VERSION 5.8 ;
BUSBITCHARS "[]" ;
DIVIDERCHAR "/" ;
UNITS
    DATABASE MICRONS 1000 ;
END UNITS

VIA ino_system_via1_2_1000_440_1_2_410_410
  VIARULE via1Array ;
  CUTSIZE 0.19 0.19 ;
  LAYERS Metal1 Via1 Metal2 ;
  CUTSPACING 0.22 0.22 ;
  ENCLOSURE 0.05 0.125 0.005 0.05 ;
  ROWCOL 1 2 ;
END ino_system_via1_2_1000_440_1_2_410_410

VIA ino_system_via2_3_1000_440_1_2_410_410
  VIARULE via2Array ;
  CUTSIZE 0.19 0.19 ;
  LAYERS Metal2 Via2 Metal3 ;
  CUTSPACING 0.22 0.22 ;
  ENCLOSURE 0.005 0.05 0.05 0.005 ;
  ROWCOL 1 2 ;
END ino_system_via2_3_1000_440_1_2_410_410

VIA ino_system_via3_4_1000_440_1_2_410_410
  VIARULE via3Array ;
  CUTSIZE 0.19 0.19 ;
  LAYERS Metal3 Via3 Metal4 ;
  CUTSPACING 0.22 0.22 ;
  ENCLOSURE 0.05 0.005 0.2 0.05 ;
  ROWCOL 1 2 ;
END ino_system_via3_4_1000_440_1_2_410_410

VIA ino_system_via4_5_1000_2000_1_1_840_840
  VIARULE viaTop1Array ;
  CUTSIZE 0.42 0.42 ;
  LAYERS Metal4 TopVia1 TopMetal1 ;
  CUTSPACING 0.42 0.42 ;
  ENCLOSURE 0.29 0.1 0.42 0.79 ;
END ino_system_via4_5_1000_2000_1_1_840_840

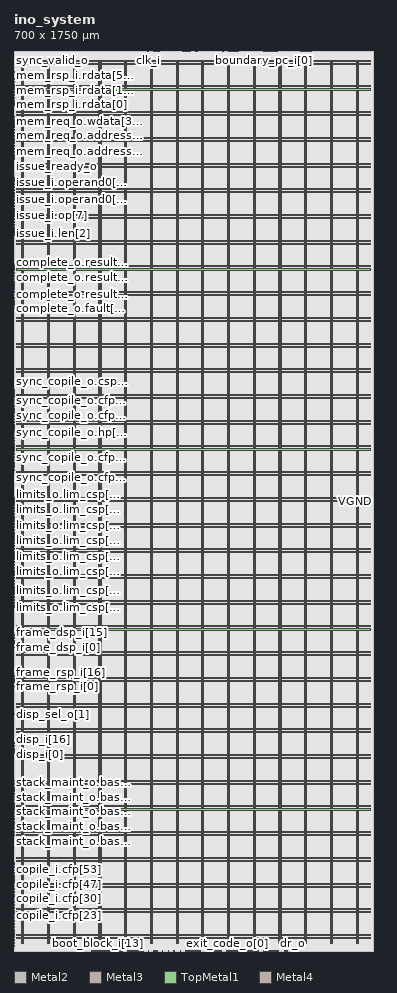
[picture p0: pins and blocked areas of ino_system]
MACRO ino_system
  FOREIGN ino_system 0 0 ;
  CLASS BLOCK ;
  SIZE 700 BY 1750 ;
  PIN boot_block_i[0]
    DIRECTION INPUT ;
    USE SIGNAL ;
    PORT
      LAYER Metal2 ;
        RECT  150.04 0 150.44 0.4 ;
    END
  END boot_block_i[0]
  PIN boot_block_i[10]
    DIRECTION INPUT ;
    USE SIGNAL ;
    PORT
      LAYER Metal2 ;
        RECT  159.64 0 160.04 0.4 ;
    END
  END boot_block_i[10]
  PIN boot_block_i[11]
    DIRECTION INPUT ;
    USE SIGNAL ;
    PORT
      LAYER Metal2 ;
        RECT  160.6 0 161 0.4 ;
    END
  END boot_block_i[11]
  PIN boot_block_i[12]
    DIRECTION INPUT ;
    USE SIGNAL ;
    PORT
      LAYER Metal2 ;
        RECT  161.56 0 161.96 0.4 ;
    END
  END boot_block_i[12]
  PIN boot_block_i[13]
    DIRECTION INPUT ;
    USE SIGNAL ;
    PORT
      LAYER Metal2 ;
        RECT  162.52 0 162.92 0.4 ;
    END
  END boot_block_i[13]
  PIN boot_block_i[14]
    DIRECTION INPUT ;
    USE SIGNAL ;
    PORT
      LAYER Metal2 ;
        RECT  163.48 0 163.88 0.4 ;
    END
  END boot_block_i[14]
  PIN boot_block_i[15]
    DIRECTION INPUT ;
    USE SIGNAL ;
    PORT
      LAYER Metal2 ;
        RECT  164.44 0 164.84 0.4 ;
    END
  END boot_block_i[15]
  PIN boot_block_i[16]
    DIRECTION INPUT ;
    USE SIGNAL ;
    PORT
      LAYER Metal2 ;
        RECT  165.4 0 165.8 0.4 ;
    END
  END boot_block_i[16]
  PIN boot_block_i[17]
    DIRECTION INPUT ;
    USE SIGNAL ;
    PORT
      LAYER Metal2 ;
        RECT  166.36 0 166.76 0.4 ;
    END
  END boot_block_i[17]
  PIN boot_block_i[18]
    DIRECTION INPUT ;
    USE SIGNAL ;
    PORT
      LAYER Metal2 ;
        RECT  167.32 0 167.72 0.4 ;
    END
  END boot_block_i[18]
  PIN boot_block_i[19]
    DIRECTION INPUT ;
    USE SIGNAL ;
    PORT
      LAYER Metal2 ;
        RECT  168.28 0 168.68 0.4 ;
    END
  END boot_block_i[19]
  PIN boot_block_i[1]
    DIRECTION INPUT ;
    USE SIGNAL ;
    PORT
      LAYER Metal2 ;
        RECT  151 0 151.4 0.4 ;
    END
  END boot_block_i[1]
  PIN boot_block_i[20]
    DIRECTION INPUT ;
    USE SIGNAL ;
    PORT
      LAYER Metal2 ;
        RECT  169.24 0 169.64 0.4 ;
    END
  END boot_block_i[20]
  PIN boot_block_i[21]
    DIRECTION INPUT ;
    USE SIGNAL ;
    PORT
      LAYER Metal2 ;
        RECT  170.2 0 170.6 0.4 ;
    END
  END boot_block_i[21]
  PIN boot_block_i[22]
    DIRECTION INPUT ;
    USE SIGNAL ;
    PORT
      LAYER Metal2 ;
        RECT  171.16 0 171.56 0.4 ;
    END
  END boot_block_i[22]
  PIN boot_block_i[23]
    DIRECTION INPUT ;
    USE SIGNAL ;
    PORT
      LAYER Metal2 ;
        RECT  172.12 0 172.52 0.4 ;
    END
  END boot_block_i[23]
  PIN boot_block_i[24]
    DIRECTION INPUT ;
    USE SIGNAL ;
    PORT
      LAYER Metal2 ;
        RECT  173.08 0 173.48 0.4 ;
    END
  END boot_block_i[24]
  PIN boot_block_i[25]
    DIRECTION INPUT ;
    USE SIGNAL ;
    PORT
      LAYER Metal2 ;
        RECT  174.04 0 174.44 0.4 ;
    END
  END boot_block_i[25]
  PIN boot_block_i[26]
    DIRECTION INPUT ;
    USE SIGNAL ;
    PORT
      LAYER Metal2 ;
        RECT  175 0 175.4 0.4 ;
    END
  END boot_block_i[26]
  PIN boot_block_i[27]
    DIRECTION INPUT ;
    USE SIGNAL ;
    PORT
      LAYER Metal2 ;
        RECT  175.96 0 176.36 0.4 ;
    END
  END boot_block_i[27]
  PIN boot_block_i[28]
    DIRECTION INPUT ;
    USE SIGNAL ;
    PORT
      LAYER Metal2 ;
        RECT  176.92 0 177.32 0.4 ;
    END
  END boot_block_i[28]
  PIN boot_block_i[29]
    DIRECTION INPUT ;
    USE SIGNAL ;
    PORT
      LAYER Metal2 ;
        RECT  177.88 0 178.28 0.4 ;
    END
  END boot_block_i[29]
  PIN boot_block_i[2]
    DIRECTION INPUT ;
    USE SIGNAL ;
    PORT
      LAYER Metal2 ;
        RECT  151.96 0 152.36 0.4 ;
    END
  END boot_block_i[2]
  PIN boot_block_i[30]
    DIRECTION INPUT ;
    USE SIGNAL ;
    PORT
      LAYER Metal2 ;
        RECT  178.84 0 179.24 0.4 ;
    END
  END boot_block_i[30]
  PIN boot_block_i[31]
    DIRECTION INPUT ;
    USE SIGNAL ;
    PORT
      LAYER Metal2 ;
        RECT  179.8 0 180.2 0.4 ;
    END
  END boot_block_i[31]
  PIN boot_block_i[32]
    DIRECTION INPUT ;
    USE SIGNAL ;
    PORT
      LAYER Metal2 ;
        RECT  180.76 0 181.16 0.4 ;
    END
  END boot_block_i[32]
  PIN boot_block_i[33]
    DIRECTION INPUT ;
    USE SIGNAL ;
    PORT
      LAYER Metal2 ;
        RECT  181.72 0 182.12 0.4 ;
    END
  END boot_block_i[33]
  PIN boot_block_i[34]
    DIRECTION INPUT ;
    USE SIGNAL ;
    PORT
      LAYER Metal2 ;
        RECT  182.68 0 183.08 0.4 ;
    END
  END boot_block_i[34]
  PIN boot_block_i[35]
    DIRECTION INPUT ;
    USE SIGNAL ;
    PORT
      LAYER Metal2 ;
        RECT  183.64 0 184.04 0.4 ;
    END
  END boot_block_i[35]
  PIN boot_block_i[36]
    DIRECTION INPUT ;
    USE SIGNAL ;
    PORT
      LAYER Metal2 ;
        RECT  184.6 0 185 0.4 ;
    END
  END boot_block_i[36]
  PIN boot_block_i[37]
    DIRECTION INPUT ;
    USE SIGNAL ;
    PORT
      LAYER Metal2 ;
        RECT  185.56 0 185.96 0.4 ;
    END
  END boot_block_i[37]
  PIN boot_block_i[38]
    DIRECTION INPUT ;
    USE SIGNAL ;
    PORT
      LAYER Metal2 ;
        RECT  186.52 0 186.92 0.4 ;
    END
  END boot_block_i[38]
  PIN boot_block_i[39]
    DIRECTION INPUT ;
    USE SIGNAL ;
    PORT
      LAYER Metal2 ;
        RECT  187.48 0 187.88 0.4 ;
    END
  END boot_block_i[39]
  PIN boot_block_i[3]
    DIRECTION INPUT ;
    USE SIGNAL ;
    PORT
      LAYER Metal2 ;
        RECT  152.92 0 153.32 0.4 ;
    END
  END boot_block_i[3]
  PIN boot_block_i[40]
    DIRECTION INPUT ;
    USE SIGNAL ;
    PORT
      LAYER Metal2 ;
        RECT  188.44 0 188.84 0.4 ;
    END
  END boot_block_i[40]
  PIN boot_block_i[41]
    DIRECTION INPUT ;
    USE SIGNAL ;
    PORT
      LAYER Metal2 ;
        RECT  189.4 0 189.8 0.4 ;
    END
  END boot_block_i[41]
  PIN boot_block_i[42]
    DIRECTION INPUT ;
    USE SIGNAL ;
    PORT
      LAYER Metal2 ;
        RECT  190.36 0 190.76 0.4 ;
    END
  END boot_block_i[42]
  PIN boot_block_i[43]
    DIRECTION INPUT ;
    USE SIGNAL ;
    PORT
      LAYER Metal2 ;
        RECT  191.32 0 191.72 0.4 ;
    END
  END boot_block_i[43]
  PIN boot_block_i[44]
    DIRECTION INPUT ;
    USE SIGNAL ;
    PORT
      LAYER Metal2 ;
        RECT  192.28 0 192.68 0.4 ;
    END
  END boot_block_i[44]
  PIN boot_block_i[45]
    DIRECTION INPUT ;
    USE SIGNAL ;
    PORT
      LAYER Metal2 ;
        RECT  193.24 0 193.64 0.4 ;
    END
  END boot_block_i[45]
  PIN boot_block_i[46]
    DIRECTION INPUT ;
    USE SIGNAL ;
    PORT
      LAYER Metal2 ;
        RECT  194.2 0 194.6 0.4 ;
    END
  END boot_block_i[46]
  PIN boot_block_i[47]
    DIRECTION INPUT ;
    USE SIGNAL ;
    PORT
      LAYER Metal2 ;
        RECT  195.16 0 195.56 0.4 ;
    END
  END boot_block_i[47]
  PIN boot_block_i[48]
    DIRECTION INPUT ;
    USE SIGNAL ;
    PORT
      LAYER Metal2 ;
        RECT  196.12 0 196.52 0.4 ;
    END
  END boot_block_i[48]
  PIN boot_block_i[49]
    DIRECTION INPUT ;
    USE SIGNAL ;
    PORT
      LAYER Metal2 ;
        RECT  197.08 0 197.48 0.4 ;
    END
  END boot_block_i[49]
  PIN boot_block_i[4]
    DIRECTION INPUT ;
    USE SIGNAL ;
    PORT
      LAYER Metal2 ;
        RECT  153.88 0 154.28 0.4 ;
    END
  END boot_block_i[4]
  PIN boot_block_i[50]
    DIRECTION INPUT ;
    USE SIGNAL ;
    PORT
      LAYER Metal2 ;
        RECT  198.04 0 198.44 0.4 ;
    END
  END boot_block_i[50]
  PIN boot_block_i[51]
    DIRECTION INPUT ;
    USE SIGNAL ;
    PORT
      LAYER Metal2 ;
        RECT  199 0 199.4 0.4 ;
    END
  END boot_block_i[51]
  PIN boot_block_i[52]
    DIRECTION INPUT ;
    USE SIGNAL ;
    PORT
      LAYER Metal2 ;
        RECT  199.96 0 200.36 0.4 ;
    END
  END boot_block_i[52]
  PIN boot_block_i[53]
    DIRECTION INPUT ;
    USE SIGNAL ;
    PORT
      LAYER Metal2 ;
        RECT  200.92 0 201.32 0.4 ;
    END
  END boot_block_i[53]
  PIN boot_block_i[54]
    DIRECTION INPUT ;
    USE SIGNAL ;
    PORT
      LAYER Metal2 ;
        RECT  201.88 0 202.28 0.4 ;
    END
  END boot_block_i[54]
  PIN boot_block_i[55]
    DIRECTION INPUT ;
    USE SIGNAL ;
    PORT
      LAYER Metal2 ;
        RECT  202.84 0 203.24 0.4 ;
    END
  END boot_block_i[55]
  PIN boot_block_i[56]
    DIRECTION INPUT ;
    USE SIGNAL ;
    PORT
      LAYER Metal2 ;
        RECT  203.8 0 204.2 0.4 ;
    END
  END boot_block_i[56]
  PIN boot_block_i[57]
    DIRECTION INPUT ;
    USE SIGNAL ;
    PORT
      LAYER Metal2 ;
        RECT  204.76 0 205.16 0.4 ;
    END
  END boot_block_i[57]
  PIN boot_block_i[58]
    DIRECTION INPUT ;
    USE SIGNAL ;
    PORT
      LAYER Metal2 ;
        RECT  205.72 0 206.12 0.4 ;
    END
  END boot_block_i[58]
  PIN boot_block_i[59]
    DIRECTION INPUT ;
    USE SIGNAL ;
    PORT
      LAYER Metal2 ;
        RECT  206.68 0 207.08 0.4 ;
    END
  END boot_block_i[59]
  PIN boot_block_i[5]
    DIRECTION INPUT ;
    USE SIGNAL ;
    PORT
      LAYER Metal2 ;
        RECT  154.84 0 155.24 0.4 ;
    END
  END boot_block_i[5]
  PIN boot_block_i[60]
    DIRECTION INPUT ;
    USE SIGNAL ;
    PORT
      LAYER Metal2 ;
        RECT  207.64 0 208.04 0.4 ;
    END
  END boot_block_i[60]
  PIN boot_block_i[61]
    DIRECTION INPUT ;
    USE SIGNAL ;
    PORT
      LAYER Metal2 ;
        RECT  208.6 0 209 0.4 ;
    END
  END boot_block_i[61]
  PIN boot_block_i[62]
    DIRECTION INPUT ;
    USE SIGNAL ;
    PORT
      LAYER Metal2 ;
        RECT  209.56 0 209.96 0.4 ;
    END
  END boot_block_i[62]
  PIN boot_block_i[63]
    DIRECTION INPUT ;
    USE SIGNAL ;
    PORT
      LAYER Metal2 ;
        RECT  210.52 0 210.92 0.4 ;
    END
  END boot_block_i[63]
  PIN boot_block_i[6]
    DIRECTION INPUT ;
    USE SIGNAL ;
    PORT
      LAYER Metal2 ;
        RECT  155.8 0 156.2 0.4 ;
    END
  END boot_block_i[6]
  PIN boot_block_i[7]
    DIRECTION INPUT ;
    USE SIGNAL ;
    PORT
      LAYER Metal2 ;
        RECT  156.76 0 157.16 0.4 ;
    END
  END boot_block_i[7]
  PIN boot_block_i[8]
    DIRECTION INPUT ;
    USE SIGNAL ;
    PORT
      LAYER Metal2 ;
        RECT  157.72 0 158.12 0.4 ;
    END
  END boot_block_i[8]
  PIN boot_block_i[9]
    DIRECTION INPUT ;
    USE SIGNAL ;
    PORT
      LAYER Metal2 ;
        RECT  158.68 0 159.08 0.4 ;
    END
  END boot_block_i[9]
  PIN boundary_pc_i[0]
    DIRECTION INPUT ;
    USE SIGNAL ;
    PORT
      LAYER Metal2 ;
        RECT  486.04 1749.6 486.44 1750 ;
    END
  END boundary_pc_i[0]
  PIN boundary_pc_i[10]
    DIRECTION INPUT ;
    USE SIGNAL ;
    PORT
      LAYER Metal2 ;
        RECT  495.64 1749.6 496.04 1750 ;
    END
  END boundary_pc_i[10]
  PIN boundary_pc_i[11]
    DIRECTION INPUT ;
    USE SIGNAL ;
    PORT
      LAYER Metal2 ;
        RECT  496.6 1749.6 497 1750 ;
    END
  END boundary_pc_i[11]
  PIN boundary_pc_i[12]
    DIRECTION INPUT ;
    USE SIGNAL ;
    PORT
      LAYER Metal2 ;
        RECT  497.56 1749.6 497.96 1750 ;
    END
  END boundary_pc_i[12]
  PIN boundary_pc_i[13]
    DIRECTION INPUT ;
    USE SIGNAL ;
    PORT
      LAYER Metal2 ;
        RECT  498.52 1749.6 498.92 1750 ;
    END
  END boundary_pc_i[13]
  PIN boundary_pc_i[14]
    DIRECTION INPUT ;
    USE SIGNAL ;
    PORT
      LAYER Metal2 ;
        RECT  499.48 1749.6 499.88 1750 ;
    END
  END boundary_pc_i[14]
  PIN boundary_pc_i[15]
    DIRECTION INPUT ;
    USE SIGNAL ;
    PORT
      LAYER Metal2 ;
        RECT  500.44 1749.6 500.84 1750 ;
    END
  END boundary_pc_i[15]
  PIN boundary_pc_i[16]
    DIRECTION INPUT ;
    USE SIGNAL ;
    PORT
      LAYER Metal2 ;
        RECT  501.4 1749.6 501.8 1750 ;
    END
  END boundary_pc_i[16]
  PIN boundary_pc_i[17]
    DIRECTION INPUT ;
    USE SIGNAL ;
    PORT
      LAYER Metal2 ;
        RECT  502.36 1749.6 502.76 1750 ;
    END
  END boundary_pc_i[17]
  PIN boundary_pc_i[18]
    DIRECTION INPUT ;
    USE SIGNAL ;
    PORT
      LAYER Metal2 ;
        RECT  503.32 1749.6 503.72 1750 ;
    END
  END boundary_pc_i[18]
  PIN boundary_pc_i[19]
    DIRECTION INPUT ;
    USE SIGNAL ;
    PORT
      LAYER Metal2 ;
        RECT  504.28 1749.6 504.68 1750 ;
    END
  END boundary_pc_i[19]
  PIN boundary_pc_i[1]
    DIRECTION INPUT ;
    USE SIGNAL ;
    PORT
      LAYER Metal2 ;
        RECT  487 1749.6 487.4 1750 ;
    END
  END boundary_pc_i[1]
  PIN boundary_pc_i[20]
    DIRECTION INPUT ;
    USE SIGNAL ;
    PORT
      LAYER Metal2 ;
        RECT  505.24 1749.6 505.64 1750 ;
    END
  END boundary_pc_i[20]
  PIN boundary_pc_i[21]
    DIRECTION INPUT ;
    USE SIGNAL ;
    PORT
      LAYER Metal2 ;
        RECT  506.2 1749.6 506.6 1750 ;
    END
  END boundary_pc_i[21]
  PIN boundary_pc_i[22]
    DIRECTION INPUT ;
    USE SIGNAL ;
    PORT
      LAYER Metal2 ;
        RECT  507.16 1749.6 507.56 1750 ;
    END
  END boundary_pc_i[22]
  PIN boundary_pc_i[23]
    DIRECTION INPUT ;
    USE SIGNAL ;
    PORT
      LAYER Metal2 ;
        RECT  508.12 1749.6 508.52 1750 ;
    END
  END boundary_pc_i[23]
  PIN boundary_pc_i[24]
    DIRECTION INPUT ;
    USE SIGNAL ;
    PORT
      LAYER Metal2 ;
        RECT  509.08 1749.6 509.48 1750 ;
    END
  END boundary_pc_i[24]
  PIN boundary_pc_i[25]
    DIRECTION INPUT ;
    USE SIGNAL ;
    PORT
      LAYER Metal2 ;
        RECT  510.04 1749.6 510.44 1750 ;
    END
  END boundary_pc_i[25]
  PIN boundary_pc_i[26]
    DIRECTION INPUT ;
    USE SIGNAL ;
    PORT
      LAYER Metal2 ;
        RECT  511 1749.6 511.4 1750 ;
    END
  END boundary_pc_i[26]
  PIN boundary_pc_i[27]
    DIRECTION INPUT ;
    USE SIGNAL ;
    PORT
      LAYER Metal2 ;
        RECT  511.96 1749.6 512.36 1750 ;
    END
  END boundary_pc_i[27]
  PIN boundary_pc_i[28]
    DIRECTION INPUT ;
    USE SIGNAL ;
    PORT
      LAYER Metal2 ;
        RECT  512.92 1749.6 513.32 1750 ;
    END
  END boundary_pc_i[28]
  PIN boundary_pc_i[29]
    DIRECTION INPUT ;
    USE SIGNAL ;
    PORT
      LAYER Metal2 ;
        RECT  513.88 1749.6 514.28 1750 ;
    END
  END boundary_pc_i[29]
  PIN boundary_pc_i[2]
    DIRECTION INPUT ;
    USE SIGNAL ;
    PORT
      LAYER Metal2 ;
        RECT  487.96 1749.6 488.36 1750 ;
    END
  END boundary_pc_i[2]
  PIN boundary_pc_i[30]
    DIRECTION INPUT ;
    USE SIGNAL ;
    PORT
      LAYER Metal2 ;
        RECT  514.84 1749.6 515.24 1750 ;
    END
  END boundary_pc_i[30]
  PIN boundary_pc_i[31]
    DIRECTION INPUT ;
    USE SIGNAL ;
    PORT
      LAYER Metal2 ;
        RECT  515.8 1749.6 516.2 1750 ;
    END
  END boundary_pc_i[31]
  PIN boundary_pc_i[3]
    DIRECTION INPUT ;
    USE SIGNAL ;
    PORT
      LAYER Metal2 ;
        RECT  488.92 1749.6 489.32 1750 ;
    END
  END boundary_pc_i[3]
  PIN boundary_pc_i[4]
    DIRECTION INPUT ;
    USE SIGNAL ;
    PORT
      LAYER Metal2 ;
        RECT  489.88 1749.6 490.28 1750 ;
    END
  END boundary_pc_i[4]
  PIN boundary_pc_i[5]
    DIRECTION INPUT ;
    USE SIGNAL ;
    PORT
      LAYER Metal2 ;
        RECT  490.84 1749.6 491.24 1750 ;
    END
  END boundary_pc_i[5]
  PIN boundary_pc_i[6]
    DIRECTION INPUT ;
    USE SIGNAL ;
    PORT
      LAYER Metal2 ;
        RECT  491.8 1749.6 492.2 1750 ;
    END
  END boundary_pc_i[6]
  PIN boundary_pc_i[7]
    DIRECTION INPUT ;
    USE SIGNAL ;
    PORT
      LAYER Metal2 ;
        RECT  492.76 1749.6 493.16 1750 ;
    END
  END boundary_pc_i[7]
  PIN boundary_pc_i[8]
    DIRECTION INPUT ;
    USE SIGNAL ;
    PORT
      LAYER Metal2 ;
        RECT  493.72 1749.6 494.12 1750 ;
    END
  END boundary_pc_i[8]
  PIN boundary_pc_i[9]
    DIRECTION INPUT ;
    USE SIGNAL ;
    PORT
      LAYER Metal2 ;
        RECT  494.68 1749.6 495.08 1750 ;
    END
  END boundary_pc_i[9]
  PIN boundary_valid_i
    DIRECTION INPUT ;
    USE SIGNAL ;
    PORT
      LAYER Metal2 ;
        RECT  475.48 1749.6 475.88 1750 ;
    END
  END boundary_valid_i
  PIN clk_i
    DIRECTION INPUT ;
    USE SIGNAL ;
    PORT
      LAYER Metal2 ;
        RECT  260.44 1749.6 260.84 1750 ;
    END
  END clk_i
  PIN complete_o.fault[0]
    DIRECTION OUTPUT ;
    USE SIGNAL ;
    PORT
      LAYER Metal3 ;
        RECT  0 1248.46 0.4 1248.86 ;
    END
  END complete_o.fault[0]
  PIN complete_o.fault[1]
    DIRECTION OUTPUT ;
    USE SIGNAL ;
    PORT
      LAYER Metal3 ;
        RECT  0 1250.98 0.4 1251.38 ;
    END
  END complete_o.fault[1]
  PIN complete_o.fault[2]
    DIRECTION OUTPUT ;
    USE SIGNAL ;
    PORT
      LAYER Metal3 ;
        RECT  0 1253.5 0.4 1253.9 ;
    END
  END complete_o.fault[2]
  PIN complete_o.fault[3]
    DIRECTION OUTPUT ;
    USE SIGNAL ;
    PORT
      LAYER Metal3 ;
        RECT  0 1256.02 0.4 1256.42 ;
    END
  END complete_o.fault[3]
  PIN complete_o.fault[4]
    DIRECTION OUTPUT ;
    USE SIGNAL ;
    PORT
      LAYER Metal3 ;
        RECT  0 1258.54 0.4 1258.94 ;
    END
  END complete_o.fault[4]
  PIN complete_o.fault[5]
    DIRECTION OUTPUT ;
    USE SIGNAL ;
    PORT
      LAYER Metal3 ;
        RECT  0 1261.06 0.4 1261.46 ;
    END
  END complete_o.fault[5]
  PIN complete_o.fault[6]
    DIRECTION OUTPUT ;
    USE SIGNAL ;
    PORT
      LAYER Metal3 ;
        RECT  0 1263.58 0.4 1263.98 ;
    END
  END complete_o.fault[6]
  PIN complete_o.fault[7]
    DIRECTION OUTPUT ;
    USE SIGNAL ;
    PORT
      LAYER Metal3 ;
        RECT  0 1266.1 0.4 1266.5 ;
    END
  END complete_o.fault[7]
  PIN complete_o.fault[8]
    DIRECTION OUTPUT ;
    USE SIGNAL ;
    PORT
      LAYER Metal3 ;
        RECT  0 1268.62 0.4 1269.02 ;
    END
  END complete_o.fault[8]
  PIN complete_o.result[0]
    DIRECTION OUTPUT ;
    USE SIGNAL ;
    PORT
      LAYER Metal3 ;
        RECT  0 1249.3 0.4 1249.7 ;
    END
  END complete_o.result[0]
  PIN complete_o.result[10]
    DIRECTION OUTPUT ;
    USE SIGNAL ;
    PORT
      LAYER Metal3 ;
        RECT  0 1272.82 0.4 1273.22 ;
    END
  END complete_o.result[10]
  PIN complete_o.result[11]
    DIRECTION OUTPUT ;
    USE SIGNAL ;
    PORT
      LAYER Metal3 ;
        RECT  0 1274.5 0.4 1274.9 ;
    END
  END complete_o.result[11]
  PIN complete_o.result[12]
    DIRECTION OUTPUT ;
    USE SIGNAL ;
    PORT
      LAYER Metal3 ;
        RECT  0 1276.18 0.4 1276.58 ;
    END
  END complete_o.result[12]
  PIN complete_o.result[13]
    DIRECTION OUTPUT ;
    USE SIGNAL ;
    PORT
      LAYER Metal3 ;
        RECT  0 1277.86 0.4 1278.26 ;
    END
  END complete_o.result[13]
  PIN complete_o.result[14]
    DIRECTION OUTPUT ;
    USE SIGNAL ;
    PORT
      LAYER Metal3 ;
        RECT  0 1279.54 0.4 1279.94 ;
    END
  END complete_o.result[14]
  PIN complete_o.result[15]
    DIRECTION OUTPUT ;
    USE SIGNAL ;
    PORT
      LAYER Metal3 ;
        RECT  0 1281.22 0.4 1281.62 ;
    END
  END complete_o.result[15]
  PIN complete_o.result[16]
    DIRECTION OUTPUT ;
    USE SIGNAL ;
    PORT
      LAYER Metal3 ;
        RECT  0 1282.9 0.4 1283.3 ;
    END
  END complete_o.result[16]
  PIN complete_o.result[17]
    DIRECTION OUTPUT ;
    USE SIGNAL ;
    PORT
      LAYER Metal3 ;
        RECT  0 1284.58 0.4 1284.98 ;
    END
  END complete_o.result[17]
  PIN complete_o.result[18]
    DIRECTION OUTPUT ;
    USE SIGNAL ;
    PORT
      LAYER Metal3 ;
        RECT  0 1286.26 0.4 1286.66 ;
    END
  END complete_o.result[18]
  PIN complete_o.result[19]
    DIRECTION OUTPUT ;
    USE SIGNAL ;
    PORT
      LAYER Metal3 ;
        RECT  0 1287.94 0.4 1288.34 ;
    END
  END complete_o.result[19]
  PIN complete_o.result[1]
    DIRECTION OUTPUT ;
    USE SIGNAL ;
    PORT
      LAYER Metal3 ;
        RECT  0 1251.82 0.4 1252.22 ;
    END
  END complete_o.result[1]
  PIN complete_o.result[20]
    DIRECTION OUTPUT ;
    USE SIGNAL ;
    PORT
      LAYER Metal3 ;
        RECT  0 1289.62 0.4 1290.02 ;
    END
  END complete_o.result[20]
  PIN complete_o.result[21]
    DIRECTION OUTPUT ;
    USE SIGNAL ;
    PORT
      LAYER Metal3 ;
        RECT  0 1291.3 0.4 1291.7 ;
    END
  END complete_o.result[21]
  PIN complete_o.result[22]
    DIRECTION OUTPUT ;
    USE SIGNAL ;
    PORT
      LAYER Metal3 ;
        RECT  0 1292.98 0.4 1293.38 ;
    END
  END complete_o.result[22]
  PIN complete_o.result[23]
    DIRECTION OUTPUT ;
    USE SIGNAL ;
    PORT
      LAYER Metal3 ;
        RECT  0 1294.66 0.4 1295.06 ;
    END
  END complete_o.result[23]
  PIN complete_o.result[24]
    DIRECTION OUTPUT ;
    USE SIGNAL ;
    PORT
      LAYER Metal3 ;
        RECT  0 1296.34 0.4 1296.74 ;
    END
  END complete_o.result[24]
  PIN complete_o.result[25]
    DIRECTION OUTPUT ;
    USE SIGNAL ;
    PORT
      LAYER Metal3 ;
        RECT  0 1298.02 0.4 1298.42 ;
    END
  END complete_o.result[25]
  PIN complete_o.result[26]
    DIRECTION OUTPUT ;
    USE SIGNAL ;
    PORT
      LAYER Metal3 ;
        RECT  0 1299.7 0.4 1300.1 ;
    END
  END complete_o.result[26]
  PIN complete_o.result[27]
    DIRECTION OUTPUT ;
    USE SIGNAL ;
    PORT
      LAYER Metal3 ;
        RECT  0 1301.38 0.4 1301.78 ;
    END
  END complete_o.result[27]
  PIN complete_o.result[28]
    DIRECTION OUTPUT ;
    USE SIGNAL ;
    PORT
      LAYER Metal3 ;
        RECT  0 1303.06 0.4 1303.46 ;
    END
  END complete_o.result[28]
  PIN complete_o.result[29]
    DIRECTION OUTPUT ;
    USE SIGNAL ;
    PORT
      LAYER Metal3 ;
        RECT  0 1304.74 0.4 1305.14 ;
    END
  END complete_o.result[29]
  PIN complete_o.result[2]
    DIRECTION OUTPUT ;
    USE SIGNAL ;
    PORT
      LAYER Metal3 ;
        RECT  0 1254.34 0.4 1254.74 ;
    END
  END complete_o.result[2]
  PIN complete_o.result[30]
    DIRECTION OUTPUT ;
    USE SIGNAL ;
    PORT
      LAYER Metal3 ;
        RECT  0 1306.42 0.4 1306.82 ;
    END
  END complete_o.result[30]
  PIN complete_o.result[31]
    DIRECTION OUTPUT ;
    USE SIGNAL ;
    PORT
      LAYER Metal3 ;
        RECT  0 1308.1 0.4 1308.5 ;
    END
  END complete_o.result[31]
  PIN complete_o.result[32]
    DIRECTION OUTPUT ;
    USE SIGNAL ;
    PORT
      LAYER Metal3 ;
        RECT  0 1309.78 0.4 1310.18 ;
    END
  END complete_o.result[32]
  PIN complete_o.result[33]
    DIRECTION OUTPUT ;
    USE SIGNAL ;
    PORT
      LAYER Metal3 ;
        RECT  0 1310.62 0.4 1311.02 ;
    END
  END complete_o.result[33]
  PIN complete_o.result[34]
    DIRECTION OUTPUT ;
    USE SIGNAL ;
    PORT
      LAYER Metal3 ;
        RECT  0 1311.46 0.4 1311.86 ;
    END
  END complete_o.result[34]
  PIN complete_o.result[35]
    DIRECTION OUTPUT ;
    USE SIGNAL ;
    PORT
      LAYER Metal3 ;
        RECT  0 1312.3 0.4 1312.7 ;
    END
  END complete_o.result[35]
  PIN complete_o.result[36]
    DIRECTION OUTPUT ;
    USE SIGNAL ;
    PORT
      LAYER Metal3 ;
        RECT  0 1313.14 0.4 1313.54 ;
    END
  END complete_o.result[36]
  PIN complete_o.result[37]
    DIRECTION OUTPUT ;
    USE SIGNAL ;
    PORT
      LAYER Metal3 ;
        RECT  0 1313.98 0.4 1314.38 ;
    END
  END complete_o.result[37]
  PIN complete_o.result[38]
    DIRECTION OUTPUT ;
    USE SIGNAL ;
    PORT
      LAYER Metal3 ;
        RECT  0 1314.82 0.4 1315.22 ;
    END
  END complete_o.result[38]
  PIN complete_o.result[39]
    DIRECTION OUTPUT ;
    USE SIGNAL ;
    PORT
      LAYER Metal3 ;
        RECT  0 1315.66 0.4 1316.06 ;
    END
  END complete_o.result[39]
  PIN complete_o.result[3]
    DIRECTION OUTPUT ;
    USE SIGNAL ;
    PORT
      LAYER Metal3 ;
        RECT  0 1256.86 0.4 1257.26 ;
    END
  END complete_o.result[3]
  PIN complete_o.result[40]
    DIRECTION OUTPUT ;
    USE SIGNAL ;
    PORT
      LAYER Metal3 ;
        RECT  0 1316.5 0.4 1316.9 ;
    END
  END complete_o.result[40]
  PIN complete_o.result[41]
    DIRECTION OUTPUT ;
    USE SIGNAL ;
    PORT
      LAYER Metal3 ;
        RECT  0 1317.34 0.4 1317.74 ;
    END
  END complete_o.result[41]
  PIN complete_o.result[42]
    DIRECTION OUTPUT ;
    USE SIGNAL ;
    PORT
      LAYER Metal3 ;
        RECT  0 1318.18 0.4 1318.58 ;
    END
  END complete_o.result[42]
  PIN complete_o.result[43]
    DIRECTION OUTPUT ;
    USE SIGNAL ;
    PORT
      LAYER Metal3 ;
        RECT  0 1319.02 0.4 1319.42 ;
    END
  END complete_o.result[43]
  PIN complete_o.result[44]
    DIRECTION OUTPUT ;
    USE SIGNAL ;
    PORT
      LAYER Metal3 ;
        RECT  0 1319.86 0.4 1320.26 ;
    END
  END complete_o.result[44]
  PIN complete_o.result[45]
    DIRECTION OUTPUT ;
    USE SIGNAL ;
    PORT
      LAYER Metal3 ;
        RECT  0 1320.7 0.4 1321.1 ;
    END
  END complete_o.result[45]
  PIN complete_o.result[46]
    DIRECTION OUTPUT ;
    USE SIGNAL ;
    PORT
      LAYER Metal3 ;
        RECT  0 1321.54 0.4 1321.94 ;
    END
  END complete_o.result[46]
  PIN complete_o.result[47]
    DIRECTION OUTPUT ;
    USE SIGNAL ;
    PORT
      LAYER Metal3 ;
        RECT  0 1322.38 0.4 1322.78 ;
    END
  END complete_o.result[47]
  PIN complete_o.result[48]
    DIRECTION OUTPUT ;
    USE SIGNAL ;
    PORT
      LAYER Metal3 ;
        RECT  0 1323.22 0.4 1323.62 ;
    END
  END complete_o.result[48]
  PIN complete_o.result[49]
    DIRECTION OUTPUT ;
    USE SIGNAL ;
    PORT
      LAYER Metal3 ;
        RECT  0 1324.06 0.4 1324.46 ;
    END
  END complete_o.result[49]
  PIN complete_o.result[4]
    DIRECTION OUTPUT ;
    USE SIGNAL ;
    PORT
      LAYER Metal3 ;
        RECT  0 1259.38 0.4 1259.78 ;
    END
  END complete_o.result[4]
  PIN complete_o.result[50]
    DIRECTION OUTPUT ;
    USE SIGNAL ;
    PORT
      LAYER Metal3 ;
        RECT  0 1324.9 0.4 1325.3 ;
    END
  END complete_o.result[50]
  PIN complete_o.result[51]
    DIRECTION OUTPUT ;
    USE SIGNAL ;
    PORT
      LAYER Metal3 ;
        RECT  0 1325.74 0.4 1326.14 ;
    END
  END complete_o.result[51]
  PIN complete_o.result[52]
    DIRECTION OUTPUT ;
    USE SIGNAL ;
    PORT
      LAYER Metal3 ;
        RECT  0 1326.58 0.4 1326.98 ;
    END
  END complete_o.result[52]
  PIN complete_o.result[53]
    DIRECTION OUTPUT ;
    USE SIGNAL ;
    PORT
      LAYER Metal3 ;
        RECT  0 1327.42 0.4 1327.82 ;
    END
  END complete_o.result[53]
  PIN complete_o.result[54]
    DIRECTION OUTPUT ;
    USE SIGNAL ;
    PORT
      LAYER Metal3 ;
        RECT  0 1328.26 0.4 1328.66 ;
    END
  END complete_o.result[54]
  PIN complete_o.result[55]
    DIRECTION OUTPUT ;
    USE SIGNAL ;
    PORT
      LAYER Metal3 ;
        RECT  0 1329.1 0.4 1329.5 ;
    END
  END complete_o.result[55]
  PIN complete_o.result[56]
    DIRECTION OUTPUT ;
    USE SIGNAL ;
    PORT
      LAYER Metal3 ;
        RECT  0 1329.94 0.4 1330.34 ;
    END
  END complete_o.result[56]
  PIN complete_o.result[57]
    DIRECTION OUTPUT ;
    USE SIGNAL ;
    PORT
      LAYER Metal3 ;
        RECT  0 1330.78 0.4 1331.18 ;
    END
  END complete_o.result[57]
  PIN complete_o.result[58]
    DIRECTION OUTPUT ;
    USE SIGNAL ;
    PORT
      LAYER Metal3 ;
        RECT  0 1331.62 0.4 1332.02 ;
    END
  END complete_o.result[58]
  PIN complete_o.result[59]
    DIRECTION OUTPUT ;
    USE SIGNAL ;
    PORT
      LAYER Metal3 ;
        RECT  0 1332.46 0.4 1332.86 ;
    END
  END complete_o.result[59]
  PIN complete_o.result[5]
    DIRECTION OUTPUT ;
    USE SIGNAL ;
    PORT
      LAYER Metal3 ;
        RECT  0 1261.9 0.4 1262.3 ;
    END
  END complete_o.result[5]
  PIN complete_o.result[60]
    DIRECTION OUTPUT ;
    USE SIGNAL ;
    PORT
      LAYER Metal3 ;
        RECT  0 1333.3 0.4 1333.7 ;
    END
  END complete_o.result[60]
  PIN complete_o.result[61]
    DIRECTION OUTPUT ;
    USE SIGNAL ;
    PORT
      LAYER Metal3 ;
        RECT  0 1334.14 0.4 1334.54 ;
    END
  END complete_o.result[61]
  PIN complete_o.result[62]
    DIRECTION OUTPUT ;
    USE SIGNAL ;
    PORT
      LAYER Metal3 ;
        RECT  0 1334.98 0.4 1335.38 ;
    END
  END complete_o.result[62]
  PIN complete_o.result[63]
    DIRECTION OUTPUT ;
    USE SIGNAL ;
    PORT
      LAYER Metal3 ;
        RECT  0 1335.82 0.4 1336.22 ;
    END
  END complete_o.result[63]
  PIN complete_o.result[6]
    DIRECTION OUTPUT ;
    USE SIGNAL ;
    PORT
      LAYER Metal3 ;
        RECT  0 1264.42 0.4 1264.82 ;
    END
  END complete_o.result[6]
  PIN complete_o.result[7]
    DIRECTION OUTPUT ;
    USE SIGNAL ;
    PORT
      LAYER Metal3 ;
        RECT  0 1266.94 0.4 1267.34 ;
    END
  END complete_o.result[7]
  PIN complete_o.result[8]
    DIRECTION OUTPUT ;
    USE SIGNAL ;
    PORT
      LAYER Metal3 ;
        RECT  0 1269.46 0.4 1269.86 ;
    END
  END complete_o.result[8]
  PIN complete_o.result[9]
    DIRECTION OUTPUT ;
    USE SIGNAL ;
    PORT
      LAYER Metal3 ;
        RECT  0 1271.14 0.4 1271.54 ;
    END
  END complete_o.result[9]
  PIN complete_o.result_valid
    DIRECTION OUTPUT ;
    USE SIGNAL ;
    PORT
      LAYER Metal3 ;
        RECT  0 1245.94 0.4 1246.34 ;
    END
  END complete_o.result_valid
  PIN complete_o.taken
    DIRECTION OUTPUT ;
    USE SIGNAL ;
    PORT
      LAYER Metal3 ;
        RECT  0 1246.78 0.4 1247.18 ;
    END
  END complete_o.taken
  PIN complete_o.target[0]
    DIRECTION OUTPUT ;
    USE SIGNAL ;
    PORT
      LAYER Metal3 ;
        RECT  0 1250.14 0.4 1250.54 ;
    END
  END complete_o.target[0]
  PIN complete_o.target[10]
    DIRECTION OUTPUT ;
    USE SIGNAL ;
    PORT
      LAYER Metal3 ;
        RECT  0 1273.66 0.4 1274.06 ;
    END
  END complete_o.target[10]
  PIN complete_o.target[11]
    DIRECTION OUTPUT ;
    USE SIGNAL ;
    PORT
      LAYER Metal3 ;
        RECT  0 1275.34 0.4 1275.74 ;
    END
  END complete_o.target[11]
  PIN complete_o.target[12]
    DIRECTION OUTPUT ;
    USE SIGNAL ;
    PORT
      LAYER Metal3 ;
        RECT  0 1277.02 0.4 1277.42 ;
    END
  END complete_o.target[12]
  PIN complete_o.target[13]
    DIRECTION OUTPUT ;
    USE SIGNAL ;
    PORT
      LAYER Metal3 ;
        RECT  0 1278.7 0.4 1279.1 ;
    END
  END complete_o.target[13]
  PIN complete_o.target[14]
    DIRECTION OUTPUT ;
    USE SIGNAL ;
    PORT
      LAYER Metal3 ;
        RECT  0 1280.38 0.4 1280.78 ;
    END
  END complete_o.target[14]
  PIN complete_o.target[15]
    DIRECTION OUTPUT ;
    USE SIGNAL ;
    PORT
      LAYER Metal3 ;
        RECT  0 1282.06 0.4 1282.46 ;
    END
  END complete_o.target[15]
  PIN complete_o.target[16]
    DIRECTION OUTPUT ;
    USE SIGNAL ;
    PORT
      LAYER Metal3 ;
        RECT  0 1283.74 0.4 1284.14 ;
    END
  END complete_o.target[16]
  PIN complete_o.target[17]
    DIRECTION OUTPUT ;
    USE SIGNAL ;
    PORT
      LAYER Metal3 ;
        RECT  0 1285.42 0.4 1285.82 ;
    END
  END complete_o.target[17]
  PIN complete_o.target[18]
    DIRECTION OUTPUT ;
    USE SIGNAL ;
    PORT
      LAYER Metal3 ;
        RECT  0 1287.1 0.4 1287.5 ;
    END
  END complete_o.target[18]
  PIN complete_o.target[19]
    DIRECTION OUTPUT ;
    USE SIGNAL ;
    PORT
      LAYER Metal3 ;
        RECT  0 1288.78 0.4 1289.18 ;
    END
  END complete_o.target[19]
  PIN complete_o.target[1]
    DIRECTION OUTPUT ;
    USE SIGNAL ;
    PORT
      LAYER Metal3 ;
        RECT  0 1252.66 0.4 1253.06 ;
    END
  END complete_o.target[1]
  PIN complete_o.target[20]
    DIRECTION OUTPUT ;
    USE SIGNAL ;
    PORT
      LAYER Metal3 ;
        RECT  0 1290.46 0.4 1290.86 ;
    END
  END complete_o.target[20]
  PIN complete_o.target[21]
    DIRECTION OUTPUT ;
    USE SIGNAL ;
    PORT
      LAYER Metal3 ;
        RECT  0 1292.14 0.4 1292.54 ;
    END
  END complete_o.target[21]
  PIN complete_o.target[22]
    DIRECTION OUTPUT ;
    USE SIGNAL ;
    PORT
      LAYER Metal3 ;
        RECT  0 1293.82 0.4 1294.22 ;
    END
  END complete_o.target[22]
  PIN complete_o.target[23]
    DIRECTION OUTPUT ;
    USE SIGNAL ;
    PORT
      LAYER Metal3 ;
        RECT  0 1295.5 0.4 1295.9 ;
    END
  END complete_o.target[23]
  PIN complete_o.target[24]
    DIRECTION OUTPUT ;
    USE SIGNAL ;
    PORT
      LAYER Metal3 ;
        RECT  0 1297.18 0.4 1297.58 ;
    END
  END complete_o.target[24]
  PIN complete_o.target[25]
    DIRECTION OUTPUT ;
    USE SIGNAL ;
    PORT
      LAYER Metal3 ;
        RECT  0 1298.86 0.4 1299.26 ;
    END
  END complete_o.target[25]
  PIN complete_o.target[26]
    DIRECTION OUTPUT ;
    USE SIGNAL ;
    PORT
      LAYER Metal3 ;
        RECT  0 1300.54 0.4 1300.94 ;
    END
  END complete_o.target[26]
  PIN complete_o.target[27]
    DIRECTION OUTPUT ;
    USE SIGNAL ;
    PORT
      LAYER Metal3 ;
        RECT  0 1302.22 0.4 1302.62 ;
    END
  END complete_o.target[27]
  PIN complete_o.target[28]
    DIRECTION OUTPUT ;
    USE SIGNAL ;
    PORT
      LAYER Metal3 ;
        RECT  0 1303.9 0.4 1304.3 ;
    END
  END complete_o.target[28]
  PIN complete_o.target[29]
    DIRECTION OUTPUT ;
    USE SIGNAL ;
    PORT
      LAYER Metal3 ;
        RECT  0 1305.58 0.4 1305.98 ;
    END
  END complete_o.target[29]
  PIN complete_o.target[2]
    DIRECTION OUTPUT ;
    USE SIGNAL ;
    PORT
      LAYER Metal3 ;
        RECT  0 1255.18 0.4 1255.58 ;
    END
  END complete_o.target[2]
  PIN complete_o.target[30]
    DIRECTION OUTPUT ;
    USE SIGNAL ;
    PORT
      LAYER Metal3 ;
        RECT  0 1307.26 0.4 1307.66 ;
    END
  END complete_o.target[30]
  PIN complete_o.target[31]
    DIRECTION OUTPUT ;
    USE SIGNAL ;
    PORT
      LAYER Metal3 ;
        RECT  0 1308.94 0.4 1309.34 ;
    END
  END complete_o.target[31]
  PIN complete_o.target[3]
    DIRECTION OUTPUT ;
    USE SIGNAL ;
    PORT
      LAYER Metal3 ;
        RECT  0 1257.7 0.4 1258.1 ;
    END
  END complete_o.target[3]
  PIN complete_o.target[4]
    DIRECTION OUTPUT ;
    USE SIGNAL ;
    PORT
      LAYER Metal3 ;
        RECT  0 1260.22 0.4 1260.62 ;
    END
  END complete_o.target[4]
  PIN complete_o.target[5]
    DIRECTION OUTPUT ;
    USE SIGNAL ;
    PORT
      LAYER Metal3 ;
        RECT  0 1262.74 0.4 1263.14 ;
    END
  END complete_o.target[5]
  PIN complete_o.target[6]
    DIRECTION OUTPUT ;
    USE SIGNAL ;
    PORT
      LAYER Metal3 ;
        RECT  0 1265.26 0.4 1265.66 ;
    END
  END complete_o.target[6]
  PIN complete_o.target[7]
    DIRECTION OUTPUT ;
    USE SIGNAL ;
    PORT
      LAYER Metal3 ;
        RECT  0 1267.78 0.4 1268.18 ;
    END
  END complete_o.target[7]
  PIN complete_o.target[8]
    DIRECTION OUTPUT ;
    USE SIGNAL ;
    PORT
      LAYER Metal3 ;
        RECT  0 1270.3 0.4 1270.7 ;
    END
  END complete_o.target[8]
  PIN complete_o.target[9]
    DIRECTION OUTPUT ;
    USE SIGNAL ;
    PORT
      LAYER Metal3 ;
        RECT  0 1271.98 0.4 1272.38 ;
    END
  END complete_o.target[9]
  PIN complete_o.valid
    DIRECTION OUTPUT ;
    USE SIGNAL ;
    PORT
      LAYER Metal3 ;
        RECT  0 1247.62 0.4 1248.02 ;
    END
  END complete_o.valid
  PIN copile_i.cfp[0]
    DIRECTION INPUT ;
    USE SIGNAL ;
    PORT
      LAYER Metal3 ;
        RECT  0 10.3 0.4 10.7 ;
    END
  END copile_i.cfp[0]
  PIN copile_i.cfp[10]
    DIRECTION INPUT ;
    USE SIGNAL ;
    PORT
      LAYER Metal3 ;
        RECT  0 35.5 0.4 35.9 ;
    END
  END copile_i.cfp[10]
  PIN copile_i.cfp[11]
    DIRECTION INPUT ;
    USE SIGNAL ;
    PORT
      LAYER Metal3 ;
        RECT  0 38.02 0.4 38.42 ;
    END
  END copile_i.cfp[11]
  PIN copile_i.cfp[12]
    DIRECTION INPUT ;
    USE SIGNAL ;
    PORT
      LAYER Metal3 ;
        RECT  0 40.54 0.4 40.94 ;
    END
  END copile_i.cfp[12]
  PIN copile_i.cfp[13]
    DIRECTION INPUT ;
    USE SIGNAL ;
    PORT
      LAYER Metal3 ;
        RECT  0 43.06 0.4 43.46 ;
    END
  END copile_i.cfp[13]
  PIN copile_i.cfp[14]
    DIRECTION INPUT ;
    USE SIGNAL ;
    PORT
      LAYER Metal3 ;
        RECT  0 45.58 0.4 45.98 ;
    END
  END copile_i.cfp[14]
  PIN copile_i.cfp[15]
    DIRECTION INPUT ;
    USE SIGNAL ;
    PORT
      LAYER Metal3 ;
        RECT  0 48.1 0.4 48.5 ;
    END
  END copile_i.cfp[15]
  PIN copile_i.cfp[16]
    DIRECTION INPUT ;
    USE SIGNAL ;
    PORT
      LAYER Metal3 ;
        RECT  0 50.62 0.4 51.02 ;
    END
  END copile_i.cfp[16]
  PIN copile_i.cfp[17]
    DIRECTION INPUT ;
    USE SIGNAL ;
    PORT
      LAYER Metal3 ;
        RECT  0 53.14 0.4 53.54 ;
    END
  END copile_i.cfp[17]
  PIN copile_i.cfp[18]
    DIRECTION INPUT ;
    USE SIGNAL ;
    PORT
      LAYER Metal3 ;
        RECT  0 55.66 0.4 56.06 ;
    END
  END copile_i.cfp[18]
  PIN copile_i.cfp[19]
    DIRECTION INPUT ;
    USE SIGNAL ;
    PORT
      LAYER Metal3 ;
        RECT  0 58.18 0.4 58.58 ;
    END
  END copile_i.cfp[19]
  PIN copile_i.cfp[1]
    DIRECTION INPUT ;
    USE SIGNAL ;
    PORT
      LAYER Metal3 ;
        RECT  0 12.82 0.4 13.22 ;
    END
  END copile_i.cfp[1]
  PIN copile_i.cfp[20]
    DIRECTION INPUT ;
    USE SIGNAL ;
    PORT
      LAYER Metal3 ;
        RECT  0 60.7 0.4 61.1 ;
    END
  END copile_i.cfp[20]
  PIN copile_i.cfp[21]
    DIRECTION INPUT ;
    USE SIGNAL ;
    PORT
      LAYER Metal3 ;
        RECT  0 63.22 0.4 63.62 ;
    END
  END copile_i.cfp[21]
  PIN copile_i.cfp[22]
    DIRECTION INPUT ;
    USE SIGNAL ;
    PORT
      LAYER Metal3 ;
        RECT  0 65.74 0.4 66.14 ;
    END
  END copile_i.cfp[22]
  PIN copile_i.cfp[23]
    DIRECTION INPUT ;
    USE SIGNAL ;
    PORT
      LAYER Metal3 ;
        RECT  0 68.26 0.4 68.66 ;
    END
  END copile_i.cfp[23]
  PIN copile_i.cfp[24]
    DIRECTION INPUT ;
    USE SIGNAL ;
    PORT
      LAYER Metal3 ;
        RECT  0 70.78 0.4 71.18 ;
    END
  END copile_i.cfp[24]
  PIN copile_i.cfp[25]
    DIRECTION INPUT ;
    USE SIGNAL ;
    PORT
      LAYER Metal3 ;
        RECT  0 73.3 0.4 73.7 ;
    END
  END copile_i.cfp[25]
  PIN copile_i.cfp[26]
    DIRECTION INPUT ;
    USE SIGNAL ;
    PORT
      LAYER Metal3 ;
        RECT  0 75.82 0.4 76.22 ;
    END
  END copile_i.cfp[26]
  PIN copile_i.cfp[27]
    DIRECTION INPUT ;
    USE SIGNAL ;
    PORT
      LAYER Metal3 ;
        RECT  0 78.34 0.4 78.74 ;
    END
  END copile_i.cfp[27]
  PIN copile_i.cfp[28]
    DIRECTION INPUT ;
    USE SIGNAL ;
    PORT
      LAYER Metal3 ;
        RECT  0 80.86 0.4 81.26 ;
    END
  END copile_i.cfp[28]
  PIN copile_i.cfp[29]
    DIRECTION INPUT ;
    USE SIGNAL ;
    PORT
      LAYER Metal3 ;
        RECT  0 83.38 0.4 83.78 ;
    END
  END copile_i.cfp[29]
  PIN copile_i.cfp[2]
    DIRECTION INPUT ;
    USE SIGNAL ;
    PORT
      LAYER Metal3 ;
        RECT  0 15.34 0.4 15.74 ;
    END
  END copile_i.cfp[2]
  PIN copile_i.cfp[30]
    DIRECTION INPUT ;
    USE SIGNAL ;
    PORT
      LAYER Metal3 ;
        RECT  0 85.9 0.4 86.3 ;
    END
  END copile_i.cfp[30]
  PIN copile_i.cfp[31]
    DIRECTION INPUT ;
    USE SIGNAL ;
    PORT
      LAYER Metal3 ;
        RECT  0 88.42 0.4 88.82 ;
    END
  END copile_i.cfp[31]
  PIN copile_i.cfp[32]
    DIRECTION INPUT ;
    USE SIGNAL ;
    PORT
      LAYER Metal3 ;
        RECT  0 90.94 0.4 91.34 ;
    END
  END copile_i.cfp[32]
  PIN copile_i.cfp[33]
    DIRECTION INPUT ;
    USE SIGNAL ;
    PORT
      LAYER Metal3 ;
        RECT  0 93.46 0.4 93.86 ;
    END
  END copile_i.cfp[33]
  PIN copile_i.cfp[34]
    DIRECTION INPUT ;
    USE SIGNAL ;
    PORT
      LAYER Metal3 ;
        RECT  0 95.98 0.4 96.38 ;
    END
  END copile_i.cfp[34]
  PIN copile_i.cfp[35]
    DIRECTION INPUT ;
    USE SIGNAL ;
    PORT
      LAYER Metal3 ;
        RECT  0 98.5 0.4 98.9 ;
    END
  END copile_i.cfp[35]
  PIN copile_i.cfp[36]
    DIRECTION INPUT ;
    USE SIGNAL ;
    PORT
      LAYER Metal3 ;
        RECT  0 101.02 0.4 101.42 ;
    END
  END copile_i.cfp[36]
  PIN copile_i.cfp[37]
    DIRECTION INPUT ;
    USE SIGNAL ;
    PORT
      LAYER Metal3 ;
        RECT  0 103.54 0.4 103.94 ;
    END
  END copile_i.cfp[37]
  PIN copile_i.cfp[38]
    DIRECTION INPUT ;
    USE SIGNAL ;
    PORT
      LAYER Metal3 ;
        RECT  0 106.06 0.4 106.46 ;
    END
  END copile_i.cfp[38]
  PIN copile_i.cfp[39]
    DIRECTION INPUT ;
    USE SIGNAL ;
    PORT
      LAYER Metal3 ;
        RECT  0 108.58 0.4 108.98 ;
    END
  END copile_i.cfp[39]
  PIN copile_i.cfp[3]
    DIRECTION INPUT ;
    USE SIGNAL ;
    PORT
      LAYER Metal3 ;
        RECT  0 17.86 0.4 18.26 ;
    END
  END copile_i.cfp[3]
  PIN copile_i.cfp[40]
    DIRECTION INPUT ;
    USE SIGNAL ;
    PORT
      LAYER Metal3 ;
        RECT  0 111.1 0.4 111.5 ;
    END
  END copile_i.cfp[40]
  PIN copile_i.cfp[41]
    DIRECTION INPUT ;
    USE SIGNAL ;
    PORT
      LAYER Metal3 ;
        RECT  0 113.62 0.4 114.02 ;
    END
  END copile_i.cfp[41]
  PIN copile_i.cfp[42]
    DIRECTION INPUT ;
    USE SIGNAL ;
    PORT
      LAYER Metal3 ;
        RECT  0 116.14 0.4 116.54 ;
    END
  END copile_i.cfp[42]
  PIN copile_i.cfp[43]
    DIRECTION INPUT ;
    USE SIGNAL ;
    PORT
      LAYER Metal3 ;
        RECT  0 118.66 0.4 119.06 ;
    END
  END copile_i.cfp[43]
  PIN copile_i.cfp[44]
    DIRECTION INPUT ;
    USE SIGNAL ;
    PORT
      LAYER Metal3 ;
        RECT  0 121.18 0.4 121.58 ;
    END
  END copile_i.cfp[44]
  PIN copile_i.cfp[45]
    DIRECTION INPUT ;
    USE SIGNAL ;
    PORT
      LAYER Metal3 ;
        RECT  0 123.7 0.4 124.1 ;
    END
  END copile_i.cfp[45]
  PIN copile_i.cfp[46]
    DIRECTION INPUT ;
    USE SIGNAL ;
    PORT
      LAYER Metal3 ;
        RECT  0 126.22 0.4 126.62 ;
    END
  END copile_i.cfp[46]
  PIN copile_i.cfp[47]
    DIRECTION INPUT ;
    USE SIGNAL ;
    PORT
      LAYER Metal3 ;
        RECT  0 128.74 0.4 129.14 ;
    END
  END copile_i.cfp[47]
  PIN copile_i.cfp[48]
    DIRECTION INPUT ;
    USE SIGNAL ;
    PORT
      LAYER Metal3 ;
        RECT  0 131.26 0.4 131.66 ;
    END
  END copile_i.cfp[48]
  PIN copile_i.cfp[49]
    DIRECTION INPUT ;
    USE SIGNAL ;
    PORT
      LAYER Metal3 ;
        RECT  0 133.78 0.4 134.18 ;
    END
  END copile_i.cfp[49]
  PIN copile_i.cfp[4]
    DIRECTION INPUT ;
    USE SIGNAL ;
    PORT
      LAYER Metal3 ;
        RECT  0 20.38 0.4 20.78 ;
    END
  END copile_i.cfp[4]
  PIN copile_i.cfp[50]
    DIRECTION INPUT ;
    USE SIGNAL ;
    PORT
      LAYER Metal3 ;
        RECT  0 136.3 0.4 136.7 ;
    END
  END copile_i.cfp[50]
  PIN copile_i.cfp[51]
    DIRECTION INPUT ;
    USE SIGNAL ;
    PORT
      LAYER Metal3 ;
        RECT  0 138.82 0.4 139.22 ;
    END
  END copile_i.cfp[51]
  PIN copile_i.cfp[52]
    DIRECTION INPUT ;
    USE SIGNAL ;
    PORT
      LAYER Metal3 ;
        RECT  0 141.34 0.4 141.74 ;
    END
  END copile_i.cfp[52]
  PIN copile_i.cfp[53]
    DIRECTION INPUT ;
    USE SIGNAL ;
    PORT
      LAYER Metal3 ;
        RECT  0 143.86 0.4 144.26 ;
    END
  END copile_i.cfp[53]
  PIN copile_i.cfp[54]
    DIRECTION INPUT ;
    USE SIGNAL ;
    PORT
      LAYER Metal3 ;
        RECT  0 146.38 0.4 146.78 ;
    END
  END copile_i.cfp[54]
  PIN copile_i.cfp[55]
    DIRECTION INPUT ;
    USE SIGNAL ;
    PORT
      LAYER Metal3 ;
        RECT  0 148.9 0.4 149.3 ;
    END
  END copile_i.cfp[55]
  PIN copile_i.cfp[56]
    DIRECTION INPUT ;
    USE SIGNAL ;
    PORT
      LAYER Metal3 ;
        RECT  0 151.42 0.4 151.82 ;
    END
  END copile_i.cfp[56]
  PIN copile_i.cfp[57]
    DIRECTION INPUT ;
    USE SIGNAL ;
    PORT
      LAYER Metal3 ;
        RECT  0 153.94 0.4 154.34 ;
    END
  END copile_i.cfp[57]
  PIN copile_i.cfp[58]
    DIRECTION INPUT ;
    USE SIGNAL ;
    PORT
      LAYER Metal3 ;
        RECT  0 156.46 0.4 156.86 ;
    END
  END copile_i.cfp[58]
  PIN copile_i.cfp[59]
    DIRECTION INPUT ;
    USE SIGNAL ;
    PORT
      LAYER Metal3 ;
        RECT  0 158.98 0.4 159.38 ;
    END
  END copile_i.cfp[59]
  PIN copile_i.cfp[5]
    DIRECTION INPUT ;
    USE SIGNAL ;
    PORT
      LAYER Metal3 ;
        RECT  0 22.9 0.4 23.3 ;
    END
  END copile_i.cfp[5]
  PIN copile_i.cfp[60]
    DIRECTION INPUT ;
    USE SIGNAL ;
    PORT
      LAYER Metal3 ;
        RECT  0 161.5 0.4 161.9 ;
    END
  END copile_i.cfp[60]
  PIN copile_i.cfp[61]
    DIRECTION INPUT ;
    USE SIGNAL ;
    PORT
      LAYER Metal3 ;
        RECT  0 164.02 0.4 164.42 ;
    END
  END copile_i.cfp[61]
  PIN copile_i.cfp[62]
    DIRECTION INPUT ;
    USE SIGNAL ;
    PORT
      LAYER Metal3 ;
        RECT  0 166.54 0.4 166.94 ;
    END
  END copile_i.cfp[62]
  PIN copile_i.cfp[63]
    DIRECTION INPUT ;
    USE SIGNAL ;
    PORT
      LAYER Metal3 ;
        RECT  0 169.06 0.4 169.46 ;
    END
  END copile_i.cfp[63]
  PIN copile_i.cfp[6]
    DIRECTION INPUT ;
    USE SIGNAL ;
    PORT
      LAYER Metal3 ;
        RECT  0 25.42 0.4 25.82 ;
    END
  END copile_i.cfp[6]
  PIN copile_i.cfp[7]
    DIRECTION INPUT ;
    USE SIGNAL ;
    PORT
      LAYER Metal3 ;
        RECT  0 27.94 0.4 28.34 ;
    END
  END copile_i.cfp[7]
  PIN copile_i.cfp[8]
    DIRECTION INPUT ;
    USE SIGNAL ;
    PORT
      LAYER Metal3 ;
        RECT  0 30.46 0.4 30.86 ;
    END
  END copile_i.cfp[8]
  PIN copile_i.cfp[9]
    DIRECTION INPUT ;
    USE SIGNAL ;
    PORT
      LAYER Metal3 ;
        RECT  0 32.98 0.4 33.38 ;
    END
  END copile_i.cfp[9]
  PIN copile_i.csp[0]
    DIRECTION INPUT ;
    USE SIGNAL ;
    PORT
      LAYER Metal3 ;
        RECT  0 11.14 0.4 11.54 ;
    END
  END copile_i.csp[0]
  PIN copile_i.csp[10]
    DIRECTION INPUT ;
    USE SIGNAL ;
    PORT
      LAYER Metal3 ;
        RECT  0 36.34 0.4 36.74 ;
    END
  END copile_i.csp[10]
  PIN copile_i.csp[11]
    DIRECTION INPUT ;
    USE SIGNAL ;
    PORT
      LAYER Metal3 ;
        RECT  0 38.86 0.4 39.26 ;
    END
  END copile_i.csp[11]
  PIN copile_i.csp[12]
    DIRECTION INPUT ;
    USE SIGNAL ;
    PORT
      LAYER Metal3 ;
        RECT  0 41.38 0.4 41.78 ;
    END
  END copile_i.csp[12]
  PIN copile_i.csp[13]
    DIRECTION INPUT ;
    USE SIGNAL ;
    PORT
      LAYER Metal3 ;
        RECT  0 43.9 0.4 44.3 ;
    END
  END copile_i.csp[13]
  PIN copile_i.csp[14]
    DIRECTION INPUT ;
    USE SIGNAL ;
    PORT
      LAYER Metal3 ;
        RECT  0 46.42 0.4 46.82 ;
    END
  END copile_i.csp[14]
  PIN copile_i.csp[15]
    DIRECTION INPUT ;
    USE SIGNAL ;
    PORT
      LAYER Metal3 ;
        RECT  0 48.94 0.4 49.34 ;
    END
  END copile_i.csp[15]
  PIN copile_i.csp[16]
    DIRECTION INPUT ;
    USE SIGNAL ;
    PORT
      LAYER Metal3 ;
        RECT  0 51.46 0.4 51.86 ;
    END
  END copile_i.csp[16]
  PIN copile_i.csp[17]
    DIRECTION INPUT ;
    USE SIGNAL ;
    PORT
      LAYER Metal3 ;
        RECT  0 53.98 0.4 54.38 ;
    END
  END copile_i.csp[17]
  PIN copile_i.csp[18]
    DIRECTION INPUT ;
    USE SIGNAL ;
    PORT
      LAYER Metal3 ;
        RECT  0 56.5 0.4 56.9 ;
    END
  END copile_i.csp[18]
  PIN copile_i.csp[19]
    DIRECTION INPUT ;
    USE SIGNAL ;
    PORT
      LAYER Metal3 ;
        RECT  0 59.02 0.4 59.42 ;
    END
  END copile_i.csp[19]
  PIN copile_i.csp[1]
    DIRECTION INPUT ;
    USE SIGNAL ;
    PORT
      LAYER Metal3 ;
        RECT  0 13.66 0.4 14.06 ;
    END
  END copile_i.csp[1]
  PIN copile_i.csp[20]
    DIRECTION INPUT ;
    USE SIGNAL ;
    PORT
      LAYER Metal3 ;
        RECT  0 61.54 0.4 61.94 ;
    END
  END copile_i.csp[20]
  PIN copile_i.csp[21]
    DIRECTION INPUT ;
    USE SIGNAL ;
    PORT
      LAYER Metal3 ;
        RECT  0 64.06 0.4 64.46 ;
    END
  END copile_i.csp[21]
  PIN copile_i.csp[22]
    DIRECTION INPUT ;
    USE SIGNAL ;
    PORT
      LAYER Metal3 ;
        RECT  0 66.58 0.4 66.98 ;
    END
  END copile_i.csp[22]
  PIN copile_i.csp[23]
    DIRECTION INPUT ;
    USE SIGNAL ;
    PORT
      LAYER Metal3 ;
        RECT  0 69.1 0.4 69.5 ;
    END
  END copile_i.csp[23]
  PIN copile_i.csp[24]
    DIRECTION INPUT ;
    USE SIGNAL ;
    PORT
      LAYER Metal3 ;
        RECT  0 71.62 0.4 72.02 ;
    END
  END copile_i.csp[24]
  PIN copile_i.csp[25]
    DIRECTION INPUT ;
    USE SIGNAL ;
    PORT
      LAYER Metal3 ;
        RECT  0 74.14 0.4 74.54 ;
    END
  END copile_i.csp[25]
  PIN copile_i.csp[26]
    DIRECTION INPUT ;
    USE SIGNAL ;
    PORT
      LAYER Metal3 ;
        RECT  0 76.66 0.4 77.06 ;
    END
  END copile_i.csp[26]
  PIN copile_i.csp[27]
    DIRECTION INPUT ;
    USE SIGNAL ;
    PORT
      LAYER Metal3 ;
        RECT  0 79.18 0.4 79.58 ;
    END
  END copile_i.csp[27]
  PIN copile_i.csp[28]
    DIRECTION INPUT ;
    USE SIGNAL ;
    PORT
      LAYER Metal3 ;
        RECT  0 81.7 0.4 82.1 ;
    END
  END copile_i.csp[28]
  PIN copile_i.csp[29]
    DIRECTION INPUT ;
    USE SIGNAL ;
    PORT
      LAYER Metal3 ;
        RECT  0 84.22 0.4 84.62 ;
    END
  END copile_i.csp[29]
  PIN copile_i.csp[2]
    DIRECTION INPUT ;
    USE SIGNAL ;
    PORT
      LAYER Metal3 ;
        RECT  0 16.18 0.4 16.58 ;
    END
  END copile_i.csp[2]
  PIN copile_i.csp[30]
    DIRECTION INPUT ;
    USE SIGNAL ;
    PORT
      LAYER Metal3 ;
        RECT  0 86.74 0.4 87.14 ;
    END
  END copile_i.csp[30]
  PIN copile_i.csp[31]
    DIRECTION INPUT ;
    USE SIGNAL ;
    PORT
      LAYER Metal3 ;
        RECT  0 89.26 0.4 89.66 ;
    END
  END copile_i.csp[31]
  PIN copile_i.csp[32]
    DIRECTION INPUT ;
    USE SIGNAL ;
    PORT
      LAYER Metal3 ;
        RECT  0 91.78 0.4 92.18 ;
    END
  END copile_i.csp[32]
  PIN copile_i.csp[33]
    DIRECTION INPUT ;
    USE SIGNAL ;
    PORT
      LAYER Metal3 ;
        RECT  0 94.3 0.4 94.7 ;
    END
  END copile_i.csp[33]
  PIN copile_i.csp[34]
    DIRECTION INPUT ;
    USE SIGNAL ;
    PORT
      LAYER Metal3 ;
        RECT  0 96.82 0.4 97.22 ;
    END
  END copile_i.csp[34]
  PIN copile_i.csp[35]
    DIRECTION INPUT ;
    USE SIGNAL ;
    PORT
      LAYER Metal3 ;
        RECT  0 99.34 0.4 99.74 ;
    END
  END copile_i.csp[35]
  PIN copile_i.csp[36]
    DIRECTION INPUT ;
    USE SIGNAL ;
    PORT
      LAYER Metal3 ;
        RECT  0 101.86 0.4 102.26 ;
    END
  END copile_i.csp[36]
  PIN copile_i.csp[37]
    DIRECTION INPUT ;
    USE SIGNAL ;
    PORT
      LAYER Metal3 ;
        RECT  0 104.38 0.4 104.78 ;
    END
  END copile_i.csp[37]
  PIN copile_i.csp[38]
    DIRECTION INPUT ;
    USE SIGNAL ;
    PORT
      LAYER Metal3 ;
        RECT  0 106.9 0.4 107.3 ;
    END
  END copile_i.csp[38]
  PIN copile_i.csp[39]
    DIRECTION INPUT ;
    USE SIGNAL ;
    PORT
      LAYER Metal3 ;
        RECT  0 109.42 0.4 109.82 ;
    END
  END copile_i.csp[39]
  PIN copile_i.csp[3]
    DIRECTION INPUT ;
    USE SIGNAL ;
    PORT
      LAYER Metal3 ;
        RECT  0 18.7 0.4 19.1 ;
    END
  END copile_i.csp[3]
  PIN copile_i.csp[40]
    DIRECTION INPUT ;
    USE SIGNAL ;
    PORT
      LAYER Metal3 ;
        RECT  0 111.94 0.4 112.34 ;
    END
  END copile_i.csp[40]
  PIN copile_i.csp[41]
    DIRECTION INPUT ;
    USE SIGNAL ;
    PORT
      LAYER Metal3 ;
        RECT  0 114.46 0.4 114.86 ;
    END
  END copile_i.csp[41]
  PIN copile_i.csp[42]
    DIRECTION INPUT ;
    USE SIGNAL ;
    PORT
      LAYER Metal3 ;
        RECT  0 116.98 0.4 117.38 ;
    END
  END copile_i.csp[42]
  PIN copile_i.csp[43]
    DIRECTION INPUT ;
    USE SIGNAL ;
    PORT
      LAYER Metal3 ;
        RECT  0 119.5 0.4 119.9 ;
    END
  END copile_i.csp[43]
  PIN copile_i.csp[44]
    DIRECTION INPUT ;
    USE SIGNAL ;
    PORT
      LAYER Metal3 ;
        RECT  0 122.02 0.4 122.42 ;
    END
  END copile_i.csp[44]
  PIN copile_i.csp[45]
    DIRECTION INPUT ;
    USE SIGNAL ;
    PORT
      LAYER Metal3 ;
        RECT  0 124.54 0.4 124.94 ;
    END
  END copile_i.csp[45]
  PIN copile_i.csp[46]
    DIRECTION INPUT ;
    USE SIGNAL ;
    PORT
      LAYER Metal3 ;
        RECT  0 127.06 0.4 127.46 ;
    END
  END copile_i.csp[46]
  PIN copile_i.csp[47]
    DIRECTION INPUT ;
    USE SIGNAL ;
    PORT
      LAYER Metal3 ;
        RECT  0 129.58 0.4 129.98 ;
    END
  END copile_i.csp[47]
  PIN copile_i.csp[48]
    DIRECTION INPUT ;
    USE SIGNAL ;
    PORT
      LAYER Metal3 ;
        RECT  0 132.1 0.4 132.5 ;
    END
  END copile_i.csp[48]
  PIN copile_i.csp[49]
    DIRECTION INPUT ;
    USE SIGNAL ;
    PORT
      LAYER Metal3 ;
        RECT  0 134.62 0.4 135.02 ;
    END
  END copile_i.csp[49]
  PIN copile_i.csp[4]
    DIRECTION INPUT ;
    USE SIGNAL ;
    PORT
      LAYER Metal3 ;
        RECT  0 21.22 0.4 21.62 ;
    END
  END copile_i.csp[4]
  PIN copile_i.csp[50]
    DIRECTION INPUT ;
    USE SIGNAL ;
    PORT
      LAYER Metal3 ;
        RECT  0 137.14 0.4 137.54 ;
    END
  END copile_i.csp[50]
  PIN copile_i.csp[51]
    DIRECTION INPUT ;
    USE SIGNAL ;
    PORT
      LAYER Metal3 ;
        RECT  0 139.66 0.4 140.06 ;
    END
  END copile_i.csp[51]
  PIN copile_i.csp[52]
    DIRECTION INPUT ;
    USE SIGNAL ;
    PORT
      LAYER Metal3 ;
        RECT  0 142.18 0.4 142.58 ;
    END
  END copile_i.csp[52]
  PIN copile_i.csp[53]
    DIRECTION INPUT ;
    USE SIGNAL ;
    PORT
      LAYER Metal3 ;
        RECT  0 144.7 0.4 145.1 ;
    END
  END copile_i.csp[53]
  PIN copile_i.csp[54]
    DIRECTION INPUT ;
    USE SIGNAL ;
    PORT
      LAYER Metal3 ;
        RECT  0 147.22 0.4 147.62 ;
    END
  END copile_i.csp[54]
  PIN copile_i.csp[55]
    DIRECTION INPUT ;
    USE SIGNAL ;
    PORT
      LAYER Metal3 ;
        RECT  0 149.74 0.4 150.14 ;
    END
  END copile_i.csp[55]
  PIN copile_i.csp[56]
    DIRECTION INPUT ;
    USE SIGNAL ;
    PORT
      LAYER Metal3 ;
        RECT  0 152.26 0.4 152.66 ;
    END
  END copile_i.csp[56]
  PIN copile_i.csp[57]
    DIRECTION INPUT ;
    USE SIGNAL ;
    PORT
      LAYER Metal3 ;
        RECT  0 154.78 0.4 155.18 ;
    END
  END copile_i.csp[57]
  PIN copile_i.csp[58]
    DIRECTION INPUT ;
    USE SIGNAL ;
    PORT
      LAYER Metal3 ;
        RECT  0 157.3 0.4 157.7 ;
    END
  END copile_i.csp[58]
  PIN copile_i.csp[59]
    DIRECTION INPUT ;
    USE SIGNAL ;
    PORT
      LAYER Metal3 ;
        RECT  0 159.82 0.4 160.22 ;
    END
  END copile_i.csp[59]
  PIN copile_i.csp[5]
    DIRECTION INPUT ;
    USE SIGNAL ;
    PORT
      LAYER Metal3 ;
        RECT  0 23.74 0.4 24.14 ;
    END
  END copile_i.csp[5]
  PIN copile_i.csp[60]
    DIRECTION INPUT ;
    USE SIGNAL ;
    PORT
      LAYER Metal3 ;
        RECT  0 162.34 0.4 162.74 ;
    END
  END copile_i.csp[60]
  PIN copile_i.csp[61]
    DIRECTION INPUT ;
    USE SIGNAL ;
    PORT
      LAYER Metal3 ;
        RECT  0 164.86 0.4 165.26 ;
    END
  END copile_i.csp[61]
  PIN copile_i.csp[62]
    DIRECTION INPUT ;
    USE SIGNAL ;
    PORT
      LAYER Metal3 ;
        RECT  0 167.38 0.4 167.78 ;
    END
  END copile_i.csp[62]
  PIN copile_i.csp[63]
    DIRECTION INPUT ;
    USE SIGNAL ;
    PORT
      LAYER Metal3 ;
        RECT  0 169.9 0.4 170.3 ;
    END
  END copile_i.csp[63]
  PIN copile_i.csp[6]
    DIRECTION INPUT ;
    USE SIGNAL ;
    PORT
      LAYER Metal3 ;
        RECT  0 26.26 0.4 26.66 ;
    END
  END copile_i.csp[6]
  PIN copile_i.csp[7]
    DIRECTION INPUT ;
    USE SIGNAL ;
    PORT
      LAYER Metal3 ;
        RECT  0 28.78 0.4 29.18 ;
    END
  END copile_i.csp[7]
  PIN copile_i.csp[8]
    DIRECTION INPUT ;
    USE SIGNAL ;
    PORT
      LAYER Metal3 ;
        RECT  0 31.3 0.4 31.7 ;
    END
  END copile_i.csp[8]
  PIN copile_i.csp[9]
    DIRECTION INPUT ;
    USE SIGNAL ;
    PORT
      LAYER Metal3 ;
        RECT  0 33.82 0.4 34.22 ;
    END
  END copile_i.csp[9]
  PIN copile_i.hp[0]
    DIRECTION INPUT ;
    USE SIGNAL ;
    PORT
      LAYER Metal3 ;
        RECT  0 11.98 0.4 12.38 ;
    END
  END copile_i.hp[0]
  PIN copile_i.hp[10]
    DIRECTION INPUT ;
    USE SIGNAL ;
    PORT
      LAYER Metal3 ;
        RECT  0 37.18 0.4 37.58 ;
    END
  END copile_i.hp[10]
  PIN copile_i.hp[11]
    DIRECTION INPUT ;
    USE SIGNAL ;
    PORT
      LAYER Metal3 ;
        RECT  0 39.7 0.4 40.1 ;
    END
  END copile_i.hp[11]
  PIN copile_i.hp[12]
    DIRECTION INPUT ;
    USE SIGNAL ;
    PORT
      LAYER Metal3 ;
        RECT  0 42.22 0.4 42.62 ;
    END
  END copile_i.hp[12]
  PIN copile_i.hp[13]
    DIRECTION INPUT ;
    USE SIGNAL ;
    PORT
      LAYER Metal3 ;
        RECT  0 44.74 0.4 45.14 ;
    END
  END copile_i.hp[13]
  PIN copile_i.hp[14]
    DIRECTION INPUT ;
    USE SIGNAL ;
    PORT
      LAYER Metal3 ;
        RECT  0 47.26 0.4 47.66 ;
    END
  END copile_i.hp[14]
  PIN copile_i.hp[15]
    DIRECTION INPUT ;
    USE SIGNAL ;
    PORT
      LAYER Metal3 ;
        RECT  0 49.78 0.4 50.18 ;
    END
  END copile_i.hp[15]
  PIN copile_i.hp[16]
    DIRECTION INPUT ;
    USE SIGNAL ;
    PORT
      LAYER Metal3 ;
        RECT  0 52.3 0.4 52.7 ;
    END
  END copile_i.hp[16]
  PIN copile_i.hp[17]
    DIRECTION INPUT ;
    USE SIGNAL ;
    PORT
      LAYER Metal3 ;
        RECT  0 54.82 0.4 55.22 ;
    END
  END copile_i.hp[17]
  PIN copile_i.hp[18]
    DIRECTION INPUT ;
    USE SIGNAL ;
    PORT
      LAYER Metal3 ;
        RECT  0 57.34 0.4 57.74 ;
    END
  END copile_i.hp[18]
  PIN copile_i.hp[19]
    DIRECTION INPUT ;
    USE SIGNAL ;
    PORT
      LAYER Metal3 ;
        RECT  0 59.86 0.4 60.26 ;
    END
  END copile_i.hp[19]
  PIN copile_i.hp[1]
    DIRECTION INPUT ;
    USE SIGNAL ;
    PORT
      LAYER Metal3 ;
        RECT  0 14.5 0.4 14.9 ;
    END
  END copile_i.hp[1]
  PIN copile_i.hp[20]
    DIRECTION INPUT ;
    USE SIGNAL ;
    PORT
      LAYER Metal3 ;
        RECT  0 62.38 0.4 62.78 ;
    END
  END copile_i.hp[20]
  PIN copile_i.hp[21]
    DIRECTION INPUT ;
    USE SIGNAL ;
    PORT
      LAYER Metal3 ;
        RECT  0 64.9 0.4 65.3 ;
    END
  END copile_i.hp[21]
  PIN copile_i.hp[22]
    DIRECTION INPUT ;
    USE SIGNAL ;
    PORT
      LAYER Metal3 ;
        RECT  0 67.42 0.4 67.82 ;
    END
  END copile_i.hp[22]
  PIN copile_i.hp[23]
    DIRECTION INPUT ;
    USE SIGNAL ;
    PORT
      LAYER Metal3 ;
        RECT  0 69.94 0.4 70.34 ;
    END
  END copile_i.hp[23]
  PIN copile_i.hp[24]
    DIRECTION INPUT ;
    USE SIGNAL ;
    PORT
      LAYER Metal3 ;
        RECT  0 72.46 0.4 72.86 ;
    END
  END copile_i.hp[24]
  PIN copile_i.hp[25]
    DIRECTION INPUT ;
    USE SIGNAL ;
    PORT
      LAYER Metal3 ;
        RECT  0 74.98 0.4 75.38 ;
    END
  END copile_i.hp[25]
  PIN copile_i.hp[26]
    DIRECTION INPUT ;
    USE SIGNAL ;
    PORT
      LAYER Metal3 ;
        RECT  0 77.5 0.4 77.9 ;
    END
  END copile_i.hp[26]
  PIN copile_i.hp[27]
    DIRECTION INPUT ;
    USE SIGNAL ;
    PORT
      LAYER Metal3 ;
        RECT  0 80.02 0.4 80.42 ;
    END
  END copile_i.hp[27]
  PIN copile_i.hp[28]
    DIRECTION INPUT ;
    USE SIGNAL ;
    PORT
      LAYER Metal3 ;
        RECT  0 82.54 0.4 82.94 ;
    END
  END copile_i.hp[28]
  PIN copile_i.hp[29]
    DIRECTION INPUT ;
    USE SIGNAL ;
    PORT
      LAYER Metal3 ;
        RECT  0 85.06 0.4 85.46 ;
    END
  END copile_i.hp[29]
  PIN copile_i.hp[2]
    DIRECTION INPUT ;
    USE SIGNAL ;
    PORT
      LAYER Metal3 ;
        RECT  0 17.02 0.4 17.42 ;
    END
  END copile_i.hp[2]
  PIN copile_i.hp[30]
    DIRECTION INPUT ;
    USE SIGNAL ;
    PORT
      LAYER Metal3 ;
        RECT  0 87.58 0.4 87.98 ;
    END
  END copile_i.hp[30]
  PIN copile_i.hp[31]
    DIRECTION INPUT ;
    USE SIGNAL ;
    PORT
      LAYER Metal3 ;
        RECT  0 90.1 0.4 90.5 ;
    END
  END copile_i.hp[31]
  PIN copile_i.hp[32]
    DIRECTION INPUT ;
    USE SIGNAL ;
    PORT
      LAYER Metal3 ;
        RECT  0 92.62 0.4 93.02 ;
    END
  END copile_i.hp[32]
  PIN copile_i.hp[33]
    DIRECTION INPUT ;
    USE SIGNAL ;
    PORT
      LAYER Metal3 ;
        RECT  0 95.14 0.4 95.54 ;
    END
  END copile_i.hp[33]
  PIN copile_i.hp[34]
    DIRECTION INPUT ;
    USE SIGNAL ;
    PORT
      LAYER Metal3 ;
        RECT  0 97.66 0.4 98.06 ;
    END
  END copile_i.hp[34]
  PIN copile_i.hp[35]
    DIRECTION INPUT ;
    USE SIGNAL ;
    PORT
      LAYER Metal3 ;
        RECT  0 100.18 0.4 100.58 ;
    END
  END copile_i.hp[35]
  PIN copile_i.hp[36]
    DIRECTION INPUT ;
    USE SIGNAL ;
    PORT
      LAYER Metal3 ;
        RECT  0 102.7 0.4 103.1 ;
    END
  END copile_i.hp[36]
  PIN copile_i.hp[37]
    DIRECTION INPUT ;
    USE SIGNAL ;
    PORT
      LAYER Metal3 ;
        RECT  0 105.22 0.4 105.62 ;
    END
  END copile_i.hp[37]
  PIN copile_i.hp[38]
    DIRECTION INPUT ;
    USE SIGNAL ;
    PORT
      LAYER Metal3 ;
        RECT  0 107.74 0.4 108.14 ;
    END
  END copile_i.hp[38]
  PIN copile_i.hp[39]
    DIRECTION INPUT ;
    USE SIGNAL ;
    PORT
      LAYER Metal3 ;
        RECT  0 110.26 0.4 110.66 ;
    END
  END copile_i.hp[39]
  PIN copile_i.hp[3]
    DIRECTION INPUT ;
    USE SIGNAL ;
    PORT
      LAYER Metal3 ;
        RECT  0 19.54 0.4 19.94 ;
    END
  END copile_i.hp[3]
  PIN copile_i.hp[40]
    DIRECTION INPUT ;
    USE SIGNAL ;
    PORT
      LAYER Metal3 ;
        RECT  0 112.78 0.4 113.18 ;
    END
  END copile_i.hp[40]
  PIN copile_i.hp[41]
    DIRECTION INPUT ;
    USE SIGNAL ;
    PORT
      LAYER Metal3 ;
        RECT  0 115.3 0.4 115.7 ;
    END
  END copile_i.hp[41]
  PIN copile_i.hp[42]
    DIRECTION INPUT ;
    USE SIGNAL ;
    PORT
      LAYER Metal3 ;
        RECT  0 117.82 0.4 118.22 ;
    END
  END copile_i.hp[42]
  PIN copile_i.hp[43]
    DIRECTION INPUT ;
    USE SIGNAL ;
    PORT
      LAYER Metal3 ;
        RECT  0 120.34 0.4 120.74 ;
    END
  END copile_i.hp[43]
  PIN copile_i.hp[44]
    DIRECTION INPUT ;
    USE SIGNAL ;
    PORT
      LAYER Metal3 ;
        RECT  0 122.86 0.4 123.26 ;
    END
  END copile_i.hp[44]
  PIN copile_i.hp[45]
    DIRECTION INPUT ;
    USE SIGNAL ;
    PORT
      LAYER Metal3 ;
        RECT  0 125.38 0.4 125.78 ;
    END
  END copile_i.hp[45]
  PIN copile_i.hp[46]
    DIRECTION INPUT ;
    USE SIGNAL ;
    PORT
      LAYER Metal3 ;
        RECT  0 127.9 0.4 128.3 ;
    END
  END copile_i.hp[46]
  PIN copile_i.hp[47]
    DIRECTION INPUT ;
    USE SIGNAL ;
    PORT
      LAYER Metal3 ;
        RECT  0 130.42 0.4 130.82 ;
    END
  END copile_i.hp[47]
  PIN copile_i.hp[48]
    DIRECTION INPUT ;
    USE SIGNAL ;
    PORT
      LAYER Metal3 ;
        RECT  0 132.94 0.4 133.34 ;
    END
  END copile_i.hp[48]
  PIN copile_i.hp[49]
    DIRECTION INPUT ;
    USE SIGNAL ;
    PORT
      LAYER Metal3 ;
        RECT  0 135.46 0.4 135.86 ;
    END
  END copile_i.hp[49]
  PIN copile_i.hp[4]
    DIRECTION INPUT ;
    USE SIGNAL ;
    PORT
      LAYER Metal3 ;
        RECT  0 22.06 0.4 22.46 ;
    END
  END copile_i.hp[4]
  PIN copile_i.hp[50]
    DIRECTION INPUT ;
    USE SIGNAL ;
    PORT
      LAYER Metal3 ;
        RECT  0 137.98 0.4 138.38 ;
    END
  END copile_i.hp[50]
  PIN copile_i.hp[51]
    DIRECTION INPUT ;
    USE SIGNAL ;
    PORT
      LAYER Metal3 ;
        RECT  0 140.5 0.4 140.9 ;
    END
  END copile_i.hp[51]
  PIN copile_i.hp[52]
    DIRECTION INPUT ;
    USE SIGNAL ;
    PORT
      LAYER Metal3 ;
        RECT  0 143.02 0.4 143.42 ;
    END
  END copile_i.hp[52]
  PIN copile_i.hp[53]
    DIRECTION INPUT ;
    USE SIGNAL ;
    PORT
      LAYER Metal3 ;
        RECT  0 145.54 0.4 145.94 ;
    END
  END copile_i.hp[53]
  PIN copile_i.hp[54]
    DIRECTION INPUT ;
    USE SIGNAL ;
    PORT
      LAYER Metal3 ;
        RECT  0 148.06 0.4 148.46 ;
    END
  END copile_i.hp[54]
  PIN copile_i.hp[55]
    DIRECTION INPUT ;
    USE SIGNAL ;
    PORT
      LAYER Metal3 ;
        RECT  0 150.58 0.4 150.98 ;
    END
  END copile_i.hp[55]
  PIN copile_i.hp[56]
    DIRECTION INPUT ;
    USE SIGNAL ;
    PORT
      LAYER Metal3 ;
        RECT  0 153.1 0.4 153.5 ;
    END
  END copile_i.hp[56]
  PIN copile_i.hp[57]
    DIRECTION INPUT ;
    USE SIGNAL ;
    PORT
      LAYER Metal3 ;
        RECT  0 155.62 0.4 156.02 ;
    END
  END copile_i.hp[57]
  PIN copile_i.hp[58]
    DIRECTION INPUT ;
    USE SIGNAL ;
    PORT
      LAYER Metal3 ;
        RECT  0 158.14 0.4 158.54 ;
    END
  END copile_i.hp[58]
  PIN copile_i.hp[59]
    DIRECTION INPUT ;
    USE SIGNAL ;
    PORT
      LAYER Metal3 ;
        RECT  0 160.66 0.4 161.06 ;
    END
  END copile_i.hp[59]
  PIN copile_i.hp[5]
    DIRECTION INPUT ;
    USE SIGNAL ;
    PORT
      LAYER Metal3 ;
        RECT  0 24.58 0.4 24.98 ;
    END
  END copile_i.hp[5]
  PIN copile_i.hp[60]
    DIRECTION INPUT ;
    USE SIGNAL ;
    PORT
      LAYER Metal3 ;
        RECT  0 163.18 0.4 163.58 ;
    END
  END copile_i.hp[60]
  PIN copile_i.hp[61]
    DIRECTION INPUT ;
    USE SIGNAL ;
    PORT
      LAYER Metal3 ;
        RECT  0 165.7 0.4 166.1 ;
    END
  END copile_i.hp[61]
  PIN copile_i.hp[62]
    DIRECTION INPUT ;
    USE SIGNAL ;
    PORT
      LAYER Metal3 ;
        RECT  0 168.22 0.4 168.62 ;
    END
  END copile_i.hp[62]
  PIN copile_i.hp[63]
    DIRECTION INPUT ;
    USE SIGNAL ;
    PORT
      LAYER Metal3 ;
        RECT  0 170.74 0.4 171.14 ;
    END
  END copile_i.hp[63]
  PIN copile_i.hp[6]
    DIRECTION INPUT ;
    USE SIGNAL ;
    PORT
      LAYER Metal3 ;
        RECT  0 27.1 0.4 27.5 ;
    END
  END copile_i.hp[6]
  PIN copile_i.hp[7]
    DIRECTION INPUT ;
    USE SIGNAL ;
    PORT
      LAYER Metal3 ;
        RECT  0 29.62 0.4 30.02 ;
    END
  END copile_i.hp[7]
  PIN copile_i.hp[8]
    DIRECTION INPUT ;
    USE SIGNAL ;
    PORT
      LAYER Metal3 ;
        RECT  0 32.14 0.4 32.54 ;
    END
  END copile_i.hp[8]
  PIN copile_i.hp[9]
    DIRECTION INPUT ;
    USE SIGNAL ;
    PORT
      LAYER Metal3 ;
        RECT  0 34.66 0.4 35.06 ;
    END
  END copile_i.hp[9]
  PIN copile_i.hp_valid
    DIRECTION INPUT ;
    USE SIGNAL ;
    PORT
      LAYER Metal3 ;
        RECT  0 9.46 0.4 9.86 ;
    END
  END copile_i.hp_valid
  PIN disp_i[0]
    DIRECTION INPUT ;
    USE SIGNAL ;
    PORT
      LAYER Metal3 ;
        RECT  0 382.42 0.4 382.82 ;
    END
  END disp_i[0]
  PIN disp_i[10]
    DIRECTION INPUT ;
    USE SIGNAL ;
    PORT
      LAYER Metal3 ;
        RECT  0 390.82 0.4 391.22 ;
    END
  END disp_i[10]
  PIN disp_i[11]
    DIRECTION INPUT ;
    USE SIGNAL ;
    PORT
      LAYER Metal3 ;
        RECT  0 391.66 0.4 392.06 ;
    END
  END disp_i[11]
  PIN disp_i[12]
    DIRECTION INPUT ;
    USE SIGNAL ;
    PORT
      LAYER Metal3 ;
        RECT  0 392.5 0.4 392.9 ;
    END
  END disp_i[12]
  PIN disp_i[13]
    DIRECTION INPUT ;
    USE SIGNAL ;
    PORT
      LAYER Metal3 ;
        RECT  0 393.34 0.4 393.74 ;
    END
  END disp_i[13]
  PIN disp_i[14]
    DIRECTION INPUT ;
    USE SIGNAL ;
    PORT
      LAYER Metal3 ;
        RECT  0 394.18 0.4 394.58 ;
    END
  END disp_i[14]
  PIN disp_i[15]
    DIRECTION INPUT ;
    USE SIGNAL ;
    PORT
      LAYER Metal3 ;
        RECT  0 395.02 0.4 395.42 ;
    END
  END disp_i[15]
  PIN disp_i[16]
    DIRECTION INPUT ;
    USE SIGNAL ;
    PORT
      LAYER Metal3 ;
        RECT  0 395.86 0.4 396.26 ;
    END
  END disp_i[16]
  PIN disp_i[17]
    DIRECTION INPUT ;
    USE SIGNAL ;
    PORT
      LAYER Metal3 ;
        RECT  0 396.7 0.4 397.1 ;
    END
  END disp_i[17]
  PIN disp_i[18]
    DIRECTION INPUT ;
    USE SIGNAL ;
    PORT
      LAYER Metal3 ;
        RECT  0 397.54 0.4 397.94 ;
    END
  END disp_i[18]
  PIN disp_i[19]
    DIRECTION INPUT ;
    USE SIGNAL ;
    PORT
      LAYER Metal3 ;
        RECT  0 398.38 0.4 398.78 ;
    END
  END disp_i[19]
  PIN disp_i[1]
    DIRECTION INPUT ;
    USE SIGNAL ;
    PORT
      LAYER Metal3 ;
        RECT  0 383.26 0.4 383.66 ;
    END
  END disp_i[1]
  PIN disp_i[20]
    DIRECTION INPUT ;
    USE SIGNAL ;
    PORT
      LAYER Metal3 ;
        RECT  0 399.22 0.4 399.62 ;
    END
  END disp_i[20]
  PIN disp_i[21]
    DIRECTION INPUT ;
    USE SIGNAL ;
    PORT
      LAYER Metal3 ;
        RECT  0 400.06 0.4 400.46 ;
    END
  END disp_i[21]
  PIN disp_i[22]
    DIRECTION INPUT ;
    USE SIGNAL ;
    PORT
      LAYER Metal3 ;
        RECT  0 400.9 0.4 401.3 ;
    END
  END disp_i[22]
  PIN disp_i[23]
    DIRECTION INPUT ;
    USE SIGNAL ;
    PORT
      LAYER Metal3 ;
        RECT  0 401.74 0.4 402.14 ;
    END
  END disp_i[23]
  PIN disp_i[24]
    DIRECTION INPUT ;
    USE SIGNAL ;
    PORT
      LAYER Metal3 ;
        RECT  0 402.58 0.4 402.98 ;
    END
  END disp_i[24]
  PIN disp_i[25]
    DIRECTION INPUT ;
    USE SIGNAL ;
    PORT
      LAYER Metal3 ;
        RECT  0 403.42 0.4 403.82 ;
    END
  END disp_i[25]
  PIN disp_i[26]
    DIRECTION INPUT ;
    USE SIGNAL ;
    PORT
      LAYER Metal3 ;
        RECT  0 404.26 0.4 404.66 ;
    END
  END disp_i[26]
  PIN disp_i[27]
    DIRECTION INPUT ;
    USE SIGNAL ;
    PORT
      LAYER Metal3 ;
        RECT  0 405.1 0.4 405.5 ;
    END
  END disp_i[27]
  PIN disp_i[28]
    DIRECTION INPUT ;
    USE SIGNAL ;
    PORT
      LAYER Metal3 ;
        RECT  0 405.94 0.4 406.34 ;
    END
  END disp_i[28]
  PIN disp_i[29]
    DIRECTION INPUT ;
    USE SIGNAL ;
    PORT
      LAYER Metal3 ;
        RECT  0 406.78 0.4 407.18 ;
    END
  END disp_i[29]
  PIN disp_i[2]
    DIRECTION INPUT ;
    USE SIGNAL ;
    PORT
      LAYER Metal3 ;
        RECT  0 384.1 0.4 384.5 ;
    END
  END disp_i[2]
  PIN disp_i[30]
    DIRECTION INPUT ;
    USE SIGNAL ;
    PORT
      LAYER Metal3 ;
        RECT  0 407.62 0.4 408.02 ;
    END
  END disp_i[30]
  PIN disp_i[31]
    DIRECTION INPUT ;
    USE SIGNAL ;
    PORT
      LAYER Metal3 ;
        RECT  0 408.46 0.4 408.86 ;
    END
  END disp_i[31]
  PIN disp_i[3]
    DIRECTION INPUT ;
    USE SIGNAL ;
    PORT
      LAYER Metal3 ;
        RECT  0 384.94 0.4 385.34 ;
    END
  END disp_i[3]
  PIN disp_i[4]
    DIRECTION INPUT ;
    USE SIGNAL ;
    PORT
      LAYER Metal3 ;
        RECT  0 385.78 0.4 386.18 ;
    END
  END disp_i[4]
  PIN disp_i[5]
    DIRECTION INPUT ;
    USE SIGNAL ;
    PORT
      LAYER Metal3 ;
        RECT  0 386.62 0.4 387.02 ;
    END
  END disp_i[5]
  PIN disp_i[6]
    DIRECTION INPUT ;
    USE SIGNAL ;
    PORT
      LAYER Metal3 ;
        RECT  0 387.46 0.4 387.86 ;
    END
  END disp_i[6]
  PIN disp_i[7]
    DIRECTION INPUT ;
    USE SIGNAL ;
    PORT
      LAYER Metal3 ;
        RECT  0 388.3 0.4 388.7 ;
    END
  END disp_i[7]
  PIN disp_i[8]
    DIRECTION INPUT ;
    USE SIGNAL ;
    PORT
      LAYER Metal3 ;
        RECT  0 389.14 0.4 389.54 ;
    END
  END disp_i[8]
  PIN disp_i[9]
    DIRECTION INPUT ;
    USE SIGNAL ;
    PORT
      LAYER Metal3 ;
        RECT  0 389.98 0.4 390.38 ;
    END
  END disp_i[9]
  PIN disp_sel_o[0]
    DIRECTION OUTPUT ;
    USE SIGNAL ;
    PORT
      LAYER Metal3 ;
        RECT  0 459.7 0.4 460.1 ;
    END
  END disp_sel_o[0]
  PIN disp_sel_o[1]
    DIRECTION OUTPUT ;
    USE SIGNAL ;
    PORT
      LAYER Metal3 ;
        RECT  0 460.54 0.4 460.94 ;
    END
  END disp_sel_o[1]
  PIN disp_sel_o[2]
    DIRECTION OUTPUT ;
    USE SIGNAL ;
    PORT
      LAYER Metal3 ;
        RECT  0 461.38 0.4 461.78 ;
    END
  END disp_sel_o[2]
  PIN disp_sel_o[3]
    DIRECTION OUTPUT ;
    USE SIGNAL ;
    PORT
      LAYER Metal3 ;
        RECT  0 462.22 0.4 462.62 ;
    END
  END disp_sel_o[3]
  PIN disp_wdata_o[0]
    DIRECTION OUTPUT ;
    USE SIGNAL ;
    PORT
      LAYER Metal2 ;
        RECT  366.04 1749.6 366.44 1750 ;
    END
  END disp_wdata_o[0]
  PIN disp_wdata_o[10]
    DIRECTION OUTPUT ;
    USE SIGNAL ;
    PORT
      LAYER Metal2 ;
        RECT  375.64 1749.6 376.04 1750 ;
    END
  END disp_wdata_o[10]
  PIN disp_wdata_o[11]
    DIRECTION OUTPUT ;
    USE SIGNAL ;
    PORT
      LAYER Metal2 ;
        RECT  376.6 1749.6 377 1750 ;
    END
  END disp_wdata_o[11]
  PIN disp_wdata_o[12]
    DIRECTION OUTPUT ;
    USE SIGNAL ;
    PORT
      LAYER Metal2 ;
        RECT  377.56 1749.6 377.96 1750 ;
    END
  END disp_wdata_o[12]
  PIN disp_wdata_o[13]
    DIRECTION OUTPUT ;
    USE SIGNAL ;
    PORT
      LAYER Metal2 ;
        RECT  378.52 1749.6 378.92 1750 ;
    END
  END disp_wdata_o[13]
  PIN disp_wdata_o[14]
    DIRECTION OUTPUT ;
    USE SIGNAL ;
    PORT
      LAYER Metal2 ;
        RECT  379.48 1749.6 379.88 1750 ;
    END
  END disp_wdata_o[14]
  PIN disp_wdata_o[15]
    DIRECTION OUTPUT ;
    USE SIGNAL ;
    PORT
      LAYER Metal2 ;
        RECT  380.44 1749.6 380.84 1750 ;
    END
  END disp_wdata_o[15]
  PIN disp_wdata_o[16]
    DIRECTION OUTPUT ;
    USE SIGNAL ;
    PORT
      LAYER Metal2 ;
        RECT  381.4 1749.6 381.8 1750 ;
    END
  END disp_wdata_o[16]
  PIN disp_wdata_o[17]
    DIRECTION OUTPUT ;
    USE SIGNAL ;
    PORT
      LAYER Metal2 ;
        RECT  382.36 1749.6 382.76 1750 ;
    END
  END disp_wdata_o[17]
  PIN disp_wdata_o[18]
    DIRECTION OUTPUT ;
    USE SIGNAL ;
    PORT
      LAYER Metal2 ;
        RECT  383.32 1749.6 383.72 1750 ;
    END
  END disp_wdata_o[18]
  PIN disp_wdata_o[19]
    DIRECTION OUTPUT ;
    USE SIGNAL ;
    PORT
      LAYER Metal2 ;
        RECT  384.28 1749.6 384.68 1750 ;
    END
  END disp_wdata_o[19]
  PIN disp_wdata_o[1]
    DIRECTION OUTPUT ;
    USE SIGNAL ;
    PORT
      LAYER Metal2 ;
        RECT  367 1749.6 367.4 1750 ;
    END
  END disp_wdata_o[1]
  PIN disp_wdata_o[20]
    DIRECTION OUTPUT ;
    USE SIGNAL ;
    PORT
      LAYER Metal2 ;
        RECT  385.24 1749.6 385.64 1750 ;
    END
  END disp_wdata_o[20]
  PIN disp_wdata_o[21]
    DIRECTION OUTPUT ;
    USE SIGNAL ;
    PORT
      LAYER Metal2 ;
        RECT  386.2 1749.6 386.6 1750 ;
    END
  END disp_wdata_o[21]
  PIN disp_wdata_o[22]
    DIRECTION OUTPUT ;
    USE SIGNAL ;
    PORT
      LAYER Metal2 ;
        RECT  387.16 1749.6 387.56 1750 ;
    END
  END disp_wdata_o[22]
  PIN disp_wdata_o[23]
    DIRECTION OUTPUT ;
    USE SIGNAL ;
    PORT
      LAYER Metal2 ;
        RECT  388.12 1749.6 388.52 1750 ;
    END
  END disp_wdata_o[23]
  PIN disp_wdata_o[24]
    DIRECTION OUTPUT ;
    USE SIGNAL ;
    PORT
      LAYER Metal2 ;
        RECT  389.08 1749.6 389.48 1750 ;
    END
  END disp_wdata_o[24]
  PIN disp_wdata_o[25]
    DIRECTION OUTPUT ;
    USE SIGNAL ;
    PORT
      LAYER Metal2 ;
        RECT  390.04 1749.6 390.44 1750 ;
    END
  END disp_wdata_o[25]
  PIN disp_wdata_o[26]
    DIRECTION OUTPUT ;
    USE SIGNAL ;
    PORT
      LAYER Metal2 ;
        RECT  391 1749.6 391.4 1750 ;
    END
  END disp_wdata_o[26]
  PIN disp_wdata_o[27]
    DIRECTION OUTPUT ;
    USE SIGNAL ;
    PORT
      LAYER Metal2 ;
        RECT  391.96 1749.6 392.36 1750 ;
    END
  END disp_wdata_o[27]
  PIN disp_wdata_o[28]
    DIRECTION OUTPUT ;
    USE SIGNAL ;
    PORT
      LAYER Metal2 ;
        RECT  392.92 1749.6 393.32 1750 ;
    END
  END disp_wdata_o[28]
  PIN disp_wdata_o[29]
    DIRECTION OUTPUT ;
    USE SIGNAL ;
    PORT
      LAYER Metal2 ;
        RECT  393.88 1749.6 394.28 1750 ;
    END
  END disp_wdata_o[29]
  PIN disp_wdata_o[2]
    DIRECTION OUTPUT ;
    USE SIGNAL ;
    PORT
      LAYER Metal2 ;
        RECT  367.96 1749.6 368.36 1750 ;
    END
  END disp_wdata_o[2]
  PIN disp_wdata_o[30]
    DIRECTION OUTPUT ;
    USE SIGNAL ;
    PORT
      LAYER Metal2 ;
        RECT  394.84 1749.6 395.24 1750 ;
    END
  END disp_wdata_o[30]
  PIN disp_wdata_o[31]
    DIRECTION OUTPUT ;
    USE SIGNAL ;
    PORT
      LAYER Metal2 ;
        RECT  395.8 1749.6 396.2 1750 ;
    END
  END disp_wdata_o[31]
  PIN disp_wdata_o[3]
    DIRECTION OUTPUT ;
    USE SIGNAL ;
    PORT
      LAYER Metal2 ;
        RECT  368.92 1749.6 369.32 1750 ;
    END
  END disp_wdata_o[3]
  PIN disp_wdata_o[4]
    DIRECTION OUTPUT ;
    USE SIGNAL ;
    PORT
      LAYER Metal2 ;
        RECT  369.88 1749.6 370.28 1750 ;
    END
  END disp_wdata_o[4]
  PIN disp_wdata_o[5]
    DIRECTION OUTPUT ;
    USE SIGNAL ;
    PORT
      LAYER Metal2 ;
        RECT  370.84 1749.6 371.24 1750 ;
    END
  END disp_wdata_o[5]
  PIN disp_wdata_o[6]
    DIRECTION OUTPUT ;
    USE SIGNAL ;
    PORT
      LAYER Metal2 ;
        RECT  371.8 1749.6 372.2 1750 ;
    END
  END disp_wdata_o[6]
  PIN disp_wdata_o[7]
    DIRECTION OUTPUT ;
    USE SIGNAL ;
    PORT
      LAYER Metal2 ;
        RECT  372.76 1749.6 373.16 1750 ;
    END
  END disp_wdata_o[7]
  PIN disp_wdata_o[8]
    DIRECTION OUTPUT ;
    USE SIGNAL ;
    PORT
      LAYER Metal2 ;
        RECT  373.72 1749.6 374.12 1750 ;
    END
  END disp_wdata_o[8]
  PIN disp_wdata_o[9]
    DIRECTION OUTPUT ;
    USE SIGNAL ;
    PORT
      LAYER Metal2 ;
        RECT  374.68 1749.6 375.08 1750 ;
    END
  END disp_wdata_o[9]
  PIN disp_we_o
    DIRECTION OUTPUT ;
    USE SIGNAL ;
    PORT
      LAYER Metal2 ;
        RECT  342.04 1749.6 342.44 1750 ;
    END
  END disp_we_o
  PIN disp_wsel_o[0]
    DIRECTION OUTPUT ;
    USE SIGNAL ;
    PORT
      LAYER Metal2 ;
        RECT  352.6 1749.6 353 1750 ;
    END
  END disp_wsel_o[0]
  PIN disp_wsel_o[1]
    DIRECTION OUTPUT ;
    USE SIGNAL ;
    PORT
      LAYER Metal2 ;
        RECT  353.56 1749.6 353.96 1750 ;
    END
  END disp_wsel_o[1]
  PIN disp_wsel_o[2]
    DIRECTION OUTPUT ;
    USE SIGNAL ;
    PORT
      LAYER Metal2 ;
        RECT  354.52 1749.6 354.92 1750 ;
    END
  END disp_wsel_o[2]
  PIN disp_wsel_o[3]
    DIRECTION OUTPUT ;
    USE SIGNAL ;
    PORT
      LAYER Metal2 ;
        RECT  355.48 1749.6 355.88 1750 ;
    END
  END disp_wsel_o[3]
  PIN dr_o
    DIRECTION OUTPUT ;
    USE SIGNAL ;
    PORT
      LAYER Metal2 ;
        RECT  542.68 0 543.08 0.4 ;
    END
  END dr_o
  PIN exit_code_o[0]
    DIRECTION OUTPUT ;
    USE SIGNAL ;
    PORT
      LAYER Metal2 ;
        RECT  414.04 0 414.44 0.4 ;
    END
  END exit_code_o[0]
  PIN exit_code_o[10]
    DIRECTION OUTPUT ;
    USE SIGNAL ;
    PORT
      LAYER Metal2 ;
        RECT  423.64 0 424.04 0.4 ;
    END
  END exit_code_o[10]
  PIN exit_code_o[11]
    DIRECTION OUTPUT ;
    USE SIGNAL ;
    PORT
      LAYER Metal2 ;
        RECT  424.6 0 425 0.4 ;
    END
  END exit_code_o[11]
  PIN exit_code_o[12]
    DIRECTION OUTPUT ;
    USE SIGNAL ;
    PORT
      LAYER Metal2 ;
        RECT  425.56 0 425.96 0.4 ;
    END
  END exit_code_o[12]
  PIN exit_code_o[13]
    DIRECTION OUTPUT ;
    USE SIGNAL ;
    PORT
      LAYER Metal2 ;
        RECT  426.52 0 426.92 0.4 ;
    END
  END exit_code_o[13]
  PIN exit_code_o[14]
    DIRECTION OUTPUT ;
    USE SIGNAL ;
    PORT
      LAYER Metal2 ;
        RECT  427.48 0 427.88 0.4 ;
    END
  END exit_code_o[14]
  PIN exit_code_o[15]
    DIRECTION OUTPUT ;
    USE SIGNAL ;
    PORT
      LAYER Metal2 ;
        RECT  428.44 0 428.84 0.4 ;
    END
  END exit_code_o[15]
  PIN exit_code_o[16]
    DIRECTION OUTPUT ;
    USE SIGNAL ;
    PORT
      LAYER Metal2 ;
        RECT  429.4 0 429.8 0.4 ;
    END
  END exit_code_o[16]
  PIN exit_code_o[17]
    DIRECTION OUTPUT ;
    USE SIGNAL ;
    PORT
      LAYER Metal2 ;
        RECT  430.36 0 430.76 0.4 ;
    END
  END exit_code_o[17]
  PIN exit_code_o[18]
    DIRECTION OUTPUT ;
    USE SIGNAL ;
    PORT
      LAYER Metal2 ;
        RECT  431.32 0 431.72 0.4 ;
    END
  END exit_code_o[18]
  PIN exit_code_o[19]
    DIRECTION OUTPUT ;
    USE SIGNAL ;
    PORT
      LAYER Metal2 ;
        RECT  432.28 0 432.68 0.4 ;
    END
  END exit_code_o[19]
  PIN exit_code_o[1]
    DIRECTION OUTPUT ;
    USE SIGNAL ;
    PORT
      LAYER Metal2 ;
        RECT  415 0 415.4 0.4 ;
    END
  END exit_code_o[1]
  PIN exit_code_o[20]
    DIRECTION OUTPUT ;
    USE SIGNAL ;
    PORT
      LAYER Metal2 ;
        RECT  433.24 0 433.64 0.4 ;
    END
  END exit_code_o[20]
  PIN exit_code_o[21]
    DIRECTION OUTPUT ;
    USE SIGNAL ;
    PORT
      LAYER Metal2 ;
        RECT  434.2 0 434.6 0.4 ;
    END
  END exit_code_o[21]
  PIN exit_code_o[22]
    DIRECTION OUTPUT ;
    USE SIGNAL ;
    PORT
      LAYER Metal2 ;
        RECT  435.16 0 435.56 0.4 ;
    END
  END exit_code_o[22]
  PIN exit_code_o[23]
    DIRECTION OUTPUT ;
    USE SIGNAL ;
    PORT
      LAYER Metal2 ;
        RECT  436.12 0 436.52 0.4 ;
    END
  END exit_code_o[23]
  PIN exit_code_o[24]
    DIRECTION OUTPUT ;
    USE SIGNAL ;
    PORT
      LAYER Metal2 ;
        RECT  437.08 0 437.48 0.4 ;
    END
  END exit_code_o[24]
  PIN exit_code_o[25]
    DIRECTION OUTPUT ;
    USE SIGNAL ;
    PORT
      LAYER Metal2 ;
        RECT  438.04 0 438.44 0.4 ;
    END
  END exit_code_o[25]
  PIN exit_code_o[26]
    DIRECTION OUTPUT ;
    USE SIGNAL ;
    PORT
      LAYER Metal2 ;
        RECT  439 0 439.4 0.4 ;
    END
  END exit_code_o[26]
  PIN exit_code_o[27]
    DIRECTION OUTPUT ;
    USE SIGNAL ;
    PORT
      LAYER Metal2 ;
        RECT  439.96 0 440.36 0.4 ;
    END
  END exit_code_o[27]
  PIN exit_code_o[28]
    DIRECTION OUTPUT ;
    USE SIGNAL ;
    PORT
      LAYER Metal2 ;
        RECT  440.92 0 441.32 0.4 ;
    END
  END exit_code_o[28]
  PIN exit_code_o[29]
    DIRECTION OUTPUT ;
    USE SIGNAL ;
    PORT
      LAYER Metal2 ;
        RECT  441.88 0 442.28 0.4 ;
    END
  END exit_code_o[29]
  PIN exit_code_o[2]
    DIRECTION OUTPUT ;
    USE SIGNAL ;
    PORT
      LAYER Metal2 ;
        RECT  415.96 0 416.36 0.4 ;
    END
  END exit_code_o[2]
  PIN exit_code_o[30]
    DIRECTION OUTPUT ;
    USE SIGNAL ;
    PORT
      LAYER Metal2 ;
        RECT  442.84 0 443.24 0.4 ;
    END
  END exit_code_o[30]
  PIN exit_code_o[31]
    DIRECTION OUTPUT ;
    USE SIGNAL ;
    PORT
      LAYER Metal2 ;
        RECT  443.8 0 444.2 0.4 ;
    END
  END exit_code_o[31]
  PIN exit_code_o[32]
    DIRECTION OUTPUT ;
    USE SIGNAL ;
    PORT
      LAYER Metal2 ;
        RECT  444.76 0 445.16 0.4 ;
    END
  END exit_code_o[32]
  PIN exit_code_o[33]
    DIRECTION OUTPUT ;
    USE SIGNAL ;
    PORT
      LAYER Metal2 ;
        RECT  445.72 0 446.12 0.4 ;
    END
  END exit_code_o[33]
  PIN exit_code_o[34]
    DIRECTION OUTPUT ;
    USE SIGNAL ;
    PORT
      LAYER Metal2 ;
        RECT  446.68 0 447.08 0.4 ;
    END
  END exit_code_o[34]
  PIN exit_code_o[35]
    DIRECTION OUTPUT ;
    USE SIGNAL ;
    PORT
      LAYER Metal2 ;
        RECT  447.64 0 448.04 0.4 ;
    END
  END exit_code_o[35]
  PIN exit_code_o[36]
    DIRECTION OUTPUT ;
    USE SIGNAL ;
    PORT
      LAYER Metal2 ;
        RECT  448.6 0 449 0.4 ;
    END
  END exit_code_o[36]
  PIN exit_code_o[37]
    DIRECTION OUTPUT ;
    USE SIGNAL ;
    PORT
      LAYER Metal2 ;
        RECT  449.56 0 449.96 0.4 ;
    END
  END exit_code_o[37]
  PIN exit_code_o[38]
    DIRECTION OUTPUT ;
    USE SIGNAL ;
    PORT
      LAYER Metal2 ;
        RECT  450.52 0 450.92 0.4 ;
    END
  END exit_code_o[38]
  PIN exit_code_o[39]
    DIRECTION OUTPUT ;
    USE SIGNAL ;
    PORT
      LAYER Metal2 ;
        RECT  451.48 0 451.88 0.4 ;
    END
  END exit_code_o[39]
  PIN exit_code_o[3]
    DIRECTION OUTPUT ;
    USE SIGNAL ;
    PORT
      LAYER Metal2 ;
        RECT  416.92 0 417.32 0.4 ;
    END
  END exit_code_o[3]
  PIN exit_code_o[40]
    DIRECTION OUTPUT ;
    USE SIGNAL ;
    PORT
      LAYER Metal2 ;
        RECT  452.44 0 452.84 0.4 ;
    END
  END exit_code_o[40]
  PIN exit_code_o[41]
    DIRECTION OUTPUT ;
    USE SIGNAL ;
    PORT
      LAYER Metal2 ;
        RECT  453.4 0 453.8 0.4 ;
    END
  END exit_code_o[41]
  PIN exit_code_o[42]
    DIRECTION OUTPUT ;
    USE SIGNAL ;
    PORT
      LAYER Metal2 ;
        RECT  454.36 0 454.76 0.4 ;
    END
  END exit_code_o[42]
  PIN exit_code_o[43]
    DIRECTION OUTPUT ;
    USE SIGNAL ;
    PORT
      LAYER Metal2 ;
        RECT  455.32 0 455.72 0.4 ;
    END
  END exit_code_o[43]
  PIN exit_code_o[44]
    DIRECTION OUTPUT ;
    USE SIGNAL ;
    PORT
      LAYER Metal2 ;
        RECT  456.28 0 456.68 0.4 ;
    END
  END exit_code_o[44]
  PIN exit_code_o[45]
    DIRECTION OUTPUT ;
    USE SIGNAL ;
    PORT
      LAYER Metal2 ;
        RECT  457.24 0 457.64 0.4 ;
    END
  END exit_code_o[45]
  PIN exit_code_o[46]
    DIRECTION OUTPUT ;
    USE SIGNAL ;
    PORT
      LAYER Metal2 ;
        RECT  458.2 0 458.6 0.4 ;
    END
  END exit_code_o[46]
  PIN exit_code_o[47]
    DIRECTION OUTPUT ;
    USE SIGNAL ;
    PORT
      LAYER Metal2 ;
        RECT  459.16 0 459.56 0.4 ;
    END
  END exit_code_o[47]
  PIN exit_code_o[48]
    DIRECTION OUTPUT ;
    USE SIGNAL ;
    PORT
      LAYER Metal2 ;
        RECT  460.12 0 460.52 0.4 ;
    END
  END exit_code_o[48]
  PIN exit_code_o[49]
    DIRECTION OUTPUT ;
    USE SIGNAL ;
    PORT
      LAYER Metal2 ;
        RECT  461.08 0 461.48 0.4 ;
    END
  END exit_code_o[49]
  PIN exit_code_o[4]
    DIRECTION OUTPUT ;
    USE SIGNAL ;
    PORT
      LAYER Metal2 ;
        RECT  417.88 0 418.28 0.4 ;
    END
  END exit_code_o[4]
  PIN exit_code_o[50]
    DIRECTION OUTPUT ;
    USE SIGNAL ;
    PORT
      LAYER Metal2 ;
        RECT  462.04 0 462.44 0.4 ;
    END
  END exit_code_o[50]
  PIN exit_code_o[51]
    DIRECTION OUTPUT ;
    USE SIGNAL ;
    PORT
      LAYER Metal2 ;
        RECT  463 0 463.4 0.4 ;
    END
  END exit_code_o[51]
  PIN exit_code_o[52]
    DIRECTION OUTPUT ;
    USE SIGNAL ;
    PORT
      LAYER Metal2 ;
        RECT  463.96 0 464.36 0.4 ;
    END
  END exit_code_o[52]
  PIN exit_code_o[53]
    DIRECTION OUTPUT ;
    USE SIGNAL ;
    PORT
      LAYER Metal2 ;
        RECT  464.92 0 465.32 0.4 ;
    END
  END exit_code_o[53]
  PIN exit_code_o[54]
    DIRECTION OUTPUT ;
    USE SIGNAL ;
    PORT
      LAYER Metal2 ;
        RECT  465.88 0 466.28 0.4 ;
    END
  END exit_code_o[54]
  PIN exit_code_o[55]
    DIRECTION OUTPUT ;
    USE SIGNAL ;
    PORT
      LAYER Metal2 ;
        RECT  466.84 0 467.24 0.4 ;
    END
  END exit_code_o[55]
  PIN exit_code_o[56]
    DIRECTION OUTPUT ;
    USE SIGNAL ;
    PORT
      LAYER Metal2 ;
        RECT  467.8 0 468.2 0.4 ;
    END
  END exit_code_o[56]
  PIN exit_code_o[57]
    DIRECTION OUTPUT ;
    USE SIGNAL ;
    PORT
      LAYER Metal2 ;
        RECT  468.76 0 469.16 0.4 ;
    END
  END exit_code_o[57]
  PIN exit_code_o[58]
    DIRECTION OUTPUT ;
    USE SIGNAL ;
    PORT
      LAYER Metal2 ;
        RECT  469.72 0 470.12 0.4 ;
    END
  END exit_code_o[58]
  PIN exit_code_o[59]
    DIRECTION OUTPUT ;
    USE SIGNAL ;
    PORT
      LAYER Metal2 ;
        RECT  470.68 0 471.08 0.4 ;
    END
  END exit_code_o[59]
  PIN exit_code_o[5]
    DIRECTION OUTPUT ;
    USE SIGNAL ;
    PORT
      LAYER Metal2 ;
        RECT  418.84 0 419.24 0.4 ;
    END
  END exit_code_o[5]
  PIN exit_code_o[60]
    DIRECTION OUTPUT ;
    USE SIGNAL ;
    PORT
      LAYER Metal2 ;
        RECT  471.64 0 472.04 0.4 ;
    END
  END exit_code_o[60]
  PIN exit_code_o[61]
    DIRECTION OUTPUT ;
    USE SIGNAL ;
    PORT
      LAYER Metal2 ;
        RECT  472.6 0 473 0.4 ;
    END
  END exit_code_o[61]
  PIN exit_code_o[62]
    DIRECTION OUTPUT ;
    USE SIGNAL ;
    PORT
      LAYER Metal2 ;
        RECT  473.56 0 473.96 0.4 ;
    END
  END exit_code_o[62]
  PIN exit_code_o[63]
    DIRECTION OUTPUT ;
    USE SIGNAL ;
    PORT
      LAYER Metal2 ;
        RECT  474.52 0 474.92 0.4 ;
    END
  END exit_code_o[63]
  PIN exit_code_o[6]
    DIRECTION OUTPUT ;
    USE SIGNAL ;
    PORT
      LAYER Metal2 ;
        RECT  419.8 0 420.2 0.4 ;
    END
  END exit_code_o[6]
  PIN exit_code_o[7]
    DIRECTION OUTPUT ;
    USE SIGNAL ;
    PORT
      LAYER Metal2 ;
        RECT  420.76 0 421.16 0.4 ;
    END
  END exit_code_o[7]
  PIN exit_code_o[8]
    DIRECTION OUTPUT ;
    USE SIGNAL ;
    PORT
      LAYER Metal2 ;
        RECT  421.72 0 422.12 0.4 ;
    END
  END exit_code_o[8]
  PIN exit_code_o[9]
    DIRECTION OUTPUT ;
    USE SIGNAL ;
    PORT
      LAYER Metal2 ;
        RECT  422.68 0 423.08 0.4 ;
    END
  END exit_code_o[9]
  PIN fault_i.code[0]
    DIRECTION INPUT ;
    USE SIGNAL ;
    PORT
      LAYER Metal2 ;
        RECT  458.2 1749.6 458.6 1750 ;
    END
  END fault_i.code[0]
  PIN fault_i.code[1]
    DIRECTION INPUT ;
    USE SIGNAL ;
    PORT
      LAYER Metal2 ;
        RECT  459.16 1749.6 459.56 1750 ;
    END
  END fault_i.code[1]
  PIN fault_i.code[2]
    DIRECTION INPUT ;
    USE SIGNAL ;
    PORT
      LAYER Metal2 ;
        RECT  460.12 1749.6 460.52 1750 ;
    END
  END fault_i.code[2]
  PIN fault_i.code[3]
    DIRECTION INPUT ;
    USE SIGNAL ;
    PORT
      LAYER Metal2 ;
        RECT  461.08 1749.6 461.48 1750 ;
    END
  END fault_i.code[3]
  PIN fault_i.code[4]
    DIRECTION INPUT ;
    USE SIGNAL ;
    PORT
      LAYER Metal2 ;
        RECT  462.04 1749.6 462.44 1750 ;
    END
  END fault_i.code[4]
  PIN fault_i.code[5]
    DIRECTION INPUT ;
    USE SIGNAL ;
    PORT
      LAYER Metal2 ;
        RECT  463 1749.6 463.4 1750 ;
    END
  END fault_i.code[5]
  PIN fault_i.code[6]
    DIRECTION INPUT ;
    USE SIGNAL ;
    PORT
      LAYER Metal2 ;
        RECT  463.96 1749.6 464.36 1750 ;
    END
  END fault_i.code[6]
  PIN fault_i.code[7]
    DIRECTION INPUT ;
    USE SIGNAL ;
    PORT
      LAYER Metal2 ;
        RECT  464.92 1749.6 465.32 1750 ;
    END
  END fault_i.code[7]
  PIN fault_i.valid
    DIRECTION INPUT ;
    USE SIGNAL ;
    PORT
      LAYER Metal2 ;
        RECT  457.24 1749.6 457.64 1750 ;
    END
  END fault_i.valid
  PIN fault_pc_i[0]
    DIRECTION INPUT ;
    USE SIGNAL ;
    PORT
      LAYER Metal2 ;
        RECT  416.92 1749.6 417.32 1750 ;
    END
  END fault_pc_i[0]
  PIN fault_pc_i[10]
    DIRECTION INPUT ;
    USE SIGNAL ;
    PORT
      LAYER Metal2 ;
        RECT  426.52 1749.6 426.92 1750 ;
    END
  END fault_pc_i[10]
  PIN fault_pc_i[11]
    DIRECTION INPUT ;
    USE SIGNAL ;
    PORT
      LAYER Metal2 ;
        RECT  427.48 1749.6 427.88 1750 ;
    END
  END fault_pc_i[11]
  PIN fault_pc_i[12]
    DIRECTION INPUT ;
    USE SIGNAL ;
    PORT
      LAYER Metal2 ;
        RECT  428.44 1749.6 428.84 1750 ;
    END
  END fault_pc_i[12]
  PIN fault_pc_i[13]
    DIRECTION INPUT ;
    USE SIGNAL ;
    PORT
      LAYER Metal2 ;
        RECT  429.4 1749.6 429.8 1750 ;
    END
  END fault_pc_i[13]
  PIN fault_pc_i[14]
    DIRECTION INPUT ;
    USE SIGNAL ;
    PORT
      LAYER Metal2 ;
        RECT  430.36 1749.6 430.76 1750 ;
    END
  END fault_pc_i[14]
  PIN fault_pc_i[15]
    DIRECTION INPUT ;
    USE SIGNAL ;
    PORT
      LAYER Metal2 ;
        RECT  431.32 1749.6 431.72 1750 ;
    END
  END fault_pc_i[15]
  PIN fault_pc_i[16]
    DIRECTION INPUT ;
    USE SIGNAL ;
    PORT
      LAYER Metal2 ;
        RECT  432.28 1749.6 432.68 1750 ;
    END
  END fault_pc_i[16]
  PIN fault_pc_i[17]
    DIRECTION INPUT ;
    USE SIGNAL ;
    PORT
      LAYER Metal2 ;
        RECT  433.24 1749.6 433.64 1750 ;
    END
  END fault_pc_i[17]
  PIN fault_pc_i[18]
    DIRECTION INPUT ;
    USE SIGNAL ;
    PORT
      LAYER Metal2 ;
        RECT  434.2 1749.6 434.6 1750 ;
    END
  END fault_pc_i[18]
  PIN fault_pc_i[19]
    DIRECTION INPUT ;
    USE SIGNAL ;
    PORT
      LAYER Metal2 ;
        RECT  435.16 1749.6 435.56 1750 ;
    END
  END fault_pc_i[19]
  PIN fault_pc_i[1]
    DIRECTION INPUT ;
    USE SIGNAL ;
    PORT
      LAYER Metal2 ;
        RECT  417.88 1749.6 418.28 1750 ;
    END
  END fault_pc_i[1]
  PIN fault_pc_i[20]
    DIRECTION INPUT ;
    USE SIGNAL ;
    PORT
      LAYER Metal2 ;
        RECT  436.12 1749.6 436.52 1750 ;
    END
  END fault_pc_i[20]
  PIN fault_pc_i[21]
    DIRECTION INPUT ;
    USE SIGNAL ;
    PORT
      LAYER Metal2 ;
        RECT  437.08 1749.6 437.48 1750 ;
    END
  END fault_pc_i[21]
  PIN fault_pc_i[22]
    DIRECTION INPUT ;
    USE SIGNAL ;
    PORT
      LAYER Metal2 ;
        RECT  438.04 1749.6 438.44 1750 ;
    END
  END fault_pc_i[22]
  PIN fault_pc_i[23]
    DIRECTION INPUT ;
    USE SIGNAL ;
    PORT
      LAYER Metal2 ;
        RECT  439 1749.6 439.4 1750 ;
    END
  END fault_pc_i[23]
  PIN fault_pc_i[24]
    DIRECTION INPUT ;
    USE SIGNAL ;
    PORT
      LAYER Metal2 ;
        RECT  439.96 1749.6 440.36 1750 ;
    END
  END fault_pc_i[24]
  PIN fault_pc_i[25]
    DIRECTION INPUT ;
    USE SIGNAL ;
    PORT
      LAYER Metal2 ;
        RECT  440.92 1749.6 441.32 1750 ;
    END
  END fault_pc_i[25]
  PIN fault_pc_i[26]
    DIRECTION INPUT ;
    USE SIGNAL ;
    PORT
      LAYER Metal2 ;
        RECT  441.88 1749.6 442.28 1750 ;
    END
  END fault_pc_i[26]
  PIN fault_pc_i[27]
    DIRECTION INPUT ;
    USE SIGNAL ;
    PORT
      LAYER Metal2 ;
        RECT  442.84 1749.6 443.24 1750 ;
    END
  END fault_pc_i[27]
  PIN fault_pc_i[28]
    DIRECTION INPUT ;
    USE SIGNAL ;
    PORT
      LAYER Metal2 ;
        RECT  443.8 1749.6 444.2 1750 ;
    END
  END fault_pc_i[28]
  PIN fault_pc_i[29]
    DIRECTION INPUT ;
    USE SIGNAL ;
    PORT
      LAYER Metal2 ;
        RECT  444.76 1749.6 445.16 1750 ;
    END
  END fault_pc_i[29]
  PIN fault_pc_i[2]
    DIRECTION INPUT ;
    USE SIGNAL ;
    PORT
      LAYER Metal2 ;
        RECT  418.84 1749.6 419.24 1750 ;
    END
  END fault_pc_i[2]
  PIN fault_pc_i[30]
    DIRECTION INPUT ;
    USE SIGNAL ;
    PORT
      LAYER Metal2 ;
        RECT  445.72 1749.6 446.12 1750 ;
    END
  END fault_pc_i[30]
  PIN fault_pc_i[31]
    DIRECTION INPUT ;
    USE SIGNAL ;
    PORT
      LAYER Metal2 ;
        RECT  446.68 1749.6 447.08 1750 ;
    END
  END fault_pc_i[31]
  PIN fault_pc_i[3]
    DIRECTION INPUT ;
    USE SIGNAL ;
    PORT
      LAYER Metal2 ;
        RECT  419.8 1749.6 420.2 1750 ;
    END
  END fault_pc_i[3]
  PIN fault_pc_i[4]
    DIRECTION INPUT ;
    USE SIGNAL ;
    PORT
      LAYER Metal2 ;
        RECT  420.76 1749.6 421.16 1750 ;
    END
  END fault_pc_i[4]
  PIN fault_pc_i[5]
    DIRECTION INPUT ;
    USE SIGNAL ;
    PORT
      LAYER Metal2 ;
        RECT  421.72 1749.6 422.12 1750 ;
    END
  END fault_pc_i[5]
  PIN fault_pc_i[6]
    DIRECTION INPUT ;
    USE SIGNAL ;
    PORT
      LAYER Metal2 ;
        RECT  422.68 1749.6 423.08 1750 ;
    END
  END fault_pc_i[6]
  PIN fault_pc_i[7]
    DIRECTION INPUT ;
    USE SIGNAL ;
    PORT
      LAYER Metal2 ;
        RECT  423.64 1749.6 424.04 1750 ;
    END
  END fault_pc_i[7]
  PIN fault_pc_i[8]
    DIRECTION INPUT ;
    USE SIGNAL ;
    PORT
      LAYER Metal2 ;
        RECT  424.6 1749.6 425 1750 ;
    END
  END fault_pc_i[8]
  PIN fault_pc_i[9]
    DIRECTION INPUT ;
    USE SIGNAL ;
    PORT
      LAYER Metal2 ;
        RECT  425.56 1749.6 425.96 1750 ;
    END
  END fault_pc_i[9]
  PIN fault_valid_i
    DIRECTION INPUT ;
    USE SIGNAL ;
    PORT
      LAYER Metal2 ;
        RECT  406.36 1749.6 406.76 1750 ;
    END
  END fault_valid_i
  PIN fcode_o[0]
    DIRECTION OUTPUT ;
    USE SIGNAL ;
    PORT
      LAYER Metal2 ;
        RECT  525.4 0 525.8 0.4 ;
    END
  END fcode_o[0]
  PIN fcode_o[1]
    DIRECTION OUTPUT ;
    USE SIGNAL ;
    PORT
      LAYER Metal2 ;
        RECT  526.36 0 526.76 0.4 ;
    END
  END fcode_o[1]
  PIN fcode_o[2]
    DIRECTION OUTPUT ;
    USE SIGNAL ;
    PORT
      LAYER Metal2 ;
        RECT  527.32 0 527.72 0.4 ;
    END
  END fcode_o[2]
  PIN fcode_o[3]
    DIRECTION OUTPUT ;
    USE SIGNAL ;
    PORT
      LAYER Metal2 ;
        RECT  528.28 0 528.68 0.4 ;
    END
  END fcode_o[3]
  PIN fcode_o[4]
    DIRECTION OUTPUT ;
    USE SIGNAL ;
    PORT
      LAYER Metal2 ;
        RECT  529.24 0 529.64 0.4 ;
    END
  END fcode_o[4]
  PIN fcode_o[5]
    DIRECTION OUTPUT ;
    USE SIGNAL ;
    PORT
      LAYER Metal2 ;
        RECT  530.2 0 530.6 0.4 ;
    END
  END fcode_o[5]
  PIN fcode_o[6]
    DIRECTION OUTPUT ;
    USE SIGNAL ;
    PORT
      LAYER Metal2 ;
        RECT  531.16 0 531.56 0.4 ;
    END
  END fcode_o[6]
  PIN fcode_o[7]
    DIRECTION OUTPUT ;
    USE SIGNAL ;
    PORT
      LAYER Metal2 ;
        RECT  532.12 0 532.52 0.4 ;
    END
  END fcode_o[7]
  PIN fpc_o[0]
    DIRECTION OUTPUT ;
    USE SIGNAL ;
    PORT
      LAYER Metal2 ;
        RECT  485.08 0 485.48 0.4 ;
    END
  END fpc_o[0]
  PIN fpc_o[10]
    DIRECTION OUTPUT ;
    USE SIGNAL ;
    PORT
      LAYER Metal2 ;
        RECT  494.68 0 495.08 0.4 ;
    END
  END fpc_o[10]
  PIN fpc_o[11]
    DIRECTION OUTPUT ;
    USE SIGNAL ;
    PORT
      LAYER Metal2 ;
        RECT  495.64 0 496.04 0.4 ;
    END
  END fpc_o[11]
  PIN fpc_o[12]
    DIRECTION OUTPUT ;
    USE SIGNAL ;
    PORT
      LAYER Metal2 ;
        RECT  496.6 0 497 0.4 ;
    END
  END fpc_o[12]
  PIN fpc_o[13]
    DIRECTION OUTPUT ;
    USE SIGNAL ;
    PORT
      LAYER Metal2 ;
        RECT  497.56 0 497.96 0.4 ;
    END
  END fpc_o[13]
  PIN fpc_o[14]
    DIRECTION OUTPUT ;
    USE SIGNAL ;
    PORT
      LAYER Metal2 ;
        RECT  498.52 0 498.92 0.4 ;
    END
  END fpc_o[14]
  PIN fpc_o[15]
    DIRECTION OUTPUT ;
    USE SIGNAL ;
    PORT
      LAYER Metal2 ;
        RECT  499.48 0 499.88 0.4 ;
    END
  END fpc_o[15]
  PIN fpc_o[16]
    DIRECTION OUTPUT ;
    USE SIGNAL ;
    PORT
      LAYER Metal2 ;
        RECT  500.44 0 500.84 0.4 ;
    END
  END fpc_o[16]
  PIN fpc_o[17]
    DIRECTION OUTPUT ;
    USE SIGNAL ;
    PORT
      LAYER Metal2 ;
        RECT  501.4 0 501.8 0.4 ;
    END
  END fpc_o[17]
  PIN fpc_o[18]
    DIRECTION OUTPUT ;
    USE SIGNAL ;
    PORT
      LAYER Metal2 ;
        RECT  502.36 0 502.76 0.4 ;
    END
  END fpc_o[18]
  PIN fpc_o[19]
    DIRECTION OUTPUT ;
    USE SIGNAL ;
    PORT
      LAYER Metal2 ;
        RECT  503.32 0 503.72 0.4 ;
    END
  END fpc_o[19]
  PIN fpc_o[1]
    DIRECTION OUTPUT ;
    USE SIGNAL ;
    PORT
      LAYER Metal2 ;
        RECT  486.04 0 486.44 0.4 ;
    END
  END fpc_o[1]
  PIN fpc_o[20]
    DIRECTION OUTPUT ;
    USE SIGNAL ;
    PORT
      LAYER Metal2 ;
        RECT  504.28 0 504.68 0.4 ;
    END
  END fpc_o[20]
  PIN fpc_o[21]
    DIRECTION OUTPUT ;
    USE SIGNAL ;
    PORT
      LAYER Metal2 ;
        RECT  505.24 0 505.64 0.4 ;
    END
  END fpc_o[21]
  PIN fpc_o[22]
    DIRECTION OUTPUT ;
    USE SIGNAL ;
    PORT
      LAYER Metal2 ;
        RECT  506.2 0 506.6 0.4 ;
    END
  END fpc_o[22]
  PIN fpc_o[23]
    DIRECTION OUTPUT ;
    USE SIGNAL ;
    PORT
      LAYER Metal2 ;
        RECT  507.16 0 507.56 0.4 ;
    END
  END fpc_o[23]
  PIN fpc_o[24]
    DIRECTION OUTPUT ;
    USE SIGNAL ;
    PORT
      LAYER Metal2 ;
        RECT  508.12 0 508.52 0.4 ;
    END
  END fpc_o[24]
  PIN fpc_o[25]
    DIRECTION OUTPUT ;
    USE SIGNAL ;
    PORT
      LAYER Metal2 ;
        RECT  509.08 0 509.48 0.4 ;
    END
  END fpc_o[25]
  PIN fpc_o[26]
    DIRECTION OUTPUT ;
    USE SIGNAL ;
    PORT
      LAYER Metal2 ;
        RECT  510.04 0 510.44 0.4 ;
    END
  END fpc_o[26]
  PIN fpc_o[27]
    DIRECTION OUTPUT ;
    USE SIGNAL ;
    PORT
      LAYER Metal2 ;
        RECT  511 0 511.4 0.4 ;
    END
  END fpc_o[27]
  PIN fpc_o[28]
    DIRECTION OUTPUT ;
    USE SIGNAL ;
    PORT
      LAYER Metal2 ;
        RECT  511.96 0 512.36 0.4 ;
    END
  END fpc_o[28]
  PIN fpc_o[29]
    DIRECTION OUTPUT ;
    USE SIGNAL ;
    PORT
      LAYER Metal2 ;
        RECT  512.92 0 513.32 0.4 ;
    END
  END fpc_o[29]
  PIN fpc_o[2]
    DIRECTION OUTPUT ;
    USE SIGNAL ;
    PORT
      LAYER Metal2 ;
        RECT  487 0 487.4 0.4 ;
    END
  END fpc_o[2]
  PIN fpc_o[30]
    DIRECTION OUTPUT ;
    USE SIGNAL ;
    PORT
      LAYER Metal2 ;
        RECT  513.88 0 514.28 0.4 ;
    END
  END fpc_o[30]
  PIN fpc_o[31]
    DIRECTION OUTPUT ;
    USE SIGNAL ;
    PORT
      LAYER Metal2 ;
        RECT  514.84 0 515.24 0.4 ;
    END
  END fpc_o[31]
  PIN fpc_o[3]
    DIRECTION OUTPUT ;
    USE SIGNAL ;
    PORT
      LAYER Metal2 ;
        RECT  487.96 0 488.36 0.4 ;
    END
  END fpc_o[3]
  PIN fpc_o[4]
    DIRECTION OUTPUT ;
    USE SIGNAL ;
    PORT
      LAYER Metal2 ;
        RECT  488.92 0 489.32 0.4 ;
    END
  END fpc_o[4]
  PIN fpc_o[5]
    DIRECTION OUTPUT ;
    USE SIGNAL ;
    PORT
      LAYER Metal2 ;
        RECT  489.88 0 490.28 0.4 ;
    END
  END fpc_o[5]
  PIN fpc_o[6]
    DIRECTION OUTPUT ;
    USE SIGNAL ;
    PORT
      LAYER Metal2 ;
        RECT  490.84 0 491.24 0.4 ;
    END
  END fpc_o[6]
  PIN fpc_o[7]
    DIRECTION OUTPUT ;
    USE SIGNAL ;
    PORT
      LAYER Metal2 ;
        RECT  491.8 0 492.2 0.4 ;
    END
  END fpc_o[7]
  PIN fpc_o[8]
    DIRECTION OUTPUT ;
    USE SIGNAL ;
    PORT
      LAYER Metal2 ;
        RECT  492.76 0 493.16 0.4 ;
    END
  END fpc_o[8]
  PIN fpc_o[9]
    DIRECTION OUTPUT ;
    USE SIGNAL ;
    PORT
      LAYER Metal2 ;
        RECT  493.72 0 494.12 0.4 ;
    END
  END fpc_o[9]
  PIN frame_dsp_i[0]
    DIRECTION INPUT ;
    USE SIGNAL ;
    PORT
      LAYER Metal3 ;
        RECT  0 590.74 0.4 591.14 ;
    END
  END frame_dsp_i[0]
  PIN frame_dsp_i[10]
    DIRECTION INPUT ;
    USE SIGNAL ;
    PORT
      LAYER Metal3 ;
        RECT  0 599.14 0.4 599.54 ;
    END
  END frame_dsp_i[10]
  PIN frame_dsp_i[11]
    DIRECTION INPUT ;
    USE SIGNAL ;
    PORT
      LAYER Metal3 ;
        RECT  0 599.98 0.4 600.38 ;
    END
  END frame_dsp_i[11]
  PIN frame_dsp_i[12]
    DIRECTION INPUT ;
    USE SIGNAL ;
    PORT
      LAYER Metal3 ;
        RECT  0 600.82 0.4 601.22 ;
    END
  END frame_dsp_i[12]
  PIN frame_dsp_i[13]
    DIRECTION INPUT ;
    USE SIGNAL ;
    PORT
      LAYER Metal3 ;
        RECT  0 601.66 0.4 602.06 ;
    END
  END frame_dsp_i[13]
  PIN frame_dsp_i[14]
    DIRECTION INPUT ;
    USE SIGNAL ;
    PORT
      LAYER Metal3 ;
        RECT  0 602.5 0.4 602.9 ;
    END
  END frame_dsp_i[14]
  PIN frame_dsp_i[15]
    DIRECTION INPUT ;
    USE SIGNAL ;
    PORT
      LAYER Metal3 ;
        RECT  0 603.34 0.4 603.74 ;
    END
  END frame_dsp_i[15]
  PIN frame_dsp_i[16]
    DIRECTION INPUT ;
    USE SIGNAL ;
    PORT
      LAYER Metal3 ;
        RECT  0 604.18 0.4 604.58 ;
    END
  END frame_dsp_i[16]
  PIN frame_dsp_i[17]
    DIRECTION INPUT ;
    USE SIGNAL ;
    PORT
      LAYER Metal3 ;
        RECT  0 605.02 0.4 605.42 ;
    END
  END frame_dsp_i[17]
  PIN frame_dsp_i[18]
    DIRECTION INPUT ;
    USE SIGNAL ;
    PORT
      LAYER Metal3 ;
        RECT  0 605.86 0.4 606.26 ;
    END
  END frame_dsp_i[18]
  PIN frame_dsp_i[19]
    DIRECTION INPUT ;
    USE SIGNAL ;
    PORT
      LAYER Metal3 ;
        RECT  0 606.7 0.4 607.1 ;
    END
  END frame_dsp_i[19]
  PIN frame_dsp_i[1]
    DIRECTION INPUT ;
    USE SIGNAL ;
    PORT
      LAYER Metal3 ;
        RECT  0 591.58 0.4 591.98 ;
    END
  END frame_dsp_i[1]
  PIN frame_dsp_i[20]
    DIRECTION INPUT ;
    USE SIGNAL ;
    PORT
      LAYER Metal3 ;
        RECT  0 607.54 0.4 607.94 ;
    END
  END frame_dsp_i[20]
  PIN frame_dsp_i[21]
    DIRECTION INPUT ;
    USE SIGNAL ;
    PORT
      LAYER Metal3 ;
        RECT  0 608.38 0.4 608.78 ;
    END
  END frame_dsp_i[21]
  PIN frame_dsp_i[22]
    DIRECTION INPUT ;
    USE SIGNAL ;
    PORT
      LAYER Metal3 ;
        RECT  0 609.22 0.4 609.62 ;
    END
  END frame_dsp_i[22]
  PIN frame_dsp_i[23]
    DIRECTION INPUT ;
    USE SIGNAL ;
    PORT
      LAYER Metal3 ;
        RECT  0 610.06 0.4 610.46 ;
    END
  END frame_dsp_i[23]
  PIN frame_dsp_i[24]
    DIRECTION INPUT ;
    USE SIGNAL ;
    PORT
      LAYER Metal3 ;
        RECT  0 610.9 0.4 611.3 ;
    END
  END frame_dsp_i[24]
  PIN frame_dsp_i[25]
    DIRECTION INPUT ;
    USE SIGNAL ;
    PORT
      LAYER Metal3 ;
        RECT  0 611.74 0.4 612.14 ;
    END
  END frame_dsp_i[25]
  PIN frame_dsp_i[26]
    DIRECTION INPUT ;
    USE SIGNAL ;
    PORT
      LAYER Metal3 ;
        RECT  0 612.58 0.4 612.98 ;
    END
  END frame_dsp_i[26]
  PIN frame_dsp_i[27]
    DIRECTION INPUT ;
    USE SIGNAL ;
    PORT
      LAYER Metal3 ;
        RECT  0 613.42 0.4 613.82 ;
    END
  END frame_dsp_i[27]
  PIN frame_dsp_i[28]
    DIRECTION INPUT ;
    USE SIGNAL ;
    PORT
      LAYER Metal3 ;
        RECT  0 614.26 0.4 614.66 ;
    END
  END frame_dsp_i[28]
  PIN frame_dsp_i[29]
    DIRECTION INPUT ;
    USE SIGNAL ;
    PORT
      LAYER Metal3 ;
        RECT  0 615.1 0.4 615.5 ;
    END
  END frame_dsp_i[29]
  PIN frame_dsp_i[2]
    DIRECTION INPUT ;
    USE SIGNAL ;
    PORT
      LAYER Metal3 ;
        RECT  0 592.42 0.4 592.82 ;
    END
  END frame_dsp_i[2]
  PIN frame_dsp_i[30]
    DIRECTION INPUT ;
    USE SIGNAL ;
    PORT
      LAYER Metal3 ;
        RECT  0 615.94 0.4 616.34 ;
    END
  END frame_dsp_i[30]
  PIN frame_dsp_i[31]
    DIRECTION INPUT ;
    USE SIGNAL ;
    PORT
      LAYER Metal3 ;
        RECT  0 616.78 0.4 617.18 ;
    END
  END frame_dsp_i[31]
  PIN frame_dsp_i[3]
    DIRECTION INPUT ;
    USE SIGNAL ;
    PORT
      LAYER Metal3 ;
        RECT  0 593.26 0.4 593.66 ;
    END
  END frame_dsp_i[3]
  PIN frame_dsp_i[4]
    DIRECTION INPUT ;
    USE SIGNAL ;
    PORT
      LAYER Metal3 ;
        RECT  0 594.1 0.4 594.5 ;
    END
  END frame_dsp_i[4]
  PIN frame_dsp_i[5]
    DIRECTION INPUT ;
    USE SIGNAL ;
    PORT
      LAYER Metal3 ;
        RECT  0 594.94 0.4 595.34 ;
    END
  END frame_dsp_i[5]
  PIN frame_dsp_i[6]
    DIRECTION INPUT ;
    USE SIGNAL ;
    PORT
      LAYER Metal3 ;
        RECT  0 595.78 0.4 596.18 ;
    END
  END frame_dsp_i[6]
  PIN frame_dsp_i[7]
    DIRECTION INPUT ;
    USE SIGNAL ;
    PORT
      LAYER Metal3 ;
        RECT  0 596.62 0.4 597.02 ;
    END
  END frame_dsp_i[7]
  PIN frame_dsp_i[8]
    DIRECTION INPUT ;
    USE SIGNAL ;
    PORT
      LAYER Metal3 ;
        RECT  0 597.46 0.4 597.86 ;
    END
  END frame_dsp_i[8]
  PIN frame_dsp_i[9]
    DIRECTION INPUT ;
    USE SIGNAL ;
    PORT
      LAYER Metal3 ;
        RECT  0 598.3 0.4 598.7 ;
    END
  END frame_dsp_i[9]
  PIN frame_rsp_i[0]
    DIRECTION INPUT ;
    USE SIGNAL ;
    PORT
      LAYER Metal3 ;
        RECT  0 513.46 0.4 513.86 ;
    END
  END frame_rsp_i[0]
  PIN frame_rsp_i[10]
    DIRECTION INPUT ;
    USE SIGNAL ;
    PORT
      LAYER Metal3 ;
        RECT  0 521.86 0.4 522.26 ;
    END
  END frame_rsp_i[10]
  PIN frame_rsp_i[11]
    DIRECTION INPUT ;
    USE SIGNAL ;
    PORT
      LAYER Metal3 ;
        RECT  0 522.7 0.4 523.1 ;
    END
  END frame_rsp_i[11]
  PIN frame_rsp_i[12]
    DIRECTION INPUT ;
    USE SIGNAL ;
    PORT
      LAYER Metal3 ;
        RECT  0 523.54 0.4 523.94 ;
    END
  END frame_rsp_i[12]
  PIN frame_rsp_i[13]
    DIRECTION INPUT ;
    USE SIGNAL ;
    PORT
      LAYER Metal3 ;
        RECT  0 524.38 0.4 524.78 ;
    END
  END frame_rsp_i[13]
  PIN frame_rsp_i[14]
    DIRECTION INPUT ;
    USE SIGNAL ;
    PORT
      LAYER Metal3 ;
        RECT  0 525.22 0.4 525.62 ;
    END
  END frame_rsp_i[14]
  PIN frame_rsp_i[15]
    DIRECTION INPUT ;
    USE SIGNAL ;
    PORT
      LAYER Metal3 ;
        RECT  0 526.06 0.4 526.46 ;
    END
  END frame_rsp_i[15]
  PIN frame_rsp_i[16]
    DIRECTION INPUT ;
    USE SIGNAL ;
    PORT
      LAYER Metal3 ;
        RECT  0 526.9 0.4 527.3 ;
    END
  END frame_rsp_i[16]
  PIN frame_rsp_i[17]
    DIRECTION INPUT ;
    USE SIGNAL ;
    PORT
      LAYER Metal3 ;
        RECT  0 527.74 0.4 528.14 ;
    END
  END frame_rsp_i[17]
  PIN frame_rsp_i[18]
    DIRECTION INPUT ;
    USE SIGNAL ;
    PORT
      LAYER Metal3 ;
        RECT  0 528.58 0.4 528.98 ;
    END
  END frame_rsp_i[18]
  PIN frame_rsp_i[19]
    DIRECTION INPUT ;
    USE SIGNAL ;
    PORT
      LAYER Metal3 ;
        RECT  0 529.42 0.4 529.82 ;
    END
  END frame_rsp_i[19]
  PIN frame_rsp_i[1]
    DIRECTION INPUT ;
    USE SIGNAL ;
    PORT
      LAYER Metal3 ;
        RECT  0 514.3 0.4 514.7 ;
    END
  END frame_rsp_i[1]
  PIN frame_rsp_i[20]
    DIRECTION INPUT ;
    USE SIGNAL ;
    PORT
      LAYER Metal3 ;
        RECT  0 530.26 0.4 530.66 ;
    END
  END frame_rsp_i[20]
  PIN frame_rsp_i[21]
    DIRECTION INPUT ;
    USE SIGNAL ;
    PORT
      LAYER Metal3 ;
        RECT  0 531.1 0.4 531.5 ;
    END
  END frame_rsp_i[21]
  PIN frame_rsp_i[22]
    DIRECTION INPUT ;
    USE SIGNAL ;
    PORT
      LAYER Metal3 ;
        RECT  0 531.94 0.4 532.34 ;
    END
  END frame_rsp_i[22]
  PIN frame_rsp_i[23]
    DIRECTION INPUT ;
    USE SIGNAL ;
    PORT
      LAYER Metal3 ;
        RECT  0 532.78 0.4 533.18 ;
    END
  END frame_rsp_i[23]
  PIN frame_rsp_i[24]
    DIRECTION INPUT ;
    USE SIGNAL ;
    PORT
      LAYER Metal3 ;
        RECT  0 533.62 0.4 534.02 ;
    END
  END frame_rsp_i[24]
  PIN frame_rsp_i[25]
    DIRECTION INPUT ;
    USE SIGNAL ;
    PORT
      LAYER Metal3 ;
        RECT  0 534.46 0.4 534.86 ;
    END
  END frame_rsp_i[25]
  PIN frame_rsp_i[26]
    DIRECTION INPUT ;
    USE SIGNAL ;
    PORT
      LAYER Metal3 ;
        RECT  0 535.3 0.4 535.7 ;
    END
  END frame_rsp_i[26]
  PIN frame_rsp_i[27]
    DIRECTION INPUT ;
    USE SIGNAL ;
    PORT
      LAYER Metal3 ;
        RECT  0 536.14 0.4 536.54 ;
    END
  END frame_rsp_i[27]
  PIN frame_rsp_i[28]
    DIRECTION INPUT ;
    USE SIGNAL ;
    PORT
      LAYER Metal3 ;
        RECT  0 536.98 0.4 537.38 ;
    END
  END frame_rsp_i[28]
  PIN frame_rsp_i[29]
    DIRECTION INPUT ;
    USE SIGNAL ;
    PORT
      LAYER Metal3 ;
        RECT  0 537.82 0.4 538.22 ;
    END
  END frame_rsp_i[29]
  PIN frame_rsp_i[2]
    DIRECTION INPUT ;
    USE SIGNAL ;
    PORT
      LAYER Metal3 ;
        RECT  0 515.14 0.4 515.54 ;
    END
  END frame_rsp_i[2]
  PIN frame_rsp_i[30]
    DIRECTION INPUT ;
    USE SIGNAL ;
    PORT
      LAYER Metal3 ;
        RECT  0 538.66 0.4 539.06 ;
    END
  END frame_rsp_i[30]
  PIN frame_rsp_i[31]
    DIRECTION INPUT ;
    USE SIGNAL ;
    PORT
      LAYER Metal3 ;
        RECT  0 539.5 0.4 539.9 ;
    END
  END frame_rsp_i[31]
  PIN frame_rsp_i[3]
    DIRECTION INPUT ;
    USE SIGNAL ;
    PORT
      LAYER Metal3 ;
        RECT  0 515.98 0.4 516.38 ;
    END
  END frame_rsp_i[3]
  PIN frame_rsp_i[4]
    DIRECTION INPUT ;
    USE SIGNAL ;
    PORT
      LAYER Metal3 ;
        RECT  0 516.82 0.4 517.22 ;
    END
  END frame_rsp_i[4]
  PIN frame_rsp_i[5]
    DIRECTION INPUT ;
    USE SIGNAL ;
    PORT
      LAYER Metal3 ;
        RECT  0 517.66 0.4 518.06 ;
    END
  END frame_rsp_i[5]
  PIN frame_rsp_i[6]
    DIRECTION INPUT ;
    USE SIGNAL ;
    PORT
      LAYER Metal3 ;
        RECT  0 518.5 0.4 518.9 ;
    END
  END frame_rsp_i[6]
  PIN frame_rsp_i[7]
    DIRECTION INPUT ;
    USE SIGNAL ;
    PORT
      LAYER Metal3 ;
        RECT  0 519.34 0.4 519.74 ;
    END
  END frame_rsp_i[7]
  PIN frame_rsp_i[8]
    DIRECTION INPUT ;
    USE SIGNAL ;
    PORT
      LAYER Metal3 ;
        RECT  0 520.18 0.4 520.58 ;
    END
  END frame_rsp_i[8]
  PIN frame_rsp_i[9]
    DIRECTION INPUT ;
    USE SIGNAL ;
    PORT
      LAYER Metal3 ;
        RECT  0 521.02 0.4 521.42 ;
    END
  END frame_rsp_i[9]
  PIN halt_cause_o[0]
    DIRECTION OUTPUT ;
    USE SIGNAL ;
    PORT
      LAYER Metal2 ;
        RECT  310.36 0 310.76 0.4 ;
    END
  END halt_cause_o[0]
  PIN halt_cause_o[1]
    DIRECTION OUTPUT ;
    USE SIGNAL ;
    PORT
      LAYER Metal2 ;
        RECT  311.32 0 311.72 0.4 ;
    END
  END halt_cause_o[1]
  PIN halt_cause_o[2]
    DIRECTION OUTPUT ;
    USE SIGNAL ;
    PORT
      LAYER Metal2 ;
        RECT  312.28 0 312.68 0.4 ;
    END
  END halt_cause_o[2]
  PIN halt_pc_o[0]
    DIRECTION OUTPUT ;
    USE SIGNAL ;
    PORT
      LAYER Metal2 ;
        RECT  373.72 0 374.12 0.4 ;
    END
  END halt_pc_o[0]
  PIN halt_pc_o[10]
    DIRECTION OUTPUT ;
    USE SIGNAL ;
    PORT
      LAYER Metal2 ;
        RECT  383.32 0 383.72 0.4 ;
    END
  END halt_pc_o[10]
  PIN halt_pc_o[11]
    DIRECTION OUTPUT ;
    USE SIGNAL ;
    PORT
      LAYER Metal2 ;
        RECT  384.28 0 384.68 0.4 ;
    END
  END halt_pc_o[11]
  PIN halt_pc_o[12]
    DIRECTION OUTPUT ;
    USE SIGNAL ;
    PORT
      LAYER Metal2 ;
        RECT  385.24 0 385.64 0.4 ;
    END
  END halt_pc_o[12]
  PIN halt_pc_o[13]
    DIRECTION OUTPUT ;
    USE SIGNAL ;
    PORT
      LAYER Metal2 ;
        RECT  386.2 0 386.6 0.4 ;
    END
  END halt_pc_o[13]
  PIN halt_pc_o[14]
    DIRECTION OUTPUT ;
    USE SIGNAL ;
    PORT
      LAYER Metal2 ;
        RECT  387.16 0 387.56 0.4 ;
    END
  END halt_pc_o[14]
  PIN halt_pc_o[15]
    DIRECTION OUTPUT ;
    USE SIGNAL ;
    PORT
      LAYER Metal2 ;
        RECT  388.12 0 388.52 0.4 ;
    END
  END halt_pc_o[15]
  PIN halt_pc_o[16]
    DIRECTION OUTPUT ;
    USE SIGNAL ;
    PORT
      LAYER Metal2 ;
        RECT  389.08 0 389.48 0.4 ;
    END
  END halt_pc_o[16]
  PIN halt_pc_o[17]
    DIRECTION OUTPUT ;
    USE SIGNAL ;
    PORT
      LAYER Metal2 ;
        RECT  390.04 0 390.44 0.4 ;
    END
  END halt_pc_o[17]
  PIN halt_pc_o[18]
    DIRECTION OUTPUT ;
    USE SIGNAL ;
    PORT
      LAYER Metal2 ;
        RECT  391 0 391.4 0.4 ;
    END
  END halt_pc_o[18]
  PIN halt_pc_o[19]
    DIRECTION OUTPUT ;
    USE SIGNAL ;
    PORT
      LAYER Metal2 ;
        RECT  391.96 0 392.36 0.4 ;
    END
  END halt_pc_o[19]
  PIN halt_pc_o[1]
    DIRECTION OUTPUT ;
    USE SIGNAL ;
    PORT
      LAYER Metal2 ;
        RECT  374.68 0 375.08 0.4 ;
    END
  END halt_pc_o[1]
  PIN halt_pc_o[20]
    DIRECTION OUTPUT ;
    USE SIGNAL ;
    PORT
      LAYER Metal2 ;
        RECT  392.92 0 393.32 0.4 ;
    END
  END halt_pc_o[20]
  PIN halt_pc_o[21]
    DIRECTION OUTPUT ;
    USE SIGNAL ;
    PORT
      LAYER Metal2 ;
        RECT  393.88 0 394.28 0.4 ;
    END
  END halt_pc_o[21]
  PIN halt_pc_o[22]
    DIRECTION OUTPUT ;
    USE SIGNAL ;
    PORT
      LAYER Metal2 ;
        RECT  394.84 0 395.24 0.4 ;
    END
  END halt_pc_o[22]
  PIN halt_pc_o[23]
    DIRECTION OUTPUT ;
    USE SIGNAL ;
    PORT
      LAYER Metal2 ;
        RECT  395.8 0 396.2 0.4 ;
    END
  END halt_pc_o[23]
  PIN halt_pc_o[24]
    DIRECTION OUTPUT ;
    USE SIGNAL ;
    PORT
      LAYER Metal2 ;
        RECT  396.76 0 397.16 0.4 ;
    END
  END halt_pc_o[24]
  PIN halt_pc_o[25]
    DIRECTION OUTPUT ;
    USE SIGNAL ;
    PORT
      LAYER Metal2 ;
        RECT  397.72 0 398.12 0.4 ;
    END
  END halt_pc_o[25]
  PIN halt_pc_o[26]
    DIRECTION OUTPUT ;
    USE SIGNAL ;
    PORT
      LAYER Metal2 ;
        RECT  398.68 0 399.08 0.4 ;
    END
  END halt_pc_o[26]
  PIN halt_pc_o[27]
    DIRECTION OUTPUT ;
    USE SIGNAL ;
    PORT
      LAYER Metal2 ;
        RECT  399.64 0 400.04 0.4 ;
    END
  END halt_pc_o[27]
  PIN halt_pc_o[28]
    DIRECTION OUTPUT ;
    USE SIGNAL ;
    PORT
      LAYER Metal2 ;
        RECT  400.6 0 401 0.4 ;
    END
  END halt_pc_o[28]
  PIN halt_pc_o[29]
    DIRECTION OUTPUT ;
    USE SIGNAL ;
    PORT
      LAYER Metal2 ;
        RECT  401.56 0 401.96 0.4 ;
    END
  END halt_pc_o[29]
  PIN halt_pc_o[2]
    DIRECTION OUTPUT ;
    USE SIGNAL ;
    PORT
      LAYER Metal2 ;
        RECT  375.64 0 376.04 0.4 ;
    END
  END halt_pc_o[2]
  PIN halt_pc_o[30]
    DIRECTION OUTPUT ;
    USE SIGNAL ;
    PORT
      LAYER Metal2 ;
        RECT  402.52 0 402.92 0.4 ;
    END
  END halt_pc_o[30]
  PIN halt_pc_o[31]
    DIRECTION OUTPUT ;
    USE SIGNAL ;
    PORT
      LAYER Metal2 ;
        RECT  403.48 0 403.88 0.4 ;
    END
  END halt_pc_o[31]
  PIN halt_pc_o[3]
    DIRECTION OUTPUT ;
    USE SIGNAL ;
    PORT
      LAYER Metal2 ;
        RECT  376.6 0 377 0.4 ;
    END
  END halt_pc_o[3]
  PIN halt_pc_o[4]
    DIRECTION OUTPUT ;
    USE SIGNAL ;
    PORT
      LAYER Metal2 ;
        RECT  377.56 0 377.96 0.4 ;
    END
  END halt_pc_o[4]
  PIN halt_pc_o[5]
    DIRECTION OUTPUT ;
    USE SIGNAL ;
    PORT
      LAYER Metal2 ;
        RECT  378.52 0 378.92 0.4 ;
    END
  END halt_pc_o[5]
  PIN halt_pc_o[6]
    DIRECTION OUTPUT ;
    USE SIGNAL ;
    PORT
      LAYER Metal2 ;
        RECT  379.48 0 379.88 0.4 ;
    END
  END halt_pc_o[6]
  PIN halt_pc_o[7]
    DIRECTION OUTPUT ;
    USE SIGNAL ;
    PORT
      LAYER Metal2 ;
        RECT  380.44 0 380.84 0.4 ;
    END
  END halt_pc_o[7]
  PIN halt_pc_o[8]
    DIRECTION OUTPUT ;
    USE SIGNAL ;
    PORT
      LAYER Metal2 ;
        RECT  381.4 0 381.8 0.4 ;
    END
  END halt_pc_o[8]
  PIN halt_pc_o[9]
    DIRECTION OUTPUT ;
    USE SIGNAL ;
    PORT
      LAYER Metal2 ;
        RECT  382.36 0 382.76 0.4 ;
    END
  END halt_pc_o[9]
  PIN halt_req_i
    DIRECTION INPUT ;
    USE SIGNAL ;
    PORT
      LAYER Metal2 ;
        RECT  289.24 0 289.64 0.4 ;
    END
  END halt_req_i
  PIN halted_o
    DIRECTION OUTPUT ;
    USE SIGNAL ;
    PORT
      LAYER Metal2 ;
        RECT  299.8 0 300.2 0.4 ;
    END
  END halted_o
  PIN irq_ack_code_o[0]
    DIRECTION OUTPUT ;
    USE SIGNAL ;
    PORT
      LAYER Metal2 ;
        RECT  271.96 0 272.36 0.4 ;
    END
  END irq_ack_code_o[0]
  PIN irq_ack_code_o[1]
    DIRECTION OUTPUT ;
    USE SIGNAL ;
    PORT
      LAYER Metal2 ;
        RECT  272.92 0 273.32 0.4 ;
    END
  END irq_ack_code_o[1]
  PIN irq_ack_code_o[2]
    DIRECTION OUTPUT ;
    USE SIGNAL ;
    PORT
      LAYER Metal2 ;
        RECT  273.88 0 274.28 0.4 ;
    END
  END irq_ack_code_o[2]
  PIN irq_ack_code_o[3]
    DIRECTION OUTPUT ;
    USE SIGNAL ;
    PORT
      LAYER Metal2 ;
        RECT  274.84 0 275.24 0.4 ;
    END
  END irq_ack_code_o[3]
  PIN irq_ack_code_o[4]
    DIRECTION OUTPUT ;
    USE SIGNAL ;
    PORT
      LAYER Metal2 ;
        RECT  275.8 0 276.2 0.4 ;
    END
  END irq_ack_code_o[4]
  PIN irq_ack_code_o[5]
    DIRECTION OUTPUT ;
    USE SIGNAL ;
    PORT
      LAYER Metal2 ;
        RECT  276.76 0 277.16 0.4 ;
    END
  END irq_ack_code_o[5]
  PIN irq_ack_code_o[6]
    DIRECTION OUTPUT ;
    USE SIGNAL ;
    PORT
      LAYER Metal2 ;
        RECT  277.72 0 278.12 0.4 ;
    END
  END irq_ack_code_o[6]
  PIN irq_ack_code_o[7]
    DIRECTION OUTPUT ;
    USE SIGNAL ;
    PORT
      LAYER Metal2 ;
        RECT  278.68 0 279.08 0.4 ;
    END
  END irq_ack_code_o[7]
  PIN irq_ack_o
    DIRECTION OUTPUT ;
    USE SIGNAL ;
    PORT
      LAYER Metal2 ;
        RECT  261.4 0 261.8 0.4 ;
    END
  END irq_ack_o
  PIN irq_pending_i[0]
    DIRECTION INPUT ;
    USE SIGNAL ;
    PORT
      LAYER Metal2 ;
        RECT  221.08 0 221.48 0.4 ;
    END
  END irq_pending_i[0]
  PIN irq_pending_i[10]
    DIRECTION INPUT ;
    USE SIGNAL ;
    PORT
      LAYER Metal2 ;
        RECT  230.68 0 231.08 0.4 ;
    END
  END irq_pending_i[10]
  PIN irq_pending_i[11]
    DIRECTION INPUT ;
    USE SIGNAL ;
    PORT
      LAYER Metal2 ;
        RECT  231.64 0 232.04 0.4 ;
    END
  END irq_pending_i[11]
  PIN irq_pending_i[12]
    DIRECTION INPUT ;
    USE SIGNAL ;
    PORT
      LAYER Metal2 ;
        RECT  232.6 0 233 0.4 ;
    END
  END irq_pending_i[12]
  PIN irq_pending_i[13]
    DIRECTION INPUT ;
    USE SIGNAL ;
    PORT
      LAYER Metal2 ;
        RECT  233.56 0 233.96 0.4 ;
    END
  END irq_pending_i[13]
  PIN irq_pending_i[14]
    DIRECTION INPUT ;
    USE SIGNAL ;
    PORT
      LAYER Metal2 ;
        RECT  234.52 0 234.92 0.4 ;
    END
  END irq_pending_i[14]
  PIN irq_pending_i[15]
    DIRECTION INPUT ;
    USE SIGNAL ;
    PORT
      LAYER Metal2 ;
        RECT  235.48 0 235.88 0.4 ;
    END
  END irq_pending_i[15]
  PIN irq_pending_i[16]
    DIRECTION INPUT ;
    USE SIGNAL ;
    PORT
      LAYER Metal2 ;
        RECT  236.44 0 236.84 0.4 ;
    END
  END irq_pending_i[16]
  PIN irq_pending_i[17]
    DIRECTION INPUT ;
    USE SIGNAL ;
    PORT
      LAYER Metal2 ;
        RECT  237.4 0 237.8 0.4 ;
    END
  END irq_pending_i[17]
  PIN irq_pending_i[18]
    DIRECTION INPUT ;
    USE SIGNAL ;
    PORT
      LAYER Metal2 ;
        RECT  238.36 0 238.76 0.4 ;
    END
  END irq_pending_i[18]
  PIN irq_pending_i[19]
    DIRECTION INPUT ;
    USE SIGNAL ;
    PORT
      LAYER Metal2 ;
        RECT  239.32 0 239.72 0.4 ;
    END
  END irq_pending_i[19]
  PIN irq_pending_i[1]
    DIRECTION INPUT ;
    USE SIGNAL ;
    PORT
      LAYER Metal2 ;
        RECT  222.04 0 222.44 0.4 ;
    END
  END irq_pending_i[1]
  PIN irq_pending_i[20]
    DIRECTION INPUT ;
    USE SIGNAL ;
    PORT
      LAYER Metal2 ;
        RECT  240.28 0 240.68 0.4 ;
    END
  END irq_pending_i[20]
  PIN irq_pending_i[21]
    DIRECTION INPUT ;
    USE SIGNAL ;
    PORT
      LAYER Metal2 ;
        RECT  241.24 0 241.64 0.4 ;
    END
  END irq_pending_i[21]
  PIN irq_pending_i[22]
    DIRECTION INPUT ;
    USE SIGNAL ;
    PORT
      LAYER Metal2 ;
        RECT  242.2 0 242.6 0.4 ;
    END
  END irq_pending_i[22]
  PIN irq_pending_i[23]
    DIRECTION INPUT ;
    USE SIGNAL ;
    PORT
      LAYER Metal2 ;
        RECT  243.16 0 243.56 0.4 ;
    END
  END irq_pending_i[23]
  PIN irq_pending_i[24]
    DIRECTION INPUT ;
    USE SIGNAL ;
    PORT
      LAYER Metal2 ;
        RECT  244.12 0 244.52 0.4 ;
    END
  END irq_pending_i[24]
  PIN irq_pending_i[25]
    DIRECTION INPUT ;
    USE SIGNAL ;
    PORT
      LAYER Metal2 ;
        RECT  245.08 0 245.48 0.4 ;
    END
  END irq_pending_i[25]
  PIN irq_pending_i[26]
    DIRECTION INPUT ;
    USE SIGNAL ;
    PORT
      LAYER Metal2 ;
        RECT  246.04 0 246.44 0.4 ;
    END
  END irq_pending_i[26]
  PIN irq_pending_i[27]
    DIRECTION INPUT ;
    USE SIGNAL ;
    PORT
      LAYER Metal2 ;
        RECT  247 0 247.4 0.4 ;
    END
  END irq_pending_i[27]
  PIN irq_pending_i[28]
    DIRECTION INPUT ;
    USE SIGNAL ;
    PORT
      LAYER Metal2 ;
        RECT  247.96 0 248.36 0.4 ;
    END
  END irq_pending_i[28]
  PIN irq_pending_i[29]
    DIRECTION INPUT ;
    USE SIGNAL ;
    PORT
      LAYER Metal2 ;
        RECT  248.92 0 249.32 0.4 ;
    END
  END irq_pending_i[29]
  PIN irq_pending_i[2]
    DIRECTION INPUT ;
    USE SIGNAL ;
    PORT
      LAYER Metal2 ;
        RECT  223 0 223.4 0.4 ;
    END
  END irq_pending_i[2]
  PIN irq_pending_i[30]
    DIRECTION INPUT ;
    USE SIGNAL ;
    PORT
      LAYER Metal2 ;
        RECT  249.88 0 250.28 0.4 ;
    END
  END irq_pending_i[30]
  PIN irq_pending_i[31]
    DIRECTION INPUT ;
    USE SIGNAL ;
    PORT
      LAYER Metal2 ;
        RECT  250.84 0 251.24 0.4 ;
    END
  END irq_pending_i[31]
  PIN irq_pending_i[3]
    DIRECTION INPUT ;
    USE SIGNAL ;
    PORT
      LAYER Metal2 ;
        RECT  223.96 0 224.36 0.4 ;
    END
  END irq_pending_i[3]
  PIN irq_pending_i[4]
    DIRECTION INPUT ;
    USE SIGNAL ;
    PORT
      LAYER Metal2 ;
        RECT  224.92 0 225.32 0.4 ;
    END
  END irq_pending_i[4]
  PIN irq_pending_i[5]
    DIRECTION INPUT ;
    USE SIGNAL ;
    PORT
      LAYER Metal2 ;
        RECT  225.88 0 226.28 0.4 ;
    END
  END irq_pending_i[5]
  PIN irq_pending_i[6]
    DIRECTION INPUT ;
    USE SIGNAL ;
    PORT
      LAYER Metal2 ;
        RECT  226.84 0 227.24 0.4 ;
    END
  END irq_pending_i[6]
  PIN irq_pending_i[7]
    DIRECTION INPUT ;
    USE SIGNAL ;
    PORT
      LAYER Metal2 ;
        RECT  227.8 0 228.2 0.4 ;
    END
  END irq_pending_i[7]
  PIN irq_pending_i[8]
    DIRECTION INPUT ;
    USE SIGNAL ;
    PORT
      LAYER Metal2 ;
        RECT  228.76 0 229.16 0.4 ;
    END
  END irq_pending_i[8]
  PIN irq_pending_i[9]
    DIRECTION INPUT ;
    USE SIGNAL ;
    PORT
      LAYER Metal2 ;
        RECT  229.72 0 230.12 0.4 ;
    END
  END irq_pending_i[9]
  PIN issue_i.len[0]
    DIRECTION INPUT ;
    USE SIGNAL ;
    PORT
      LAYER Metal3 ;
        RECT  0 1387.06 0.4 1387.46 ;
    END
  END issue_i.len[0]
  PIN issue_i.len[1]
    DIRECTION INPUT ;
    USE SIGNAL ;
    PORT
      LAYER Metal3 ;
        RECT  0 1391.26 0.4 1391.66 ;
    END
  END issue_i.len[1]
  PIN issue_i.len[2]
    DIRECTION INPUT ;
    USE SIGNAL ;
    PORT
      LAYER Metal3 ;
        RECT  0 1395.46 0.4 1395.86 ;
    END
  END issue_i.len[2]
  PIN issue_i.len[3]
    DIRECTION INPUT ;
    USE SIGNAL ;
    PORT
      LAYER Metal3 ;
        RECT  0 1399.66 0.4 1400.06 ;
    END
  END issue_i.len[3]
  PIN issue_i.op[0]
    DIRECTION INPUT ;
    USE SIGNAL ;
    PORT
      LAYER Metal3 ;
        RECT  0 1387.9 0.4 1388.3 ;
    END
  END issue_i.op[0]
  PIN issue_i.op[1]
    DIRECTION INPUT ;
    USE SIGNAL ;
    PORT
      LAYER Metal3 ;
        RECT  0 1392.1 0.4 1392.5 ;
    END
  END issue_i.op[1]
  PIN issue_i.op[2]
    DIRECTION INPUT ;
    USE SIGNAL ;
    PORT
      LAYER Metal3 ;
        RECT  0 1396.3 0.4 1396.7 ;
    END
  END issue_i.op[2]
  PIN issue_i.op[3]
    DIRECTION INPUT ;
    USE SIGNAL ;
    PORT
      LAYER Metal3 ;
        RECT  0 1400.5 0.4 1400.9 ;
    END
  END issue_i.op[3]
  PIN issue_i.op[4]
    DIRECTION INPUT ;
    USE SIGNAL ;
    PORT
      LAYER Metal3 ;
        RECT  0 1403.86 0.4 1404.26 ;
    END
  END issue_i.op[4]
  PIN issue_i.op[5]
    DIRECTION INPUT ;
    USE SIGNAL ;
    PORT
      LAYER Metal3 ;
        RECT  0 1407.22 0.4 1407.62 ;
    END
  END issue_i.op[5]
  PIN issue_i.op[6]
    DIRECTION INPUT ;
    USE SIGNAL ;
    PORT
      LAYER Metal3 ;
        RECT  0 1410.58 0.4 1410.98 ;
    END
  END issue_i.op[6]
  PIN issue_i.op[7]
    DIRECTION INPUT ;
    USE SIGNAL ;
    PORT
      LAYER Metal3 ;
        RECT  0 1413.94 0.4 1414.34 ;
    END
  END issue_i.op[7]
  PIN issue_i.operand0[0]
    DIRECTION INPUT ;
    USE SIGNAL ;
    PORT
      LAYER Metal3 ;
        RECT  0 1388.74 0.4 1389.14 ;
    END
  END issue_i.operand0[0]
  PIN issue_i.operand0[10]
    DIRECTION INPUT ;
    USE SIGNAL ;
    PORT
      LAYER Metal3 ;
        RECT  0 1422.34 0.4 1422.74 ;
    END
  END issue_i.operand0[10]
  PIN issue_i.operand0[11]
    DIRECTION INPUT ;
    USE SIGNAL ;
    PORT
      LAYER Metal3 ;
        RECT  0 1424.86 0.4 1425.26 ;
    END
  END issue_i.operand0[11]
  PIN issue_i.operand0[12]
    DIRECTION INPUT ;
    USE SIGNAL ;
    PORT
      LAYER Metal3 ;
        RECT  0 1427.38 0.4 1427.78 ;
    END
  END issue_i.operand0[12]
  PIN issue_i.operand0[13]
    DIRECTION INPUT ;
    USE SIGNAL ;
    PORT
      LAYER Metal3 ;
        RECT  0 1429.9 0.4 1430.3 ;
    END
  END issue_i.operand0[13]
  PIN issue_i.operand0[14]
    DIRECTION INPUT ;
    USE SIGNAL ;
    PORT
      LAYER Metal3 ;
        RECT  0 1432.42 0.4 1432.82 ;
    END
  END issue_i.operand0[14]
  PIN issue_i.operand0[15]
    DIRECTION INPUT ;
    USE SIGNAL ;
    PORT
      LAYER Metal3 ;
        RECT  0 1434.94 0.4 1435.34 ;
    END
  END issue_i.operand0[15]
  PIN issue_i.operand0[16]
    DIRECTION INPUT ;
    USE SIGNAL ;
    PORT
      LAYER Metal3 ;
        RECT  0 1437.46 0.4 1437.86 ;
    END
  END issue_i.operand0[16]
  PIN issue_i.operand0[17]
    DIRECTION INPUT ;
    USE SIGNAL ;
    PORT
      LAYER Metal3 ;
        RECT  0 1439.98 0.4 1440.38 ;
    END
  END issue_i.operand0[17]
  PIN issue_i.operand0[18]
    DIRECTION INPUT ;
    USE SIGNAL ;
    PORT
      LAYER Metal3 ;
        RECT  0 1442.5 0.4 1442.9 ;
    END
  END issue_i.operand0[18]
  PIN issue_i.operand0[19]
    DIRECTION INPUT ;
    USE SIGNAL ;
    PORT
      LAYER Metal3 ;
        RECT  0 1445.02 0.4 1445.42 ;
    END
  END issue_i.operand0[19]
  PIN issue_i.operand0[1]
    DIRECTION INPUT ;
    USE SIGNAL ;
    PORT
      LAYER Metal3 ;
        RECT  0 1392.94 0.4 1393.34 ;
    END
  END issue_i.operand0[1]
  PIN issue_i.operand0[20]
    DIRECTION INPUT ;
    USE SIGNAL ;
    PORT
      LAYER Metal3 ;
        RECT  0 1447.54 0.4 1447.94 ;
    END
  END issue_i.operand0[20]
  PIN issue_i.operand0[21]
    DIRECTION INPUT ;
    USE SIGNAL ;
    PORT
      LAYER Metal3 ;
        RECT  0 1450.06 0.4 1450.46 ;
    END
  END issue_i.operand0[21]
  PIN issue_i.operand0[22]
    DIRECTION INPUT ;
    USE SIGNAL ;
    PORT
      LAYER Metal3 ;
        RECT  0 1452.58 0.4 1452.98 ;
    END
  END issue_i.operand0[22]
  PIN issue_i.operand0[23]
    DIRECTION INPUT ;
    USE SIGNAL ;
    PORT
      LAYER Metal3 ;
        RECT  0 1455.1 0.4 1455.5 ;
    END
  END issue_i.operand0[23]
  PIN issue_i.operand0[24]
    DIRECTION INPUT ;
    USE SIGNAL ;
    PORT
      LAYER Metal3 ;
        RECT  0 1457.62 0.4 1458.02 ;
    END
  END issue_i.operand0[24]
  PIN issue_i.operand0[25]
    DIRECTION INPUT ;
    USE SIGNAL ;
    PORT
      LAYER Metal3 ;
        RECT  0 1460.14 0.4 1460.54 ;
    END
  END issue_i.operand0[25]
  PIN issue_i.operand0[26]
    DIRECTION INPUT ;
    USE SIGNAL ;
    PORT
      LAYER Metal3 ;
        RECT  0 1462.66 0.4 1463.06 ;
    END
  END issue_i.operand0[26]
  PIN issue_i.operand0[27]
    DIRECTION INPUT ;
    USE SIGNAL ;
    PORT
      LAYER Metal3 ;
        RECT  0 1465.18 0.4 1465.58 ;
    END
  END issue_i.operand0[27]
  PIN issue_i.operand0[28]
    DIRECTION INPUT ;
    USE SIGNAL ;
    PORT
      LAYER Metal3 ;
        RECT  0 1467.7 0.4 1468.1 ;
    END
  END issue_i.operand0[28]
  PIN issue_i.operand0[29]
    DIRECTION INPUT ;
    USE SIGNAL ;
    PORT
      LAYER Metal3 ;
        RECT  0 1470.22 0.4 1470.62 ;
    END
  END issue_i.operand0[29]
  PIN issue_i.operand0[2]
    DIRECTION INPUT ;
    USE SIGNAL ;
    PORT
      LAYER Metal3 ;
        RECT  0 1397.14 0.4 1397.54 ;
    END
  END issue_i.operand0[2]
  PIN issue_i.operand0[30]
    DIRECTION INPUT ;
    USE SIGNAL ;
    PORT
      LAYER Metal3 ;
        RECT  0 1472.74 0.4 1473.14 ;
    END
  END issue_i.operand0[30]
  PIN issue_i.operand0[31]
    DIRECTION INPUT ;
    USE SIGNAL ;
    PORT
      LAYER Metal3 ;
        RECT  0 1475.26 0.4 1475.66 ;
    END
  END issue_i.operand0[31]
  PIN issue_i.operand0[32]
    DIRECTION INPUT ;
    USE SIGNAL ;
    PORT
      LAYER Metal3 ;
        RECT  0 1477.78 0.4 1478.18 ;
    END
  END issue_i.operand0[32]
  PIN issue_i.operand0[33]
    DIRECTION INPUT ;
    USE SIGNAL ;
    PORT
      LAYER Metal3 ;
        RECT  0 1478.62 0.4 1479.02 ;
    END
  END issue_i.operand0[33]
  PIN issue_i.operand0[34]
    DIRECTION INPUT ;
    USE SIGNAL ;
    PORT
      LAYER Metal3 ;
        RECT  0 1479.46 0.4 1479.86 ;
    END
  END issue_i.operand0[34]
  PIN issue_i.operand0[35]
    DIRECTION INPUT ;
    USE SIGNAL ;
    PORT
      LAYER Metal3 ;
        RECT  0 1480.3 0.4 1480.7 ;
    END
  END issue_i.operand0[35]
  PIN issue_i.operand0[36]
    DIRECTION INPUT ;
    USE SIGNAL ;
    PORT
      LAYER Metal3 ;
        RECT  0 1481.14 0.4 1481.54 ;
    END
  END issue_i.operand0[36]
  PIN issue_i.operand0[37]
    DIRECTION INPUT ;
    USE SIGNAL ;
    PORT
      LAYER Metal3 ;
        RECT  0 1481.98 0.4 1482.38 ;
    END
  END issue_i.operand0[37]
  PIN issue_i.operand0[38]
    DIRECTION INPUT ;
    USE SIGNAL ;
    PORT
      LAYER Metal3 ;
        RECT  0 1482.82 0.4 1483.22 ;
    END
  END issue_i.operand0[38]
  PIN issue_i.operand0[39]
    DIRECTION INPUT ;
    USE SIGNAL ;
    PORT
      LAYER Metal3 ;
        RECT  0 1483.66 0.4 1484.06 ;
    END
  END issue_i.operand0[39]
  PIN issue_i.operand0[3]
    DIRECTION INPUT ;
    USE SIGNAL ;
    PORT
      LAYER Metal3 ;
        RECT  0 1401.34 0.4 1401.74 ;
    END
  END issue_i.operand0[3]
  PIN issue_i.operand0[40]
    DIRECTION INPUT ;
    USE SIGNAL ;
    PORT
      LAYER Metal3 ;
        RECT  0 1484.5 0.4 1484.9 ;
    END
  END issue_i.operand0[40]
  PIN issue_i.operand0[41]
    DIRECTION INPUT ;
    USE SIGNAL ;
    PORT
      LAYER Metal3 ;
        RECT  0 1485.34 0.4 1485.74 ;
    END
  END issue_i.operand0[41]
  PIN issue_i.operand0[42]
    DIRECTION INPUT ;
    USE SIGNAL ;
    PORT
      LAYER Metal3 ;
        RECT  0 1486.18 0.4 1486.58 ;
    END
  END issue_i.operand0[42]
  PIN issue_i.operand0[43]
    DIRECTION INPUT ;
    USE SIGNAL ;
    PORT
      LAYER Metal3 ;
        RECT  0 1487.02 0.4 1487.42 ;
    END
  END issue_i.operand0[43]
  PIN issue_i.operand0[44]
    DIRECTION INPUT ;
    USE SIGNAL ;
    PORT
      LAYER Metal3 ;
        RECT  0 1487.86 0.4 1488.26 ;
    END
  END issue_i.operand0[44]
  PIN issue_i.operand0[45]
    DIRECTION INPUT ;
    USE SIGNAL ;
    PORT
      LAYER Metal3 ;
        RECT  0 1488.7 0.4 1489.1 ;
    END
  END issue_i.operand0[45]
  PIN issue_i.operand0[46]
    DIRECTION INPUT ;
    USE SIGNAL ;
    PORT
      LAYER Metal3 ;
        RECT  0 1489.54 0.4 1489.94 ;
    END
  END issue_i.operand0[46]
  PIN issue_i.operand0[47]
    DIRECTION INPUT ;
    USE SIGNAL ;
    PORT
      LAYER Metal3 ;
        RECT  0 1490.38 0.4 1490.78 ;
    END
  END issue_i.operand0[47]
  PIN issue_i.operand0[48]
    DIRECTION INPUT ;
    USE SIGNAL ;
    PORT
      LAYER Metal3 ;
        RECT  0 1491.22 0.4 1491.62 ;
    END
  END issue_i.operand0[48]
  PIN issue_i.operand0[49]
    DIRECTION INPUT ;
    USE SIGNAL ;
    PORT
      LAYER Metal3 ;
        RECT  0 1492.06 0.4 1492.46 ;
    END
  END issue_i.operand0[49]
  PIN issue_i.operand0[4]
    DIRECTION INPUT ;
    USE SIGNAL ;
    PORT
      LAYER Metal3 ;
        RECT  0 1404.7 0.4 1405.1 ;
    END
  END issue_i.operand0[4]
  PIN issue_i.operand0[50]
    DIRECTION INPUT ;
    USE SIGNAL ;
    PORT
      LAYER Metal3 ;
        RECT  0 1492.9 0.4 1493.3 ;
    END
  END issue_i.operand0[50]
  PIN issue_i.operand0[51]
    DIRECTION INPUT ;
    USE SIGNAL ;
    PORT
      LAYER Metal3 ;
        RECT  0 1493.74 0.4 1494.14 ;
    END
  END issue_i.operand0[51]
  PIN issue_i.operand0[52]
    DIRECTION INPUT ;
    USE SIGNAL ;
    PORT
      LAYER Metal3 ;
        RECT  0 1494.58 0.4 1494.98 ;
    END
  END issue_i.operand0[52]
  PIN issue_i.operand0[53]
    DIRECTION INPUT ;
    USE SIGNAL ;
    PORT
      LAYER Metal3 ;
        RECT  0 1495.42 0.4 1495.82 ;
    END
  END issue_i.operand0[53]
  PIN issue_i.operand0[54]
    DIRECTION INPUT ;
    USE SIGNAL ;
    PORT
      LAYER Metal3 ;
        RECT  0 1496.26 0.4 1496.66 ;
    END
  END issue_i.operand0[54]
  PIN issue_i.operand0[55]
    DIRECTION INPUT ;
    USE SIGNAL ;
    PORT
      LAYER Metal3 ;
        RECT  0 1497.1 0.4 1497.5 ;
    END
  END issue_i.operand0[55]
  PIN issue_i.operand0[56]
    DIRECTION INPUT ;
    USE SIGNAL ;
    PORT
      LAYER Metal3 ;
        RECT  0 1497.94 0.4 1498.34 ;
    END
  END issue_i.operand0[56]
  PIN issue_i.operand0[57]
    DIRECTION INPUT ;
    USE SIGNAL ;
    PORT
      LAYER Metal3 ;
        RECT  0 1498.78 0.4 1499.18 ;
    END
  END issue_i.operand0[57]
  PIN issue_i.operand0[58]
    DIRECTION INPUT ;
    USE SIGNAL ;
    PORT
      LAYER Metal3 ;
        RECT  0 1499.62 0.4 1500.02 ;
    END
  END issue_i.operand0[58]
  PIN issue_i.operand0[59]
    DIRECTION INPUT ;
    USE SIGNAL ;
    PORT
      LAYER Metal3 ;
        RECT  0 1500.46 0.4 1500.86 ;
    END
  END issue_i.operand0[59]
  PIN issue_i.operand0[5]
    DIRECTION INPUT ;
    USE SIGNAL ;
    PORT
      LAYER Metal3 ;
        RECT  0 1408.06 0.4 1408.46 ;
    END
  END issue_i.operand0[5]
  PIN issue_i.operand0[60]
    DIRECTION INPUT ;
    USE SIGNAL ;
    PORT
      LAYER Metal3 ;
        RECT  0 1501.3 0.4 1501.7 ;
    END
  END issue_i.operand0[60]
  PIN issue_i.operand0[61]
    DIRECTION INPUT ;
    USE SIGNAL ;
    PORT
      LAYER Metal3 ;
        RECT  0 1502.14 0.4 1502.54 ;
    END
  END issue_i.operand0[61]
  PIN issue_i.operand0[62]
    DIRECTION INPUT ;
    USE SIGNAL ;
    PORT
      LAYER Metal3 ;
        RECT  0 1502.98 0.4 1503.38 ;
    END
  END issue_i.operand0[62]
  PIN issue_i.operand0[63]
    DIRECTION INPUT ;
    USE SIGNAL ;
    PORT
      LAYER Metal3 ;
        RECT  0 1503.82 0.4 1504.22 ;
    END
  END issue_i.operand0[63]
  PIN issue_i.operand0[6]
    DIRECTION INPUT ;
    USE SIGNAL ;
    PORT
      LAYER Metal3 ;
        RECT  0 1411.42 0.4 1411.82 ;
    END
  END issue_i.operand0[6]
  PIN issue_i.operand0[7]
    DIRECTION INPUT ;
    USE SIGNAL ;
    PORT
      LAYER Metal3 ;
        RECT  0 1414.78 0.4 1415.18 ;
    END
  END issue_i.operand0[7]
  PIN issue_i.operand0[8]
    DIRECTION INPUT ;
    USE SIGNAL ;
    PORT
      LAYER Metal3 ;
        RECT  0 1417.3 0.4 1417.7 ;
    END
  END issue_i.operand0[8]
  PIN issue_i.operand0[9]
    DIRECTION INPUT ;
    USE SIGNAL ;
    PORT
      LAYER Metal3 ;
        RECT  0 1419.82 0.4 1420.22 ;
    END
  END issue_i.operand0[9]
  PIN issue_i.pc[0]
    DIRECTION INPUT ;
    USE SIGNAL ;
    PORT
      LAYER Metal3 ;
        RECT  0 1389.58 0.4 1389.98 ;
    END
  END issue_i.pc[0]
  PIN issue_i.pc[10]
    DIRECTION INPUT ;
    USE SIGNAL ;
    PORT
      LAYER Metal3 ;
        RECT  0 1423.18 0.4 1423.58 ;
    END
  END issue_i.pc[10]
  PIN issue_i.pc[11]
    DIRECTION INPUT ;
    USE SIGNAL ;
    PORT
      LAYER Metal3 ;
        RECT  0 1425.7 0.4 1426.1 ;
    END
  END issue_i.pc[11]
  PIN issue_i.pc[12]
    DIRECTION INPUT ;
    USE SIGNAL ;
    PORT
      LAYER Metal3 ;
        RECT  0 1428.22 0.4 1428.62 ;
    END
  END issue_i.pc[12]
  PIN issue_i.pc[13]
    DIRECTION INPUT ;
    USE SIGNAL ;
    PORT
      LAYER Metal3 ;
        RECT  0 1430.74 0.4 1431.14 ;
    END
  END issue_i.pc[13]
  PIN issue_i.pc[14]
    DIRECTION INPUT ;
    USE SIGNAL ;
    PORT
      LAYER Metal3 ;
        RECT  0 1433.26 0.4 1433.66 ;
    END
  END issue_i.pc[14]
  PIN issue_i.pc[15]
    DIRECTION INPUT ;
    USE SIGNAL ;
    PORT
      LAYER Metal3 ;
        RECT  0 1435.78 0.4 1436.18 ;
    END
  END issue_i.pc[15]
  PIN issue_i.pc[16]
    DIRECTION INPUT ;
    USE SIGNAL ;
    PORT
      LAYER Metal3 ;
        RECT  0 1438.3 0.4 1438.7 ;
    END
  END issue_i.pc[16]
  PIN issue_i.pc[17]
    DIRECTION INPUT ;
    USE SIGNAL ;
    PORT
      LAYER Metal3 ;
        RECT  0 1440.82 0.4 1441.22 ;
    END
  END issue_i.pc[17]
  PIN issue_i.pc[18]
    DIRECTION INPUT ;
    USE SIGNAL ;
    PORT
      LAYER Metal3 ;
        RECT  0 1443.34 0.4 1443.74 ;
    END
  END issue_i.pc[18]
  PIN issue_i.pc[19]
    DIRECTION INPUT ;
    USE SIGNAL ;
    PORT
      LAYER Metal3 ;
        RECT  0 1445.86 0.4 1446.26 ;
    END
  END issue_i.pc[19]
  PIN issue_i.pc[1]
    DIRECTION INPUT ;
    USE SIGNAL ;
    PORT
      LAYER Metal3 ;
        RECT  0 1393.78 0.4 1394.18 ;
    END
  END issue_i.pc[1]
  PIN issue_i.pc[20]
    DIRECTION INPUT ;
    USE SIGNAL ;
    PORT
      LAYER Metal3 ;
        RECT  0 1448.38 0.4 1448.78 ;
    END
  END issue_i.pc[20]
  PIN issue_i.pc[21]
    DIRECTION INPUT ;
    USE SIGNAL ;
    PORT
      LAYER Metal3 ;
        RECT  0 1450.9 0.4 1451.3 ;
    END
  END issue_i.pc[21]
  PIN issue_i.pc[22]
    DIRECTION INPUT ;
    USE SIGNAL ;
    PORT
      LAYER Metal3 ;
        RECT  0 1453.42 0.4 1453.82 ;
    END
  END issue_i.pc[22]
  PIN issue_i.pc[23]
    DIRECTION INPUT ;
    USE SIGNAL ;
    PORT
      LAYER Metal3 ;
        RECT  0 1455.94 0.4 1456.34 ;
    END
  END issue_i.pc[23]
  PIN issue_i.pc[24]
    DIRECTION INPUT ;
    USE SIGNAL ;
    PORT
      LAYER Metal3 ;
        RECT  0 1458.46 0.4 1458.86 ;
    END
  END issue_i.pc[24]
  PIN issue_i.pc[25]
    DIRECTION INPUT ;
    USE SIGNAL ;
    PORT
      LAYER Metal3 ;
        RECT  0 1460.98 0.4 1461.38 ;
    END
  END issue_i.pc[25]
  PIN issue_i.pc[26]
    DIRECTION INPUT ;
    USE SIGNAL ;
    PORT
      LAYER Metal3 ;
        RECT  0 1463.5 0.4 1463.9 ;
    END
  END issue_i.pc[26]
  PIN issue_i.pc[27]
    DIRECTION INPUT ;
    USE SIGNAL ;
    PORT
      LAYER Metal3 ;
        RECT  0 1466.02 0.4 1466.42 ;
    END
  END issue_i.pc[27]
  PIN issue_i.pc[28]
    DIRECTION INPUT ;
    USE SIGNAL ;
    PORT
      LAYER Metal3 ;
        RECT  0 1468.54 0.4 1468.94 ;
    END
  END issue_i.pc[28]
  PIN issue_i.pc[29]
    DIRECTION INPUT ;
    USE SIGNAL ;
    PORT
      LAYER Metal3 ;
        RECT  0 1471.06 0.4 1471.46 ;
    END
  END issue_i.pc[29]
  PIN issue_i.pc[2]
    DIRECTION INPUT ;
    USE SIGNAL ;
    PORT
      LAYER Metal3 ;
        RECT  0 1397.98 0.4 1398.38 ;
    END
  END issue_i.pc[2]
  PIN issue_i.pc[30]
    DIRECTION INPUT ;
    USE SIGNAL ;
    PORT
      LAYER Metal3 ;
        RECT  0 1473.58 0.4 1473.98 ;
    END
  END issue_i.pc[30]
  PIN issue_i.pc[31]
    DIRECTION INPUT ;
    USE SIGNAL ;
    PORT
      LAYER Metal3 ;
        RECT  0 1476.1 0.4 1476.5 ;
    END
  END issue_i.pc[31]
  PIN issue_i.pc[3]
    DIRECTION INPUT ;
    USE SIGNAL ;
    PORT
      LAYER Metal3 ;
        RECT  0 1402.18 0.4 1402.58 ;
    END
  END issue_i.pc[3]
  PIN issue_i.pc[4]
    DIRECTION INPUT ;
    USE SIGNAL ;
    PORT
      LAYER Metal3 ;
        RECT  0 1405.54 0.4 1405.94 ;
    END
  END issue_i.pc[4]
  PIN issue_i.pc[5]
    DIRECTION INPUT ;
    USE SIGNAL ;
    PORT
      LAYER Metal3 ;
        RECT  0 1408.9 0.4 1409.3 ;
    END
  END issue_i.pc[5]
  PIN issue_i.pc[6]
    DIRECTION INPUT ;
    USE SIGNAL ;
    PORT
      LAYER Metal3 ;
        RECT  0 1412.26 0.4 1412.66 ;
    END
  END issue_i.pc[6]
  PIN issue_i.pc[7]
    DIRECTION INPUT ;
    USE SIGNAL ;
    PORT
      LAYER Metal3 ;
        RECT  0 1415.62 0.4 1416.02 ;
    END
  END issue_i.pc[7]
  PIN issue_i.pc[8]
    DIRECTION INPUT ;
    USE SIGNAL ;
    PORT
      LAYER Metal3 ;
        RECT  0 1418.14 0.4 1418.54 ;
    END
  END issue_i.pc[8]
  PIN issue_i.pc[9]
    DIRECTION INPUT ;
    USE SIGNAL ;
    PORT
      LAYER Metal3 ;
        RECT  0 1420.66 0.4 1421.06 ;
    END
  END issue_i.pc[9]
  PIN issue_i.val[0]
    DIRECTION INPUT ;
    USE SIGNAL ;
    PORT
      LAYER Metal3 ;
        RECT  0 1390.42 0.4 1390.82 ;
    END
  END issue_i.val[0]
  PIN issue_i.val[10]
    DIRECTION INPUT ;
    USE SIGNAL ;
    PORT
      LAYER Metal3 ;
        RECT  0 1424.02 0.4 1424.42 ;
    END
  END issue_i.val[10]
  PIN issue_i.val[11]
    DIRECTION INPUT ;
    USE SIGNAL ;
    PORT
      LAYER Metal3 ;
        RECT  0 1426.54 0.4 1426.94 ;
    END
  END issue_i.val[11]
  PIN issue_i.val[12]
    DIRECTION INPUT ;
    USE SIGNAL ;
    PORT
      LAYER Metal3 ;
        RECT  0 1429.06 0.4 1429.46 ;
    END
  END issue_i.val[12]
  PIN issue_i.val[13]
    DIRECTION INPUT ;
    USE SIGNAL ;
    PORT
      LAYER Metal3 ;
        RECT  0 1431.58 0.4 1431.98 ;
    END
  END issue_i.val[13]
  PIN issue_i.val[14]
    DIRECTION INPUT ;
    USE SIGNAL ;
    PORT
      LAYER Metal3 ;
        RECT  0 1434.1 0.4 1434.5 ;
    END
  END issue_i.val[14]
  PIN issue_i.val[15]
    DIRECTION INPUT ;
    USE SIGNAL ;
    PORT
      LAYER Metal3 ;
        RECT  0 1436.62 0.4 1437.02 ;
    END
  END issue_i.val[15]
  PIN issue_i.val[16]
    DIRECTION INPUT ;
    USE SIGNAL ;
    PORT
      LAYER Metal3 ;
        RECT  0 1439.14 0.4 1439.54 ;
    END
  END issue_i.val[16]
  PIN issue_i.val[17]
    DIRECTION INPUT ;
    USE SIGNAL ;
    PORT
      LAYER Metal3 ;
        RECT  0 1441.66 0.4 1442.06 ;
    END
  END issue_i.val[17]
  PIN issue_i.val[18]
    DIRECTION INPUT ;
    USE SIGNAL ;
    PORT
      LAYER Metal3 ;
        RECT  0 1444.18 0.4 1444.58 ;
    END
  END issue_i.val[18]
  PIN issue_i.val[19]
    DIRECTION INPUT ;
    USE SIGNAL ;
    PORT
      LAYER Metal3 ;
        RECT  0 1446.7 0.4 1447.1 ;
    END
  END issue_i.val[19]
  PIN issue_i.val[1]
    DIRECTION INPUT ;
    USE SIGNAL ;
    PORT
      LAYER Metal3 ;
        RECT  0 1394.62 0.4 1395.02 ;
    END
  END issue_i.val[1]
  PIN issue_i.val[20]
    DIRECTION INPUT ;
    USE SIGNAL ;
    PORT
      LAYER Metal3 ;
        RECT  0 1449.22 0.4 1449.62 ;
    END
  END issue_i.val[20]
  PIN issue_i.val[21]
    DIRECTION INPUT ;
    USE SIGNAL ;
    PORT
      LAYER Metal3 ;
        RECT  0 1451.74 0.4 1452.14 ;
    END
  END issue_i.val[21]
  PIN issue_i.val[22]
    DIRECTION INPUT ;
    USE SIGNAL ;
    PORT
      LAYER Metal3 ;
        RECT  0 1454.26 0.4 1454.66 ;
    END
  END issue_i.val[22]
  PIN issue_i.val[23]
    DIRECTION INPUT ;
    USE SIGNAL ;
    PORT
      LAYER Metal3 ;
        RECT  0 1456.78 0.4 1457.18 ;
    END
  END issue_i.val[23]
  PIN issue_i.val[24]
    DIRECTION INPUT ;
    USE SIGNAL ;
    PORT
      LAYER Metal3 ;
        RECT  0 1459.3 0.4 1459.7 ;
    END
  END issue_i.val[24]
  PIN issue_i.val[25]
    DIRECTION INPUT ;
    USE SIGNAL ;
    PORT
      LAYER Metal3 ;
        RECT  0 1461.82 0.4 1462.22 ;
    END
  END issue_i.val[25]
  PIN issue_i.val[26]
    DIRECTION INPUT ;
    USE SIGNAL ;
    PORT
      LAYER Metal3 ;
        RECT  0 1464.34 0.4 1464.74 ;
    END
  END issue_i.val[26]
  PIN issue_i.val[27]
    DIRECTION INPUT ;
    USE SIGNAL ;
    PORT
      LAYER Metal3 ;
        RECT  0 1466.86 0.4 1467.26 ;
    END
  END issue_i.val[27]
  PIN issue_i.val[28]
    DIRECTION INPUT ;
    USE SIGNAL ;
    PORT
      LAYER Metal3 ;
        RECT  0 1469.38 0.4 1469.78 ;
    END
  END issue_i.val[28]
  PIN issue_i.val[29]
    DIRECTION INPUT ;
    USE SIGNAL ;
    PORT
      LAYER Metal3 ;
        RECT  0 1471.9 0.4 1472.3 ;
    END
  END issue_i.val[29]
  PIN issue_i.val[2]
    DIRECTION INPUT ;
    USE SIGNAL ;
    PORT
      LAYER Metal3 ;
        RECT  0 1398.82 0.4 1399.22 ;
    END
  END issue_i.val[2]
  PIN issue_i.val[30]
    DIRECTION INPUT ;
    USE SIGNAL ;
    PORT
      LAYER Metal3 ;
        RECT  0 1474.42 0.4 1474.82 ;
    END
  END issue_i.val[30]
  PIN issue_i.val[31]
    DIRECTION INPUT ;
    USE SIGNAL ;
    PORT
      LAYER Metal3 ;
        RECT  0 1476.94 0.4 1477.34 ;
    END
  END issue_i.val[31]
  PIN issue_i.val[3]
    DIRECTION INPUT ;
    USE SIGNAL ;
    PORT
      LAYER Metal3 ;
        RECT  0 1403.02 0.4 1403.42 ;
    END
  END issue_i.val[3]
  PIN issue_i.val[4]
    DIRECTION INPUT ;
    USE SIGNAL ;
    PORT
      LAYER Metal3 ;
        RECT  0 1406.38 0.4 1406.78 ;
    END
  END issue_i.val[4]
  PIN issue_i.val[5]
    DIRECTION INPUT ;
    USE SIGNAL ;
    PORT
      LAYER Metal3 ;
        RECT  0 1409.74 0.4 1410.14 ;
    END
  END issue_i.val[5]
  PIN issue_i.val[6]
    DIRECTION INPUT ;
    USE SIGNAL ;
    PORT
      LAYER Metal3 ;
        RECT  0 1413.1 0.4 1413.5 ;
    END
  END issue_i.val[6]
  PIN issue_i.val[7]
    DIRECTION INPUT ;
    USE SIGNAL ;
    PORT
      LAYER Metal3 ;
        RECT  0 1416.46 0.4 1416.86 ;
    END
  END issue_i.val[7]
  PIN issue_i.val[8]
    DIRECTION INPUT ;
    USE SIGNAL ;
    PORT
      LAYER Metal3 ;
        RECT  0 1418.98 0.4 1419.38 ;
    END
  END issue_i.val[8]
  PIN issue_i.val[9]
    DIRECTION INPUT ;
    USE SIGNAL ;
    PORT
      LAYER Metal3 ;
        RECT  0 1421.5 0.4 1421.9 ;
    END
  END issue_i.val[9]
  PIN issue_ready_o
    DIRECTION OUTPUT ;
    USE SIGNAL ;
    PORT
      LAYER Metal3 ;
        RECT  0 1525.66 0.4 1526.06 ;
    END
  END issue_ready_o
  PIN issue_valid_i
    DIRECTION INPUT ;
    USE SIGNAL ;
    PORT
      LAYER Metal3 ;
        RECT  0 1514.74 0.4 1515.14 ;
    END
  END issue_valid_i
  PIN limits_o.lim_csp[0]
    DIRECTION OUTPUT ;
    USE SIGNAL ;
    PORT
      LAYER Metal3 ;
        RECT  0 668.02 0.4 668.42 ;
    END
  END limits_o.lim_csp[0]
  PIN limits_o.lim_csp[10]
    DIRECTION OUTPUT ;
    USE SIGNAL ;
    PORT
      LAYER Metal3 ;
        RECT  0 701.62 0.4 702.02 ;
    END
  END limits_o.lim_csp[10]
  PIN limits_o.lim_csp[11]
    DIRECTION OUTPUT ;
    USE SIGNAL ;
    PORT
      LAYER Metal3 ;
        RECT  0 704.98 0.4 705.38 ;
    END
  END limits_o.lim_csp[11]
  PIN limits_o.lim_csp[12]
    DIRECTION OUTPUT ;
    USE SIGNAL ;
    PORT
      LAYER Metal3 ;
        RECT  0 708.34 0.4 708.74 ;
    END
  END limits_o.lim_csp[12]
  PIN limits_o.lim_csp[13]
    DIRECTION OUTPUT ;
    USE SIGNAL ;
    PORT
      LAYER Metal3 ;
        RECT  0 711.7 0.4 712.1 ;
    END
  END limits_o.lim_csp[13]
  PIN limits_o.lim_csp[14]
    DIRECTION OUTPUT ;
    USE SIGNAL ;
    PORT
      LAYER Metal3 ;
        RECT  0 715.06 0.4 715.46 ;
    END
  END limits_o.lim_csp[14]
  PIN limits_o.lim_csp[15]
    DIRECTION OUTPUT ;
    USE SIGNAL ;
    PORT
      LAYER Metal3 ;
        RECT  0 718.42 0.4 718.82 ;
    END
  END limits_o.lim_csp[15]
  PIN limits_o.lim_csp[16]
    DIRECTION OUTPUT ;
    USE SIGNAL ;
    PORT
      LAYER Metal3 ;
        RECT  0 721.78 0.4 722.18 ;
    END
  END limits_o.lim_csp[16]
  PIN limits_o.lim_csp[17]
    DIRECTION OUTPUT ;
    USE SIGNAL ;
    PORT
      LAYER Metal3 ;
        RECT  0 725.14 0.4 725.54 ;
    END
  END limits_o.lim_csp[17]
  PIN limits_o.lim_csp[18]
    DIRECTION OUTPUT ;
    USE SIGNAL ;
    PORT
      LAYER Metal3 ;
        RECT  0 728.5 0.4 728.9 ;
    END
  END limits_o.lim_csp[18]
  PIN limits_o.lim_csp[19]
    DIRECTION OUTPUT ;
    USE SIGNAL ;
    PORT
      LAYER Metal3 ;
        RECT  0 731.86 0.4 732.26 ;
    END
  END limits_o.lim_csp[19]
  PIN limits_o.lim_csp[1]
    DIRECTION OUTPUT ;
    USE SIGNAL ;
    PORT
      LAYER Metal3 ;
        RECT  0 671.38 0.4 671.78 ;
    END
  END limits_o.lim_csp[1]
  PIN limits_o.lim_csp[20]
    DIRECTION OUTPUT ;
    USE SIGNAL ;
    PORT
      LAYER Metal3 ;
        RECT  0 735.22 0.4 735.62 ;
    END
  END limits_o.lim_csp[20]
  PIN limits_o.lim_csp[21]
    DIRECTION OUTPUT ;
    USE SIGNAL ;
    PORT
      LAYER Metal3 ;
        RECT  0 738.58 0.4 738.98 ;
    END
  END limits_o.lim_csp[21]
  PIN limits_o.lim_csp[22]
    DIRECTION OUTPUT ;
    USE SIGNAL ;
    PORT
      LAYER Metal3 ;
        RECT  0 741.94 0.4 742.34 ;
    END
  END limits_o.lim_csp[22]
  PIN limits_o.lim_csp[23]
    DIRECTION OUTPUT ;
    USE SIGNAL ;
    PORT
      LAYER Metal3 ;
        RECT  0 745.3 0.4 745.7 ;
    END
  END limits_o.lim_csp[23]
  PIN limits_o.lim_csp[24]
    DIRECTION OUTPUT ;
    USE SIGNAL ;
    PORT
      LAYER Metal3 ;
        RECT  0 748.66 0.4 749.06 ;
    END
  END limits_o.lim_csp[24]
  PIN limits_o.lim_csp[25]
    DIRECTION OUTPUT ;
    USE SIGNAL ;
    PORT
      LAYER Metal3 ;
        RECT  0 752.02 0.4 752.42 ;
    END
  END limits_o.lim_csp[25]
  PIN limits_o.lim_csp[26]
    DIRECTION OUTPUT ;
    USE SIGNAL ;
    PORT
      LAYER Metal3 ;
        RECT  0 755.38 0.4 755.78 ;
    END
  END limits_o.lim_csp[26]
  PIN limits_o.lim_csp[27]
    DIRECTION OUTPUT ;
    USE SIGNAL ;
    PORT
      LAYER Metal3 ;
        RECT  0 758.74 0.4 759.14 ;
    END
  END limits_o.lim_csp[27]
  PIN limits_o.lim_csp[28]
    DIRECTION OUTPUT ;
    USE SIGNAL ;
    PORT
      LAYER Metal3 ;
        RECT  0 762.1 0.4 762.5 ;
    END
  END limits_o.lim_csp[28]
  PIN limits_o.lim_csp[29]
    DIRECTION OUTPUT ;
    USE SIGNAL ;
    PORT
      LAYER Metal3 ;
        RECT  0 765.46 0.4 765.86 ;
    END
  END limits_o.lim_csp[29]
  PIN limits_o.lim_csp[2]
    DIRECTION OUTPUT ;
    USE SIGNAL ;
    PORT
      LAYER Metal3 ;
        RECT  0 674.74 0.4 675.14 ;
    END
  END limits_o.lim_csp[2]
  PIN limits_o.lim_csp[30]
    DIRECTION OUTPUT ;
    USE SIGNAL ;
    PORT
      LAYER Metal3 ;
        RECT  0 768.82 0.4 769.22 ;
    END
  END limits_o.lim_csp[30]
  PIN limits_o.lim_csp[31]
    DIRECTION OUTPUT ;
    USE SIGNAL ;
    PORT
      LAYER Metal3 ;
        RECT  0 772.18 0.4 772.58 ;
    END
  END limits_o.lim_csp[31]
  PIN limits_o.lim_csp[32]
    DIRECTION OUTPUT ;
    USE SIGNAL ;
    PORT
      LAYER Metal3 ;
        RECT  0 775.54 0.4 775.94 ;
    END
  END limits_o.lim_csp[32]
  PIN limits_o.lim_csp[33]
    DIRECTION OUTPUT ;
    USE SIGNAL ;
    PORT
      LAYER Metal3 ;
        RECT  0 778.9 0.4 779.3 ;
    END
  END limits_o.lim_csp[33]
  PIN limits_o.lim_csp[34]
    DIRECTION OUTPUT ;
    USE SIGNAL ;
    PORT
      LAYER Metal3 ;
        RECT  0 782.26 0.4 782.66 ;
    END
  END limits_o.lim_csp[34]
  PIN limits_o.lim_csp[35]
    DIRECTION OUTPUT ;
    USE SIGNAL ;
    PORT
      LAYER Metal3 ;
        RECT  0 785.62 0.4 786.02 ;
    END
  END limits_o.lim_csp[35]
  PIN limits_o.lim_csp[36]
    DIRECTION OUTPUT ;
    USE SIGNAL ;
    PORT
      LAYER Metal3 ;
        RECT  0 788.98 0.4 789.38 ;
    END
  END limits_o.lim_csp[36]
  PIN limits_o.lim_csp[37]
    DIRECTION OUTPUT ;
    USE SIGNAL ;
    PORT
      LAYER Metal3 ;
        RECT  0 792.34 0.4 792.74 ;
    END
  END limits_o.lim_csp[37]
  PIN limits_o.lim_csp[38]
    DIRECTION OUTPUT ;
    USE SIGNAL ;
    PORT
      LAYER Metal3 ;
        RECT  0 795.7 0.4 796.1 ;
    END
  END limits_o.lim_csp[38]
  PIN limits_o.lim_csp[39]
    DIRECTION OUTPUT ;
    USE SIGNAL ;
    PORT
      LAYER Metal3 ;
        RECT  0 799.06 0.4 799.46 ;
    END
  END limits_o.lim_csp[39]
  PIN limits_o.lim_csp[3]
    DIRECTION OUTPUT ;
    USE SIGNAL ;
    PORT
      LAYER Metal3 ;
        RECT  0 678.1 0.4 678.5 ;
    END
  END limits_o.lim_csp[3]
  PIN limits_o.lim_csp[40]
    DIRECTION OUTPUT ;
    USE SIGNAL ;
    PORT
      LAYER Metal3 ;
        RECT  0 802.42 0.4 802.82 ;
    END
  END limits_o.lim_csp[40]
  PIN limits_o.lim_csp[41]
    DIRECTION OUTPUT ;
    USE SIGNAL ;
    PORT
      LAYER Metal3 ;
        RECT  0 805.78 0.4 806.18 ;
    END
  END limits_o.lim_csp[41]
  PIN limits_o.lim_csp[42]
    DIRECTION OUTPUT ;
    USE SIGNAL ;
    PORT
      LAYER Metal3 ;
        RECT  0 809.14 0.4 809.54 ;
    END
  END limits_o.lim_csp[42]
  PIN limits_o.lim_csp[43]
    DIRECTION OUTPUT ;
    USE SIGNAL ;
    PORT
      LAYER Metal3 ;
        RECT  0 812.5 0.4 812.9 ;
    END
  END limits_o.lim_csp[43]
  PIN limits_o.lim_csp[44]
    DIRECTION OUTPUT ;
    USE SIGNAL ;
    PORT
      LAYER Metal3 ;
        RECT  0 815.86 0.4 816.26 ;
    END
  END limits_o.lim_csp[44]
  PIN limits_o.lim_csp[45]
    DIRECTION OUTPUT ;
    USE SIGNAL ;
    PORT
      LAYER Metal3 ;
        RECT  0 819.22 0.4 819.62 ;
    END
  END limits_o.lim_csp[45]
  PIN limits_o.lim_csp[46]
    DIRECTION OUTPUT ;
    USE SIGNAL ;
    PORT
      LAYER Metal3 ;
        RECT  0 822.58 0.4 822.98 ;
    END
  END limits_o.lim_csp[46]
  PIN limits_o.lim_csp[47]
    DIRECTION OUTPUT ;
    USE SIGNAL ;
    PORT
      LAYER Metal3 ;
        RECT  0 825.94 0.4 826.34 ;
    END
  END limits_o.lim_csp[47]
  PIN limits_o.lim_csp[48]
    DIRECTION OUTPUT ;
    USE SIGNAL ;
    PORT
      LAYER Metal3 ;
        RECT  0 829.3 0.4 829.7 ;
    END
  END limits_o.lim_csp[48]
  PIN limits_o.lim_csp[49]
    DIRECTION OUTPUT ;
    USE SIGNAL ;
    PORT
      LAYER Metal3 ;
        RECT  0 832.66 0.4 833.06 ;
    END
  END limits_o.lim_csp[49]
  PIN limits_o.lim_csp[4]
    DIRECTION OUTPUT ;
    USE SIGNAL ;
    PORT
      LAYER Metal3 ;
        RECT  0 681.46 0.4 681.86 ;
    END
  END limits_o.lim_csp[4]
  PIN limits_o.lim_csp[50]
    DIRECTION OUTPUT ;
    USE SIGNAL ;
    PORT
      LAYER Metal3 ;
        RECT  0 836.02 0.4 836.42 ;
    END
  END limits_o.lim_csp[50]
  PIN limits_o.lim_csp[51]
    DIRECTION OUTPUT ;
    USE SIGNAL ;
    PORT
      LAYER Metal3 ;
        RECT  0 839.38 0.4 839.78 ;
    END
  END limits_o.lim_csp[51]
  PIN limits_o.lim_csp[52]
    DIRECTION OUTPUT ;
    USE SIGNAL ;
    PORT
      LAYER Metal3 ;
        RECT  0 842.74 0.4 843.14 ;
    END
  END limits_o.lim_csp[52]
  PIN limits_o.lim_csp[53]
    DIRECTION OUTPUT ;
    USE SIGNAL ;
    PORT
      LAYER Metal3 ;
        RECT  0 846.1 0.4 846.5 ;
    END
  END limits_o.lim_csp[53]
  PIN limits_o.lim_csp[54]
    DIRECTION OUTPUT ;
    USE SIGNAL ;
    PORT
      LAYER Metal3 ;
        RECT  0 849.46 0.4 849.86 ;
    END
  END limits_o.lim_csp[54]
  PIN limits_o.lim_csp[55]
    DIRECTION OUTPUT ;
    USE SIGNAL ;
    PORT
      LAYER Metal3 ;
        RECT  0 852.82 0.4 853.22 ;
    END
  END limits_o.lim_csp[55]
  PIN limits_o.lim_csp[56]
    DIRECTION OUTPUT ;
    USE SIGNAL ;
    PORT
      LAYER Metal3 ;
        RECT  0 856.18 0.4 856.58 ;
    END
  END limits_o.lim_csp[56]
  PIN limits_o.lim_csp[57]
    DIRECTION OUTPUT ;
    USE SIGNAL ;
    PORT
      LAYER Metal3 ;
        RECT  0 859.54 0.4 859.94 ;
    END
  END limits_o.lim_csp[57]
  PIN limits_o.lim_csp[58]
    DIRECTION OUTPUT ;
    USE SIGNAL ;
    PORT
      LAYER Metal3 ;
        RECT  0 862.9 0.4 863.3 ;
    END
  END limits_o.lim_csp[58]
  PIN limits_o.lim_csp[59]
    DIRECTION OUTPUT ;
    USE SIGNAL ;
    PORT
      LAYER Metal3 ;
        RECT  0 866.26 0.4 866.66 ;
    END
  END limits_o.lim_csp[59]
  PIN limits_o.lim_csp[5]
    DIRECTION OUTPUT ;
    USE SIGNAL ;
    PORT
      LAYER Metal3 ;
        RECT  0 684.82 0.4 685.22 ;
    END
  END limits_o.lim_csp[5]
  PIN limits_o.lim_csp[60]
    DIRECTION OUTPUT ;
    USE SIGNAL ;
    PORT
      LAYER Metal3 ;
        RECT  0 869.62 0.4 870.02 ;
    END
  END limits_o.lim_csp[60]
  PIN limits_o.lim_csp[61]
    DIRECTION OUTPUT ;
    USE SIGNAL ;
    PORT
      LAYER Metal3 ;
        RECT  0 872.98 0.4 873.38 ;
    END
  END limits_o.lim_csp[61]
  PIN limits_o.lim_csp[62]
    DIRECTION OUTPUT ;
    USE SIGNAL ;
    PORT
      LAYER Metal3 ;
        RECT  0 876.34 0.4 876.74 ;
    END
  END limits_o.lim_csp[62]
  PIN limits_o.lim_csp[63]
    DIRECTION OUTPUT ;
    USE SIGNAL ;
    PORT
      LAYER Metal3 ;
        RECT  0 879.7 0.4 880.1 ;
    END
  END limits_o.lim_csp[63]
  PIN limits_o.lim_csp[6]
    DIRECTION OUTPUT ;
    USE SIGNAL ;
    PORT
      LAYER Metal3 ;
        RECT  0 688.18 0.4 688.58 ;
    END
  END limits_o.lim_csp[6]
  PIN limits_o.lim_csp[7]
    DIRECTION OUTPUT ;
    USE SIGNAL ;
    PORT
      LAYER Metal3 ;
        RECT  0 691.54 0.4 691.94 ;
    END
  END limits_o.lim_csp[7]
  PIN limits_o.lim_csp[8]
    DIRECTION OUTPUT ;
    USE SIGNAL ;
    PORT
      LAYER Metal3 ;
        RECT  0 694.9 0.4 695.3 ;
    END
  END limits_o.lim_csp[8]
  PIN limits_o.lim_csp[9]
    DIRECTION OUTPUT ;
    USE SIGNAL ;
    PORT
      LAYER Metal3 ;
        RECT  0 698.26 0.4 698.66 ;
    END
  END limits_o.lim_csp[9]
  PIN limits_o.lim_dsp[0]
    DIRECTION OUTPUT ;
    USE SIGNAL ;
    PORT
      LAYER Metal3 ;
        RECT  0 668.86 0.4 669.26 ;
    END
  END limits_o.lim_dsp[0]
  PIN limits_o.lim_dsp[10]
    DIRECTION OUTPUT ;
    USE SIGNAL ;
    PORT
      LAYER Metal3 ;
        RECT  0 702.46 0.4 702.86 ;
    END
  END limits_o.lim_dsp[10]
  PIN limits_o.lim_dsp[11]
    DIRECTION OUTPUT ;
    USE SIGNAL ;
    PORT
      LAYER Metal3 ;
        RECT  0 705.82 0.4 706.22 ;
    END
  END limits_o.lim_dsp[11]
  PIN limits_o.lim_dsp[12]
    DIRECTION OUTPUT ;
    USE SIGNAL ;
    PORT
      LAYER Metal3 ;
        RECT  0 709.18 0.4 709.58 ;
    END
  END limits_o.lim_dsp[12]
  PIN limits_o.lim_dsp[13]
    DIRECTION OUTPUT ;
    USE SIGNAL ;
    PORT
      LAYER Metal3 ;
        RECT  0 712.54 0.4 712.94 ;
    END
  END limits_o.lim_dsp[13]
  PIN limits_o.lim_dsp[14]
    DIRECTION OUTPUT ;
    USE SIGNAL ;
    PORT
      LAYER Metal3 ;
        RECT  0 715.9 0.4 716.3 ;
    END
  END limits_o.lim_dsp[14]
  PIN limits_o.lim_dsp[15]
    DIRECTION OUTPUT ;
    USE SIGNAL ;
    PORT
      LAYER Metal3 ;
        RECT  0 719.26 0.4 719.66 ;
    END
  END limits_o.lim_dsp[15]
  PIN limits_o.lim_dsp[16]
    DIRECTION OUTPUT ;
    USE SIGNAL ;
    PORT
      LAYER Metal3 ;
        RECT  0 722.62 0.4 723.02 ;
    END
  END limits_o.lim_dsp[16]
  PIN limits_o.lim_dsp[17]
    DIRECTION OUTPUT ;
    USE SIGNAL ;
    PORT
      LAYER Metal3 ;
        RECT  0 725.98 0.4 726.38 ;
    END
  END limits_o.lim_dsp[17]
  PIN limits_o.lim_dsp[18]
    DIRECTION OUTPUT ;
    USE SIGNAL ;
    PORT
      LAYER Metal3 ;
        RECT  0 729.34 0.4 729.74 ;
    END
  END limits_o.lim_dsp[18]
  PIN limits_o.lim_dsp[19]
    DIRECTION OUTPUT ;
    USE SIGNAL ;
    PORT
      LAYER Metal3 ;
        RECT  0 732.7 0.4 733.1 ;
    END
  END limits_o.lim_dsp[19]
  PIN limits_o.lim_dsp[1]
    DIRECTION OUTPUT ;
    USE SIGNAL ;
    PORT
      LAYER Metal3 ;
        RECT  0 672.22 0.4 672.62 ;
    END
  END limits_o.lim_dsp[1]
  PIN limits_o.lim_dsp[20]
    DIRECTION OUTPUT ;
    USE SIGNAL ;
    PORT
      LAYER Metal3 ;
        RECT  0 736.06 0.4 736.46 ;
    END
  END limits_o.lim_dsp[20]
  PIN limits_o.lim_dsp[21]
    DIRECTION OUTPUT ;
    USE SIGNAL ;
    PORT
      LAYER Metal3 ;
        RECT  0 739.42 0.4 739.82 ;
    END
  END limits_o.lim_dsp[21]
  PIN limits_o.lim_dsp[22]
    DIRECTION OUTPUT ;
    USE SIGNAL ;
    PORT
      LAYER Metal3 ;
        RECT  0 742.78 0.4 743.18 ;
    END
  END limits_o.lim_dsp[22]
  PIN limits_o.lim_dsp[23]
    DIRECTION OUTPUT ;
    USE SIGNAL ;
    PORT
      LAYER Metal3 ;
        RECT  0 746.14 0.4 746.54 ;
    END
  END limits_o.lim_dsp[23]
  PIN limits_o.lim_dsp[24]
    DIRECTION OUTPUT ;
    USE SIGNAL ;
    PORT
      LAYER Metal3 ;
        RECT  0 749.5 0.4 749.9 ;
    END
  END limits_o.lim_dsp[24]
  PIN limits_o.lim_dsp[25]
    DIRECTION OUTPUT ;
    USE SIGNAL ;
    PORT
      LAYER Metal3 ;
        RECT  0 752.86 0.4 753.26 ;
    END
  END limits_o.lim_dsp[25]
  PIN limits_o.lim_dsp[26]
    DIRECTION OUTPUT ;
    USE SIGNAL ;
    PORT
      LAYER Metal3 ;
        RECT  0 756.22 0.4 756.62 ;
    END
  END limits_o.lim_dsp[26]
  PIN limits_o.lim_dsp[27]
    DIRECTION OUTPUT ;
    USE SIGNAL ;
    PORT
      LAYER Metal3 ;
        RECT  0 759.58 0.4 759.98 ;
    END
  END limits_o.lim_dsp[27]
  PIN limits_o.lim_dsp[28]
    DIRECTION OUTPUT ;
    USE SIGNAL ;
    PORT
      LAYER Metal3 ;
        RECT  0 762.94 0.4 763.34 ;
    END
  END limits_o.lim_dsp[28]
  PIN limits_o.lim_dsp[29]
    DIRECTION OUTPUT ;
    USE SIGNAL ;
    PORT
      LAYER Metal3 ;
        RECT  0 766.3 0.4 766.7 ;
    END
  END limits_o.lim_dsp[29]
  PIN limits_o.lim_dsp[2]
    DIRECTION OUTPUT ;
    USE SIGNAL ;
    PORT
      LAYER Metal3 ;
        RECT  0 675.58 0.4 675.98 ;
    END
  END limits_o.lim_dsp[2]
  PIN limits_o.lim_dsp[30]
    DIRECTION OUTPUT ;
    USE SIGNAL ;
    PORT
      LAYER Metal3 ;
        RECT  0 769.66 0.4 770.06 ;
    END
  END limits_o.lim_dsp[30]
  PIN limits_o.lim_dsp[31]
    DIRECTION OUTPUT ;
    USE SIGNAL ;
    PORT
      LAYER Metal3 ;
        RECT  0 773.02 0.4 773.42 ;
    END
  END limits_o.lim_dsp[31]
  PIN limits_o.lim_dsp[32]
    DIRECTION OUTPUT ;
    USE SIGNAL ;
    PORT
      LAYER Metal3 ;
        RECT  0 776.38 0.4 776.78 ;
    END
  END limits_o.lim_dsp[32]
  PIN limits_o.lim_dsp[33]
    DIRECTION OUTPUT ;
    USE SIGNAL ;
    PORT
      LAYER Metal3 ;
        RECT  0 779.74 0.4 780.14 ;
    END
  END limits_o.lim_dsp[33]
  PIN limits_o.lim_dsp[34]
    DIRECTION OUTPUT ;
    USE SIGNAL ;
    PORT
      LAYER Metal3 ;
        RECT  0 783.1 0.4 783.5 ;
    END
  END limits_o.lim_dsp[34]
  PIN limits_o.lim_dsp[35]
    DIRECTION OUTPUT ;
    USE SIGNAL ;
    PORT
      LAYER Metal3 ;
        RECT  0 786.46 0.4 786.86 ;
    END
  END limits_o.lim_dsp[35]
  PIN limits_o.lim_dsp[36]
    DIRECTION OUTPUT ;
    USE SIGNAL ;
    PORT
      LAYER Metal3 ;
        RECT  0 789.82 0.4 790.22 ;
    END
  END limits_o.lim_dsp[36]
  PIN limits_o.lim_dsp[37]
    DIRECTION OUTPUT ;
    USE SIGNAL ;
    PORT
      LAYER Metal3 ;
        RECT  0 793.18 0.4 793.58 ;
    END
  END limits_o.lim_dsp[37]
  PIN limits_o.lim_dsp[38]
    DIRECTION OUTPUT ;
    USE SIGNAL ;
    PORT
      LAYER Metal3 ;
        RECT  0 796.54 0.4 796.94 ;
    END
  END limits_o.lim_dsp[38]
  PIN limits_o.lim_dsp[39]
    DIRECTION OUTPUT ;
    USE SIGNAL ;
    PORT
      LAYER Metal3 ;
        RECT  0 799.9 0.4 800.3 ;
    END
  END limits_o.lim_dsp[39]
  PIN limits_o.lim_dsp[3]
    DIRECTION OUTPUT ;
    USE SIGNAL ;
    PORT
      LAYER Metal3 ;
        RECT  0 678.94 0.4 679.34 ;
    END
  END limits_o.lim_dsp[3]
  PIN limits_o.lim_dsp[40]
    DIRECTION OUTPUT ;
    USE SIGNAL ;
    PORT
      LAYER Metal3 ;
        RECT  0 803.26 0.4 803.66 ;
    END
  END limits_o.lim_dsp[40]
  PIN limits_o.lim_dsp[41]
    DIRECTION OUTPUT ;
    USE SIGNAL ;
    PORT
      LAYER Metal3 ;
        RECT  0 806.62 0.4 807.02 ;
    END
  END limits_o.lim_dsp[41]
  PIN limits_o.lim_dsp[42]
    DIRECTION OUTPUT ;
    USE SIGNAL ;
    PORT
      LAYER Metal3 ;
        RECT  0 809.98 0.4 810.38 ;
    END
  END limits_o.lim_dsp[42]
  PIN limits_o.lim_dsp[43]
    DIRECTION OUTPUT ;
    USE SIGNAL ;
    PORT
      LAYER Metal3 ;
        RECT  0 813.34 0.4 813.74 ;
    END
  END limits_o.lim_dsp[43]
  PIN limits_o.lim_dsp[44]
    DIRECTION OUTPUT ;
    USE SIGNAL ;
    PORT
      LAYER Metal3 ;
        RECT  0 816.7 0.4 817.1 ;
    END
  END limits_o.lim_dsp[44]
  PIN limits_o.lim_dsp[45]
    DIRECTION OUTPUT ;
    USE SIGNAL ;
    PORT
      LAYER Metal3 ;
        RECT  0 820.06 0.4 820.46 ;
    END
  END limits_o.lim_dsp[45]
  PIN limits_o.lim_dsp[46]
    DIRECTION OUTPUT ;
    USE SIGNAL ;
    PORT
      LAYER Metal3 ;
        RECT  0 823.42 0.4 823.82 ;
    END
  END limits_o.lim_dsp[46]
  PIN limits_o.lim_dsp[47]
    DIRECTION OUTPUT ;
    USE SIGNAL ;
    PORT
      LAYER Metal3 ;
        RECT  0 826.78 0.4 827.18 ;
    END
  END limits_o.lim_dsp[47]
  PIN limits_o.lim_dsp[48]
    DIRECTION OUTPUT ;
    USE SIGNAL ;
    PORT
      LAYER Metal3 ;
        RECT  0 830.14 0.4 830.54 ;
    END
  END limits_o.lim_dsp[48]
  PIN limits_o.lim_dsp[49]
    DIRECTION OUTPUT ;
    USE SIGNAL ;
    PORT
      LAYER Metal3 ;
        RECT  0 833.5 0.4 833.9 ;
    END
  END limits_o.lim_dsp[49]
  PIN limits_o.lim_dsp[4]
    DIRECTION OUTPUT ;
    USE SIGNAL ;
    PORT
      LAYER Metal3 ;
        RECT  0 682.3 0.4 682.7 ;
    END
  END limits_o.lim_dsp[4]
  PIN limits_o.lim_dsp[50]
    DIRECTION OUTPUT ;
    USE SIGNAL ;
    PORT
      LAYER Metal3 ;
        RECT  0 836.86 0.4 837.26 ;
    END
  END limits_o.lim_dsp[50]
  PIN limits_o.lim_dsp[51]
    DIRECTION OUTPUT ;
    USE SIGNAL ;
    PORT
      LAYER Metal3 ;
        RECT  0 840.22 0.4 840.62 ;
    END
  END limits_o.lim_dsp[51]
  PIN limits_o.lim_dsp[52]
    DIRECTION OUTPUT ;
    USE SIGNAL ;
    PORT
      LAYER Metal3 ;
        RECT  0 843.58 0.4 843.98 ;
    END
  END limits_o.lim_dsp[52]
  PIN limits_o.lim_dsp[53]
    DIRECTION OUTPUT ;
    USE SIGNAL ;
    PORT
      LAYER Metal3 ;
        RECT  0 846.94 0.4 847.34 ;
    END
  END limits_o.lim_dsp[53]
  PIN limits_o.lim_dsp[54]
    DIRECTION OUTPUT ;
    USE SIGNAL ;
    PORT
      LAYER Metal3 ;
        RECT  0 850.3 0.4 850.7 ;
    END
  END limits_o.lim_dsp[54]
  PIN limits_o.lim_dsp[55]
    DIRECTION OUTPUT ;
    USE SIGNAL ;
    PORT
      LAYER Metal3 ;
        RECT  0 853.66 0.4 854.06 ;
    END
  END limits_o.lim_dsp[55]
  PIN limits_o.lim_dsp[56]
    DIRECTION OUTPUT ;
    USE SIGNAL ;
    PORT
      LAYER Metal3 ;
        RECT  0 857.02 0.4 857.42 ;
    END
  END limits_o.lim_dsp[56]
  PIN limits_o.lim_dsp[57]
    DIRECTION OUTPUT ;
    USE SIGNAL ;
    PORT
      LAYER Metal3 ;
        RECT  0 860.38 0.4 860.78 ;
    END
  END limits_o.lim_dsp[57]
  PIN limits_o.lim_dsp[58]
    DIRECTION OUTPUT ;
    USE SIGNAL ;
    PORT
      LAYER Metal3 ;
        RECT  0 863.74 0.4 864.14 ;
    END
  END limits_o.lim_dsp[58]
  PIN limits_o.lim_dsp[59]
    DIRECTION OUTPUT ;
    USE SIGNAL ;
    PORT
      LAYER Metal3 ;
        RECT  0 867.1 0.4 867.5 ;
    END
  END limits_o.lim_dsp[59]
  PIN limits_o.lim_dsp[5]
    DIRECTION OUTPUT ;
    USE SIGNAL ;
    PORT
      LAYER Metal3 ;
        RECT  0 685.66 0.4 686.06 ;
    END
  END limits_o.lim_dsp[5]
  PIN limits_o.lim_dsp[60]
    DIRECTION OUTPUT ;
    USE SIGNAL ;
    PORT
      LAYER Metal3 ;
        RECT  0 870.46 0.4 870.86 ;
    END
  END limits_o.lim_dsp[60]
  PIN limits_o.lim_dsp[61]
    DIRECTION OUTPUT ;
    USE SIGNAL ;
    PORT
      LAYER Metal3 ;
        RECT  0 873.82 0.4 874.22 ;
    END
  END limits_o.lim_dsp[61]
  PIN limits_o.lim_dsp[62]
    DIRECTION OUTPUT ;
    USE SIGNAL ;
    PORT
      LAYER Metal3 ;
        RECT  0 877.18 0.4 877.58 ;
    END
  END limits_o.lim_dsp[62]
  PIN limits_o.lim_dsp[63]
    DIRECTION OUTPUT ;
    USE SIGNAL ;
    PORT
      LAYER Metal3 ;
        RECT  0 880.54 0.4 880.94 ;
    END
  END limits_o.lim_dsp[63]
  PIN limits_o.lim_dsp[6]
    DIRECTION OUTPUT ;
    USE SIGNAL ;
    PORT
      LAYER Metal3 ;
        RECT  0 689.02 0.4 689.42 ;
    END
  END limits_o.lim_dsp[6]
  PIN limits_o.lim_dsp[7]
    DIRECTION OUTPUT ;
    USE SIGNAL ;
    PORT
      LAYER Metal3 ;
        RECT  0 692.38 0.4 692.78 ;
    END
  END limits_o.lim_dsp[7]
  PIN limits_o.lim_dsp[8]
    DIRECTION OUTPUT ;
    USE SIGNAL ;
    PORT
      LAYER Metal3 ;
        RECT  0 695.74 0.4 696.14 ;
    END
  END limits_o.lim_dsp[8]
  PIN limits_o.lim_dsp[9]
    DIRECTION OUTPUT ;
    USE SIGNAL ;
    PORT
      LAYER Metal3 ;
        RECT  0 699.1 0.4 699.5 ;
    END
  END limits_o.lim_dsp[9]
  PIN limits_o.lim_hp[0]
    DIRECTION OUTPUT ;
    USE SIGNAL ;
    PORT
      LAYER Metal3 ;
        RECT  0 669.7 0.4 670.1 ;
    END
  END limits_o.lim_hp[0]
  PIN limits_o.lim_hp[10]
    DIRECTION OUTPUT ;
    USE SIGNAL ;
    PORT
      LAYER Metal3 ;
        RECT  0 703.3 0.4 703.7 ;
    END
  END limits_o.lim_hp[10]
  PIN limits_o.lim_hp[11]
    DIRECTION OUTPUT ;
    USE SIGNAL ;
    PORT
      LAYER Metal3 ;
        RECT  0 706.66 0.4 707.06 ;
    END
  END limits_o.lim_hp[11]
  PIN limits_o.lim_hp[12]
    DIRECTION OUTPUT ;
    USE SIGNAL ;
    PORT
      LAYER Metal3 ;
        RECT  0 710.02 0.4 710.42 ;
    END
  END limits_o.lim_hp[12]
  PIN limits_o.lim_hp[13]
    DIRECTION OUTPUT ;
    USE SIGNAL ;
    PORT
      LAYER Metal3 ;
        RECT  0 713.38 0.4 713.78 ;
    END
  END limits_o.lim_hp[13]
  PIN limits_o.lim_hp[14]
    DIRECTION OUTPUT ;
    USE SIGNAL ;
    PORT
      LAYER Metal3 ;
        RECT  0 716.74 0.4 717.14 ;
    END
  END limits_o.lim_hp[14]
  PIN limits_o.lim_hp[15]
    DIRECTION OUTPUT ;
    USE SIGNAL ;
    PORT
      LAYER Metal3 ;
        RECT  0 720.1 0.4 720.5 ;
    END
  END limits_o.lim_hp[15]
  PIN limits_o.lim_hp[16]
    DIRECTION OUTPUT ;
    USE SIGNAL ;
    PORT
      LAYER Metal3 ;
        RECT  0 723.46 0.4 723.86 ;
    END
  END limits_o.lim_hp[16]
  PIN limits_o.lim_hp[17]
    DIRECTION OUTPUT ;
    USE SIGNAL ;
    PORT
      LAYER Metal3 ;
        RECT  0 726.82 0.4 727.22 ;
    END
  END limits_o.lim_hp[17]
  PIN limits_o.lim_hp[18]
    DIRECTION OUTPUT ;
    USE SIGNAL ;
    PORT
      LAYER Metal3 ;
        RECT  0 730.18 0.4 730.58 ;
    END
  END limits_o.lim_hp[18]
  PIN limits_o.lim_hp[19]
    DIRECTION OUTPUT ;
    USE SIGNAL ;
    PORT
      LAYER Metal3 ;
        RECT  0 733.54 0.4 733.94 ;
    END
  END limits_o.lim_hp[19]
  PIN limits_o.lim_hp[1]
    DIRECTION OUTPUT ;
    USE SIGNAL ;
    PORT
      LAYER Metal3 ;
        RECT  0 673.06 0.4 673.46 ;
    END
  END limits_o.lim_hp[1]
  PIN limits_o.lim_hp[20]
    DIRECTION OUTPUT ;
    USE SIGNAL ;
    PORT
      LAYER Metal3 ;
        RECT  0 736.9 0.4 737.3 ;
    END
  END limits_o.lim_hp[20]
  PIN limits_o.lim_hp[21]
    DIRECTION OUTPUT ;
    USE SIGNAL ;
    PORT
      LAYER Metal3 ;
        RECT  0 740.26 0.4 740.66 ;
    END
  END limits_o.lim_hp[21]
  PIN limits_o.lim_hp[22]
    DIRECTION OUTPUT ;
    USE SIGNAL ;
    PORT
      LAYER Metal3 ;
        RECT  0 743.62 0.4 744.02 ;
    END
  END limits_o.lim_hp[22]
  PIN limits_o.lim_hp[23]
    DIRECTION OUTPUT ;
    USE SIGNAL ;
    PORT
      LAYER Metal3 ;
        RECT  0 746.98 0.4 747.38 ;
    END
  END limits_o.lim_hp[23]
  PIN limits_o.lim_hp[24]
    DIRECTION OUTPUT ;
    USE SIGNAL ;
    PORT
      LAYER Metal3 ;
        RECT  0 750.34 0.4 750.74 ;
    END
  END limits_o.lim_hp[24]
  PIN limits_o.lim_hp[25]
    DIRECTION OUTPUT ;
    USE SIGNAL ;
    PORT
      LAYER Metal3 ;
        RECT  0 753.7 0.4 754.1 ;
    END
  END limits_o.lim_hp[25]
  PIN limits_o.lim_hp[26]
    DIRECTION OUTPUT ;
    USE SIGNAL ;
    PORT
      LAYER Metal3 ;
        RECT  0 757.06 0.4 757.46 ;
    END
  END limits_o.lim_hp[26]
  PIN limits_o.lim_hp[27]
    DIRECTION OUTPUT ;
    USE SIGNAL ;
    PORT
      LAYER Metal3 ;
        RECT  0 760.42 0.4 760.82 ;
    END
  END limits_o.lim_hp[27]
  PIN limits_o.lim_hp[28]
    DIRECTION OUTPUT ;
    USE SIGNAL ;
    PORT
      LAYER Metal3 ;
        RECT  0 763.78 0.4 764.18 ;
    END
  END limits_o.lim_hp[28]
  PIN limits_o.lim_hp[29]
    DIRECTION OUTPUT ;
    USE SIGNAL ;
    PORT
      LAYER Metal3 ;
        RECT  0 767.14 0.4 767.54 ;
    END
  END limits_o.lim_hp[29]
  PIN limits_o.lim_hp[2]
    DIRECTION OUTPUT ;
    USE SIGNAL ;
    PORT
      LAYER Metal3 ;
        RECT  0 676.42 0.4 676.82 ;
    END
  END limits_o.lim_hp[2]
  PIN limits_o.lim_hp[30]
    DIRECTION OUTPUT ;
    USE SIGNAL ;
    PORT
      LAYER Metal3 ;
        RECT  0 770.5 0.4 770.9 ;
    END
  END limits_o.lim_hp[30]
  PIN limits_o.lim_hp[31]
    DIRECTION OUTPUT ;
    USE SIGNAL ;
    PORT
      LAYER Metal3 ;
        RECT  0 773.86 0.4 774.26 ;
    END
  END limits_o.lim_hp[31]
  PIN limits_o.lim_hp[32]
    DIRECTION OUTPUT ;
    USE SIGNAL ;
    PORT
      LAYER Metal3 ;
        RECT  0 777.22 0.4 777.62 ;
    END
  END limits_o.lim_hp[32]
  PIN limits_o.lim_hp[33]
    DIRECTION OUTPUT ;
    USE SIGNAL ;
    PORT
      LAYER Metal3 ;
        RECT  0 780.58 0.4 780.98 ;
    END
  END limits_o.lim_hp[33]
  PIN limits_o.lim_hp[34]
    DIRECTION OUTPUT ;
    USE SIGNAL ;
    PORT
      LAYER Metal3 ;
        RECT  0 783.94 0.4 784.34 ;
    END
  END limits_o.lim_hp[34]
  PIN limits_o.lim_hp[35]
    DIRECTION OUTPUT ;
    USE SIGNAL ;
    PORT
      LAYER Metal3 ;
        RECT  0 787.3 0.4 787.7 ;
    END
  END limits_o.lim_hp[35]
  PIN limits_o.lim_hp[36]
    DIRECTION OUTPUT ;
    USE SIGNAL ;
    PORT
      LAYER Metal3 ;
        RECT  0 790.66 0.4 791.06 ;
    END
  END limits_o.lim_hp[36]
  PIN limits_o.lim_hp[37]
    DIRECTION OUTPUT ;
    USE SIGNAL ;
    PORT
      LAYER Metal3 ;
        RECT  0 794.02 0.4 794.42 ;
    END
  END limits_o.lim_hp[37]
  PIN limits_o.lim_hp[38]
    DIRECTION OUTPUT ;
    USE SIGNAL ;
    PORT
      LAYER Metal3 ;
        RECT  0 797.38 0.4 797.78 ;
    END
  END limits_o.lim_hp[38]
  PIN limits_o.lim_hp[39]
    DIRECTION OUTPUT ;
    USE SIGNAL ;
    PORT
      LAYER Metal3 ;
        RECT  0 800.74 0.4 801.14 ;
    END
  END limits_o.lim_hp[39]
  PIN limits_o.lim_hp[3]
    DIRECTION OUTPUT ;
    USE SIGNAL ;
    PORT
      LAYER Metal3 ;
        RECT  0 679.78 0.4 680.18 ;
    END
  END limits_o.lim_hp[3]
  PIN limits_o.lim_hp[40]
    DIRECTION OUTPUT ;
    USE SIGNAL ;
    PORT
      LAYER Metal3 ;
        RECT  0 804.1 0.4 804.5 ;
    END
  END limits_o.lim_hp[40]
  PIN limits_o.lim_hp[41]
    DIRECTION OUTPUT ;
    USE SIGNAL ;
    PORT
      LAYER Metal3 ;
        RECT  0 807.46 0.4 807.86 ;
    END
  END limits_o.lim_hp[41]
  PIN limits_o.lim_hp[42]
    DIRECTION OUTPUT ;
    USE SIGNAL ;
    PORT
      LAYER Metal3 ;
        RECT  0 810.82 0.4 811.22 ;
    END
  END limits_o.lim_hp[42]
  PIN limits_o.lim_hp[43]
    DIRECTION OUTPUT ;
    USE SIGNAL ;
    PORT
      LAYER Metal3 ;
        RECT  0 814.18 0.4 814.58 ;
    END
  END limits_o.lim_hp[43]
  PIN limits_o.lim_hp[44]
    DIRECTION OUTPUT ;
    USE SIGNAL ;
    PORT
      LAYER Metal3 ;
        RECT  0 817.54 0.4 817.94 ;
    END
  END limits_o.lim_hp[44]
  PIN limits_o.lim_hp[45]
    DIRECTION OUTPUT ;
    USE SIGNAL ;
    PORT
      LAYER Metal3 ;
        RECT  0 820.9 0.4 821.3 ;
    END
  END limits_o.lim_hp[45]
  PIN limits_o.lim_hp[46]
    DIRECTION OUTPUT ;
    USE SIGNAL ;
    PORT
      LAYER Metal3 ;
        RECT  0 824.26 0.4 824.66 ;
    END
  END limits_o.lim_hp[46]
  PIN limits_o.lim_hp[47]
    DIRECTION OUTPUT ;
    USE SIGNAL ;
    PORT
      LAYER Metal3 ;
        RECT  0 827.62 0.4 828.02 ;
    END
  END limits_o.lim_hp[47]
  PIN limits_o.lim_hp[48]
    DIRECTION OUTPUT ;
    USE SIGNAL ;
    PORT
      LAYER Metal3 ;
        RECT  0 830.98 0.4 831.38 ;
    END
  END limits_o.lim_hp[48]
  PIN limits_o.lim_hp[49]
    DIRECTION OUTPUT ;
    USE SIGNAL ;
    PORT
      LAYER Metal3 ;
        RECT  0 834.34 0.4 834.74 ;
    END
  END limits_o.lim_hp[49]
  PIN limits_o.lim_hp[4]
    DIRECTION OUTPUT ;
    USE SIGNAL ;
    PORT
      LAYER Metal3 ;
        RECT  0 683.14 0.4 683.54 ;
    END
  END limits_o.lim_hp[4]
  PIN limits_o.lim_hp[50]
    DIRECTION OUTPUT ;
    USE SIGNAL ;
    PORT
      LAYER Metal3 ;
        RECT  0 837.7 0.4 838.1 ;
    END
  END limits_o.lim_hp[50]
  PIN limits_o.lim_hp[51]
    DIRECTION OUTPUT ;
    USE SIGNAL ;
    PORT
      LAYER Metal3 ;
        RECT  0 841.06 0.4 841.46 ;
    END
  END limits_o.lim_hp[51]
  PIN limits_o.lim_hp[52]
    DIRECTION OUTPUT ;
    USE SIGNAL ;
    PORT
      LAYER Metal3 ;
        RECT  0 844.42 0.4 844.82 ;
    END
  END limits_o.lim_hp[52]
  PIN limits_o.lim_hp[53]
    DIRECTION OUTPUT ;
    USE SIGNAL ;
    PORT
      LAYER Metal3 ;
        RECT  0 847.78 0.4 848.18 ;
    END
  END limits_o.lim_hp[53]
  PIN limits_o.lim_hp[54]
    DIRECTION OUTPUT ;
    USE SIGNAL ;
    PORT
      LAYER Metal3 ;
        RECT  0 851.14 0.4 851.54 ;
    END
  END limits_o.lim_hp[54]
  PIN limits_o.lim_hp[55]
    DIRECTION OUTPUT ;
    USE SIGNAL ;
    PORT
      LAYER Metal3 ;
        RECT  0 854.5 0.4 854.9 ;
    END
  END limits_o.lim_hp[55]
  PIN limits_o.lim_hp[56]
    DIRECTION OUTPUT ;
    USE SIGNAL ;
    PORT
      LAYER Metal3 ;
        RECT  0 857.86 0.4 858.26 ;
    END
  END limits_o.lim_hp[56]
  PIN limits_o.lim_hp[57]
    DIRECTION OUTPUT ;
    USE SIGNAL ;
    PORT
      LAYER Metal3 ;
        RECT  0 861.22 0.4 861.62 ;
    END
  END limits_o.lim_hp[57]
  PIN limits_o.lim_hp[58]
    DIRECTION OUTPUT ;
    USE SIGNAL ;
    PORT
      LAYER Metal3 ;
        RECT  0 864.58 0.4 864.98 ;
    END
  END limits_o.lim_hp[58]
  PIN limits_o.lim_hp[59]
    DIRECTION OUTPUT ;
    USE SIGNAL ;
    PORT
      LAYER Metal3 ;
        RECT  0 867.94 0.4 868.34 ;
    END
  END limits_o.lim_hp[59]
  PIN limits_o.lim_hp[5]
    DIRECTION OUTPUT ;
    USE SIGNAL ;
    PORT
      LAYER Metal3 ;
        RECT  0 686.5 0.4 686.9 ;
    END
  END limits_o.lim_hp[5]
  PIN limits_o.lim_hp[60]
    DIRECTION OUTPUT ;
    USE SIGNAL ;
    PORT
      LAYER Metal3 ;
        RECT  0 871.3 0.4 871.7 ;
    END
  END limits_o.lim_hp[60]
  PIN limits_o.lim_hp[61]
    DIRECTION OUTPUT ;
    USE SIGNAL ;
    PORT
      LAYER Metal3 ;
        RECT  0 874.66 0.4 875.06 ;
    END
  END limits_o.lim_hp[61]
  PIN limits_o.lim_hp[62]
    DIRECTION OUTPUT ;
    USE SIGNAL ;
    PORT
      LAYER Metal3 ;
        RECT  0 878.02 0.4 878.42 ;
    END
  END limits_o.lim_hp[62]
  PIN limits_o.lim_hp[63]
    DIRECTION OUTPUT ;
    USE SIGNAL ;
    PORT
      LAYER Metal3 ;
        RECT  0 881.38 0.4 881.78 ;
    END
  END limits_o.lim_hp[63]
  PIN limits_o.lim_hp[6]
    DIRECTION OUTPUT ;
    USE SIGNAL ;
    PORT
      LAYER Metal3 ;
        RECT  0 689.86 0.4 690.26 ;
    END
  END limits_o.lim_hp[6]
  PIN limits_o.lim_hp[7]
    DIRECTION OUTPUT ;
    USE SIGNAL ;
    PORT
      LAYER Metal3 ;
        RECT  0 693.22 0.4 693.62 ;
    END
  END limits_o.lim_hp[7]
  PIN limits_o.lim_hp[8]
    DIRECTION OUTPUT ;
    USE SIGNAL ;
    PORT
      LAYER Metal3 ;
        RECT  0 696.58 0.4 696.98 ;
    END
  END limits_o.lim_hp[8]
  PIN limits_o.lim_hp[9]
    DIRECTION OUTPUT ;
    USE SIGNAL ;
    PORT
      LAYER Metal3 ;
        RECT  0 699.94 0.4 700.34 ;
    END
  END limits_o.lim_hp[9]
  PIN limits_o.lim_rsp[0]
    DIRECTION OUTPUT ;
    USE SIGNAL ;
    PORT
      LAYER Metal3 ;
        RECT  0 670.54 0.4 670.94 ;
    END
  END limits_o.lim_rsp[0]
  PIN limits_o.lim_rsp[10]
    DIRECTION OUTPUT ;
    USE SIGNAL ;
    PORT
      LAYER Metal3 ;
        RECT  0 704.14 0.4 704.54 ;
    END
  END limits_o.lim_rsp[10]
  PIN limits_o.lim_rsp[11]
    DIRECTION OUTPUT ;
    USE SIGNAL ;
    PORT
      LAYER Metal3 ;
        RECT  0 707.5 0.4 707.9 ;
    END
  END limits_o.lim_rsp[11]
  PIN limits_o.lim_rsp[12]
    DIRECTION OUTPUT ;
    USE SIGNAL ;
    PORT
      LAYER Metal3 ;
        RECT  0 710.86 0.4 711.26 ;
    END
  END limits_o.lim_rsp[12]
  PIN limits_o.lim_rsp[13]
    DIRECTION OUTPUT ;
    USE SIGNAL ;
    PORT
      LAYER Metal3 ;
        RECT  0 714.22 0.4 714.62 ;
    END
  END limits_o.lim_rsp[13]
  PIN limits_o.lim_rsp[14]
    DIRECTION OUTPUT ;
    USE SIGNAL ;
    PORT
      LAYER Metal3 ;
        RECT  0 717.58 0.4 717.98 ;
    END
  END limits_o.lim_rsp[14]
  PIN limits_o.lim_rsp[15]
    DIRECTION OUTPUT ;
    USE SIGNAL ;
    PORT
      LAYER Metal3 ;
        RECT  0 720.94 0.4 721.34 ;
    END
  END limits_o.lim_rsp[15]
  PIN limits_o.lim_rsp[16]
    DIRECTION OUTPUT ;
    USE SIGNAL ;
    PORT
      LAYER Metal3 ;
        RECT  0 724.3 0.4 724.7 ;
    END
  END limits_o.lim_rsp[16]
  PIN limits_o.lim_rsp[17]
    DIRECTION OUTPUT ;
    USE SIGNAL ;
    PORT
      LAYER Metal3 ;
        RECT  0 727.66 0.4 728.06 ;
    END
  END limits_o.lim_rsp[17]
  PIN limits_o.lim_rsp[18]
    DIRECTION OUTPUT ;
    USE SIGNAL ;
    PORT
      LAYER Metal3 ;
        RECT  0 731.02 0.4 731.42 ;
    END
  END limits_o.lim_rsp[18]
  PIN limits_o.lim_rsp[19]
    DIRECTION OUTPUT ;
    USE SIGNAL ;
    PORT
      LAYER Metal3 ;
        RECT  0 734.38 0.4 734.78 ;
    END
  END limits_o.lim_rsp[19]
  PIN limits_o.lim_rsp[1]
    DIRECTION OUTPUT ;
    USE SIGNAL ;
    PORT
      LAYER Metal3 ;
        RECT  0 673.9 0.4 674.3 ;
    END
  END limits_o.lim_rsp[1]
  PIN limits_o.lim_rsp[20]
    DIRECTION OUTPUT ;
    USE SIGNAL ;
    PORT
      LAYER Metal3 ;
        RECT  0 737.74 0.4 738.14 ;
    END
  END limits_o.lim_rsp[20]
  PIN limits_o.lim_rsp[21]
    DIRECTION OUTPUT ;
    USE SIGNAL ;
    PORT
      LAYER Metal3 ;
        RECT  0 741.1 0.4 741.5 ;
    END
  END limits_o.lim_rsp[21]
  PIN limits_o.lim_rsp[22]
    DIRECTION OUTPUT ;
    USE SIGNAL ;
    PORT
      LAYER Metal3 ;
        RECT  0 744.46 0.4 744.86 ;
    END
  END limits_o.lim_rsp[22]
  PIN limits_o.lim_rsp[23]
    DIRECTION OUTPUT ;
    USE SIGNAL ;
    PORT
      LAYER Metal3 ;
        RECT  0 747.82 0.4 748.22 ;
    END
  END limits_o.lim_rsp[23]
  PIN limits_o.lim_rsp[24]
    DIRECTION OUTPUT ;
    USE SIGNAL ;
    PORT
      LAYER Metal3 ;
        RECT  0 751.18 0.4 751.58 ;
    END
  END limits_o.lim_rsp[24]
  PIN limits_o.lim_rsp[25]
    DIRECTION OUTPUT ;
    USE SIGNAL ;
    PORT
      LAYER Metal3 ;
        RECT  0 754.54 0.4 754.94 ;
    END
  END limits_o.lim_rsp[25]
  PIN limits_o.lim_rsp[26]
    DIRECTION OUTPUT ;
    USE SIGNAL ;
    PORT
      LAYER Metal3 ;
        RECT  0 757.9 0.4 758.3 ;
    END
  END limits_o.lim_rsp[26]
  PIN limits_o.lim_rsp[27]
    DIRECTION OUTPUT ;
    USE SIGNAL ;
    PORT
      LAYER Metal3 ;
        RECT  0 761.26 0.4 761.66 ;
    END
  END limits_o.lim_rsp[27]
  PIN limits_o.lim_rsp[28]
    DIRECTION OUTPUT ;
    USE SIGNAL ;
    PORT
      LAYER Metal3 ;
        RECT  0 764.62 0.4 765.02 ;
    END
  END limits_o.lim_rsp[28]
  PIN limits_o.lim_rsp[29]
    DIRECTION OUTPUT ;
    USE SIGNAL ;
    PORT
      LAYER Metal3 ;
        RECT  0 767.98 0.4 768.38 ;
    END
  END limits_o.lim_rsp[29]
  PIN limits_o.lim_rsp[2]
    DIRECTION OUTPUT ;
    USE SIGNAL ;
    PORT
      LAYER Metal3 ;
        RECT  0 677.26 0.4 677.66 ;
    END
  END limits_o.lim_rsp[2]
  PIN limits_o.lim_rsp[30]
    DIRECTION OUTPUT ;
    USE SIGNAL ;
    PORT
      LAYER Metal3 ;
        RECT  0 771.34 0.4 771.74 ;
    END
  END limits_o.lim_rsp[30]
  PIN limits_o.lim_rsp[31]
    DIRECTION OUTPUT ;
    USE SIGNAL ;
    PORT
      LAYER Metal3 ;
        RECT  0 774.7 0.4 775.1 ;
    END
  END limits_o.lim_rsp[31]
  PIN limits_o.lim_rsp[32]
    DIRECTION OUTPUT ;
    USE SIGNAL ;
    PORT
      LAYER Metal3 ;
        RECT  0 778.06 0.4 778.46 ;
    END
  END limits_o.lim_rsp[32]
  PIN limits_o.lim_rsp[33]
    DIRECTION OUTPUT ;
    USE SIGNAL ;
    PORT
      LAYER Metal3 ;
        RECT  0 781.42 0.4 781.82 ;
    END
  END limits_o.lim_rsp[33]
  PIN limits_o.lim_rsp[34]
    DIRECTION OUTPUT ;
    USE SIGNAL ;
    PORT
      LAYER Metal3 ;
        RECT  0 784.78 0.4 785.18 ;
    END
  END limits_o.lim_rsp[34]
  PIN limits_o.lim_rsp[35]
    DIRECTION OUTPUT ;
    USE SIGNAL ;
    PORT
      LAYER Metal3 ;
        RECT  0 788.14 0.4 788.54 ;
    END
  END limits_o.lim_rsp[35]
  PIN limits_o.lim_rsp[36]
    DIRECTION OUTPUT ;
    USE SIGNAL ;
    PORT
      LAYER Metal3 ;
        RECT  0 791.5 0.4 791.9 ;
    END
  END limits_o.lim_rsp[36]
  PIN limits_o.lim_rsp[37]
    DIRECTION OUTPUT ;
    USE SIGNAL ;
    PORT
      LAYER Metal3 ;
        RECT  0 794.86 0.4 795.26 ;
    END
  END limits_o.lim_rsp[37]
  PIN limits_o.lim_rsp[38]
    DIRECTION OUTPUT ;
    USE SIGNAL ;
    PORT
      LAYER Metal3 ;
        RECT  0 798.22 0.4 798.62 ;
    END
  END limits_o.lim_rsp[38]
  PIN limits_o.lim_rsp[39]
    DIRECTION OUTPUT ;
    USE SIGNAL ;
    PORT
      LAYER Metal3 ;
        RECT  0 801.58 0.4 801.98 ;
    END
  END limits_o.lim_rsp[39]
  PIN limits_o.lim_rsp[3]
    DIRECTION OUTPUT ;
    USE SIGNAL ;
    PORT
      LAYER Metal3 ;
        RECT  0 680.62 0.4 681.02 ;
    END
  END limits_o.lim_rsp[3]
  PIN limits_o.lim_rsp[40]
    DIRECTION OUTPUT ;
    USE SIGNAL ;
    PORT
      LAYER Metal3 ;
        RECT  0 804.94 0.4 805.34 ;
    END
  END limits_o.lim_rsp[40]
  PIN limits_o.lim_rsp[41]
    DIRECTION OUTPUT ;
    USE SIGNAL ;
    PORT
      LAYER Metal3 ;
        RECT  0 808.3 0.4 808.7 ;
    END
  END limits_o.lim_rsp[41]
  PIN limits_o.lim_rsp[42]
    DIRECTION OUTPUT ;
    USE SIGNAL ;
    PORT
      LAYER Metal3 ;
        RECT  0 811.66 0.4 812.06 ;
    END
  END limits_o.lim_rsp[42]
  PIN limits_o.lim_rsp[43]
    DIRECTION OUTPUT ;
    USE SIGNAL ;
    PORT
      LAYER Metal3 ;
        RECT  0 815.02 0.4 815.42 ;
    END
  END limits_o.lim_rsp[43]
  PIN limits_o.lim_rsp[44]
    DIRECTION OUTPUT ;
    USE SIGNAL ;
    PORT
      LAYER Metal3 ;
        RECT  0 818.38 0.4 818.78 ;
    END
  END limits_o.lim_rsp[44]
  PIN limits_o.lim_rsp[45]
    DIRECTION OUTPUT ;
    USE SIGNAL ;
    PORT
      LAYER Metal3 ;
        RECT  0 821.74 0.4 822.14 ;
    END
  END limits_o.lim_rsp[45]
  PIN limits_o.lim_rsp[46]
    DIRECTION OUTPUT ;
    USE SIGNAL ;
    PORT
      LAYER Metal3 ;
        RECT  0 825.1 0.4 825.5 ;
    END
  END limits_o.lim_rsp[46]
  PIN limits_o.lim_rsp[47]
    DIRECTION OUTPUT ;
    USE SIGNAL ;
    PORT
      LAYER Metal3 ;
        RECT  0 828.46 0.4 828.86 ;
    END
  END limits_o.lim_rsp[47]
  PIN limits_o.lim_rsp[48]
    DIRECTION OUTPUT ;
    USE SIGNAL ;
    PORT
      LAYER Metal3 ;
        RECT  0 831.82 0.4 832.22 ;
    END
  END limits_o.lim_rsp[48]
  PIN limits_o.lim_rsp[49]
    DIRECTION OUTPUT ;
    USE SIGNAL ;
    PORT
      LAYER Metal3 ;
        RECT  0 835.18 0.4 835.58 ;
    END
  END limits_o.lim_rsp[49]
  PIN limits_o.lim_rsp[4]
    DIRECTION OUTPUT ;
    USE SIGNAL ;
    PORT
      LAYER Metal3 ;
        RECT  0 683.98 0.4 684.38 ;
    END
  END limits_o.lim_rsp[4]
  PIN limits_o.lim_rsp[50]
    DIRECTION OUTPUT ;
    USE SIGNAL ;
    PORT
      LAYER Metal3 ;
        RECT  0 838.54 0.4 838.94 ;
    END
  END limits_o.lim_rsp[50]
  PIN limits_o.lim_rsp[51]
    DIRECTION OUTPUT ;
    USE SIGNAL ;
    PORT
      LAYER Metal3 ;
        RECT  0 841.9 0.4 842.3 ;
    END
  END limits_o.lim_rsp[51]
  PIN limits_o.lim_rsp[52]
    DIRECTION OUTPUT ;
    USE SIGNAL ;
    PORT
      LAYER Metal3 ;
        RECT  0 845.26 0.4 845.66 ;
    END
  END limits_o.lim_rsp[52]
  PIN limits_o.lim_rsp[53]
    DIRECTION OUTPUT ;
    USE SIGNAL ;
    PORT
      LAYER Metal3 ;
        RECT  0 848.62 0.4 849.02 ;
    END
  END limits_o.lim_rsp[53]
  PIN limits_o.lim_rsp[54]
    DIRECTION OUTPUT ;
    USE SIGNAL ;
    PORT
      LAYER Metal3 ;
        RECT  0 851.98 0.4 852.38 ;
    END
  END limits_o.lim_rsp[54]
  PIN limits_o.lim_rsp[55]
    DIRECTION OUTPUT ;
    USE SIGNAL ;
    PORT
      LAYER Metal3 ;
        RECT  0 855.34 0.4 855.74 ;
    END
  END limits_o.lim_rsp[55]
  PIN limits_o.lim_rsp[56]
    DIRECTION OUTPUT ;
    USE SIGNAL ;
    PORT
      LAYER Metal3 ;
        RECT  0 858.7 0.4 859.1 ;
    END
  END limits_o.lim_rsp[56]
  PIN limits_o.lim_rsp[57]
    DIRECTION OUTPUT ;
    USE SIGNAL ;
    PORT
      LAYER Metal3 ;
        RECT  0 862.06 0.4 862.46 ;
    END
  END limits_o.lim_rsp[57]
  PIN limits_o.lim_rsp[58]
    DIRECTION OUTPUT ;
    USE SIGNAL ;
    PORT
      LAYER Metal3 ;
        RECT  0 865.42 0.4 865.82 ;
    END
  END limits_o.lim_rsp[58]
  PIN limits_o.lim_rsp[59]
    DIRECTION OUTPUT ;
    USE SIGNAL ;
    PORT
      LAYER Metal3 ;
        RECT  0 868.78 0.4 869.18 ;
    END
  END limits_o.lim_rsp[59]
  PIN limits_o.lim_rsp[5]
    DIRECTION OUTPUT ;
    USE SIGNAL ;
    PORT
      LAYER Metal3 ;
        RECT  0 687.34 0.4 687.74 ;
    END
  END limits_o.lim_rsp[5]
  PIN limits_o.lim_rsp[60]
    DIRECTION OUTPUT ;
    USE SIGNAL ;
    PORT
      LAYER Metal3 ;
        RECT  0 872.14 0.4 872.54 ;
    END
  END limits_o.lim_rsp[60]
  PIN limits_o.lim_rsp[61]
    DIRECTION OUTPUT ;
    USE SIGNAL ;
    PORT
      LAYER Metal3 ;
        RECT  0 875.5 0.4 875.9 ;
    END
  END limits_o.lim_rsp[61]
  PIN limits_o.lim_rsp[62]
    DIRECTION OUTPUT ;
    USE SIGNAL ;
    PORT
      LAYER Metal3 ;
        RECT  0 878.86 0.4 879.26 ;
    END
  END limits_o.lim_rsp[62]
  PIN limits_o.lim_rsp[63]
    DIRECTION OUTPUT ;
    USE SIGNAL ;
    PORT
      LAYER Metal3 ;
        RECT  0 882.22 0.4 882.62 ;
    END
  END limits_o.lim_rsp[63]
  PIN limits_o.lim_rsp[6]
    DIRECTION OUTPUT ;
    USE SIGNAL ;
    PORT
      LAYER Metal3 ;
        RECT  0 690.7 0.4 691.1 ;
    END
  END limits_o.lim_rsp[6]
  PIN limits_o.lim_rsp[7]
    DIRECTION OUTPUT ;
    USE SIGNAL ;
    PORT
      LAYER Metal3 ;
        RECT  0 694.06 0.4 694.46 ;
    END
  END limits_o.lim_rsp[7]
  PIN limits_o.lim_rsp[8]
    DIRECTION OUTPUT ;
    USE SIGNAL ;
    PORT
      LAYER Metal3 ;
        RECT  0 697.42 0.4 697.82 ;
    END
  END limits_o.lim_rsp[8]
  PIN limits_o.lim_rsp[9]
    DIRECTION OUTPUT ;
    USE SIGNAL ;
    PORT
      LAYER Metal3 ;
        RECT  0 700.78 0.4 701.18 ;
    END
  END limits_o.lim_rsp[9]
  PIN mem_ready_i
    DIRECTION INPUT ;
    USE SIGNAL ;
    PORT
      LAYER Metal3 ;
        RECT  0 1632.34 0.4 1632.74 ;
    END
  END mem_ready_i
  PIN mem_req_o.address[0]
    DIRECTION OUTPUT ;
    USE SIGNAL ;
    PORT
      LAYER Metal3 ;
        RECT  0 1539.94 0.4 1540.34 ;
    END
  END mem_req_o.address[0]
  PIN mem_req_o.address[10]
    DIRECTION OUTPUT ;
    USE SIGNAL ;
    PORT
      LAYER Metal3 ;
        RECT  0 1558.42 0.4 1558.82 ;
    END
  END mem_req_o.address[10]
  PIN mem_req_o.address[11]
    DIRECTION OUTPUT ;
    USE SIGNAL ;
    PORT
      LAYER Metal3 ;
        RECT  0 1560.1 0.4 1560.5 ;
    END
  END mem_req_o.address[11]
  PIN mem_req_o.address[12]
    DIRECTION OUTPUT ;
    USE SIGNAL ;
    PORT
      LAYER Metal3 ;
        RECT  0 1561.78 0.4 1562.18 ;
    END
  END mem_req_o.address[12]
  PIN mem_req_o.address[13]
    DIRECTION OUTPUT ;
    USE SIGNAL ;
    PORT
      LAYER Metal3 ;
        RECT  0 1563.46 0.4 1563.86 ;
    END
  END mem_req_o.address[13]
  PIN mem_req_o.address[14]
    DIRECTION OUTPUT ;
    USE SIGNAL ;
    PORT
      LAYER Metal3 ;
        RECT  0 1565.14 0.4 1565.54 ;
    END
  END mem_req_o.address[14]
  PIN mem_req_o.address[15]
    DIRECTION OUTPUT ;
    USE SIGNAL ;
    PORT
      LAYER Metal3 ;
        RECT  0 1566.82 0.4 1567.22 ;
    END
  END mem_req_o.address[15]
  PIN mem_req_o.address[16]
    DIRECTION OUTPUT ;
    USE SIGNAL ;
    PORT
      LAYER Metal3 ;
        RECT  0 1568.5 0.4 1568.9 ;
    END
  END mem_req_o.address[16]
  PIN mem_req_o.address[17]
    DIRECTION OUTPUT ;
    USE SIGNAL ;
    PORT
      LAYER Metal3 ;
        RECT  0 1570.18 0.4 1570.58 ;
    END
  END mem_req_o.address[17]
  PIN mem_req_o.address[18]
    DIRECTION OUTPUT ;
    USE SIGNAL ;
    PORT
      LAYER Metal3 ;
        RECT  0 1571.86 0.4 1572.26 ;
    END
  END mem_req_o.address[18]
  PIN mem_req_o.address[19]
    DIRECTION OUTPUT ;
    USE SIGNAL ;
    PORT
      LAYER Metal3 ;
        RECT  0 1573.54 0.4 1573.94 ;
    END
  END mem_req_o.address[19]
  PIN mem_req_o.address[1]
    DIRECTION OUTPUT ;
    USE SIGNAL ;
    PORT
      LAYER Metal3 ;
        RECT  0 1542.46 0.4 1542.86 ;
    END
  END mem_req_o.address[1]
  PIN mem_req_o.address[20]
    DIRECTION OUTPUT ;
    USE SIGNAL ;
    PORT
      LAYER Metal3 ;
        RECT  0 1575.22 0.4 1575.62 ;
    END
  END mem_req_o.address[20]
  PIN mem_req_o.address[21]
    DIRECTION OUTPUT ;
    USE SIGNAL ;
    PORT
      LAYER Metal3 ;
        RECT  0 1576.9 0.4 1577.3 ;
    END
  END mem_req_o.address[21]
  PIN mem_req_o.address[22]
    DIRECTION OUTPUT ;
    USE SIGNAL ;
    PORT
      LAYER Metal3 ;
        RECT  0 1578.58 0.4 1578.98 ;
    END
  END mem_req_o.address[22]
  PIN mem_req_o.address[23]
    DIRECTION OUTPUT ;
    USE SIGNAL ;
    PORT
      LAYER Metal3 ;
        RECT  0 1580.26 0.4 1580.66 ;
    END
  END mem_req_o.address[23]
  PIN mem_req_o.address[24]
    DIRECTION OUTPUT ;
    USE SIGNAL ;
    PORT
      LAYER Metal3 ;
        RECT  0 1581.94 0.4 1582.34 ;
    END
  END mem_req_o.address[24]
  PIN mem_req_o.address[25]
    DIRECTION OUTPUT ;
    USE SIGNAL ;
    PORT
      LAYER Metal3 ;
        RECT  0 1583.62 0.4 1584.02 ;
    END
  END mem_req_o.address[25]
  PIN mem_req_o.address[26]
    DIRECTION OUTPUT ;
    USE SIGNAL ;
    PORT
      LAYER Metal3 ;
        RECT  0 1585.3 0.4 1585.7 ;
    END
  END mem_req_o.address[26]
  PIN mem_req_o.address[27]
    DIRECTION OUTPUT ;
    USE SIGNAL ;
    PORT
      LAYER Metal3 ;
        RECT  0 1586.98 0.4 1587.38 ;
    END
  END mem_req_o.address[27]
  PIN mem_req_o.address[28]
    DIRECTION OUTPUT ;
    USE SIGNAL ;
    PORT
      LAYER Metal3 ;
        RECT  0 1588.66 0.4 1589.06 ;
    END
  END mem_req_o.address[28]
  PIN mem_req_o.address[29]
    DIRECTION OUTPUT ;
    USE SIGNAL ;
    PORT
      LAYER Metal3 ;
        RECT  0 1590.34 0.4 1590.74 ;
    END
  END mem_req_o.address[29]
  PIN mem_req_o.address[2]
    DIRECTION OUTPUT ;
    USE SIGNAL ;
    PORT
      LAYER Metal3 ;
        RECT  0 1544.98 0.4 1545.38 ;
    END
  END mem_req_o.address[2]
  PIN mem_req_o.address[30]
    DIRECTION OUTPUT ;
    USE SIGNAL ;
    PORT
      LAYER Metal3 ;
        RECT  0 1592.02 0.4 1592.42 ;
    END
  END mem_req_o.address[30]
  PIN mem_req_o.address[31]
    DIRECTION OUTPUT ;
    USE SIGNAL ;
    PORT
      LAYER Metal3 ;
        RECT  0 1593.7 0.4 1594.1 ;
    END
  END mem_req_o.address[31]
  PIN mem_req_o.address[3]
    DIRECTION OUTPUT ;
    USE SIGNAL ;
    PORT
      LAYER Metal3 ;
        RECT  0 1546.66 0.4 1547.06 ;
    END
  END mem_req_o.address[3]
  PIN mem_req_o.address[4]
    DIRECTION OUTPUT ;
    USE SIGNAL ;
    PORT
      LAYER Metal3 ;
        RECT  0 1548.34 0.4 1548.74 ;
    END
  END mem_req_o.address[4]
  PIN mem_req_o.address[5]
    DIRECTION OUTPUT ;
    USE SIGNAL ;
    PORT
      LAYER Metal3 ;
        RECT  0 1550.02 0.4 1550.42 ;
    END
  END mem_req_o.address[5]
  PIN mem_req_o.address[6]
    DIRECTION OUTPUT ;
    USE SIGNAL ;
    PORT
      LAYER Metal3 ;
        RECT  0 1551.7 0.4 1552.1 ;
    END
  END mem_req_o.address[6]
  PIN mem_req_o.address[7]
    DIRECTION OUTPUT ;
    USE SIGNAL ;
    PORT
      LAYER Metal3 ;
        RECT  0 1553.38 0.4 1553.78 ;
    END
  END mem_req_o.address[7]
  PIN mem_req_o.address[8]
    DIRECTION OUTPUT ;
    USE SIGNAL ;
    PORT
      LAYER Metal3 ;
        RECT  0 1555.06 0.4 1555.46 ;
    END
  END mem_req_o.address[8]
  PIN mem_req_o.address[9]
    DIRECTION OUTPUT ;
    USE SIGNAL ;
    PORT
      LAYER Metal3 ;
        RECT  0 1556.74 0.4 1557.14 ;
    END
  END mem_req_o.address[9]
  PIN mem_req_o.outside
    DIRECTION OUTPUT ;
    USE SIGNAL ;
    PORT
      LAYER Metal3 ;
        RECT  0 1536.58 0.4 1536.98 ;
    END
  END mem_req_o.outside
  PIN mem_req_o.probe
    DIRECTION OUTPUT ;
    USE SIGNAL ;
    PORT
      LAYER Metal3 ;
        RECT  0 1537.42 0.4 1537.82 ;
    END
  END mem_req_o.probe
  PIN mem_req_o.size[0]
    DIRECTION OUTPUT ;
    USE SIGNAL ;
    PORT
      LAYER Metal3 ;
        RECT  0 1540.78 0.4 1541.18 ;
    END
  END mem_req_o.size[0]
  PIN mem_req_o.size[1]
    DIRECTION OUTPUT ;
    USE SIGNAL ;
    PORT
      LAYER Metal3 ;
        RECT  0 1543.3 0.4 1543.7 ;
    END
  END mem_req_o.size[1]
  PIN mem_req_o.valid
    DIRECTION OUTPUT ;
    USE SIGNAL ;
    PORT
      LAYER Metal3 ;
        RECT  0 1538.26 0.4 1538.66 ;
    END
  END mem_req_o.valid
  PIN mem_req_o.wdata[0]
    DIRECTION OUTPUT ;
    USE SIGNAL ;
    PORT
      LAYER Metal3 ;
        RECT  0 1541.62 0.4 1542.02 ;
    END
  END mem_req_o.wdata[0]
  PIN mem_req_o.wdata[10]
    DIRECTION OUTPUT ;
    USE SIGNAL ;
    PORT
      LAYER Metal3 ;
        RECT  0 1559.26 0.4 1559.66 ;
    END
  END mem_req_o.wdata[10]
  PIN mem_req_o.wdata[11]
    DIRECTION OUTPUT ;
    USE SIGNAL ;
    PORT
      LAYER Metal3 ;
        RECT  0 1560.94 0.4 1561.34 ;
    END
  END mem_req_o.wdata[11]
  PIN mem_req_o.wdata[12]
    DIRECTION OUTPUT ;
    USE SIGNAL ;
    PORT
      LAYER Metal3 ;
        RECT  0 1562.62 0.4 1563.02 ;
    END
  END mem_req_o.wdata[12]
  PIN mem_req_o.wdata[13]
    DIRECTION OUTPUT ;
    USE SIGNAL ;
    PORT
      LAYER Metal3 ;
        RECT  0 1564.3 0.4 1564.7 ;
    END
  END mem_req_o.wdata[13]
  PIN mem_req_o.wdata[14]
    DIRECTION OUTPUT ;
    USE SIGNAL ;
    PORT
      LAYER Metal3 ;
        RECT  0 1565.98 0.4 1566.38 ;
    END
  END mem_req_o.wdata[14]
  PIN mem_req_o.wdata[15]
    DIRECTION OUTPUT ;
    USE SIGNAL ;
    PORT
      LAYER Metal3 ;
        RECT  0 1567.66 0.4 1568.06 ;
    END
  END mem_req_o.wdata[15]
  PIN mem_req_o.wdata[16]
    DIRECTION OUTPUT ;
    USE SIGNAL ;
    PORT
      LAYER Metal3 ;
        RECT  0 1569.34 0.4 1569.74 ;
    END
  END mem_req_o.wdata[16]
  PIN mem_req_o.wdata[17]
    DIRECTION OUTPUT ;
    USE SIGNAL ;
    PORT
      LAYER Metal3 ;
        RECT  0 1571.02 0.4 1571.42 ;
    END
  END mem_req_o.wdata[17]
  PIN mem_req_o.wdata[18]
    DIRECTION OUTPUT ;
    USE SIGNAL ;
    PORT
      LAYER Metal3 ;
        RECT  0 1572.7 0.4 1573.1 ;
    END
  END mem_req_o.wdata[18]
  PIN mem_req_o.wdata[19]
    DIRECTION OUTPUT ;
    USE SIGNAL ;
    PORT
      LAYER Metal3 ;
        RECT  0 1574.38 0.4 1574.78 ;
    END
  END mem_req_o.wdata[19]
  PIN mem_req_o.wdata[1]
    DIRECTION OUTPUT ;
    USE SIGNAL ;
    PORT
      LAYER Metal3 ;
        RECT  0 1544.14 0.4 1544.54 ;
    END
  END mem_req_o.wdata[1]
  PIN mem_req_o.wdata[20]
    DIRECTION OUTPUT ;
    USE SIGNAL ;
    PORT
      LAYER Metal3 ;
        RECT  0 1576.06 0.4 1576.46 ;
    END
  END mem_req_o.wdata[20]
  PIN mem_req_o.wdata[21]
    DIRECTION OUTPUT ;
    USE SIGNAL ;
    PORT
      LAYER Metal3 ;
        RECT  0 1577.74 0.4 1578.14 ;
    END
  END mem_req_o.wdata[21]
  PIN mem_req_o.wdata[22]
    DIRECTION OUTPUT ;
    USE SIGNAL ;
    PORT
      LAYER Metal3 ;
        RECT  0 1579.42 0.4 1579.82 ;
    END
  END mem_req_o.wdata[22]
  PIN mem_req_o.wdata[23]
    DIRECTION OUTPUT ;
    USE SIGNAL ;
    PORT
      LAYER Metal3 ;
        RECT  0 1581.1 0.4 1581.5 ;
    END
  END mem_req_o.wdata[23]
  PIN mem_req_o.wdata[24]
    DIRECTION OUTPUT ;
    USE SIGNAL ;
    PORT
      LAYER Metal3 ;
        RECT  0 1582.78 0.4 1583.18 ;
    END
  END mem_req_o.wdata[24]
  PIN mem_req_o.wdata[25]
    DIRECTION OUTPUT ;
    USE SIGNAL ;
    PORT
      LAYER Metal3 ;
        RECT  0 1584.46 0.4 1584.86 ;
    END
  END mem_req_o.wdata[25]
  PIN mem_req_o.wdata[26]
    DIRECTION OUTPUT ;
    USE SIGNAL ;
    PORT
      LAYER Metal3 ;
        RECT  0 1586.14 0.4 1586.54 ;
    END
  END mem_req_o.wdata[26]
  PIN mem_req_o.wdata[27]
    DIRECTION OUTPUT ;
    USE SIGNAL ;
    PORT
      LAYER Metal3 ;
        RECT  0 1587.82 0.4 1588.22 ;
    END
  END mem_req_o.wdata[27]
  PIN mem_req_o.wdata[28]
    DIRECTION OUTPUT ;
    USE SIGNAL ;
    PORT
      LAYER Metal3 ;
        RECT  0 1589.5 0.4 1589.9 ;
    END
  END mem_req_o.wdata[28]
  PIN mem_req_o.wdata[29]
    DIRECTION OUTPUT ;
    USE SIGNAL ;
    PORT
      LAYER Metal3 ;
        RECT  0 1591.18 0.4 1591.58 ;
    END
  END mem_req_o.wdata[29]
  PIN mem_req_o.wdata[2]
    DIRECTION OUTPUT ;
    USE SIGNAL ;
    PORT
      LAYER Metal3 ;
        RECT  0 1545.82 0.4 1546.22 ;
    END
  END mem_req_o.wdata[2]
  PIN mem_req_o.wdata[30]
    DIRECTION OUTPUT ;
    USE SIGNAL ;
    PORT
      LAYER Metal3 ;
        RECT  0 1592.86 0.4 1593.26 ;
    END
  END mem_req_o.wdata[30]
  PIN mem_req_o.wdata[31]
    DIRECTION OUTPUT ;
    USE SIGNAL ;
    PORT
      LAYER Metal3 ;
        RECT  0 1594.54 0.4 1594.94 ;
    END
  END mem_req_o.wdata[31]
  PIN mem_req_o.wdata[32]
    DIRECTION OUTPUT ;
    USE SIGNAL ;
    PORT
      LAYER Metal3 ;
        RECT  0 1595.38 0.4 1595.78 ;
    END
  END mem_req_o.wdata[32]
  PIN mem_req_o.wdata[33]
    DIRECTION OUTPUT ;
    USE SIGNAL ;
    PORT
      LAYER Metal3 ;
        RECT  0 1596.22 0.4 1596.62 ;
    END
  END mem_req_o.wdata[33]
  PIN mem_req_o.wdata[34]
    DIRECTION OUTPUT ;
    USE SIGNAL ;
    PORT
      LAYER Metal3 ;
        RECT  0 1597.06 0.4 1597.46 ;
    END
  END mem_req_o.wdata[34]
  PIN mem_req_o.wdata[35]
    DIRECTION OUTPUT ;
    USE SIGNAL ;
    PORT
      LAYER Metal3 ;
        RECT  0 1597.9 0.4 1598.3 ;
    END
  END mem_req_o.wdata[35]
  PIN mem_req_o.wdata[36]
    DIRECTION OUTPUT ;
    USE SIGNAL ;
    PORT
      LAYER Metal3 ;
        RECT  0 1598.74 0.4 1599.14 ;
    END
  END mem_req_o.wdata[36]
  PIN mem_req_o.wdata[37]
    DIRECTION OUTPUT ;
    USE SIGNAL ;
    PORT
      LAYER Metal3 ;
        RECT  0 1599.58 0.4 1599.98 ;
    END
  END mem_req_o.wdata[37]
  PIN mem_req_o.wdata[38]
    DIRECTION OUTPUT ;
    USE SIGNAL ;
    PORT
      LAYER Metal3 ;
        RECT  0 1600.42 0.4 1600.82 ;
    END
  END mem_req_o.wdata[38]
  PIN mem_req_o.wdata[39]
    DIRECTION OUTPUT ;
    USE SIGNAL ;
    PORT
      LAYER Metal3 ;
        RECT  0 1601.26 0.4 1601.66 ;
    END
  END mem_req_o.wdata[39]
  PIN mem_req_o.wdata[3]
    DIRECTION OUTPUT ;
    USE SIGNAL ;
    PORT
      LAYER Metal3 ;
        RECT  0 1547.5 0.4 1547.9 ;
    END
  END mem_req_o.wdata[3]
  PIN mem_req_o.wdata[40]
    DIRECTION OUTPUT ;
    USE SIGNAL ;
    PORT
      LAYER Metal3 ;
        RECT  0 1602.1 0.4 1602.5 ;
    END
  END mem_req_o.wdata[40]
  PIN mem_req_o.wdata[41]
    DIRECTION OUTPUT ;
    USE SIGNAL ;
    PORT
      LAYER Metal3 ;
        RECT  0 1602.94 0.4 1603.34 ;
    END
  END mem_req_o.wdata[41]
  PIN mem_req_o.wdata[42]
    DIRECTION OUTPUT ;
    USE SIGNAL ;
    PORT
      LAYER Metal3 ;
        RECT  0 1603.78 0.4 1604.18 ;
    END
  END mem_req_o.wdata[42]
  PIN mem_req_o.wdata[43]
    DIRECTION OUTPUT ;
    USE SIGNAL ;
    PORT
      LAYER Metal3 ;
        RECT  0 1604.62 0.4 1605.02 ;
    END
  END mem_req_o.wdata[43]
  PIN mem_req_o.wdata[44]
    DIRECTION OUTPUT ;
    USE SIGNAL ;
    PORT
      LAYER Metal3 ;
        RECT  0 1605.46 0.4 1605.86 ;
    END
  END mem_req_o.wdata[44]
  PIN mem_req_o.wdata[45]
    DIRECTION OUTPUT ;
    USE SIGNAL ;
    PORT
      LAYER Metal3 ;
        RECT  0 1606.3 0.4 1606.7 ;
    END
  END mem_req_o.wdata[45]
  PIN mem_req_o.wdata[46]
    DIRECTION OUTPUT ;
    USE SIGNAL ;
    PORT
      LAYER Metal3 ;
        RECT  0 1607.14 0.4 1607.54 ;
    END
  END mem_req_o.wdata[46]
  PIN mem_req_o.wdata[47]
    DIRECTION OUTPUT ;
    USE SIGNAL ;
    PORT
      LAYER Metal3 ;
        RECT  0 1607.98 0.4 1608.38 ;
    END
  END mem_req_o.wdata[47]
  PIN mem_req_o.wdata[48]
    DIRECTION OUTPUT ;
    USE SIGNAL ;
    PORT
      LAYER Metal3 ;
        RECT  0 1608.82 0.4 1609.22 ;
    END
  END mem_req_o.wdata[48]
  PIN mem_req_o.wdata[49]
    DIRECTION OUTPUT ;
    USE SIGNAL ;
    PORT
      LAYER Metal3 ;
        RECT  0 1609.66 0.4 1610.06 ;
    END
  END mem_req_o.wdata[49]
  PIN mem_req_o.wdata[4]
    DIRECTION OUTPUT ;
    USE SIGNAL ;
    PORT
      LAYER Metal3 ;
        RECT  0 1549.18 0.4 1549.58 ;
    END
  END mem_req_o.wdata[4]
  PIN mem_req_o.wdata[50]
    DIRECTION OUTPUT ;
    USE SIGNAL ;
    PORT
      LAYER Metal3 ;
        RECT  0 1610.5 0.4 1610.9 ;
    END
  END mem_req_o.wdata[50]
  PIN mem_req_o.wdata[51]
    DIRECTION OUTPUT ;
    USE SIGNAL ;
    PORT
      LAYER Metal3 ;
        RECT  0 1611.34 0.4 1611.74 ;
    END
  END mem_req_o.wdata[51]
  PIN mem_req_o.wdata[52]
    DIRECTION OUTPUT ;
    USE SIGNAL ;
    PORT
      LAYER Metal3 ;
        RECT  0 1612.18 0.4 1612.58 ;
    END
  END mem_req_o.wdata[52]
  PIN mem_req_o.wdata[53]
    DIRECTION OUTPUT ;
    USE SIGNAL ;
    PORT
      LAYER Metal3 ;
        RECT  0 1613.02 0.4 1613.42 ;
    END
  END mem_req_o.wdata[53]
  PIN mem_req_o.wdata[54]
    DIRECTION OUTPUT ;
    USE SIGNAL ;
    PORT
      LAYER Metal3 ;
        RECT  0 1613.86 0.4 1614.26 ;
    END
  END mem_req_o.wdata[54]
  PIN mem_req_o.wdata[55]
    DIRECTION OUTPUT ;
    USE SIGNAL ;
    PORT
      LAYER Metal3 ;
        RECT  0 1614.7 0.4 1615.1 ;
    END
  END mem_req_o.wdata[55]
  PIN mem_req_o.wdata[56]
    DIRECTION OUTPUT ;
    USE SIGNAL ;
    PORT
      LAYER Metal3 ;
        RECT  0 1615.54 0.4 1615.94 ;
    END
  END mem_req_o.wdata[56]
  PIN mem_req_o.wdata[57]
    DIRECTION OUTPUT ;
    USE SIGNAL ;
    PORT
      LAYER Metal3 ;
        RECT  0 1616.38 0.4 1616.78 ;
    END
  END mem_req_o.wdata[57]
  PIN mem_req_o.wdata[58]
    DIRECTION OUTPUT ;
    USE SIGNAL ;
    PORT
      LAYER Metal3 ;
        RECT  0 1617.22 0.4 1617.62 ;
    END
  END mem_req_o.wdata[58]
  PIN mem_req_o.wdata[59]
    DIRECTION OUTPUT ;
    USE SIGNAL ;
    PORT
      LAYER Metal3 ;
        RECT  0 1618.06 0.4 1618.46 ;
    END
  END mem_req_o.wdata[59]
  PIN mem_req_o.wdata[5]
    DIRECTION OUTPUT ;
    USE SIGNAL ;
    PORT
      LAYER Metal3 ;
        RECT  0 1550.86 0.4 1551.26 ;
    END
  END mem_req_o.wdata[5]
  PIN mem_req_o.wdata[60]
    DIRECTION OUTPUT ;
    USE SIGNAL ;
    PORT
      LAYER Metal3 ;
        RECT  0 1618.9 0.4 1619.3 ;
    END
  END mem_req_o.wdata[60]
  PIN mem_req_o.wdata[61]
    DIRECTION OUTPUT ;
    USE SIGNAL ;
    PORT
      LAYER Metal3 ;
        RECT  0 1619.74 0.4 1620.14 ;
    END
  END mem_req_o.wdata[61]
  PIN mem_req_o.wdata[62]
    DIRECTION OUTPUT ;
    USE SIGNAL ;
    PORT
      LAYER Metal3 ;
        RECT  0 1620.58 0.4 1620.98 ;
    END
  END mem_req_o.wdata[62]
  PIN mem_req_o.wdata[63]
    DIRECTION OUTPUT ;
    USE SIGNAL ;
    PORT
      LAYER Metal3 ;
        RECT  0 1621.42 0.4 1621.82 ;
    END
  END mem_req_o.wdata[63]
  PIN mem_req_o.wdata[6]
    DIRECTION OUTPUT ;
    USE SIGNAL ;
    PORT
      LAYER Metal3 ;
        RECT  0 1552.54 0.4 1552.94 ;
    END
  END mem_req_o.wdata[6]
  PIN mem_req_o.wdata[7]
    DIRECTION OUTPUT ;
    USE SIGNAL ;
    PORT
      LAYER Metal3 ;
        RECT  0 1554.22 0.4 1554.62 ;
    END
  END mem_req_o.wdata[7]
  PIN mem_req_o.wdata[8]
    DIRECTION OUTPUT ;
    USE SIGNAL ;
    PORT
      LAYER Metal3 ;
        RECT  0 1555.9 0.4 1556.3 ;
    END
  END mem_req_o.wdata[8]
  PIN mem_req_o.wdata[9]
    DIRECTION OUTPUT ;
    USE SIGNAL ;
    PORT
      LAYER Metal3 ;
        RECT  0 1557.58 0.4 1557.98 ;
    END
  END mem_req_o.wdata[9]
  PIN mem_req_o.write
    DIRECTION OUTPUT ;
    USE SIGNAL ;
    PORT
      LAYER Metal3 ;
        RECT  0 1539.1 0.4 1539.5 ;
    END
  END mem_req_o.write
  PIN mem_rsp_i.fault
    DIRECTION INPUT ;
    USE SIGNAL ;
    PORT
      LAYER Metal3 ;
        RECT  0 1643.26 0.4 1643.66 ;
    END
  END mem_rsp_i.fault
  PIN mem_rsp_i.rdata[0]
    DIRECTION INPUT ;
    USE SIGNAL ;
    PORT
      LAYER Metal3 ;
        RECT  0 1644.94 0.4 1645.34 ;
    END
  END mem_rsp_i.rdata[0]
  PIN mem_rsp_i.rdata[10]
    DIRECTION INPUT ;
    USE SIGNAL ;
    PORT
      LAYER Metal3 ;
        RECT  0 1653.34 0.4 1653.74 ;
    END
  END mem_rsp_i.rdata[10]
  PIN mem_rsp_i.rdata[11]
    DIRECTION INPUT ;
    USE SIGNAL ;
    PORT
      LAYER Metal3 ;
        RECT  0 1654.18 0.4 1654.58 ;
    END
  END mem_rsp_i.rdata[11]
  PIN mem_rsp_i.rdata[12]
    DIRECTION INPUT ;
    USE SIGNAL ;
    PORT
      LAYER Metal3 ;
        RECT  0 1655.02 0.4 1655.42 ;
    END
  END mem_rsp_i.rdata[12]
  PIN mem_rsp_i.rdata[13]
    DIRECTION INPUT ;
    USE SIGNAL ;
    PORT
      LAYER Metal3 ;
        RECT  0 1655.86 0.4 1656.26 ;
    END
  END mem_rsp_i.rdata[13]
  PIN mem_rsp_i.rdata[14]
    DIRECTION INPUT ;
    USE SIGNAL ;
    PORT
      LAYER Metal3 ;
        RECT  0 1656.7 0.4 1657.1 ;
    END
  END mem_rsp_i.rdata[14]
  PIN mem_rsp_i.rdata[15]
    DIRECTION INPUT ;
    USE SIGNAL ;
    PORT
      LAYER Metal3 ;
        RECT  0 1657.54 0.4 1657.94 ;
    END
  END mem_rsp_i.rdata[15]
  PIN mem_rsp_i.rdata[16]
    DIRECTION INPUT ;
    USE SIGNAL ;
    PORT
      LAYER Metal3 ;
        RECT  0 1658.38 0.4 1658.78 ;
    END
  END mem_rsp_i.rdata[16]
  PIN mem_rsp_i.rdata[17]
    DIRECTION INPUT ;
    USE SIGNAL ;
    PORT
      LAYER Metal3 ;
        RECT  0 1659.22 0.4 1659.62 ;
    END
  END mem_rsp_i.rdata[17]
  PIN mem_rsp_i.rdata[18]
    DIRECTION INPUT ;
    USE SIGNAL ;
    PORT
      LAYER Metal3 ;
        RECT  0 1660.06 0.4 1660.46 ;
    END
  END mem_rsp_i.rdata[18]
  PIN mem_rsp_i.rdata[19]
    DIRECTION INPUT ;
    USE SIGNAL ;
    PORT
      LAYER Metal3 ;
        RECT  0 1660.9 0.4 1661.3 ;
    END
  END mem_rsp_i.rdata[19]
  PIN mem_rsp_i.rdata[1]
    DIRECTION INPUT ;
    USE SIGNAL ;
    PORT
      LAYER Metal3 ;
        RECT  0 1645.78 0.4 1646.18 ;
    END
  END mem_rsp_i.rdata[1]
  PIN mem_rsp_i.rdata[20]
    DIRECTION INPUT ;
    USE SIGNAL ;
    PORT
      LAYER Metal3 ;
        RECT  0 1661.74 0.4 1662.14 ;
    END
  END mem_rsp_i.rdata[20]
  PIN mem_rsp_i.rdata[21]
    DIRECTION INPUT ;
    USE SIGNAL ;
    PORT
      LAYER Metal3 ;
        RECT  0 1662.58 0.4 1662.98 ;
    END
  END mem_rsp_i.rdata[21]
  PIN mem_rsp_i.rdata[22]
    DIRECTION INPUT ;
    USE SIGNAL ;
    PORT
      LAYER Metal3 ;
        RECT  0 1663.42 0.4 1663.82 ;
    END
  END mem_rsp_i.rdata[22]
  PIN mem_rsp_i.rdata[23]
    DIRECTION INPUT ;
    USE SIGNAL ;
    PORT
      LAYER Metal3 ;
        RECT  0 1664.26 0.4 1664.66 ;
    END
  END mem_rsp_i.rdata[23]
  PIN mem_rsp_i.rdata[24]
    DIRECTION INPUT ;
    USE SIGNAL ;
    PORT
      LAYER Metal3 ;
        RECT  0 1665.1 0.4 1665.5 ;
    END
  END mem_rsp_i.rdata[24]
  PIN mem_rsp_i.rdata[25]
    DIRECTION INPUT ;
    USE SIGNAL ;
    PORT
      LAYER Metal3 ;
        RECT  0 1665.94 0.4 1666.34 ;
    END
  END mem_rsp_i.rdata[25]
  PIN mem_rsp_i.rdata[26]
    DIRECTION INPUT ;
    USE SIGNAL ;
    PORT
      LAYER Metal3 ;
        RECT  0 1666.78 0.4 1667.18 ;
    END
  END mem_rsp_i.rdata[26]
  PIN mem_rsp_i.rdata[27]
    DIRECTION INPUT ;
    USE SIGNAL ;
    PORT
      LAYER Metal3 ;
        RECT  0 1667.62 0.4 1668.02 ;
    END
  END mem_rsp_i.rdata[27]
  PIN mem_rsp_i.rdata[28]
    DIRECTION INPUT ;
    USE SIGNAL ;
    PORT
      LAYER Metal3 ;
        RECT  0 1668.46 0.4 1668.86 ;
    END
  END mem_rsp_i.rdata[28]
  PIN mem_rsp_i.rdata[29]
    DIRECTION INPUT ;
    USE SIGNAL ;
    PORT
      LAYER Metal3 ;
        RECT  0 1669.3 0.4 1669.7 ;
    END
  END mem_rsp_i.rdata[29]
  PIN mem_rsp_i.rdata[2]
    DIRECTION INPUT ;
    USE SIGNAL ;
    PORT
      LAYER Metal3 ;
        RECT  0 1646.62 0.4 1647.02 ;
    END
  END mem_rsp_i.rdata[2]
  PIN mem_rsp_i.rdata[30]
    DIRECTION INPUT ;
    USE SIGNAL ;
    PORT
      LAYER Metal3 ;
        RECT  0 1670.14 0.4 1670.54 ;
    END
  END mem_rsp_i.rdata[30]
  PIN mem_rsp_i.rdata[31]
    DIRECTION INPUT ;
    USE SIGNAL ;
    PORT
      LAYER Metal3 ;
        RECT  0 1670.98 0.4 1671.38 ;
    END
  END mem_rsp_i.rdata[31]
  PIN mem_rsp_i.rdata[32]
    DIRECTION INPUT ;
    USE SIGNAL ;
    PORT
      LAYER Metal3 ;
        RECT  0 1671.82 0.4 1672.22 ;
    END
  END mem_rsp_i.rdata[32]
  PIN mem_rsp_i.rdata[33]
    DIRECTION INPUT ;
    USE SIGNAL ;
    PORT
      LAYER Metal3 ;
        RECT  0 1672.66 0.4 1673.06 ;
    END
  END mem_rsp_i.rdata[33]
  PIN mem_rsp_i.rdata[34]
    DIRECTION INPUT ;
    USE SIGNAL ;
    PORT
      LAYER Metal3 ;
        RECT  0 1673.5 0.4 1673.9 ;
    END
  END mem_rsp_i.rdata[34]
  PIN mem_rsp_i.rdata[35]
    DIRECTION INPUT ;
    USE SIGNAL ;
    PORT
      LAYER Metal3 ;
        RECT  0 1674.34 0.4 1674.74 ;
    END
  END mem_rsp_i.rdata[35]
  PIN mem_rsp_i.rdata[36]
    DIRECTION INPUT ;
    USE SIGNAL ;
    PORT
      LAYER Metal3 ;
        RECT  0 1675.18 0.4 1675.58 ;
    END
  END mem_rsp_i.rdata[36]
  PIN mem_rsp_i.rdata[37]
    DIRECTION INPUT ;
    USE SIGNAL ;
    PORT
      LAYER Metal3 ;
        RECT  0 1676.02 0.4 1676.42 ;
    END
  END mem_rsp_i.rdata[37]
  PIN mem_rsp_i.rdata[38]
    DIRECTION INPUT ;
    USE SIGNAL ;
    PORT
      LAYER Metal3 ;
        RECT  0 1676.86 0.4 1677.26 ;
    END
  END mem_rsp_i.rdata[38]
  PIN mem_rsp_i.rdata[39]
    DIRECTION INPUT ;
    USE SIGNAL ;
    PORT
      LAYER Metal3 ;
        RECT  0 1677.7 0.4 1678.1 ;
    END
  END mem_rsp_i.rdata[39]
  PIN mem_rsp_i.rdata[3]
    DIRECTION INPUT ;
    USE SIGNAL ;
    PORT
      LAYER Metal3 ;
        RECT  0 1647.46 0.4 1647.86 ;
    END
  END mem_rsp_i.rdata[3]
  PIN mem_rsp_i.rdata[40]
    DIRECTION INPUT ;
    USE SIGNAL ;
    PORT
      LAYER Metal3 ;
        RECT  0 1678.54 0.4 1678.94 ;
    END
  END mem_rsp_i.rdata[40]
  PIN mem_rsp_i.rdata[41]
    DIRECTION INPUT ;
    USE SIGNAL ;
    PORT
      LAYER Metal3 ;
        RECT  0 1679.38 0.4 1679.78 ;
    END
  END mem_rsp_i.rdata[41]
  PIN mem_rsp_i.rdata[42]
    DIRECTION INPUT ;
    USE SIGNAL ;
    PORT
      LAYER Metal3 ;
        RECT  0 1680.22 0.4 1680.62 ;
    END
  END mem_rsp_i.rdata[42]
  PIN mem_rsp_i.rdata[43]
    DIRECTION INPUT ;
    USE SIGNAL ;
    PORT
      LAYER Metal3 ;
        RECT  0 1681.06 0.4 1681.46 ;
    END
  END mem_rsp_i.rdata[43]
  PIN mem_rsp_i.rdata[44]
    DIRECTION INPUT ;
    USE SIGNAL ;
    PORT
      LAYER Metal3 ;
        RECT  0 1681.9 0.4 1682.3 ;
    END
  END mem_rsp_i.rdata[44]
  PIN mem_rsp_i.rdata[45]
    DIRECTION INPUT ;
    USE SIGNAL ;
    PORT
      LAYER Metal3 ;
        RECT  0 1682.74 0.4 1683.14 ;
    END
  END mem_rsp_i.rdata[45]
  PIN mem_rsp_i.rdata[46]
    DIRECTION INPUT ;
    USE SIGNAL ;
    PORT
      LAYER Metal3 ;
        RECT  0 1683.58 0.4 1683.98 ;
    END
  END mem_rsp_i.rdata[46]
  PIN mem_rsp_i.rdata[47]
    DIRECTION INPUT ;
    USE SIGNAL ;
    PORT
      LAYER Metal3 ;
        RECT  0 1684.42 0.4 1684.82 ;
    END
  END mem_rsp_i.rdata[47]
  PIN mem_rsp_i.rdata[48]
    DIRECTION INPUT ;
    USE SIGNAL ;
    PORT
      LAYER Metal3 ;
        RECT  0 1685.26 0.4 1685.66 ;
    END
  END mem_rsp_i.rdata[48]
  PIN mem_rsp_i.rdata[49]
    DIRECTION INPUT ;
    USE SIGNAL ;
    PORT
      LAYER Metal3 ;
        RECT  0 1686.1 0.4 1686.5 ;
    END
  END mem_rsp_i.rdata[49]
  PIN mem_rsp_i.rdata[4]
    DIRECTION INPUT ;
    USE SIGNAL ;
    PORT
      LAYER Metal3 ;
        RECT  0 1648.3 0.4 1648.7 ;
    END
  END mem_rsp_i.rdata[4]
  PIN mem_rsp_i.rdata[50]
    DIRECTION INPUT ;
    USE SIGNAL ;
    PORT
      LAYER Metal3 ;
        RECT  0 1686.94 0.4 1687.34 ;
    END
  END mem_rsp_i.rdata[50]
  PIN mem_rsp_i.rdata[51]
    DIRECTION INPUT ;
    USE SIGNAL ;
    PORT
      LAYER Metal3 ;
        RECT  0 1687.78 0.4 1688.18 ;
    END
  END mem_rsp_i.rdata[51]
  PIN mem_rsp_i.rdata[52]
    DIRECTION INPUT ;
    USE SIGNAL ;
    PORT
      LAYER Metal3 ;
        RECT  0 1688.62 0.4 1689.02 ;
    END
  END mem_rsp_i.rdata[52]
  PIN mem_rsp_i.rdata[53]
    DIRECTION INPUT ;
    USE SIGNAL ;
    PORT
      LAYER Metal3 ;
        RECT  0 1689.46 0.4 1689.86 ;
    END
  END mem_rsp_i.rdata[53]
  PIN mem_rsp_i.rdata[54]
    DIRECTION INPUT ;
    USE SIGNAL ;
    PORT
      LAYER Metal3 ;
        RECT  0 1690.3 0.4 1690.7 ;
    END
  END mem_rsp_i.rdata[54]
  PIN mem_rsp_i.rdata[55]
    DIRECTION INPUT ;
    USE SIGNAL ;
    PORT
      LAYER Metal3 ;
        RECT  0 1691.14 0.4 1691.54 ;
    END
  END mem_rsp_i.rdata[55]
  PIN mem_rsp_i.rdata[56]
    DIRECTION INPUT ;
    USE SIGNAL ;
    PORT
      LAYER Metal3 ;
        RECT  0 1691.98 0.4 1692.38 ;
    END
  END mem_rsp_i.rdata[56]
  PIN mem_rsp_i.rdata[57]
    DIRECTION INPUT ;
    USE SIGNAL ;
    PORT
      LAYER Metal3 ;
        RECT  0 1692.82 0.4 1693.22 ;
    END
  END mem_rsp_i.rdata[57]
  PIN mem_rsp_i.rdata[58]
    DIRECTION INPUT ;
    USE SIGNAL ;
    PORT
      LAYER Metal3 ;
        RECT  0 1693.66 0.4 1694.06 ;
    END
  END mem_rsp_i.rdata[58]
  PIN mem_rsp_i.rdata[59]
    DIRECTION INPUT ;
    USE SIGNAL ;
    PORT
      LAYER Metal3 ;
        RECT  0 1694.5 0.4 1694.9 ;
    END
  END mem_rsp_i.rdata[59]
  PIN mem_rsp_i.rdata[5]
    DIRECTION INPUT ;
    USE SIGNAL ;
    PORT
      LAYER Metal3 ;
        RECT  0 1649.14 0.4 1649.54 ;
    END
  END mem_rsp_i.rdata[5]
  PIN mem_rsp_i.rdata[60]
    DIRECTION INPUT ;
    USE SIGNAL ;
    PORT
      LAYER Metal3 ;
        RECT  0 1695.34 0.4 1695.74 ;
    END
  END mem_rsp_i.rdata[60]
  PIN mem_rsp_i.rdata[61]
    DIRECTION INPUT ;
    USE SIGNAL ;
    PORT
      LAYER Metal3 ;
        RECT  0 1696.18 0.4 1696.58 ;
    END
  END mem_rsp_i.rdata[61]
  PIN mem_rsp_i.rdata[62]
    DIRECTION INPUT ;
    USE SIGNAL ;
    PORT
      LAYER Metal3 ;
        RECT  0 1697.02 0.4 1697.42 ;
    END
  END mem_rsp_i.rdata[62]
  PIN mem_rsp_i.rdata[63]
    DIRECTION INPUT ;
    USE SIGNAL ;
    PORT
      LAYER Metal3 ;
        RECT  0 1697.86 0.4 1698.26 ;
    END
  END mem_rsp_i.rdata[63]
  PIN mem_rsp_i.rdata[6]
    DIRECTION INPUT ;
    USE SIGNAL ;
    PORT
      LAYER Metal3 ;
        RECT  0 1649.98 0.4 1650.38 ;
    END
  END mem_rsp_i.rdata[6]
  PIN mem_rsp_i.rdata[7]
    DIRECTION INPUT ;
    USE SIGNAL ;
    PORT
      LAYER Metal3 ;
        RECT  0 1650.82 0.4 1651.22 ;
    END
  END mem_rsp_i.rdata[7]
  PIN mem_rsp_i.rdata[8]
    DIRECTION INPUT ;
    USE SIGNAL ;
    PORT
      LAYER Metal3 ;
        RECT  0 1651.66 0.4 1652.06 ;
    END
  END mem_rsp_i.rdata[8]
  PIN mem_rsp_i.rdata[9]
    DIRECTION INPUT ;
    USE SIGNAL ;
    PORT
      LAYER Metal3 ;
        RECT  0 1652.5 0.4 1652.9 ;
    END
  END mem_rsp_i.rdata[9]
  PIN mem_rsp_i.valid
    DIRECTION INPUT ;
    USE SIGNAL ;
    PORT
      LAYER Metal3 ;
        RECT  0 1644.1 0.4 1644.5 ;
    END
  END mem_rsp_i.valid
  PIN redirect_pc_o[0]
    DIRECTION OUTPUT ;
    USE SIGNAL ;
    PORT
      LAYER Metal2 ;
        RECT  547.48 1749.6 547.88 1750 ;
    END
  END redirect_pc_o[0]
  PIN redirect_pc_o[10]
    DIRECTION OUTPUT ;
    USE SIGNAL ;
    PORT
      LAYER Metal2 ;
        RECT  557.08 1749.6 557.48 1750 ;
    END
  END redirect_pc_o[10]
  PIN redirect_pc_o[11]
    DIRECTION OUTPUT ;
    USE SIGNAL ;
    PORT
      LAYER Metal2 ;
        RECT  558.04 1749.6 558.44 1750 ;
    END
  END redirect_pc_o[11]
  PIN redirect_pc_o[12]
    DIRECTION OUTPUT ;
    USE SIGNAL ;
    PORT
      LAYER Metal2 ;
        RECT  559 1749.6 559.4 1750 ;
    END
  END redirect_pc_o[12]
  PIN redirect_pc_o[13]
    DIRECTION OUTPUT ;
    USE SIGNAL ;
    PORT
      LAYER Metal2 ;
        RECT  559.96 1749.6 560.36 1750 ;
    END
  END redirect_pc_o[13]
  PIN redirect_pc_o[14]
    DIRECTION OUTPUT ;
    USE SIGNAL ;
    PORT
      LAYER Metal2 ;
        RECT  560.92 1749.6 561.32 1750 ;
    END
  END redirect_pc_o[14]
  PIN redirect_pc_o[15]
    DIRECTION OUTPUT ;
    USE SIGNAL ;
    PORT
      LAYER Metal2 ;
        RECT  561.88 1749.6 562.28 1750 ;
    END
  END redirect_pc_o[15]
  PIN redirect_pc_o[16]
    DIRECTION OUTPUT ;
    USE SIGNAL ;
    PORT
      LAYER Metal2 ;
        RECT  562.84 1749.6 563.24 1750 ;
    END
  END redirect_pc_o[16]
  PIN redirect_pc_o[17]
    DIRECTION OUTPUT ;
    USE SIGNAL ;
    PORT
      LAYER Metal2 ;
        RECT  563.8 1749.6 564.2 1750 ;
    END
  END redirect_pc_o[17]
  PIN redirect_pc_o[18]
    DIRECTION OUTPUT ;
    USE SIGNAL ;
    PORT
      LAYER Metal2 ;
        RECT  564.76 1749.6 565.16 1750 ;
    END
  END redirect_pc_o[18]
  PIN redirect_pc_o[19]
    DIRECTION OUTPUT ;
    USE SIGNAL ;
    PORT
      LAYER Metal2 ;
        RECT  565.72 1749.6 566.12 1750 ;
    END
  END redirect_pc_o[19]
  PIN redirect_pc_o[1]
    DIRECTION OUTPUT ;
    USE SIGNAL ;
    PORT
      LAYER Metal2 ;
        RECT  548.44 1749.6 548.84 1750 ;
    END
  END redirect_pc_o[1]
  PIN redirect_pc_o[20]
    DIRECTION OUTPUT ;
    USE SIGNAL ;
    PORT
      LAYER Metal2 ;
        RECT  566.68 1749.6 567.08 1750 ;
    END
  END redirect_pc_o[20]
  PIN redirect_pc_o[21]
    DIRECTION OUTPUT ;
    USE SIGNAL ;
    PORT
      LAYER Metal2 ;
        RECT  567.64 1749.6 568.04 1750 ;
    END
  END redirect_pc_o[21]
  PIN redirect_pc_o[22]
    DIRECTION OUTPUT ;
    USE SIGNAL ;
    PORT
      LAYER Metal2 ;
        RECT  568.6 1749.6 569 1750 ;
    END
  END redirect_pc_o[22]
  PIN redirect_pc_o[23]
    DIRECTION OUTPUT ;
    USE SIGNAL ;
    PORT
      LAYER Metal2 ;
        RECT  569.56 1749.6 569.96 1750 ;
    END
  END redirect_pc_o[23]
  PIN redirect_pc_o[24]
    DIRECTION OUTPUT ;
    USE SIGNAL ;
    PORT
      LAYER Metal2 ;
        RECT  570.52 1749.6 570.92 1750 ;
    END
  END redirect_pc_o[24]
  PIN redirect_pc_o[25]
    DIRECTION OUTPUT ;
    USE SIGNAL ;
    PORT
      LAYER Metal2 ;
        RECT  571.48 1749.6 571.88 1750 ;
    END
  END redirect_pc_o[25]
  PIN redirect_pc_o[26]
    DIRECTION OUTPUT ;
    USE SIGNAL ;
    PORT
      LAYER Metal2 ;
        RECT  572.44 1749.6 572.84 1750 ;
    END
  END redirect_pc_o[26]
  PIN redirect_pc_o[27]
    DIRECTION OUTPUT ;
    USE SIGNAL ;
    PORT
      LAYER Metal2 ;
        RECT  573.4 1749.6 573.8 1750 ;
    END
  END redirect_pc_o[27]
  PIN redirect_pc_o[28]
    DIRECTION OUTPUT ;
    USE SIGNAL ;
    PORT
      LAYER Metal2 ;
        RECT  574.36 1749.6 574.76 1750 ;
    END
  END redirect_pc_o[28]
  PIN redirect_pc_o[29]
    DIRECTION OUTPUT ;
    USE SIGNAL ;
    PORT
      LAYER Metal2 ;
        RECT  575.32 1749.6 575.72 1750 ;
    END
  END redirect_pc_o[29]
  PIN redirect_pc_o[2]
    DIRECTION OUTPUT ;
    USE SIGNAL ;
    PORT
      LAYER Metal2 ;
        RECT  549.4 1749.6 549.8 1750 ;
    END
  END redirect_pc_o[2]
  PIN redirect_pc_o[30]
    DIRECTION OUTPUT ;
    USE SIGNAL ;
    PORT
      LAYER Metal2 ;
        RECT  576.28 1749.6 576.68 1750 ;
    END
  END redirect_pc_o[30]
  PIN redirect_pc_o[31]
    DIRECTION OUTPUT ;
    USE SIGNAL ;
    PORT
      LAYER Metal2 ;
        RECT  577.24 1749.6 577.64 1750 ;
    END
  END redirect_pc_o[31]
  PIN redirect_pc_o[3]
    DIRECTION OUTPUT ;
    USE SIGNAL ;
    PORT
      LAYER Metal2 ;
        RECT  550.36 1749.6 550.76 1750 ;
    END
  END redirect_pc_o[3]
  PIN redirect_pc_o[4]
    DIRECTION OUTPUT ;
    USE SIGNAL ;
    PORT
      LAYER Metal2 ;
        RECT  551.32 1749.6 551.72 1750 ;
    END
  END redirect_pc_o[4]
  PIN redirect_pc_o[5]
    DIRECTION OUTPUT ;
    USE SIGNAL ;
    PORT
      LAYER Metal2 ;
        RECT  552.28 1749.6 552.68 1750 ;
    END
  END redirect_pc_o[5]
  PIN redirect_pc_o[6]
    DIRECTION OUTPUT ;
    USE SIGNAL ;
    PORT
      LAYER Metal2 ;
        RECT  553.24 1749.6 553.64 1750 ;
    END
  END redirect_pc_o[6]
  PIN redirect_pc_o[7]
    DIRECTION OUTPUT ;
    USE SIGNAL ;
    PORT
      LAYER Metal2 ;
        RECT  554.2 1749.6 554.6 1750 ;
    END
  END redirect_pc_o[7]
  PIN redirect_pc_o[8]
    DIRECTION OUTPUT ;
    USE SIGNAL ;
    PORT
      LAYER Metal2 ;
        RECT  555.16 1749.6 555.56 1750 ;
    END
  END redirect_pc_o[8]
  PIN redirect_pc_o[9]
    DIRECTION OUTPUT ;
    USE SIGNAL ;
    PORT
      LAYER Metal2 ;
        RECT  556.12 1749.6 556.52 1750 ;
    END
  END redirect_pc_o[9]
  PIN redirect_valid_o
    DIRECTION OUTPUT ;
    USE SIGNAL ;
    PORT
      LAYER Metal2 ;
        RECT  536.92 1749.6 537.32 1750 ;
    END
  END redirect_valid_o
  PIN reset_i
    DIRECTION INPUT ;
    USE SIGNAL ;
    PORT
      LAYER Metal2 ;
        RECT  249.88 1749.6 250.28 1750 ;
    END
  END reset_i
  PIN resume_pc_i[0]
    DIRECTION INPUT ;
    USE SIGNAL ;
    PORT
      LAYER Metal2 ;
        RECT  333.4 0 333.8 0.4 ;
    END
  END resume_pc_i[0]
  PIN resume_pc_i[10]
    DIRECTION INPUT ;
    USE SIGNAL ;
    PORT
      LAYER Metal2 ;
        RECT  343 0 343.4 0.4 ;
    END
  END resume_pc_i[10]
  PIN resume_pc_i[11]
    DIRECTION INPUT ;
    USE SIGNAL ;
    PORT
      LAYER Metal2 ;
        RECT  343.96 0 344.36 0.4 ;
    END
  END resume_pc_i[11]
  PIN resume_pc_i[12]
    DIRECTION INPUT ;
    USE SIGNAL ;
    PORT
      LAYER Metal2 ;
        RECT  344.92 0 345.32 0.4 ;
    END
  END resume_pc_i[12]
  PIN resume_pc_i[13]
    DIRECTION INPUT ;
    USE SIGNAL ;
    PORT
      LAYER Metal2 ;
        RECT  345.88 0 346.28 0.4 ;
    END
  END resume_pc_i[13]
  PIN resume_pc_i[14]
    DIRECTION INPUT ;
    USE SIGNAL ;
    PORT
      LAYER Metal2 ;
        RECT  346.84 0 347.24 0.4 ;
    END
  END resume_pc_i[14]
  PIN resume_pc_i[15]
    DIRECTION INPUT ;
    USE SIGNAL ;
    PORT
      LAYER Metal2 ;
        RECT  347.8 0 348.2 0.4 ;
    END
  END resume_pc_i[15]
  PIN resume_pc_i[16]
    DIRECTION INPUT ;
    USE SIGNAL ;
    PORT
      LAYER Metal2 ;
        RECT  348.76 0 349.16 0.4 ;
    END
  END resume_pc_i[16]
  PIN resume_pc_i[17]
    DIRECTION INPUT ;
    USE SIGNAL ;
    PORT
      LAYER Metal2 ;
        RECT  349.72 0 350.12 0.4 ;
    END
  END resume_pc_i[17]
  PIN resume_pc_i[18]
    DIRECTION INPUT ;
    USE SIGNAL ;
    PORT
      LAYER Metal2 ;
        RECT  350.68 0 351.08 0.4 ;
    END
  END resume_pc_i[18]
  PIN resume_pc_i[19]
    DIRECTION INPUT ;
    USE SIGNAL ;
    PORT
      LAYER Metal2 ;
        RECT  351.64 0 352.04 0.4 ;
    END
  END resume_pc_i[19]
  PIN resume_pc_i[1]
    DIRECTION INPUT ;
    USE SIGNAL ;
    PORT
      LAYER Metal2 ;
        RECT  334.36 0 334.76 0.4 ;
    END
  END resume_pc_i[1]
  PIN resume_pc_i[20]
    DIRECTION INPUT ;
    USE SIGNAL ;
    PORT
      LAYER Metal2 ;
        RECT  352.6 0 353 0.4 ;
    END
  END resume_pc_i[20]
  PIN resume_pc_i[21]
    DIRECTION INPUT ;
    USE SIGNAL ;
    PORT
      LAYER Metal2 ;
        RECT  353.56 0 353.96 0.4 ;
    END
  END resume_pc_i[21]
  PIN resume_pc_i[22]
    DIRECTION INPUT ;
    USE SIGNAL ;
    PORT
      LAYER Metal2 ;
        RECT  354.52 0 354.92 0.4 ;
    END
  END resume_pc_i[22]
  PIN resume_pc_i[23]
    DIRECTION INPUT ;
    USE SIGNAL ;
    PORT
      LAYER Metal2 ;
        RECT  355.48 0 355.88 0.4 ;
    END
  END resume_pc_i[23]
  PIN resume_pc_i[24]
    DIRECTION INPUT ;
    USE SIGNAL ;
    PORT
      LAYER Metal2 ;
        RECT  356.44 0 356.84 0.4 ;
    END
  END resume_pc_i[24]
  PIN resume_pc_i[25]
    DIRECTION INPUT ;
    USE SIGNAL ;
    PORT
      LAYER Metal2 ;
        RECT  357.4 0 357.8 0.4 ;
    END
  END resume_pc_i[25]
  PIN resume_pc_i[26]
    DIRECTION INPUT ;
    USE SIGNAL ;
    PORT
      LAYER Metal2 ;
        RECT  358.36 0 358.76 0.4 ;
    END
  END resume_pc_i[26]
  PIN resume_pc_i[27]
    DIRECTION INPUT ;
    USE SIGNAL ;
    PORT
      LAYER Metal2 ;
        RECT  359.32 0 359.72 0.4 ;
    END
  END resume_pc_i[27]
  PIN resume_pc_i[28]
    DIRECTION INPUT ;
    USE SIGNAL ;
    PORT
      LAYER Metal2 ;
        RECT  360.28 0 360.68 0.4 ;
    END
  END resume_pc_i[28]
  PIN resume_pc_i[29]
    DIRECTION INPUT ;
    USE SIGNAL ;
    PORT
      LAYER Metal2 ;
        RECT  361.24 0 361.64 0.4 ;
    END
  END resume_pc_i[29]
  PIN resume_pc_i[2]
    DIRECTION INPUT ;
    USE SIGNAL ;
    PORT
      LAYER Metal2 ;
        RECT  335.32 0 335.72 0.4 ;
    END
  END resume_pc_i[2]
  PIN resume_pc_i[30]
    DIRECTION INPUT ;
    USE SIGNAL ;
    PORT
      LAYER Metal2 ;
        RECT  362.2 0 362.6 0.4 ;
    END
  END resume_pc_i[30]
  PIN resume_pc_i[31]
    DIRECTION INPUT ;
    USE SIGNAL ;
    PORT
      LAYER Metal2 ;
        RECT  363.16 0 363.56 0.4 ;
    END
  END resume_pc_i[31]
  PIN resume_pc_i[3]
    DIRECTION INPUT ;
    USE SIGNAL ;
    PORT
      LAYER Metal2 ;
        RECT  336.28 0 336.68 0.4 ;
    END
  END resume_pc_i[3]
  PIN resume_pc_i[4]
    DIRECTION INPUT ;
    USE SIGNAL ;
    PORT
      LAYER Metal2 ;
        RECT  337.24 0 337.64 0.4 ;
    END
  END resume_pc_i[4]
  PIN resume_pc_i[5]
    DIRECTION INPUT ;
    USE SIGNAL ;
    PORT
      LAYER Metal2 ;
        RECT  338.2 0 338.6 0.4 ;
    END
  END resume_pc_i[5]
  PIN resume_pc_i[6]
    DIRECTION INPUT ;
    USE SIGNAL ;
    PORT
      LAYER Metal2 ;
        RECT  339.16 0 339.56 0.4 ;
    END
  END resume_pc_i[6]
  PIN resume_pc_i[7]
    DIRECTION INPUT ;
    USE SIGNAL ;
    PORT
      LAYER Metal2 ;
        RECT  340.12 0 340.52 0.4 ;
    END
  END resume_pc_i[7]
  PIN resume_pc_i[8]
    DIRECTION INPUT ;
    USE SIGNAL ;
    PORT
      LAYER Metal2 ;
        RECT  341.08 0 341.48 0.4 ;
    END
  END resume_pc_i[8]
  PIN resume_pc_i[9]
    DIRECTION INPUT ;
    USE SIGNAL ;
    PORT
      LAYER Metal2 ;
        RECT  342.04 0 342.44 0.4 ;
    END
  END resume_pc_i[9]
  PIN resume_req_i
    DIRECTION INPUT ;
    USE SIGNAL ;
    PORT
      LAYER Metal2 ;
        RECT  322.84 0 323.24 0.4 ;
    END
  END resume_req_i
  PIN stack_maint_done_i
    DIRECTION INPUT ;
    USE SIGNAL ;
    PORT
      LAYER Metal3 ;
        RECT  0 1708.78 0.4 1709.18 ;
    END
  END stack_maint_done_i
  PIN stack_maint_o.base[0]
    DIRECTION OUTPUT ;
    USE SIGNAL ;
    PORT
      LAYER Metal3 ;
        RECT  0 222.82 0.4 223.22 ;
    END
  END stack_maint_o.base[0]
  PIN stack_maint_o.base[10]
    DIRECTION OUTPUT ;
    USE SIGNAL ;
    PORT
      LAYER Metal3 ;
        RECT  0 241.3 0.4 241.7 ;
    END
  END stack_maint_o.base[10]
  PIN stack_maint_o.base[11]
    DIRECTION OUTPUT ;
    USE SIGNAL ;
    PORT
      LAYER Metal3 ;
        RECT  0 242.98 0.4 243.38 ;
    END
  END stack_maint_o.base[11]
  PIN stack_maint_o.base[12]
    DIRECTION OUTPUT ;
    USE SIGNAL ;
    PORT
      LAYER Metal3 ;
        RECT  0 244.66 0.4 245.06 ;
    END
  END stack_maint_o.base[12]
  PIN stack_maint_o.base[13]
    DIRECTION OUTPUT ;
    USE SIGNAL ;
    PORT
      LAYER Metal3 ;
        RECT  0 246.34 0.4 246.74 ;
    END
  END stack_maint_o.base[13]
  PIN stack_maint_o.base[14]
    DIRECTION OUTPUT ;
    USE SIGNAL ;
    PORT
      LAYER Metal3 ;
        RECT  0 248.02 0.4 248.42 ;
    END
  END stack_maint_o.base[14]
  PIN stack_maint_o.base[15]
    DIRECTION OUTPUT ;
    USE SIGNAL ;
    PORT
      LAYER Metal3 ;
        RECT  0 249.7 0.4 250.1 ;
    END
  END stack_maint_o.base[15]
  PIN stack_maint_o.base[16]
    DIRECTION OUTPUT ;
    USE SIGNAL ;
    PORT
      LAYER Metal3 ;
        RECT  0 251.38 0.4 251.78 ;
    END
  END stack_maint_o.base[16]
  PIN stack_maint_o.base[17]
    DIRECTION OUTPUT ;
    USE SIGNAL ;
    PORT
      LAYER Metal3 ;
        RECT  0 253.06 0.4 253.46 ;
    END
  END stack_maint_o.base[17]
  PIN stack_maint_o.base[18]
    DIRECTION OUTPUT ;
    USE SIGNAL ;
    PORT
      LAYER Metal3 ;
        RECT  0 254.74 0.4 255.14 ;
    END
  END stack_maint_o.base[18]
  PIN stack_maint_o.base[19]
    DIRECTION OUTPUT ;
    USE SIGNAL ;
    PORT
      LAYER Metal3 ;
        RECT  0 256.42 0.4 256.82 ;
    END
  END stack_maint_o.base[19]
  PIN stack_maint_o.base[1]
    DIRECTION OUTPUT ;
    USE SIGNAL ;
    PORT
      LAYER Metal3 ;
        RECT  0 225.34 0.4 225.74 ;
    END
  END stack_maint_o.base[1]
  PIN stack_maint_o.base[20]
    DIRECTION OUTPUT ;
    USE SIGNAL ;
    PORT
      LAYER Metal3 ;
        RECT  0 258.1 0.4 258.5 ;
    END
  END stack_maint_o.base[20]
  PIN stack_maint_o.base[21]
    DIRECTION OUTPUT ;
    USE SIGNAL ;
    PORT
      LAYER Metal3 ;
        RECT  0 259.78 0.4 260.18 ;
    END
  END stack_maint_o.base[21]
  PIN stack_maint_o.base[22]
    DIRECTION OUTPUT ;
    USE SIGNAL ;
    PORT
      LAYER Metal3 ;
        RECT  0 261.46 0.4 261.86 ;
    END
  END stack_maint_o.base[22]
  PIN stack_maint_o.base[23]
    DIRECTION OUTPUT ;
    USE SIGNAL ;
    PORT
      LAYER Metal3 ;
        RECT  0 263.14 0.4 263.54 ;
    END
  END stack_maint_o.base[23]
  PIN stack_maint_o.base[24]
    DIRECTION OUTPUT ;
    USE SIGNAL ;
    PORT
      LAYER Metal3 ;
        RECT  0 264.82 0.4 265.22 ;
    END
  END stack_maint_o.base[24]
  PIN stack_maint_o.base[25]
    DIRECTION OUTPUT ;
    USE SIGNAL ;
    PORT
      LAYER Metal3 ;
        RECT  0 266.5 0.4 266.9 ;
    END
  END stack_maint_o.base[25]
  PIN stack_maint_o.base[26]
    DIRECTION OUTPUT ;
    USE SIGNAL ;
    PORT
      LAYER Metal3 ;
        RECT  0 268.18 0.4 268.58 ;
    END
  END stack_maint_o.base[26]
  PIN stack_maint_o.base[27]
    DIRECTION OUTPUT ;
    USE SIGNAL ;
    PORT
      LAYER Metal3 ;
        RECT  0 269.86 0.4 270.26 ;
    END
  END stack_maint_o.base[27]
  PIN stack_maint_o.base[28]
    DIRECTION OUTPUT ;
    USE SIGNAL ;
    PORT
      LAYER Metal3 ;
        RECT  0 271.54 0.4 271.94 ;
    END
  END stack_maint_o.base[28]
  PIN stack_maint_o.base[29]
    DIRECTION OUTPUT ;
    USE SIGNAL ;
    PORT
      LAYER Metal3 ;
        RECT  0 273.22 0.4 273.62 ;
    END
  END stack_maint_o.base[29]
  PIN stack_maint_o.base[2]
    DIRECTION OUTPUT ;
    USE SIGNAL ;
    PORT
      LAYER Metal3 ;
        RECT  0 227.86 0.4 228.26 ;
    END
  END stack_maint_o.base[2]
  PIN stack_maint_o.base[30]
    DIRECTION OUTPUT ;
    USE SIGNAL ;
    PORT
      LAYER Metal3 ;
        RECT  0 274.9 0.4 275.3 ;
    END
  END stack_maint_o.base[30]
  PIN stack_maint_o.base[31]
    DIRECTION OUTPUT ;
    USE SIGNAL ;
    PORT
      LAYER Metal3 ;
        RECT  0 276.58 0.4 276.98 ;
    END
  END stack_maint_o.base[31]
  PIN stack_maint_o.base[32]
    DIRECTION OUTPUT ;
    USE SIGNAL ;
    PORT
      LAYER Metal3 ;
        RECT  0 278.26 0.4 278.66 ;
    END
  END stack_maint_o.base[32]
  PIN stack_maint_o.base[33]
    DIRECTION OUTPUT ;
    USE SIGNAL ;
    PORT
      LAYER Metal3 ;
        RECT  0 279.94 0.4 280.34 ;
    END
  END stack_maint_o.base[33]
  PIN stack_maint_o.base[34]
    DIRECTION OUTPUT ;
    USE SIGNAL ;
    PORT
      LAYER Metal3 ;
        RECT  0 281.62 0.4 282.02 ;
    END
  END stack_maint_o.base[34]
  PIN stack_maint_o.base[35]
    DIRECTION OUTPUT ;
    USE SIGNAL ;
    PORT
      LAYER Metal3 ;
        RECT  0 283.3 0.4 283.7 ;
    END
  END stack_maint_o.base[35]
  PIN stack_maint_o.base[36]
    DIRECTION OUTPUT ;
    USE SIGNAL ;
    PORT
      LAYER Metal3 ;
        RECT  0 284.98 0.4 285.38 ;
    END
  END stack_maint_o.base[36]
  PIN stack_maint_o.base[37]
    DIRECTION OUTPUT ;
    USE SIGNAL ;
    PORT
      LAYER Metal3 ;
        RECT  0 286.66 0.4 287.06 ;
    END
  END stack_maint_o.base[37]
  PIN stack_maint_o.base[38]
    DIRECTION OUTPUT ;
    USE SIGNAL ;
    PORT
      LAYER Metal3 ;
        RECT  0 288.34 0.4 288.74 ;
    END
  END stack_maint_o.base[38]
  PIN stack_maint_o.base[39]
    DIRECTION OUTPUT ;
    USE SIGNAL ;
    PORT
      LAYER Metal3 ;
        RECT  0 290.02 0.4 290.42 ;
    END
  END stack_maint_o.base[39]
  PIN stack_maint_o.base[3]
    DIRECTION OUTPUT ;
    USE SIGNAL ;
    PORT
      LAYER Metal3 ;
        RECT  0 229.54 0.4 229.94 ;
    END
  END stack_maint_o.base[3]
  PIN stack_maint_o.base[40]
    DIRECTION OUTPUT ;
    USE SIGNAL ;
    PORT
      LAYER Metal3 ;
        RECT  0 291.7 0.4 292.1 ;
    END
  END stack_maint_o.base[40]
  PIN stack_maint_o.base[41]
    DIRECTION OUTPUT ;
    USE SIGNAL ;
    PORT
      LAYER Metal3 ;
        RECT  0 293.38 0.4 293.78 ;
    END
  END stack_maint_o.base[41]
  PIN stack_maint_o.base[42]
    DIRECTION OUTPUT ;
    USE SIGNAL ;
    PORT
      LAYER Metal3 ;
        RECT  0 295.06 0.4 295.46 ;
    END
  END stack_maint_o.base[42]
  PIN stack_maint_o.base[43]
    DIRECTION OUTPUT ;
    USE SIGNAL ;
    PORT
      LAYER Metal3 ;
        RECT  0 296.74 0.4 297.14 ;
    END
  END stack_maint_o.base[43]
  PIN stack_maint_o.base[44]
    DIRECTION OUTPUT ;
    USE SIGNAL ;
    PORT
      LAYER Metal3 ;
        RECT  0 298.42 0.4 298.82 ;
    END
  END stack_maint_o.base[44]
  PIN stack_maint_o.base[45]
    DIRECTION OUTPUT ;
    USE SIGNAL ;
    PORT
      LAYER Metal3 ;
        RECT  0 300.1 0.4 300.5 ;
    END
  END stack_maint_o.base[45]
  PIN stack_maint_o.base[46]
    DIRECTION OUTPUT ;
    USE SIGNAL ;
    PORT
      LAYER Metal3 ;
        RECT  0 301.78 0.4 302.18 ;
    END
  END stack_maint_o.base[46]
  PIN stack_maint_o.base[47]
    DIRECTION OUTPUT ;
    USE SIGNAL ;
    PORT
      LAYER Metal3 ;
        RECT  0 303.46 0.4 303.86 ;
    END
  END stack_maint_o.base[47]
  PIN stack_maint_o.base[48]
    DIRECTION OUTPUT ;
    USE SIGNAL ;
    PORT
      LAYER Metal3 ;
        RECT  0 305.14 0.4 305.54 ;
    END
  END stack_maint_o.base[48]
  PIN stack_maint_o.base[49]
    DIRECTION OUTPUT ;
    USE SIGNAL ;
    PORT
      LAYER Metal3 ;
        RECT  0 306.82 0.4 307.22 ;
    END
  END stack_maint_o.base[49]
  PIN stack_maint_o.base[4]
    DIRECTION OUTPUT ;
    USE SIGNAL ;
    PORT
      LAYER Metal3 ;
        RECT  0 231.22 0.4 231.62 ;
    END
  END stack_maint_o.base[4]
  PIN stack_maint_o.base[50]
    DIRECTION OUTPUT ;
    USE SIGNAL ;
    PORT
      LAYER Metal3 ;
        RECT  0 308.5 0.4 308.9 ;
    END
  END stack_maint_o.base[50]
  PIN stack_maint_o.base[51]
    DIRECTION OUTPUT ;
    USE SIGNAL ;
    PORT
      LAYER Metal3 ;
        RECT  0 310.18 0.4 310.58 ;
    END
  END stack_maint_o.base[51]
  PIN stack_maint_o.base[52]
    DIRECTION OUTPUT ;
    USE SIGNAL ;
    PORT
      LAYER Metal3 ;
        RECT  0 311.86 0.4 312.26 ;
    END
  END stack_maint_o.base[52]
  PIN stack_maint_o.base[53]
    DIRECTION OUTPUT ;
    USE SIGNAL ;
    PORT
      LAYER Metal3 ;
        RECT  0 313.54 0.4 313.94 ;
    END
  END stack_maint_o.base[53]
  PIN stack_maint_o.base[54]
    DIRECTION OUTPUT ;
    USE SIGNAL ;
    PORT
      LAYER Metal3 ;
        RECT  0 315.22 0.4 315.62 ;
    END
  END stack_maint_o.base[54]
  PIN stack_maint_o.base[55]
    DIRECTION OUTPUT ;
    USE SIGNAL ;
    PORT
      LAYER Metal3 ;
        RECT  0 316.9 0.4 317.3 ;
    END
  END stack_maint_o.base[55]
  PIN stack_maint_o.base[56]
    DIRECTION OUTPUT ;
    USE SIGNAL ;
    PORT
      LAYER Metal3 ;
        RECT  0 318.58 0.4 318.98 ;
    END
  END stack_maint_o.base[56]
  PIN stack_maint_o.base[57]
    DIRECTION OUTPUT ;
    USE SIGNAL ;
    PORT
      LAYER Metal3 ;
        RECT  0 320.26 0.4 320.66 ;
    END
  END stack_maint_o.base[57]
  PIN stack_maint_o.base[58]
    DIRECTION OUTPUT ;
    USE SIGNAL ;
    PORT
      LAYER Metal3 ;
        RECT  0 321.94 0.4 322.34 ;
    END
  END stack_maint_o.base[58]
  PIN stack_maint_o.base[59]
    DIRECTION OUTPUT ;
    USE SIGNAL ;
    PORT
      LAYER Metal3 ;
        RECT  0 323.62 0.4 324.02 ;
    END
  END stack_maint_o.base[59]
  PIN stack_maint_o.base[5]
    DIRECTION OUTPUT ;
    USE SIGNAL ;
    PORT
      LAYER Metal3 ;
        RECT  0 232.9 0.4 233.3 ;
    END
  END stack_maint_o.base[5]
  PIN stack_maint_o.base[60]
    DIRECTION OUTPUT ;
    USE SIGNAL ;
    PORT
      LAYER Metal3 ;
        RECT  0 325.3 0.4 325.7 ;
    END
  END stack_maint_o.base[60]
  PIN stack_maint_o.base[61]
    DIRECTION OUTPUT ;
    USE SIGNAL ;
    PORT
      LAYER Metal3 ;
        RECT  0 326.98 0.4 327.38 ;
    END
  END stack_maint_o.base[61]
  PIN stack_maint_o.base[62]
    DIRECTION OUTPUT ;
    USE SIGNAL ;
    PORT
      LAYER Metal3 ;
        RECT  0 328.66 0.4 329.06 ;
    END
  END stack_maint_o.base[62]
  PIN stack_maint_o.base[63]
    DIRECTION OUTPUT ;
    USE SIGNAL ;
    PORT
      LAYER Metal3 ;
        RECT  0 330.34 0.4 330.74 ;
    END
  END stack_maint_o.base[63]
  PIN stack_maint_o.base[6]
    DIRECTION OUTPUT ;
    USE SIGNAL ;
    PORT
      LAYER Metal3 ;
        RECT  0 234.58 0.4 234.98 ;
    END
  END stack_maint_o.base[6]
  PIN stack_maint_o.base[7]
    DIRECTION OUTPUT ;
    USE SIGNAL ;
    PORT
      LAYER Metal3 ;
        RECT  0 236.26 0.4 236.66 ;
    END
  END stack_maint_o.base[7]
  PIN stack_maint_o.base[8]
    DIRECTION OUTPUT ;
    USE SIGNAL ;
    PORT
      LAYER Metal3 ;
        RECT  0 237.94 0.4 238.34 ;
    END
  END stack_maint_o.base[8]
  PIN stack_maint_o.base[9]
    DIRECTION OUTPUT ;
    USE SIGNAL ;
    PORT
      LAYER Metal3 ;
        RECT  0 239.62 0.4 240.02 ;
    END
  END stack_maint_o.base[9]
  PIN stack_maint_o.kind[0]
    DIRECTION OUTPUT ;
    USE SIGNAL ;
    PORT
      LAYER Metal3 ;
        RECT  0 223.66 0.4 224.06 ;
    END
  END stack_maint_o.kind[0]
  PIN stack_maint_o.kind[1]
    DIRECTION OUTPUT ;
    USE SIGNAL ;
    PORT
      LAYER Metal3 ;
        RECT  0 226.18 0.4 226.58 ;
    END
  END stack_maint_o.kind[1]
  PIN stack_maint_o.length[0]
    DIRECTION OUTPUT ;
    USE SIGNAL ;
    PORT
      LAYER Metal3 ;
        RECT  0 224.5 0.4 224.9 ;
    END
  END stack_maint_o.length[0]
  PIN stack_maint_o.length[10]
    DIRECTION OUTPUT ;
    USE SIGNAL ;
    PORT
      LAYER Metal3 ;
        RECT  0 242.14 0.4 242.54 ;
    END
  END stack_maint_o.length[10]
  PIN stack_maint_o.length[11]
    DIRECTION OUTPUT ;
    USE SIGNAL ;
    PORT
      LAYER Metal3 ;
        RECT  0 243.82 0.4 244.22 ;
    END
  END stack_maint_o.length[11]
  PIN stack_maint_o.length[12]
    DIRECTION OUTPUT ;
    USE SIGNAL ;
    PORT
      LAYER Metal3 ;
        RECT  0 245.5 0.4 245.9 ;
    END
  END stack_maint_o.length[12]
  PIN stack_maint_o.length[13]
    DIRECTION OUTPUT ;
    USE SIGNAL ;
    PORT
      LAYER Metal3 ;
        RECT  0 247.18 0.4 247.58 ;
    END
  END stack_maint_o.length[13]
  PIN stack_maint_o.length[14]
    DIRECTION OUTPUT ;
    USE SIGNAL ;
    PORT
      LAYER Metal3 ;
        RECT  0 248.86 0.4 249.26 ;
    END
  END stack_maint_o.length[14]
  PIN stack_maint_o.length[15]
    DIRECTION OUTPUT ;
    USE SIGNAL ;
    PORT
      LAYER Metal3 ;
        RECT  0 250.54 0.4 250.94 ;
    END
  END stack_maint_o.length[15]
  PIN stack_maint_o.length[16]
    DIRECTION OUTPUT ;
    USE SIGNAL ;
    PORT
      LAYER Metal3 ;
        RECT  0 252.22 0.4 252.62 ;
    END
  END stack_maint_o.length[16]
  PIN stack_maint_o.length[17]
    DIRECTION OUTPUT ;
    USE SIGNAL ;
    PORT
      LAYER Metal3 ;
        RECT  0 253.9 0.4 254.3 ;
    END
  END stack_maint_o.length[17]
  PIN stack_maint_o.length[18]
    DIRECTION OUTPUT ;
    USE SIGNAL ;
    PORT
      LAYER Metal3 ;
        RECT  0 255.58 0.4 255.98 ;
    END
  END stack_maint_o.length[18]
  PIN stack_maint_o.length[19]
    DIRECTION OUTPUT ;
    USE SIGNAL ;
    PORT
      LAYER Metal3 ;
        RECT  0 257.26 0.4 257.66 ;
    END
  END stack_maint_o.length[19]
  PIN stack_maint_o.length[1]
    DIRECTION OUTPUT ;
    USE SIGNAL ;
    PORT
      LAYER Metal3 ;
        RECT  0 227.02 0.4 227.42 ;
    END
  END stack_maint_o.length[1]
  PIN stack_maint_o.length[20]
    DIRECTION OUTPUT ;
    USE SIGNAL ;
    PORT
      LAYER Metal3 ;
        RECT  0 258.94 0.4 259.34 ;
    END
  END stack_maint_o.length[20]
  PIN stack_maint_o.length[21]
    DIRECTION OUTPUT ;
    USE SIGNAL ;
    PORT
      LAYER Metal3 ;
        RECT  0 260.62 0.4 261.02 ;
    END
  END stack_maint_o.length[21]
  PIN stack_maint_o.length[22]
    DIRECTION OUTPUT ;
    USE SIGNAL ;
    PORT
      LAYER Metal3 ;
        RECT  0 262.3 0.4 262.7 ;
    END
  END stack_maint_o.length[22]
  PIN stack_maint_o.length[23]
    DIRECTION OUTPUT ;
    USE SIGNAL ;
    PORT
      LAYER Metal3 ;
        RECT  0 263.98 0.4 264.38 ;
    END
  END stack_maint_o.length[23]
  PIN stack_maint_o.length[24]
    DIRECTION OUTPUT ;
    USE SIGNAL ;
    PORT
      LAYER Metal3 ;
        RECT  0 265.66 0.4 266.06 ;
    END
  END stack_maint_o.length[24]
  PIN stack_maint_o.length[25]
    DIRECTION OUTPUT ;
    USE SIGNAL ;
    PORT
      LAYER Metal3 ;
        RECT  0 267.34 0.4 267.74 ;
    END
  END stack_maint_o.length[25]
  PIN stack_maint_o.length[26]
    DIRECTION OUTPUT ;
    USE SIGNAL ;
    PORT
      LAYER Metal3 ;
        RECT  0 269.02 0.4 269.42 ;
    END
  END stack_maint_o.length[26]
  PIN stack_maint_o.length[27]
    DIRECTION OUTPUT ;
    USE SIGNAL ;
    PORT
      LAYER Metal3 ;
        RECT  0 270.7 0.4 271.1 ;
    END
  END stack_maint_o.length[27]
  PIN stack_maint_o.length[28]
    DIRECTION OUTPUT ;
    USE SIGNAL ;
    PORT
      LAYER Metal3 ;
        RECT  0 272.38 0.4 272.78 ;
    END
  END stack_maint_o.length[28]
  PIN stack_maint_o.length[29]
    DIRECTION OUTPUT ;
    USE SIGNAL ;
    PORT
      LAYER Metal3 ;
        RECT  0 274.06 0.4 274.46 ;
    END
  END stack_maint_o.length[29]
  PIN stack_maint_o.length[2]
    DIRECTION OUTPUT ;
    USE SIGNAL ;
    PORT
      LAYER Metal3 ;
        RECT  0 228.7 0.4 229.1 ;
    END
  END stack_maint_o.length[2]
  PIN stack_maint_o.length[30]
    DIRECTION OUTPUT ;
    USE SIGNAL ;
    PORT
      LAYER Metal3 ;
        RECT  0 275.74 0.4 276.14 ;
    END
  END stack_maint_o.length[30]
  PIN stack_maint_o.length[31]
    DIRECTION OUTPUT ;
    USE SIGNAL ;
    PORT
      LAYER Metal3 ;
        RECT  0 277.42 0.4 277.82 ;
    END
  END stack_maint_o.length[31]
  PIN stack_maint_o.length[32]
    DIRECTION OUTPUT ;
    USE SIGNAL ;
    PORT
      LAYER Metal3 ;
        RECT  0 279.1 0.4 279.5 ;
    END
  END stack_maint_o.length[32]
  PIN stack_maint_o.length[33]
    DIRECTION OUTPUT ;
    USE SIGNAL ;
    PORT
      LAYER Metal3 ;
        RECT  0 280.78 0.4 281.18 ;
    END
  END stack_maint_o.length[33]
  PIN stack_maint_o.length[34]
    DIRECTION OUTPUT ;
    USE SIGNAL ;
    PORT
      LAYER Metal3 ;
        RECT  0 282.46 0.4 282.86 ;
    END
  END stack_maint_o.length[34]
  PIN stack_maint_o.length[35]
    DIRECTION OUTPUT ;
    USE SIGNAL ;
    PORT
      LAYER Metal3 ;
        RECT  0 284.14 0.4 284.54 ;
    END
  END stack_maint_o.length[35]
  PIN stack_maint_o.length[36]
    DIRECTION OUTPUT ;
    USE SIGNAL ;
    PORT
      LAYER Metal3 ;
        RECT  0 285.82 0.4 286.22 ;
    END
  END stack_maint_o.length[36]
  PIN stack_maint_o.length[37]
    DIRECTION OUTPUT ;
    USE SIGNAL ;
    PORT
      LAYER Metal3 ;
        RECT  0 287.5 0.4 287.9 ;
    END
  END stack_maint_o.length[37]
  PIN stack_maint_o.length[38]
    DIRECTION OUTPUT ;
    USE SIGNAL ;
    PORT
      LAYER Metal3 ;
        RECT  0 289.18 0.4 289.58 ;
    END
  END stack_maint_o.length[38]
  PIN stack_maint_o.length[39]
    DIRECTION OUTPUT ;
    USE SIGNAL ;
    PORT
      LAYER Metal3 ;
        RECT  0 290.86 0.4 291.26 ;
    END
  END stack_maint_o.length[39]
  PIN stack_maint_o.length[3]
    DIRECTION OUTPUT ;
    USE SIGNAL ;
    PORT
      LAYER Metal3 ;
        RECT  0 230.38 0.4 230.78 ;
    END
  END stack_maint_o.length[3]
  PIN stack_maint_o.length[40]
    DIRECTION OUTPUT ;
    USE SIGNAL ;
    PORT
      LAYER Metal3 ;
        RECT  0 292.54 0.4 292.94 ;
    END
  END stack_maint_o.length[40]
  PIN stack_maint_o.length[41]
    DIRECTION OUTPUT ;
    USE SIGNAL ;
    PORT
      LAYER Metal3 ;
        RECT  0 294.22 0.4 294.62 ;
    END
  END stack_maint_o.length[41]
  PIN stack_maint_o.length[42]
    DIRECTION OUTPUT ;
    USE SIGNAL ;
    PORT
      LAYER Metal3 ;
        RECT  0 295.9 0.4 296.3 ;
    END
  END stack_maint_o.length[42]
  PIN stack_maint_o.length[43]
    DIRECTION OUTPUT ;
    USE SIGNAL ;
    PORT
      LAYER Metal3 ;
        RECT  0 297.58 0.4 297.98 ;
    END
  END stack_maint_o.length[43]
  PIN stack_maint_o.length[44]
    DIRECTION OUTPUT ;
    USE SIGNAL ;
    PORT
      LAYER Metal3 ;
        RECT  0 299.26 0.4 299.66 ;
    END
  END stack_maint_o.length[44]
  PIN stack_maint_o.length[45]
    DIRECTION OUTPUT ;
    USE SIGNAL ;
    PORT
      LAYER Metal3 ;
        RECT  0 300.94 0.4 301.34 ;
    END
  END stack_maint_o.length[45]
  PIN stack_maint_o.length[46]
    DIRECTION OUTPUT ;
    USE SIGNAL ;
    PORT
      LAYER Metal3 ;
        RECT  0 302.62 0.4 303.02 ;
    END
  END stack_maint_o.length[46]
  PIN stack_maint_o.length[47]
    DIRECTION OUTPUT ;
    USE SIGNAL ;
    PORT
      LAYER Metal3 ;
        RECT  0 304.3 0.4 304.7 ;
    END
  END stack_maint_o.length[47]
  PIN stack_maint_o.length[48]
    DIRECTION OUTPUT ;
    USE SIGNAL ;
    PORT
      LAYER Metal3 ;
        RECT  0 305.98 0.4 306.38 ;
    END
  END stack_maint_o.length[48]
  PIN stack_maint_o.length[49]
    DIRECTION OUTPUT ;
    USE SIGNAL ;
    PORT
      LAYER Metal3 ;
        RECT  0 307.66 0.4 308.06 ;
    END
  END stack_maint_o.length[49]
  PIN stack_maint_o.length[4]
    DIRECTION OUTPUT ;
    USE SIGNAL ;
    PORT
      LAYER Metal3 ;
        RECT  0 232.06 0.4 232.46 ;
    END
  END stack_maint_o.length[4]
  PIN stack_maint_o.length[50]
    DIRECTION OUTPUT ;
    USE SIGNAL ;
    PORT
      LAYER Metal3 ;
        RECT  0 309.34 0.4 309.74 ;
    END
  END stack_maint_o.length[50]
  PIN stack_maint_o.length[51]
    DIRECTION OUTPUT ;
    USE SIGNAL ;
    PORT
      LAYER Metal3 ;
        RECT  0 311.02 0.4 311.42 ;
    END
  END stack_maint_o.length[51]
  PIN stack_maint_o.length[52]
    DIRECTION OUTPUT ;
    USE SIGNAL ;
    PORT
      LAYER Metal3 ;
        RECT  0 312.7 0.4 313.1 ;
    END
  END stack_maint_o.length[52]
  PIN stack_maint_o.length[53]
    DIRECTION OUTPUT ;
    USE SIGNAL ;
    PORT
      LAYER Metal3 ;
        RECT  0 314.38 0.4 314.78 ;
    END
  END stack_maint_o.length[53]
  PIN stack_maint_o.length[54]
    DIRECTION OUTPUT ;
    USE SIGNAL ;
    PORT
      LAYER Metal3 ;
        RECT  0 316.06 0.4 316.46 ;
    END
  END stack_maint_o.length[54]
  PIN stack_maint_o.length[55]
    DIRECTION OUTPUT ;
    USE SIGNAL ;
    PORT
      LAYER Metal3 ;
        RECT  0 317.74 0.4 318.14 ;
    END
  END stack_maint_o.length[55]
  PIN stack_maint_o.length[56]
    DIRECTION OUTPUT ;
    USE SIGNAL ;
    PORT
      LAYER Metal3 ;
        RECT  0 319.42 0.4 319.82 ;
    END
  END stack_maint_o.length[56]
  PIN stack_maint_o.length[57]
    DIRECTION OUTPUT ;
    USE SIGNAL ;
    PORT
      LAYER Metal3 ;
        RECT  0 321.1 0.4 321.5 ;
    END
  END stack_maint_o.length[57]
  PIN stack_maint_o.length[58]
    DIRECTION OUTPUT ;
    USE SIGNAL ;
    PORT
      LAYER Metal3 ;
        RECT  0 322.78 0.4 323.18 ;
    END
  END stack_maint_o.length[58]
  PIN stack_maint_o.length[59]
    DIRECTION OUTPUT ;
    USE SIGNAL ;
    PORT
      LAYER Metal3 ;
        RECT  0 324.46 0.4 324.86 ;
    END
  END stack_maint_o.length[59]
  PIN stack_maint_o.length[5]
    DIRECTION OUTPUT ;
    USE SIGNAL ;
    PORT
      LAYER Metal3 ;
        RECT  0 233.74 0.4 234.14 ;
    END
  END stack_maint_o.length[5]
  PIN stack_maint_o.length[60]
    DIRECTION OUTPUT ;
    USE SIGNAL ;
    PORT
      LAYER Metal3 ;
        RECT  0 326.14 0.4 326.54 ;
    END
  END stack_maint_o.length[60]
  PIN stack_maint_o.length[61]
    DIRECTION OUTPUT ;
    USE SIGNAL ;
    PORT
      LAYER Metal3 ;
        RECT  0 327.82 0.4 328.22 ;
    END
  END stack_maint_o.length[61]
  PIN stack_maint_o.length[62]
    DIRECTION OUTPUT ;
    USE SIGNAL ;
    PORT
      LAYER Metal3 ;
        RECT  0 329.5 0.4 329.9 ;
    END
  END stack_maint_o.length[62]
  PIN stack_maint_o.length[63]
    DIRECTION OUTPUT ;
    USE SIGNAL ;
    PORT
      LAYER Metal3 ;
        RECT  0 331.18 0.4 331.58 ;
    END
  END stack_maint_o.length[63]
  PIN stack_maint_o.length[6]
    DIRECTION OUTPUT ;
    USE SIGNAL ;
    PORT
      LAYER Metal3 ;
        RECT  0 235.42 0.4 235.82 ;
    END
  END stack_maint_o.length[6]
  PIN stack_maint_o.length[7]
    DIRECTION OUTPUT ;
    USE SIGNAL ;
    PORT
      LAYER Metal3 ;
        RECT  0 237.1 0.4 237.5 ;
    END
  END stack_maint_o.length[7]
  PIN stack_maint_o.length[8]
    DIRECTION OUTPUT ;
    USE SIGNAL ;
    PORT
      LAYER Metal3 ;
        RECT  0 238.78 0.4 239.18 ;
    END
  END stack_maint_o.length[8]
  PIN stack_maint_o.length[9]
    DIRECTION OUTPUT ;
    USE SIGNAL ;
    PORT
      LAYER Metal3 ;
        RECT  0 240.46 0.4 240.86 ;
    END
  END stack_maint_o.length[9]
  PIN stack_maint_o.valid
    DIRECTION OUTPUT ;
    USE SIGNAL ;
    PORT
      LAYER Metal3 ;
        RECT  0 221.98 0.4 222.38 ;
    END
  END stack_maint_o.valid
  PIN sync_copile_o.cfp[0]
    DIRECTION OUTPUT ;
    USE SIGNAL ;
    PORT
      LAYER Metal3 ;
        RECT  0 934.3 0.4 934.7 ;
    END
  END sync_copile_o.cfp[0]
  PIN sync_copile_o.cfp[10]
    DIRECTION OUTPUT ;
    USE SIGNAL ;
    PORT
      LAYER Metal3 ;
        RECT  0 959.5 0.4 959.9 ;
    END
  END sync_copile_o.cfp[10]
  PIN sync_copile_o.cfp[11]
    DIRECTION OUTPUT ;
    USE SIGNAL ;
    PORT
      LAYER Metal3 ;
        RECT  0 962.02 0.4 962.42 ;
    END
  END sync_copile_o.cfp[11]
  PIN sync_copile_o.cfp[12]
    DIRECTION OUTPUT ;
    USE SIGNAL ;
    PORT
      LAYER Metal3 ;
        RECT  0 964.54 0.4 964.94 ;
    END
  END sync_copile_o.cfp[12]
  PIN sync_copile_o.cfp[13]
    DIRECTION OUTPUT ;
    USE SIGNAL ;
    PORT
      LAYER Metal3 ;
        RECT  0 967.06 0.4 967.46 ;
    END
  END sync_copile_o.cfp[13]
  PIN sync_copile_o.cfp[14]
    DIRECTION OUTPUT ;
    USE SIGNAL ;
    PORT
      LAYER Metal3 ;
        RECT  0 969.58 0.4 969.98 ;
    END
  END sync_copile_o.cfp[14]
  PIN sync_copile_o.cfp[15]
    DIRECTION OUTPUT ;
    USE SIGNAL ;
    PORT
      LAYER Metal3 ;
        RECT  0 972.1 0.4 972.5 ;
    END
  END sync_copile_o.cfp[15]
  PIN sync_copile_o.cfp[16]
    DIRECTION OUTPUT ;
    USE SIGNAL ;
    PORT
      LAYER Metal3 ;
        RECT  0 974.62 0.4 975.02 ;
    END
  END sync_copile_o.cfp[16]
  PIN sync_copile_o.cfp[17]
    DIRECTION OUTPUT ;
    USE SIGNAL ;
    PORT
      LAYER Metal3 ;
        RECT  0 977.14 0.4 977.54 ;
    END
  END sync_copile_o.cfp[17]
  PIN sync_copile_o.cfp[18]
    DIRECTION OUTPUT ;
    USE SIGNAL ;
    PORT
      LAYER Metal3 ;
        RECT  0 979.66 0.4 980.06 ;
    END
  END sync_copile_o.cfp[18]
  PIN sync_copile_o.cfp[19]
    DIRECTION OUTPUT ;
    USE SIGNAL ;
    PORT
      LAYER Metal3 ;
        RECT  0 982.18 0.4 982.58 ;
    END
  END sync_copile_o.cfp[19]
  PIN sync_copile_o.cfp[1]
    DIRECTION OUTPUT ;
    USE SIGNAL ;
    PORT
      LAYER Metal3 ;
        RECT  0 936.82 0.4 937.22 ;
    END
  END sync_copile_o.cfp[1]
  PIN sync_copile_o.cfp[20]
    DIRECTION OUTPUT ;
    USE SIGNAL ;
    PORT
      LAYER Metal3 ;
        RECT  0 984.7 0.4 985.1 ;
    END
  END sync_copile_o.cfp[20]
  PIN sync_copile_o.cfp[21]
    DIRECTION OUTPUT ;
    USE SIGNAL ;
    PORT
      LAYER Metal3 ;
        RECT  0 987.22 0.4 987.62 ;
    END
  END sync_copile_o.cfp[21]
  PIN sync_copile_o.cfp[22]
    DIRECTION OUTPUT ;
    USE SIGNAL ;
    PORT
      LAYER Metal3 ;
        RECT  0 989.74 0.4 990.14 ;
    END
  END sync_copile_o.cfp[22]
  PIN sync_copile_o.cfp[23]
    DIRECTION OUTPUT ;
    USE SIGNAL ;
    PORT
      LAYER Metal3 ;
        RECT  0 992.26 0.4 992.66 ;
    END
  END sync_copile_o.cfp[23]
  PIN sync_copile_o.cfp[24]
    DIRECTION OUTPUT ;
    USE SIGNAL ;
    PORT
      LAYER Metal3 ;
        RECT  0 994.78 0.4 995.18 ;
    END
  END sync_copile_o.cfp[24]
  PIN sync_copile_o.cfp[25]
    DIRECTION OUTPUT ;
    USE SIGNAL ;
    PORT
      LAYER Metal3 ;
        RECT  0 997.3 0.4 997.7 ;
    END
  END sync_copile_o.cfp[25]
  PIN sync_copile_o.cfp[26]
    DIRECTION OUTPUT ;
    USE SIGNAL ;
    PORT
      LAYER Metal3 ;
        RECT  0 999.82 0.4 1000.22 ;
    END
  END sync_copile_o.cfp[26]
  PIN sync_copile_o.cfp[27]
    DIRECTION OUTPUT ;
    USE SIGNAL ;
    PORT
      LAYER Metal3 ;
        RECT  0 1002.34 0.4 1002.74 ;
    END
  END sync_copile_o.cfp[27]
  PIN sync_copile_o.cfp[28]
    DIRECTION OUTPUT ;
    USE SIGNAL ;
    PORT
      LAYER Metal3 ;
        RECT  0 1004.86 0.4 1005.26 ;
    END
  END sync_copile_o.cfp[28]
  PIN sync_copile_o.cfp[29]
    DIRECTION OUTPUT ;
    USE SIGNAL ;
    PORT
      LAYER Metal3 ;
        RECT  0 1007.38 0.4 1007.78 ;
    END
  END sync_copile_o.cfp[29]
  PIN sync_copile_o.cfp[2]
    DIRECTION OUTPUT ;
    USE SIGNAL ;
    PORT
      LAYER Metal3 ;
        RECT  0 939.34 0.4 939.74 ;
    END
  END sync_copile_o.cfp[2]
  PIN sync_copile_o.cfp[30]
    DIRECTION OUTPUT ;
    USE SIGNAL ;
    PORT
      LAYER Metal3 ;
        RECT  0 1009.9 0.4 1010.3 ;
    END
  END sync_copile_o.cfp[30]
  PIN sync_copile_o.cfp[31]
    DIRECTION OUTPUT ;
    USE SIGNAL ;
    PORT
      LAYER Metal3 ;
        RECT  0 1012.42 0.4 1012.82 ;
    END
  END sync_copile_o.cfp[31]
  PIN sync_copile_o.cfp[32]
    DIRECTION OUTPUT ;
    USE SIGNAL ;
    PORT
      LAYER Metal3 ;
        RECT  0 1014.94 0.4 1015.34 ;
    END
  END sync_copile_o.cfp[32]
  PIN sync_copile_o.cfp[33]
    DIRECTION OUTPUT ;
    USE SIGNAL ;
    PORT
      LAYER Metal3 ;
        RECT  0 1017.46 0.4 1017.86 ;
    END
  END sync_copile_o.cfp[33]
  PIN sync_copile_o.cfp[34]
    DIRECTION OUTPUT ;
    USE SIGNAL ;
    PORT
      LAYER Metal3 ;
        RECT  0 1019.98 0.4 1020.38 ;
    END
  END sync_copile_o.cfp[34]
  PIN sync_copile_o.cfp[35]
    DIRECTION OUTPUT ;
    USE SIGNAL ;
    PORT
      LAYER Metal3 ;
        RECT  0 1022.5 0.4 1022.9 ;
    END
  END sync_copile_o.cfp[35]
  PIN sync_copile_o.cfp[36]
    DIRECTION OUTPUT ;
    USE SIGNAL ;
    PORT
      LAYER Metal3 ;
        RECT  0 1025.02 0.4 1025.42 ;
    END
  END sync_copile_o.cfp[36]
  PIN sync_copile_o.cfp[37]
    DIRECTION OUTPUT ;
    USE SIGNAL ;
    PORT
      LAYER Metal3 ;
        RECT  0 1027.54 0.4 1027.94 ;
    END
  END sync_copile_o.cfp[37]
  PIN sync_copile_o.cfp[38]
    DIRECTION OUTPUT ;
    USE SIGNAL ;
    PORT
      LAYER Metal3 ;
        RECT  0 1030.06 0.4 1030.46 ;
    END
  END sync_copile_o.cfp[38]
  PIN sync_copile_o.cfp[39]
    DIRECTION OUTPUT ;
    USE SIGNAL ;
    PORT
      LAYER Metal3 ;
        RECT  0 1032.58 0.4 1032.98 ;
    END
  END sync_copile_o.cfp[39]
  PIN sync_copile_o.cfp[3]
    DIRECTION OUTPUT ;
    USE SIGNAL ;
    PORT
      LAYER Metal3 ;
        RECT  0 941.86 0.4 942.26 ;
    END
  END sync_copile_o.cfp[3]
  PIN sync_copile_o.cfp[40]
    DIRECTION OUTPUT ;
    USE SIGNAL ;
    PORT
      LAYER Metal3 ;
        RECT  0 1035.1 0.4 1035.5 ;
    END
  END sync_copile_o.cfp[40]
  PIN sync_copile_o.cfp[41]
    DIRECTION OUTPUT ;
    USE SIGNAL ;
    PORT
      LAYER Metal3 ;
        RECT  0 1037.62 0.4 1038.02 ;
    END
  END sync_copile_o.cfp[41]
  PIN sync_copile_o.cfp[42]
    DIRECTION OUTPUT ;
    USE SIGNAL ;
    PORT
      LAYER Metal3 ;
        RECT  0 1040.14 0.4 1040.54 ;
    END
  END sync_copile_o.cfp[42]
  PIN sync_copile_o.cfp[43]
    DIRECTION OUTPUT ;
    USE SIGNAL ;
    PORT
      LAYER Metal3 ;
        RECT  0 1042.66 0.4 1043.06 ;
    END
  END sync_copile_o.cfp[43]
  PIN sync_copile_o.cfp[44]
    DIRECTION OUTPUT ;
    USE SIGNAL ;
    PORT
      LAYER Metal3 ;
        RECT  0 1045.18 0.4 1045.58 ;
    END
  END sync_copile_o.cfp[44]
  PIN sync_copile_o.cfp[45]
    DIRECTION OUTPUT ;
    USE SIGNAL ;
    PORT
      LAYER Metal3 ;
        RECT  0 1047.7 0.4 1048.1 ;
    END
  END sync_copile_o.cfp[45]
  PIN sync_copile_o.cfp[46]
    DIRECTION OUTPUT ;
    USE SIGNAL ;
    PORT
      LAYER Metal3 ;
        RECT  0 1050.22 0.4 1050.62 ;
    END
  END sync_copile_o.cfp[46]
  PIN sync_copile_o.cfp[47]
    DIRECTION OUTPUT ;
    USE SIGNAL ;
    PORT
      LAYER Metal3 ;
        RECT  0 1052.74 0.4 1053.14 ;
    END
  END sync_copile_o.cfp[47]
  PIN sync_copile_o.cfp[48]
    DIRECTION OUTPUT ;
    USE SIGNAL ;
    PORT
      LAYER Metal3 ;
        RECT  0 1055.26 0.4 1055.66 ;
    END
  END sync_copile_o.cfp[48]
  PIN sync_copile_o.cfp[49]
    DIRECTION OUTPUT ;
    USE SIGNAL ;
    PORT
      LAYER Metal3 ;
        RECT  0 1057.78 0.4 1058.18 ;
    END
  END sync_copile_o.cfp[49]
  PIN sync_copile_o.cfp[4]
    DIRECTION OUTPUT ;
    USE SIGNAL ;
    PORT
      LAYER Metal3 ;
        RECT  0 944.38 0.4 944.78 ;
    END
  END sync_copile_o.cfp[4]
  PIN sync_copile_o.cfp[50]
    DIRECTION OUTPUT ;
    USE SIGNAL ;
    PORT
      LAYER Metal3 ;
        RECT  0 1060.3 0.4 1060.7 ;
    END
  END sync_copile_o.cfp[50]
  PIN sync_copile_o.cfp[51]
    DIRECTION OUTPUT ;
    USE SIGNAL ;
    PORT
      LAYER Metal3 ;
        RECT  0 1062.82 0.4 1063.22 ;
    END
  END sync_copile_o.cfp[51]
  PIN sync_copile_o.cfp[52]
    DIRECTION OUTPUT ;
    USE SIGNAL ;
    PORT
      LAYER Metal3 ;
        RECT  0 1065.34 0.4 1065.74 ;
    END
  END sync_copile_o.cfp[52]
  PIN sync_copile_o.cfp[53]
    DIRECTION OUTPUT ;
    USE SIGNAL ;
    PORT
      LAYER Metal3 ;
        RECT  0 1067.86 0.4 1068.26 ;
    END
  END sync_copile_o.cfp[53]
  PIN sync_copile_o.cfp[54]
    DIRECTION OUTPUT ;
    USE SIGNAL ;
    PORT
      LAYER Metal3 ;
        RECT  0 1070.38 0.4 1070.78 ;
    END
  END sync_copile_o.cfp[54]
  PIN sync_copile_o.cfp[55]
    DIRECTION OUTPUT ;
    USE SIGNAL ;
    PORT
      LAYER Metal3 ;
        RECT  0 1072.9 0.4 1073.3 ;
    END
  END sync_copile_o.cfp[55]
  PIN sync_copile_o.cfp[56]
    DIRECTION OUTPUT ;
    USE SIGNAL ;
    PORT
      LAYER Metal3 ;
        RECT  0 1075.42 0.4 1075.82 ;
    END
  END sync_copile_o.cfp[56]
  PIN sync_copile_o.cfp[57]
    DIRECTION OUTPUT ;
    USE SIGNAL ;
    PORT
      LAYER Metal3 ;
        RECT  0 1077.94 0.4 1078.34 ;
    END
  END sync_copile_o.cfp[57]
  PIN sync_copile_o.cfp[58]
    DIRECTION OUTPUT ;
    USE SIGNAL ;
    PORT
      LAYER Metal3 ;
        RECT  0 1080.46 0.4 1080.86 ;
    END
  END sync_copile_o.cfp[58]
  PIN sync_copile_o.cfp[59]
    DIRECTION OUTPUT ;
    USE SIGNAL ;
    PORT
      LAYER Metal3 ;
        RECT  0 1082.98 0.4 1083.38 ;
    END
  END sync_copile_o.cfp[59]
  PIN sync_copile_o.cfp[5]
    DIRECTION OUTPUT ;
    USE SIGNAL ;
    PORT
      LAYER Metal3 ;
        RECT  0 946.9 0.4 947.3 ;
    END
  END sync_copile_o.cfp[5]
  PIN sync_copile_o.cfp[60]
    DIRECTION OUTPUT ;
    USE SIGNAL ;
    PORT
      LAYER Metal3 ;
        RECT  0 1085.5 0.4 1085.9 ;
    END
  END sync_copile_o.cfp[60]
  PIN sync_copile_o.cfp[61]
    DIRECTION OUTPUT ;
    USE SIGNAL ;
    PORT
      LAYER Metal3 ;
        RECT  0 1088.02 0.4 1088.42 ;
    END
  END sync_copile_o.cfp[61]
  PIN sync_copile_o.cfp[62]
    DIRECTION OUTPUT ;
    USE SIGNAL ;
    PORT
      LAYER Metal3 ;
        RECT  0 1090.54 0.4 1090.94 ;
    END
  END sync_copile_o.cfp[62]
  PIN sync_copile_o.cfp[63]
    DIRECTION OUTPUT ;
    USE SIGNAL ;
    PORT
      LAYER Metal3 ;
        RECT  0 1093.06 0.4 1093.46 ;
    END
  END sync_copile_o.cfp[63]
  PIN sync_copile_o.cfp[6]
    DIRECTION OUTPUT ;
    USE SIGNAL ;
    PORT
      LAYER Metal3 ;
        RECT  0 949.42 0.4 949.82 ;
    END
  END sync_copile_o.cfp[6]
  PIN sync_copile_o.cfp[7]
    DIRECTION OUTPUT ;
    USE SIGNAL ;
    PORT
      LAYER Metal3 ;
        RECT  0 951.94 0.4 952.34 ;
    END
  END sync_copile_o.cfp[7]
  PIN sync_copile_o.cfp[8]
    DIRECTION OUTPUT ;
    USE SIGNAL ;
    PORT
      LAYER Metal3 ;
        RECT  0 954.46 0.4 954.86 ;
    END
  END sync_copile_o.cfp[8]
  PIN sync_copile_o.cfp[9]
    DIRECTION OUTPUT ;
    USE SIGNAL ;
    PORT
      LAYER Metal3 ;
        RECT  0 956.98 0.4 957.38 ;
    END
  END sync_copile_o.cfp[9]
  PIN sync_copile_o.csp[0]
    DIRECTION OUTPUT ;
    USE SIGNAL ;
    PORT
      LAYER Metal3 ;
        RECT  0 935.14 0.4 935.54 ;
    END
  END sync_copile_o.csp[0]
  PIN sync_copile_o.csp[10]
    DIRECTION OUTPUT ;
    USE SIGNAL ;
    PORT
      LAYER Metal3 ;
        RECT  0 960.34 0.4 960.74 ;
    END
  END sync_copile_o.csp[10]
  PIN sync_copile_o.csp[11]
    DIRECTION OUTPUT ;
    USE SIGNAL ;
    PORT
      LAYER Metal3 ;
        RECT  0 962.86 0.4 963.26 ;
    END
  END sync_copile_o.csp[11]
  PIN sync_copile_o.csp[12]
    DIRECTION OUTPUT ;
    USE SIGNAL ;
    PORT
      LAYER Metal3 ;
        RECT  0 965.38 0.4 965.78 ;
    END
  END sync_copile_o.csp[12]
  PIN sync_copile_o.csp[13]
    DIRECTION OUTPUT ;
    USE SIGNAL ;
    PORT
      LAYER Metal3 ;
        RECT  0 967.9 0.4 968.3 ;
    END
  END sync_copile_o.csp[13]
  PIN sync_copile_o.csp[14]
    DIRECTION OUTPUT ;
    USE SIGNAL ;
    PORT
      LAYER Metal3 ;
        RECT  0 970.42 0.4 970.82 ;
    END
  END sync_copile_o.csp[14]
  PIN sync_copile_o.csp[15]
    DIRECTION OUTPUT ;
    USE SIGNAL ;
    PORT
      LAYER Metal3 ;
        RECT  0 972.94 0.4 973.34 ;
    END
  END sync_copile_o.csp[15]
  PIN sync_copile_o.csp[16]
    DIRECTION OUTPUT ;
    USE SIGNAL ;
    PORT
      LAYER Metal3 ;
        RECT  0 975.46 0.4 975.86 ;
    END
  END sync_copile_o.csp[16]
  PIN sync_copile_o.csp[17]
    DIRECTION OUTPUT ;
    USE SIGNAL ;
    PORT
      LAYER Metal3 ;
        RECT  0 977.98 0.4 978.38 ;
    END
  END sync_copile_o.csp[17]
  PIN sync_copile_o.csp[18]
    DIRECTION OUTPUT ;
    USE SIGNAL ;
    PORT
      LAYER Metal3 ;
        RECT  0 980.5 0.4 980.9 ;
    END
  END sync_copile_o.csp[18]
  PIN sync_copile_o.csp[19]
    DIRECTION OUTPUT ;
    USE SIGNAL ;
    PORT
      LAYER Metal3 ;
        RECT  0 983.02 0.4 983.42 ;
    END
  END sync_copile_o.csp[19]
  PIN sync_copile_o.csp[1]
    DIRECTION OUTPUT ;
    USE SIGNAL ;
    PORT
      LAYER Metal3 ;
        RECT  0 937.66 0.4 938.06 ;
    END
  END sync_copile_o.csp[1]
  PIN sync_copile_o.csp[20]
    DIRECTION OUTPUT ;
    USE SIGNAL ;
    PORT
      LAYER Metal3 ;
        RECT  0 985.54 0.4 985.94 ;
    END
  END sync_copile_o.csp[20]
  PIN sync_copile_o.csp[21]
    DIRECTION OUTPUT ;
    USE SIGNAL ;
    PORT
      LAYER Metal3 ;
        RECT  0 988.06 0.4 988.46 ;
    END
  END sync_copile_o.csp[21]
  PIN sync_copile_o.csp[22]
    DIRECTION OUTPUT ;
    USE SIGNAL ;
    PORT
      LAYER Metal3 ;
        RECT  0 990.58 0.4 990.98 ;
    END
  END sync_copile_o.csp[22]
  PIN sync_copile_o.csp[23]
    DIRECTION OUTPUT ;
    USE SIGNAL ;
    PORT
      LAYER Metal3 ;
        RECT  0 993.1 0.4 993.5 ;
    END
  END sync_copile_o.csp[23]
  PIN sync_copile_o.csp[24]
    DIRECTION OUTPUT ;
    USE SIGNAL ;
    PORT
      LAYER Metal3 ;
        RECT  0 995.62 0.4 996.02 ;
    END
  END sync_copile_o.csp[24]
  PIN sync_copile_o.csp[25]
    DIRECTION OUTPUT ;
    USE SIGNAL ;
    PORT
      LAYER Metal3 ;
        RECT  0 998.14 0.4 998.54 ;
    END
  END sync_copile_o.csp[25]
  PIN sync_copile_o.csp[26]
    DIRECTION OUTPUT ;
    USE SIGNAL ;
    PORT
      LAYER Metal3 ;
        RECT  0 1000.66 0.4 1001.06 ;
    END
  END sync_copile_o.csp[26]
  PIN sync_copile_o.csp[27]
    DIRECTION OUTPUT ;
    USE SIGNAL ;
    PORT
      LAYER Metal3 ;
        RECT  0 1003.18 0.4 1003.58 ;
    END
  END sync_copile_o.csp[27]
  PIN sync_copile_o.csp[28]
    DIRECTION OUTPUT ;
    USE SIGNAL ;
    PORT
      LAYER Metal3 ;
        RECT  0 1005.7 0.4 1006.1 ;
    END
  END sync_copile_o.csp[28]
  PIN sync_copile_o.csp[29]
    DIRECTION OUTPUT ;
    USE SIGNAL ;
    PORT
      LAYER Metal3 ;
        RECT  0 1008.22 0.4 1008.62 ;
    END
  END sync_copile_o.csp[29]
  PIN sync_copile_o.csp[2]
    DIRECTION OUTPUT ;
    USE SIGNAL ;
    PORT
      LAYER Metal3 ;
        RECT  0 940.18 0.4 940.58 ;
    END
  END sync_copile_o.csp[2]
  PIN sync_copile_o.csp[30]
    DIRECTION OUTPUT ;
    USE SIGNAL ;
    PORT
      LAYER Metal3 ;
        RECT  0 1010.74 0.4 1011.14 ;
    END
  END sync_copile_o.csp[30]
  PIN sync_copile_o.csp[31]
    DIRECTION OUTPUT ;
    USE SIGNAL ;
    PORT
      LAYER Metal3 ;
        RECT  0 1013.26 0.4 1013.66 ;
    END
  END sync_copile_o.csp[31]
  PIN sync_copile_o.csp[32]
    DIRECTION OUTPUT ;
    USE SIGNAL ;
    PORT
      LAYER Metal3 ;
        RECT  0 1015.78 0.4 1016.18 ;
    END
  END sync_copile_o.csp[32]
  PIN sync_copile_o.csp[33]
    DIRECTION OUTPUT ;
    USE SIGNAL ;
    PORT
      LAYER Metal3 ;
        RECT  0 1018.3 0.4 1018.7 ;
    END
  END sync_copile_o.csp[33]
  PIN sync_copile_o.csp[34]
    DIRECTION OUTPUT ;
    USE SIGNAL ;
    PORT
      LAYER Metal3 ;
        RECT  0 1020.82 0.4 1021.22 ;
    END
  END sync_copile_o.csp[34]
  PIN sync_copile_o.csp[35]
    DIRECTION OUTPUT ;
    USE SIGNAL ;
    PORT
      LAYER Metal3 ;
        RECT  0 1023.34 0.4 1023.74 ;
    END
  END sync_copile_o.csp[35]
  PIN sync_copile_o.csp[36]
    DIRECTION OUTPUT ;
    USE SIGNAL ;
    PORT
      LAYER Metal3 ;
        RECT  0 1025.86 0.4 1026.26 ;
    END
  END sync_copile_o.csp[36]
  PIN sync_copile_o.csp[37]
    DIRECTION OUTPUT ;
    USE SIGNAL ;
    PORT
      LAYER Metal3 ;
        RECT  0 1028.38 0.4 1028.78 ;
    END
  END sync_copile_o.csp[37]
  PIN sync_copile_o.csp[38]
    DIRECTION OUTPUT ;
    USE SIGNAL ;
    PORT
      LAYER Metal3 ;
        RECT  0 1030.9 0.4 1031.3 ;
    END
  END sync_copile_o.csp[38]
  PIN sync_copile_o.csp[39]
    DIRECTION OUTPUT ;
    USE SIGNAL ;
    PORT
      LAYER Metal3 ;
        RECT  0 1033.42 0.4 1033.82 ;
    END
  END sync_copile_o.csp[39]
  PIN sync_copile_o.csp[3]
    DIRECTION OUTPUT ;
    USE SIGNAL ;
    PORT
      LAYER Metal3 ;
        RECT  0 942.7 0.4 943.1 ;
    END
  END sync_copile_o.csp[3]
  PIN sync_copile_o.csp[40]
    DIRECTION OUTPUT ;
    USE SIGNAL ;
    PORT
      LAYER Metal3 ;
        RECT  0 1035.94 0.4 1036.34 ;
    END
  END sync_copile_o.csp[40]
  PIN sync_copile_o.csp[41]
    DIRECTION OUTPUT ;
    USE SIGNAL ;
    PORT
      LAYER Metal3 ;
        RECT  0 1038.46 0.4 1038.86 ;
    END
  END sync_copile_o.csp[41]
  PIN sync_copile_o.csp[42]
    DIRECTION OUTPUT ;
    USE SIGNAL ;
    PORT
      LAYER Metal3 ;
        RECT  0 1040.98 0.4 1041.38 ;
    END
  END sync_copile_o.csp[42]
  PIN sync_copile_o.csp[43]
    DIRECTION OUTPUT ;
    USE SIGNAL ;
    PORT
      LAYER Metal3 ;
        RECT  0 1043.5 0.4 1043.9 ;
    END
  END sync_copile_o.csp[43]
  PIN sync_copile_o.csp[44]
    DIRECTION OUTPUT ;
    USE SIGNAL ;
    PORT
      LAYER Metal3 ;
        RECT  0 1046.02 0.4 1046.42 ;
    END
  END sync_copile_o.csp[44]
  PIN sync_copile_o.csp[45]
    DIRECTION OUTPUT ;
    USE SIGNAL ;
    PORT
      LAYER Metal3 ;
        RECT  0 1048.54 0.4 1048.94 ;
    END
  END sync_copile_o.csp[45]
  PIN sync_copile_o.csp[46]
    DIRECTION OUTPUT ;
    USE SIGNAL ;
    PORT
      LAYER Metal3 ;
        RECT  0 1051.06 0.4 1051.46 ;
    END
  END sync_copile_o.csp[46]
  PIN sync_copile_o.csp[47]
    DIRECTION OUTPUT ;
    USE SIGNAL ;
    PORT
      LAYER Metal3 ;
        RECT  0 1053.58 0.4 1053.98 ;
    END
  END sync_copile_o.csp[47]
  PIN sync_copile_o.csp[48]
    DIRECTION OUTPUT ;
    USE SIGNAL ;
    PORT
      LAYER Metal3 ;
        RECT  0 1056.1 0.4 1056.5 ;
    END
  END sync_copile_o.csp[48]
  PIN sync_copile_o.csp[49]
    DIRECTION OUTPUT ;
    USE SIGNAL ;
    PORT
      LAYER Metal3 ;
        RECT  0 1058.62 0.4 1059.02 ;
    END
  END sync_copile_o.csp[49]
  PIN sync_copile_o.csp[4]
    DIRECTION OUTPUT ;
    USE SIGNAL ;
    PORT
      LAYER Metal3 ;
        RECT  0 945.22 0.4 945.62 ;
    END
  END sync_copile_o.csp[4]
  PIN sync_copile_o.csp[50]
    DIRECTION OUTPUT ;
    USE SIGNAL ;
    PORT
      LAYER Metal3 ;
        RECT  0 1061.14 0.4 1061.54 ;
    END
  END sync_copile_o.csp[50]
  PIN sync_copile_o.csp[51]
    DIRECTION OUTPUT ;
    USE SIGNAL ;
    PORT
      LAYER Metal3 ;
        RECT  0 1063.66 0.4 1064.06 ;
    END
  END sync_copile_o.csp[51]
  PIN sync_copile_o.csp[52]
    DIRECTION OUTPUT ;
    USE SIGNAL ;
    PORT
      LAYER Metal3 ;
        RECT  0 1066.18 0.4 1066.58 ;
    END
  END sync_copile_o.csp[52]
  PIN sync_copile_o.csp[53]
    DIRECTION OUTPUT ;
    USE SIGNAL ;
    PORT
      LAYER Metal3 ;
        RECT  0 1068.7 0.4 1069.1 ;
    END
  END sync_copile_o.csp[53]
  PIN sync_copile_o.csp[54]
    DIRECTION OUTPUT ;
    USE SIGNAL ;
    PORT
      LAYER Metal3 ;
        RECT  0 1071.22 0.4 1071.62 ;
    END
  END sync_copile_o.csp[54]
  PIN sync_copile_o.csp[55]
    DIRECTION OUTPUT ;
    USE SIGNAL ;
    PORT
      LAYER Metal3 ;
        RECT  0 1073.74 0.4 1074.14 ;
    END
  END sync_copile_o.csp[55]
  PIN sync_copile_o.csp[56]
    DIRECTION OUTPUT ;
    USE SIGNAL ;
    PORT
      LAYER Metal3 ;
        RECT  0 1076.26 0.4 1076.66 ;
    END
  END sync_copile_o.csp[56]
  PIN sync_copile_o.csp[57]
    DIRECTION OUTPUT ;
    USE SIGNAL ;
    PORT
      LAYER Metal3 ;
        RECT  0 1078.78 0.4 1079.18 ;
    END
  END sync_copile_o.csp[57]
  PIN sync_copile_o.csp[58]
    DIRECTION OUTPUT ;
    USE SIGNAL ;
    PORT
      LAYER Metal3 ;
        RECT  0 1081.3 0.4 1081.7 ;
    END
  END sync_copile_o.csp[58]
  PIN sync_copile_o.csp[59]
    DIRECTION OUTPUT ;
    USE SIGNAL ;
    PORT
      LAYER Metal3 ;
        RECT  0 1083.82 0.4 1084.22 ;
    END
  END sync_copile_o.csp[59]
  PIN sync_copile_o.csp[5]
    DIRECTION OUTPUT ;
    USE SIGNAL ;
    PORT
      LAYER Metal3 ;
        RECT  0 947.74 0.4 948.14 ;
    END
  END sync_copile_o.csp[5]
  PIN sync_copile_o.csp[60]
    DIRECTION OUTPUT ;
    USE SIGNAL ;
    PORT
      LAYER Metal3 ;
        RECT  0 1086.34 0.4 1086.74 ;
    END
  END sync_copile_o.csp[60]
  PIN sync_copile_o.csp[61]
    DIRECTION OUTPUT ;
    USE SIGNAL ;
    PORT
      LAYER Metal3 ;
        RECT  0 1088.86 0.4 1089.26 ;
    END
  END sync_copile_o.csp[61]
  PIN sync_copile_o.csp[62]
    DIRECTION OUTPUT ;
    USE SIGNAL ;
    PORT
      LAYER Metal3 ;
        RECT  0 1091.38 0.4 1091.78 ;
    END
  END sync_copile_o.csp[62]
  PIN sync_copile_o.csp[63]
    DIRECTION OUTPUT ;
    USE SIGNAL ;
    PORT
      LAYER Metal3 ;
        RECT  0 1093.9 0.4 1094.3 ;
    END
  END sync_copile_o.csp[63]
  PIN sync_copile_o.csp[6]
    DIRECTION OUTPUT ;
    USE SIGNAL ;
    PORT
      LAYER Metal3 ;
        RECT  0 950.26 0.4 950.66 ;
    END
  END sync_copile_o.csp[6]
  PIN sync_copile_o.csp[7]
    DIRECTION OUTPUT ;
    USE SIGNAL ;
    PORT
      LAYER Metal3 ;
        RECT  0 952.78 0.4 953.18 ;
    END
  END sync_copile_o.csp[7]
  PIN sync_copile_o.csp[8]
    DIRECTION OUTPUT ;
    USE SIGNAL ;
    PORT
      LAYER Metal3 ;
        RECT  0 955.3 0.4 955.7 ;
    END
  END sync_copile_o.csp[8]
  PIN sync_copile_o.csp[9]
    DIRECTION OUTPUT ;
    USE SIGNAL ;
    PORT
      LAYER Metal3 ;
        RECT  0 957.82 0.4 958.22 ;
    END
  END sync_copile_o.csp[9]
  PIN sync_copile_o.hp[0]
    DIRECTION OUTPUT ;
    USE SIGNAL ;
    PORT
      LAYER Metal3 ;
        RECT  0 935.98 0.4 936.38 ;
    END
  END sync_copile_o.hp[0]
  PIN sync_copile_o.hp[10]
    DIRECTION OUTPUT ;
    USE SIGNAL ;
    PORT
      LAYER Metal3 ;
        RECT  0 961.18 0.4 961.58 ;
    END
  END sync_copile_o.hp[10]
  PIN sync_copile_o.hp[11]
    DIRECTION OUTPUT ;
    USE SIGNAL ;
    PORT
      LAYER Metal3 ;
        RECT  0 963.7 0.4 964.1 ;
    END
  END sync_copile_o.hp[11]
  PIN sync_copile_o.hp[12]
    DIRECTION OUTPUT ;
    USE SIGNAL ;
    PORT
      LAYER Metal3 ;
        RECT  0 966.22 0.4 966.62 ;
    END
  END sync_copile_o.hp[12]
  PIN sync_copile_o.hp[13]
    DIRECTION OUTPUT ;
    USE SIGNAL ;
    PORT
      LAYER Metal3 ;
        RECT  0 968.74 0.4 969.14 ;
    END
  END sync_copile_o.hp[13]
  PIN sync_copile_o.hp[14]
    DIRECTION OUTPUT ;
    USE SIGNAL ;
    PORT
      LAYER Metal3 ;
        RECT  0 971.26 0.4 971.66 ;
    END
  END sync_copile_o.hp[14]
  PIN sync_copile_o.hp[15]
    DIRECTION OUTPUT ;
    USE SIGNAL ;
    PORT
      LAYER Metal3 ;
        RECT  0 973.78 0.4 974.18 ;
    END
  END sync_copile_o.hp[15]
  PIN sync_copile_o.hp[16]
    DIRECTION OUTPUT ;
    USE SIGNAL ;
    PORT
      LAYER Metal3 ;
        RECT  0 976.3 0.4 976.7 ;
    END
  END sync_copile_o.hp[16]
  PIN sync_copile_o.hp[17]
    DIRECTION OUTPUT ;
    USE SIGNAL ;
    PORT
      LAYER Metal3 ;
        RECT  0 978.82 0.4 979.22 ;
    END
  END sync_copile_o.hp[17]
  PIN sync_copile_o.hp[18]
    DIRECTION OUTPUT ;
    USE SIGNAL ;
    PORT
      LAYER Metal3 ;
        RECT  0 981.34 0.4 981.74 ;
    END
  END sync_copile_o.hp[18]
  PIN sync_copile_o.hp[19]
    DIRECTION OUTPUT ;
    USE SIGNAL ;
    PORT
      LAYER Metal3 ;
        RECT  0 983.86 0.4 984.26 ;
    END
  END sync_copile_o.hp[19]
  PIN sync_copile_o.hp[1]
    DIRECTION OUTPUT ;
    USE SIGNAL ;
    PORT
      LAYER Metal3 ;
        RECT  0 938.5 0.4 938.9 ;
    END
  END sync_copile_o.hp[1]
  PIN sync_copile_o.hp[20]
    DIRECTION OUTPUT ;
    USE SIGNAL ;
    PORT
      LAYER Metal3 ;
        RECT  0 986.38 0.4 986.78 ;
    END
  END sync_copile_o.hp[20]
  PIN sync_copile_o.hp[21]
    DIRECTION OUTPUT ;
    USE SIGNAL ;
    PORT
      LAYER Metal3 ;
        RECT  0 988.9 0.4 989.3 ;
    END
  END sync_copile_o.hp[21]
  PIN sync_copile_o.hp[22]
    DIRECTION OUTPUT ;
    USE SIGNAL ;
    PORT
      LAYER Metal3 ;
        RECT  0 991.42 0.4 991.82 ;
    END
  END sync_copile_o.hp[22]
  PIN sync_copile_o.hp[23]
    DIRECTION OUTPUT ;
    USE SIGNAL ;
    PORT
      LAYER Metal3 ;
        RECT  0 993.94 0.4 994.34 ;
    END
  END sync_copile_o.hp[23]
  PIN sync_copile_o.hp[24]
    DIRECTION OUTPUT ;
    USE SIGNAL ;
    PORT
      LAYER Metal3 ;
        RECT  0 996.46 0.4 996.86 ;
    END
  END sync_copile_o.hp[24]
  PIN sync_copile_o.hp[25]
    DIRECTION OUTPUT ;
    USE SIGNAL ;
    PORT
      LAYER Metal3 ;
        RECT  0 998.98 0.4 999.38 ;
    END
  END sync_copile_o.hp[25]
  PIN sync_copile_o.hp[26]
    DIRECTION OUTPUT ;
    USE SIGNAL ;
    PORT
      LAYER Metal3 ;
        RECT  0 1001.5 0.4 1001.9 ;
    END
  END sync_copile_o.hp[26]
  PIN sync_copile_o.hp[27]
    DIRECTION OUTPUT ;
    USE SIGNAL ;
    PORT
      LAYER Metal3 ;
        RECT  0 1004.02 0.4 1004.42 ;
    END
  END sync_copile_o.hp[27]
  PIN sync_copile_o.hp[28]
    DIRECTION OUTPUT ;
    USE SIGNAL ;
    PORT
      LAYER Metal3 ;
        RECT  0 1006.54 0.4 1006.94 ;
    END
  END sync_copile_o.hp[28]
  PIN sync_copile_o.hp[29]
    DIRECTION OUTPUT ;
    USE SIGNAL ;
    PORT
      LAYER Metal3 ;
        RECT  0 1009.06 0.4 1009.46 ;
    END
  END sync_copile_o.hp[29]
  PIN sync_copile_o.hp[2]
    DIRECTION OUTPUT ;
    USE SIGNAL ;
    PORT
      LAYER Metal3 ;
        RECT  0 941.02 0.4 941.42 ;
    END
  END sync_copile_o.hp[2]
  PIN sync_copile_o.hp[30]
    DIRECTION OUTPUT ;
    USE SIGNAL ;
    PORT
      LAYER Metal3 ;
        RECT  0 1011.58 0.4 1011.98 ;
    END
  END sync_copile_o.hp[30]
  PIN sync_copile_o.hp[31]
    DIRECTION OUTPUT ;
    USE SIGNAL ;
    PORT
      LAYER Metal3 ;
        RECT  0 1014.1 0.4 1014.5 ;
    END
  END sync_copile_o.hp[31]
  PIN sync_copile_o.hp[32]
    DIRECTION OUTPUT ;
    USE SIGNAL ;
    PORT
      LAYER Metal3 ;
        RECT  0 1016.62 0.4 1017.02 ;
    END
  END sync_copile_o.hp[32]
  PIN sync_copile_o.hp[33]
    DIRECTION OUTPUT ;
    USE SIGNAL ;
    PORT
      LAYER Metal3 ;
        RECT  0 1019.14 0.4 1019.54 ;
    END
  END sync_copile_o.hp[33]
  PIN sync_copile_o.hp[34]
    DIRECTION OUTPUT ;
    USE SIGNAL ;
    PORT
      LAYER Metal3 ;
        RECT  0 1021.66 0.4 1022.06 ;
    END
  END sync_copile_o.hp[34]
  PIN sync_copile_o.hp[35]
    DIRECTION OUTPUT ;
    USE SIGNAL ;
    PORT
      LAYER Metal3 ;
        RECT  0 1024.18 0.4 1024.58 ;
    END
  END sync_copile_o.hp[35]
  PIN sync_copile_o.hp[36]
    DIRECTION OUTPUT ;
    USE SIGNAL ;
    PORT
      LAYER Metal3 ;
        RECT  0 1026.7 0.4 1027.1 ;
    END
  END sync_copile_o.hp[36]
  PIN sync_copile_o.hp[37]
    DIRECTION OUTPUT ;
    USE SIGNAL ;
    PORT
      LAYER Metal3 ;
        RECT  0 1029.22 0.4 1029.62 ;
    END
  END sync_copile_o.hp[37]
  PIN sync_copile_o.hp[38]
    DIRECTION OUTPUT ;
    USE SIGNAL ;
    PORT
      LAYER Metal3 ;
        RECT  0 1031.74 0.4 1032.14 ;
    END
  END sync_copile_o.hp[38]
  PIN sync_copile_o.hp[39]
    DIRECTION OUTPUT ;
    USE SIGNAL ;
    PORT
      LAYER Metal3 ;
        RECT  0 1034.26 0.4 1034.66 ;
    END
  END sync_copile_o.hp[39]
  PIN sync_copile_o.hp[3]
    DIRECTION OUTPUT ;
    USE SIGNAL ;
    PORT
      LAYER Metal3 ;
        RECT  0 943.54 0.4 943.94 ;
    END
  END sync_copile_o.hp[3]
  PIN sync_copile_o.hp[40]
    DIRECTION OUTPUT ;
    USE SIGNAL ;
    PORT
      LAYER Metal3 ;
        RECT  0 1036.78 0.4 1037.18 ;
    END
  END sync_copile_o.hp[40]
  PIN sync_copile_o.hp[41]
    DIRECTION OUTPUT ;
    USE SIGNAL ;
    PORT
      LAYER Metal3 ;
        RECT  0 1039.3 0.4 1039.7 ;
    END
  END sync_copile_o.hp[41]
  PIN sync_copile_o.hp[42]
    DIRECTION OUTPUT ;
    USE SIGNAL ;
    PORT
      LAYER Metal3 ;
        RECT  0 1041.82 0.4 1042.22 ;
    END
  END sync_copile_o.hp[42]
  PIN sync_copile_o.hp[43]
    DIRECTION OUTPUT ;
    USE SIGNAL ;
    PORT
      LAYER Metal3 ;
        RECT  0 1044.34 0.4 1044.74 ;
    END
  END sync_copile_o.hp[43]
  PIN sync_copile_o.hp[44]
    DIRECTION OUTPUT ;
    USE SIGNAL ;
    PORT
      LAYER Metal3 ;
        RECT  0 1046.86 0.4 1047.26 ;
    END
  END sync_copile_o.hp[44]
  PIN sync_copile_o.hp[45]
    DIRECTION OUTPUT ;
    USE SIGNAL ;
    PORT
      LAYER Metal3 ;
        RECT  0 1049.38 0.4 1049.78 ;
    END
  END sync_copile_o.hp[45]
  PIN sync_copile_o.hp[46]
    DIRECTION OUTPUT ;
    USE SIGNAL ;
    PORT
      LAYER Metal3 ;
        RECT  0 1051.9 0.4 1052.3 ;
    END
  END sync_copile_o.hp[46]
  PIN sync_copile_o.hp[47]
    DIRECTION OUTPUT ;
    USE SIGNAL ;
    PORT
      LAYER Metal3 ;
        RECT  0 1054.42 0.4 1054.82 ;
    END
  END sync_copile_o.hp[47]
  PIN sync_copile_o.hp[48]
    DIRECTION OUTPUT ;
    USE SIGNAL ;
    PORT
      LAYER Metal3 ;
        RECT  0 1056.94 0.4 1057.34 ;
    END
  END sync_copile_o.hp[48]
  PIN sync_copile_o.hp[49]
    DIRECTION OUTPUT ;
    USE SIGNAL ;
    PORT
      LAYER Metal3 ;
        RECT  0 1059.46 0.4 1059.86 ;
    END
  END sync_copile_o.hp[49]
  PIN sync_copile_o.hp[4]
    DIRECTION OUTPUT ;
    USE SIGNAL ;
    PORT
      LAYER Metal3 ;
        RECT  0 946.06 0.4 946.46 ;
    END
  END sync_copile_o.hp[4]
  PIN sync_copile_o.hp[50]
    DIRECTION OUTPUT ;
    USE SIGNAL ;
    PORT
      LAYER Metal3 ;
        RECT  0 1061.98 0.4 1062.38 ;
    END
  END sync_copile_o.hp[50]
  PIN sync_copile_o.hp[51]
    DIRECTION OUTPUT ;
    USE SIGNAL ;
    PORT
      LAYER Metal3 ;
        RECT  0 1064.5 0.4 1064.9 ;
    END
  END sync_copile_o.hp[51]
  PIN sync_copile_o.hp[52]
    DIRECTION OUTPUT ;
    USE SIGNAL ;
    PORT
      LAYER Metal3 ;
        RECT  0 1067.02 0.4 1067.42 ;
    END
  END sync_copile_o.hp[52]
  PIN sync_copile_o.hp[53]
    DIRECTION OUTPUT ;
    USE SIGNAL ;
    PORT
      LAYER Metal3 ;
        RECT  0 1069.54 0.4 1069.94 ;
    END
  END sync_copile_o.hp[53]
  PIN sync_copile_o.hp[54]
    DIRECTION OUTPUT ;
    USE SIGNAL ;
    PORT
      LAYER Metal3 ;
        RECT  0 1072.06 0.4 1072.46 ;
    END
  END sync_copile_o.hp[54]
  PIN sync_copile_o.hp[55]
    DIRECTION OUTPUT ;
    USE SIGNAL ;
    PORT
      LAYER Metal3 ;
        RECT  0 1074.58 0.4 1074.98 ;
    END
  END sync_copile_o.hp[55]
  PIN sync_copile_o.hp[56]
    DIRECTION OUTPUT ;
    USE SIGNAL ;
    PORT
      LAYER Metal3 ;
        RECT  0 1077.1 0.4 1077.5 ;
    END
  END sync_copile_o.hp[56]
  PIN sync_copile_o.hp[57]
    DIRECTION OUTPUT ;
    USE SIGNAL ;
    PORT
      LAYER Metal3 ;
        RECT  0 1079.62 0.4 1080.02 ;
    END
  END sync_copile_o.hp[57]
  PIN sync_copile_o.hp[58]
    DIRECTION OUTPUT ;
    USE SIGNAL ;
    PORT
      LAYER Metal3 ;
        RECT  0 1082.14 0.4 1082.54 ;
    END
  END sync_copile_o.hp[58]
  PIN sync_copile_o.hp[59]
    DIRECTION OUTPUT ;
    USE SIGNAL ;
    PORT
      LAYER Metal3 ;
        RECT  0 1084.66 0.4 1085.06 ;
    END
  END sync_copile_o.hp[59]
  PIN sync_copile_o.hp[5]
    DIRECTION OUTPUT ;
    USE SIGNAL ;
    PORT
      LAYER Metal3 ;
        RECT  0 948.58 0.4 948.98 ;
    END
  END sync_copile_o.hp[5]
  PIN sync_copile_o.hp[60]
    DIRECTION OUTPUT ;
    USE SIGNAL ;
    PORT
      LAYER Metal3 ;
        RECT  0 1087.18 0.4 1087.58 ;
    END
  END sync_copile_o.hp[60]
  PIN sync_copile_o.hp[61]
    DIRECTION OUTPUT ;
    USE SIGNAL ;
    PORT
      LAYER Metal3 ;
        RECT  0 1089.7 0.4 1090.1 ;
    END
  END sync_copile_o.hp[61]
  PIN sync_copile_o.hp[62]
    DIRECTION OUTPUT ;
    USE SIGNAL ;
    PORT
      LAYER Metal3 ;
        RECT  0 1092.22 0.4 1092.62 ;
    END
  END sync_copile_o.hp[62]
  PIN sync_copile_o.hp[63]
    DIRECTION OUTPUT ;
    USE SIGNAL ;
    PORT
      LAYER Metal3 ;
        RECT  0 1094.74 0.4 1095.14 ;
    END
  END sync_copile_o.hp[63]
  PIN sync_copile_o.hp[6]
    DIRECTION OUTPUT ;
    USE SIGNAL ;
    PORT
      LAYER Metal3 ;
        RECT  0 951.1 0.4 951.5 ;
    END
  END sync_copile_o.hp[6]
  PIN sync_copile_o.hp[7]
    DIRECTION OUTPUT ;
    USE SIGNAL ;
    PORT
      LAYER Metal3 ;
        RECT  0 953.62 0.4 954.02 ;
    END
  END sync_copile_o.hp[7]
  PIN sync_copile_o.hp[8]
    DIRECTION OUTPUT ;
    USE SIGNAL ;
    PORT
      LAYER Metal3 ;
        RECT  0 956.14 0.4 956.54 ;
    END
  END sync_copile_o.hp[8]
  PIN sync_copile_o.hp[9]
    DIRECTION OUTPUT ;
    USE SIGNAL ;
    PORT
      LAYER Metal3 ;
        RECT  0 958.66 0.4 959.06 ;
    END
  END sync_copile_o.hp[9]
  PIN sync_copile_o.hp_valid
    DIRECTION OUTPUT ;
    USE SIGNAL ;
    PORT
      LAYER Metal3 ;
        RECT  0 933.46 0.4 933.86 ;
    END
  END sync_copile_o.hp_valid
  PIN sync_dsp_o[0]
    DIRECTION OUTPUT ;
    USE SIGNAL ;
    PORT
      LAYER Metal2 ;
        RECT  271 1749.6 271.4 1750 ;
    END
  END sync_dsp_o[0]
  PIN sync_dsp_o[10]
    DIRECTION OUTPUT ;
    USE SIGNAL ;
    PORT
      LAYER Metal2 ;
        RECT  280.6 1749.6 281 1750 ;
    END
  END sync_dsp_o[10]
  PIN sync_dsp_o[11]
    DIRECTION OUTPUT ;
    USE SIGNAL ;
    PORT
      LAYER Metal2 ;
        RECT  281.56 1749.6 281.96 1750 ;
    END
  END sync_dsp_o[11]
  PIN sync_dsp_o[12]
    DIRECTION OUTPUT ;
    USE SIGNAL ;
    PORT
      LAYER Metal2 ;
        RECT  282.52 1749.6 282.92 1750 ;
    END
  END sync_dsp_o[12]
  PIN sync_dsp_o[13]
    DIRECTION OUTPUT ;
    USE SIGNAL ;
    PORT
      LAYER Metal2 ;
        RECT  283.48 1749.6 283.88 1750 ;
    END
  END sync_dsp_o[13]
  PIN sync_dsp_o[14]
    DIRECTION OUTPUT ;
    USE SIGNAL ;
    PORT
      LAYER Metal2 ;
        RECT  284.44 1749.6 284.84 1750 ;
    END
  END sync_dsp_o[14]
  PIN sync_dsp_o[15]
    DIRECTION OUTPUT ;
    USE SIGNAL ;
    PORT
      LAYER Metal2 ;
        RECT  285.4 1749.6 285.8 1750 ;
    END
  END sync_dsp_o[15]
  PIN sync_dsp_o[16]
    DIRECTION OUTPUT ;
    USE SIGNAL ;
    PORT
      LAYER Metal2 ;
        RECT  286.36 1749.6 286.76 1750 ;
    END
  END sync_dsp_o[16]
  PIN sync_dsp_o[17]
    DIRECTION OUTPUT ;
    USE SIGNAL ;
    PORT
      LAYER Metal2 ;
        RECT  287.32 1749.6 287.72 1750 ;
    END
  END sync_dsp_o[17]
  PIN sync_dsp_o[18]
    DIRECTION OUTPUT ;
    USE SIGNAL ;
    PORT
      LAYER Metal2 ;
        RECT  288.28 1749.6 288.68 1750 ;
    END
  END sync_dsp_o[18]
  PIN sync_dsp_o[19]
    DIRECTION OUTPUT ;
    USE SIGNAL ;
    PORT
      LAYER Metal2 ;
        RECT  289.24 1749.6 289.64 1750 ;
    END
  END sync_dsp_o[19]
  PIN sync_dsp_o[1]
    DIRECTION OUTPUT ;
    USE SIGNAL ;
    PORT
      LAYER Metal2 ;
        RECT  271.96 1749.6 272.36 1750 ;
    END
  END sync_dsp_o[1]
  PIN sync_dsp_o[20]
    DIRECTION OUTPUT ;
    USE SIGNAL ;
    PORT
      LAYER Metal2 ;
        RECT  290.2 1749.6 290.6 1750 ;
    END
  END sync_dsp_o[20]
  PIN sync_dsp_o[21]
    DIRECTION OUTPUT ;
    USE SIGNAL ;
    PORT
      LAYER Metal2 ;
        RECT  291.16 1749.6 291.56 1750 ;
    END
  END sync_dsp_o[21]
  PIN sync_dsp_o[22]
    DIRECTION OUTPUT ;
    USE SIGNAL ;
    PORT
      LAYER Metal2 ;
        RECT  292.12 1749.6 292.52 1750 ;
    END
  END sync_dsp_o[22]
  PIN sync_dsp_o[23]
    DIRECTION OUTPUT ;
    USE SIGNAL ;
    PORT
      LAYER Metal2 ;
        RECT  293.08 1749.6 293.48 1750 ;
    END
  END sync_dsp_o[23]
  PIN sync_dsp_o[24]
    DIRECTION OUTPUT ;
    USE SIGNAL ;
    PORT
      LAYER Metal2 ;
        RECT  294.04 1749.6 294.44 1750 ;
    END
  END sync_dsp_o[24]
  PIN sync_dsp_o[25]
    DIRECTION OUTPUT ;
    USE SIGNAL ;
    PORT
      LAYER Metal2 ;
        RECT  295 1749.6 295.4 1750 ;
    END
  END sync_dsp_o[25]
  PIN sync_dsp_o[26]
    DIRECTION OUTPUT ;
    USE SIGNAL ;
    PORT
      LAYER Metal2 ;
        RECT  295.96 1749.6 296.36 1750 ;
    END
  END sync_dsp_o[26]
  PIN sync_dsp_o[27]
    DIRECTION OUTPUT ;
    USE SIGNAL ;
    PORT
      LAYER Metal2 ;
        RECT  296.92 1749.6 297.32 1750 ;
    END
  END sync_dsp_o[27]
  PIN sync_dsp_o[28]
    DIRECTION OUTPUT ;
    USE SIGNAL ;
    PORT
      LAYER Metal2 ;
        RECT  297.88 1749.6 298.28 1750 ;
    END
  END sync_dsp_o[28]
  PIN sync_dsp_o[29]
    DIRECTION OUTPUT ;
    USE SIGNAL ;
    PORT
      LAYER Metal2 ;
        RECT  298.84 1749.6 299.24 1750 ;
    END
  END sync_dsp_o[29]
  PIN sync_dsp_o[2]
    DIRECTION OUTPUT ;
    USE SIGNAL ;
    PORT
      LAYER Metal2 ;
        RECT  272.92 1749.6 273.32 1750 ;
    END
  END sync_dsp_o[2]
  PIN sync_dsp_o[30]
    DIRECTION OUTPUT ;
    USE SIGNAL ;
    PORT
      LAYER Metal2 ;
        RECT  299.8 1749.6 300.2 1750 ;
    END
  END sync_dsp_o[30]
  PIN sync_dsp_o[31]
    DIRECTION OUTPUT ;
    USE SIGNAL ;
    PORT
      LAYER Metal2 ;
        RECT  300.76 1749.6 301.16 1750 ;
    END
  END sync_dsp_o[31]
  PIN sync_dsp_o[3]
    DIRECTION OUTPUT ;
    USE SIGNAL ;
    PORT
      LAYER Metal2 ;
        RECT  273.88 1749.6 274.28 1750 ;
    END
  END sync_dsp_o[3]
  PIN sync_dsp_o[4]
    DIRECTION OUTPUT ;
    USE SIGNAL ;
    PORT
      LAYER Metal2 ;
        RECT  274.84 1749.6 275.24 1750 ;
    END
  END sync_dsp_o[4]
  PIN sync_dsp_o[5]
    DIRECTION OUTPUT ;
    USE SIGNAL ;
    PORT
      LAYER Metal2 ;
        RECT  275.8 1749.6 276.2 1750 ;
    END
  END sync_dsp_o[5]
  PIN sync_dsp_o[6]
    DIRECTION OUTPUT ;
    USE SIGNAL ;
    PORT
      LAYER Metal2 ;
        RECT  276.76 1749.6 277.16 1750 ;
    END
  END sync_dsp_o[6]
  PIN sync_dsp_o[7]
    DIRECTION OUTPUT ;
    USE SIGNAL ;
    PORT
      LAYER Metal2 ;
        RECT  277.72 1749.6 278.12 1750 ;
    END
  END sync_dsp_o[7]
  PIN sync_dsp_o[8]
    DIRECTION OUTPUT ;
    USE SIGNAL ;
    PORT
      LAYER Metal2 ;
        RECT  278.68 1749.6 279.08 1750 ;
    END
  END sync_dsp_o[8]
  PIN sync_dsp_o[9]
    DIRECTION OUTPUT ;
    USE SIGNAL ;
    PORT
      LAYER Metal2 ;
        RECT  279.64 1749.6 280.04 1750 ;
    END
  END sync_dsp_o[9]
  PIN sync_rsp_o[0]
    DIRECTION OUTPUT ;
    USE SIGNAL ;
    PORT
      LAYER Metal2 ;
        RECT  311.32 1749.6 311.72 1750 ;
    END
  END sync_rsp_o[0]
  PIN sync_rsp_o[10]
    DIRECTION OUTPUT ;
    USE SIGNAL ;
    PORT
      LAYER Metal2 ;
        RECT  320.92 1749.6 321.32 1750 ;
    END
  END sync_rsp_o[10]
  PIN sync_rsp_o[11]
    DIRECTION OUTPUT ;
    USE SIGNAL ;
    PORT
      LAYER Metal2 ;
        RECT  321.88 1749.6 322.28 1750 ;
    END
  END sync_rsp_o[11]
  PIN sync_rsp_o[12]
    DIRECTION OUTPUT ;
    USE SIGNAL ;
    PORT
      LAYER Metal2 ;
        RECT  322.84 1749.6 323.24 1750 ;
    END
  END sync_rsp_o[12]
  PIN sync_rsp_o[13]
    DIRECTION OUTPUT ;
    USE SIGNAL ;
    PORT
      LAYER Metal2 ;
        RECT  323.8 1749.6 324.2 1750 ;
    END
  END sync_rsp_o[13]
  PIN sync_rsp_o[14]
    DIRECTION OUTPUT ;
    USE SIGNAL ;
    PORT
      LAYER Metal2 ;
        RECT  324.76 1749.6 325.16 1750 ;
    END
  END sync_rsp_o[14]
  PIN sync_rsp_o[15]
    DIRECTION OUTPUT ;
    USE SIGNAL ;
    PORT
      LAYER Metal2 ;
        RECT  325.72 1749.6 326.12 1750 ;
    END
  END sync_rsp_o[15]
  PIN sync_rsp_o[16]
    DIRECTION OUTPUT ;
    USE SIGNAL ;
    PORT
      LAYER Metal2 ;
        RECT  326.68 1749.6 327.08 1750 ;
    END
  END sync_rsp_o[16]
  PIN sync_rsp_o[17]
    DIRECTION OUTPUT ;
    USE SIGNAL ;
    PORT
      LAYER Metal2 ;
        RECT  327.64 1749.6 328.04 1750 ;
    END
  END sync_rsp_o[17]
  PIN sync_rsp_o[18]
    DIRECTION OUTPUT ;
    USE SIGNAL ;
    PORT
      LAYER Metal2 ;
        RECT  328.6 1749.6 329 1750 ;
    END
  END sync_rsp_o[18]
  PIN sync_rsp_o[19]
    DIRECTION OUTPUT ;
    USE SIGNAL ;
    PORT
      LAYER Metal2 ;
        RECT  329.56 1749.6 329.96 1750 ;
    END
  END sync_rsp_o[19]
  PIN sync_rsp_o[1]
    DIRECTION OUTPUT ;
    USE SIGNAL ;
    PORT
      LAYER Metal2 ;
        RECT  312.28 1749.6 312.68 1750 ;
    END
  END sync_rsp_o[1]
  PIN sync_rsp_o[20]
    DIRECTION OUTPUT ;
    USE SIGNAL ;
    PORT
      LAYER Metal2 ;
        RECT  330.52 1749.6 330.92 1750 ;
    END
  END sync_rsp_o[20]
  PIN sync_rsp_o[21]
    DIRECTION OUTPUT ;
    USE SIGNAL ;
    PORT
      LAYER Metal2 ;
        RECT  331.48 1749.6 331.88 1750 ;
    END
  END sync_rsp_o[21]
  PIN sync_rsp_o[22]
    DIRECTION OUTPUT ;
    USE SIGNAL ;
    PORT
      LAYER Metal2 ;
        RECT  332.44 1749.6 332.84 1750 ;
    END
  END sync_rsp_o[22]
  PIN sync_rsp_o[23]
    DIRECTION OUTPUT ;
    USE SIGNAL ;
    PORT
      LAYER Metal2 ;
        RECT  333.4 1749.6 333.8 1750 ;
    END
  END sync_rsp_o[23]
  PIN sync_rsp_o[24]
    DIRECTION OUTPUT ;
    USE SIGNAL ;
    PORT
      LAYER Metal2 ;
        RECT  334.36 1749.6 334.76 1750 ;
    END
  END sync_rsp_o[24]
  PIN sync_rsp_o[25]
    DIRECTION OUTPUT ;
    USE SIGNAL ;
    PORT
      LAYER Metal2 ;
        RECT  335.32 1749.6 335.72 1750 ;
    END
  END sync_rsp_o[25]
  PIN sync_rsp_o[26]
    DIRECTION OUTPUT ;
    USE SIGNAL ;
    PORT
      LAYER Metal2 ;
        RECT  336.28 1749.6 336.68 1750 ;
    END
  END sync_rsp_o[26]
  PIN sync_rsp_o[27]
    DIRECTION OUTPUT ;
    USE SIGNAL ;
    PORT
      LAYER Metal2 ;
        RECT  337.24 1749.6 337.64 1750 ;
    END
  END sync_rsp_o[27]
  PIN sync_rsp_o[28]
    DIRECTION OUTPUT ;
    USE SIGNAL ;
    PORT
      LAYER Metal2 ;
        RECT  338.2 1749.6 338.6 1750 ;
    END
  END sync_rsp_o[28]
  PIN sync_rsp_o[29]
    DIRECTION OUTPUT ;
    USE SIGNAL ;
    PORT
      LAYER Metal2 ;
        RECT  339.16 1749.6 339.56 1750 ;
    END
  END sync_rsp_o[29]
  PIN sync_rsp_o[2]
    DIRECTION OUTPUT ;
    USE SIGNAL ;
    PORT
      LAYER Metal2 ;
        RECT  313.24 1749.6 313.64 1750 ;
    END
  END sync_rsp_o[2]
  PIN sync_rsp_o[30]
    DIRECTION OUTPUT ;
    USE SIGNAL ;
    PORT
      LAYER Metal2 ;
        RECT  340.12 1749.6 340.52 1750 ;
    END
  END sync_rsp_o[30]
  PIN sync_rsp_o[31]
    DIRECTION OUTPUT ;
    USE SIGNAL ;
    PORT
      LAYER Metal2 ;
        RECT  341.08 1749.6 341.48 1750 ;
    END
  END sync_rsp_o[31]
  PIN sync_rsp_o[3]
    DIRECTION OUTPUT ;
    USE SIGNAL ;
    PORT
      LAYER Metal2 ;
        RECT  314.2 1749.6 314.6 1750 ;
    END
  END sync_rsp_o[3]
  PIN sync_rsp_o[4]
    DIRECTION OUTPUT ;
    USE SIGNAL ;
    PORT
      LAYER Metal2 ;
        RECT  315.16 1749.6 315.56 1750 ;
    END
  END sync_rsp_o[4]
  PIN sync_rsp_o[5]
    DIRECTION OUTPUT ;
    USE SIGNAL ;
    PORT
      LAYER Metal2 ;
        RECT  316.12 1749.6 316.52 1750 ;
    END
  END sync_rsp_o[5]
  PIN sync_rsp_o[6]
    DIRECTION OUTPUT ;
    USE SIGNAL ;
    PORT
      LAYER Metal2 ;
        RECT  317.08 1749.6 317.48 1750 ;
    END
  END sync_rsp_o[6]
  PIN sync_rsp_o[7]
    DIRECTION OUTPUT ;
    USE SIGNAL ;
    PORT
      LAYER Metal2 ;
        RECT  318.04 1749.6 318.44 1750 ;
    END
  END sync_rsp_o[7]
  PIN sync_rsp_o[8]
    DIRECTION OUTPUT ;
    USE SIGNAL ;
    PORT
      LAYER Metal2 ;
        RECT  319 1749.6 319.4 1750 ;
    END
  END sync_rsp_o[8]
  PIN sync_rsp_o[9]
    DIRECTION OUTPUT ;
    USE SIGNAL ;
    PORT
      LAYER Metal2 ;
        RECT  319.96 1749.6 320.36 1750 ;
    END
  END sync_rsp_o[9]
  PIN sync_valid_o
    DIRECTION OUTPUT ;
    USE SIGNAL ;
    PORT
      LAYER Metal3 ;
        RECT  0 1719.7 0.4 1720.1 ;
    END
  END sync_valid_o
  PIN system_hold_o
    DIRECTION OUTPUT ;
    USE SIGNAL ;
    PORT
      LAYER Metal2 ;
        RECT  526.36 1749.6 526.76 1750 ;
    END
  END system_hold_o
  PIN VPWR
    DIRECTION INOUT ;
    USE POWER ;
    PORT
      LAYER TopMetal1 ;
        RECT  5.76 1724.12 694.08 1726.12 ;
        RECT  5.76 1674.12 694.08 1676.12 ;
        RECT  5.76 1624.12 694.08 1626.12 ;
        RECT  5.76 1574.12 694.08 1576.12 ;
        RECT  5.76 1524.12 694.08 1526.12 ;
        RECT  5.76 1474.12 694.08 1476.12 ;
        RECT  5.76 1424.12 694.08 1426.12 ;
        RECT  5.76 1374.12 694.08 1376.12 ;
        RECT  5.76 1324.12 694.08 1326.12 ;
        RECT  5.76 1274.12 694.08 1276.12 ;
        RECT  5.76 1224.12 694.08 1226.12 ;
        RECT  5.76 1174.12 694.08 1176.12 ;
        RECT  5.76 1124.12 694.08 1126.12 ;
        RECT  5.76 1074.12 694.08 1076.12 ;
        RECT  5.76 1024.12 694.08 1026.12 ;
        RECT  5.76 974.12 694.08 976.12 ;
        RECT  5.76 924.12 694.08 926.12 ;
        RECT  5.76 874.12 694.08 876.12 ;
        RECT  5.76 824.12 694.08 826.12 ;
        RECT  5.76 774.12 694.08 776.12 ;
        RECT  5.76 724.12 694.08 726.12 ;
        RECT  5.76 674.12 694.08 676.12 ;
        RECT  5.76 624.12 694.08 626.12 ;
        RECT  5.76 574.12 694.08 576.12 ;
        RECT  5.76 524.12 694.08 526.12 ;
        RECT  5.76 474.12 694.08 476.12 ;
        RECT  5.76 424.12 694.08 426.12 ;
        RECT  5.76 374.12 694.08 376.12 ;
        RECT  5.76 324.12 694.08 326.12 ;
        RECT  5.76 274.12 694.08 276.12 ;
        RECT  5.76 224.12 694.08 226.12 ;
        RECT  5.76 174.12 694.08 176.12 ;
        RECT  5.76 124.12 694.08 126.12 ;
        RECT  5.76 74.12 694.08 76.12 ;
        RECT  5.76 24.12 694.08 26.12 ;
      LAYER Metal4 ;
        RECT  665.26 14.9 666.26 1731.46 ;
        RECT  615.26 14.9 616.26 1731.46 ;
        RECT  565.26 14.9 566.26 1731.46 ;
        RECT  515.26 14.9 516.26 1731.46 ;
        RECT  465.26 14.9 466.26 1731.46 ;
        RECT  415.26 14.9 416.26 1731.46 ;
        RECT  365.26 14.9 366.26 1731.46 ;
        RECT  315.26 14.9 316.26 1731.46 ;
        RECT  265.26 14.9 266.26 1731.46 ;
        RECT  215.26 14.9 216.26 1731.46 ;
        RECT  165.26 14.9 166.26 1731.46 ;
        RECT  115.26 14.9 116.26 1731.46 ;
        RECT  65.26 14.9 66.26 1731.46 ;
        RECT  15.26 14.9 16.26 1731.46 ;
    END
  END VPWR
  PIN VGND
    DIRECTION INOUT ;
    USE GROUND ;
    PORT
      LAYER TopMetal1 ;
        RECT  5.76 1730.12 694.08 1732.12 ;
        RECT  5.76 1680.12 694.08 1682.12 ;
        RECT  5.76 1630.12 694.08 1632.12 ;
        RECT  5.76 1580.12 694.08 1582.12 ;
        RECT  5.76 1530.12 694.08 1532.12 ;
        RECT  5.76 1480.12 694.08 1482.12 ;
        RECT  5.76 1430.12 694.08 1432.12 ;
        RECT  5.76 1380.12 694.08 1382.12 ;
        RECT  5.76 1330.12 694.08 1332.12 ;
        RECT  5.76 1280.12 694.08 1282.12 ;
        RECT  5.76 1230.12 694.08 1232.12 ;
        RECT  5.76 1180.12 694.08 1182.12 ;
        RECT  5.76 1130.12 694.08 1132.12 ;
        RECT  5.76 1080.12 694.08 1082.12 ;
        RECT  5.76 1030.12 694.08 1032.12 ;
        RECT  5.76 980.12 694.08 982.12 ;
        RECT  5.76 930.12 694.08 932.12 ;
        RECT  5.76 880.12 694.08 882.12 ;
        RECT  5.76 830.12 694.08 832.12 ;
        RECT  5.76 780.12 694.08 782.12 ;
        RECT  5.76 730.12 694.08 732.12 ;
        RECT  5.76 680.12 694.08 682.12 ;
        RECT  5.76 630.12 694.08 632.12 ;
        RECT  5.76 580.12 694.08 582.12 ;
        RECT  5.76 530.12 694.08 532.12 ;
        RECT  5.76 480.12 694.08 482.12 ;
        RECT  5.76 430.12 694.08 432.12 ;
        RECT  5.76 380.12 694.08 382.12 ;
        RECT  5.76 330.12 694.08 332.12 ;
        RECT  5.76 280.12 694.08 282.12 ;
        RECT  5.76 230.12 694.08 232.12 ;
        RECT  5.76 180.12 694.08 182.12 ;
        RECT  5.76 130.12 694.08 132.12 ;
        RECT  5.76 80.12 694.08 82.12 ;
        RECT  5.76 30.12 694.08 32.12 ;
      LAYER Metal4 ;
        RECT  668.26 14.9 669.26 1732.12 ;
        RECT  618.26 14.9 619.26 1732.12 ;
        RECT  568.26 14.9 569.26 1732.12 ;
        RECT  518.26 14.9 519.26 1732.12 ;
        RECT  468.26 14.9 469.26 1732.12 ;
        RECT  418.26 14.9 419.26 1732.12 ;
        RECT  368.26 14.9 369.26 1732.12 ;
        RECT  318.26 14.9 319.26 1732.12 ;
        RECT  268.26 14.9 269.26 1732.12 ;
        RECT  218.26 14.9 219.26 1732.12 ;
        RECT  168.26 14.9 169.26 1732.12 ;
        RECT  118.26 14.9 119.26 1732.12 ;
        RECT  68.26 14.9 69.26 1732.12 ;
        RECT  18.26 14.9 19.26 1732.12 ;
    END
  END VGND
  OBS
    LAYER Metal1 ;
     RECT  0 0 698.545 1750 ;
    LAYER Metal2 ;
     RECT  0 0 698.545 1750 ;
    LAYER Metal3 ;
     RECT  0 0 698.545 1750 ;
    LAYER Metal4 ;
     RECT  0 0 698.545 1750 ;
    LAYER TopMetal1 ;
     RECT  0 0 698.545 1750 ;
  END
END ino_system
END LIBRARY
